VERSION 5.8 ;
BUSBITCHARS "[]" ;
DIVIDERCHAR "/" ;
UNITS
    DATABASE MICRONS 1000 ;
END UNITS

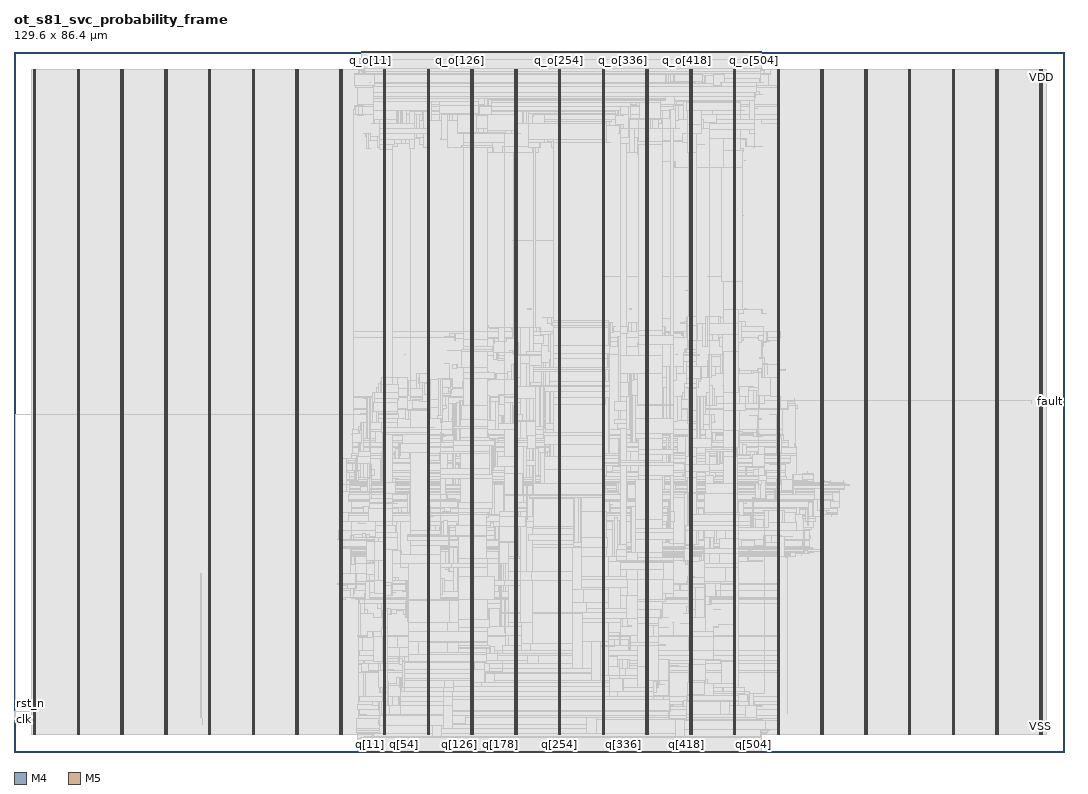
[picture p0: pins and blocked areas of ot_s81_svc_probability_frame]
MACRO ot_s81_svc_probability_frame
  FOREIGN ot_s81_svc_probability_frame 0 0 ;
  CLASS BLOCK ;
  SIZE 129.6 BY 86.4 ;
  PIN clk
    DIRECTION INPUT ;
    USE SIGNAL ;
    PORT
      LAYER M4 ;
        RECT  0 4.032 0.084 4.056 ;
    END
  END clk
  PIN fault
    DIRECTION OUTPUT ;
    USE SIGNAL ;
    PORT
      LAYER M4 ;
        RECT  129.516 43.2 129.6 43.224 ;
    END
    PORT
      LAYER M4 ;
        RECT  128.797 43.2 129.564 43.224 ;
    END
  END fault
  PIN q[0]
    DIRECTION INPUT ;
    USE SIGNAL ;
    PORT
      LAYER M5 ;
        RECT  42.912 0 42.936 0.084 ;
    END
  END q[0]
  PIN q[100]
    DIRECTION INPUT ;
    USE SIGNAL ;
    PORT
      LAYER M5 ;
        RECT  52.512 0 52.536 0.084 ;
    END
  END q[100]
  PIN q[101]
    DIRECTION INPUT ;
    USE SIGNAL ;
    PORT
      LAYER M5 ;
        RECT  52.608 0 52.632 0.084 ;
    END
  END q[101]
  PIN q[102]
    DIRECTION INPUT ;
    USE SIGNAL ;
    PORT
      LAYER M5 ;
        RECT  52.704 0 52.728 0.084 ;
    END
  END q[102]
  PIN q[103]
    DIRECTION INPUT ;
    USE SIGNAL ;
    PORT
      LAYER M5 ;
        RECT  52.8 0 52.824 0.084 ;
    END
  END q[103]
  PIN q[104]
    DIRECTION INPUT ;
    USE SIGNAL ;
    PORT
      LAYER M5 ;
        RECT  52.896 0 52.92 0.084 ;
    END
  END q[104]
  PIN q[105]
    DIRECTION INPUT ;
    USE SIGNAL ;
    PORT
      LAYER M5 ;
        RECT  52.992 0 53.016 0.084 ;
    END
  END q[105]
  PIN q[106]
    DIRECTION INPUT ;
    USE SIGNAL ;
    PORT
      LAYER M5 ;
        RECT  53.088 0 53.112 0.084 ;
    END
  END q[106]
  PIN q[107]
    DIRECTION INPUT ;
    USE SIGNAL ;
    PORT
      LAYER M5 ;
        RECT  53.184 0 53.208 0.084 ;
    END
  END q[107]
  PIN q[108]
    DIRECTION INPUT ;
    USE SIGNAL ;
    PORT
      LAYER M5 ;
        RECT  53.28 0 53.304 0.084 ;
    END
  END q[108]
  PIN q[109]
    DIRECTION INPUT ;
    USE SIGNAL ;
    PORT
      LAYER M5 ;
        RECT  53.376 0 53.4 0.084 ;
    END
  END q[109]
  PIN q[10]
    DIRECTION INPUT ;
    USE SIGNAL ;
    PORT
      LAYER M5 ;
        RECT  43.872 0 43.896 0.084 ;
    END
  END q[10]
  PIN q[110]
    DIRECTION INPUT ;
    USE SIGNAL ;
    PORT
      LAYER M5 ;
        RECT  53.472 0 53.496 0.084 ;
    END
  END q[110]
  PIN q[111]
    DIRECTION INPUT ;
    USE SIGNAL ;
    PORT
      LAYER M5 ;
        RECT  53.568 0 53.592 0.084 ;
    END
  END q[111]
  PIN q[112]
    DIRECTION INPUT ;
    USE SIGNAL ;
    PORT
      LAYER M5 ;
        RECT  53.664 0 53.688 0.084 ;
    END
  END q[112]
  PIN q[113]
    DIRECTION INPUT ;
    USE SIGNAL ;
    PORT
      LAYER M5 ;
        RECT  53.76 0 53.784 0.084 ;
    END
  END q[113]
  PIN q[114]
    DIRECTION INPUT ;
    USE SIGNAL ;
    PORT
      LAYER M5 ;
        RECT  53.856 0 53.88 0.084 ;
    END
  END q[114]
  PIN q[115]
    DIRECTION INPUT ;
    USE SIGNAL ;
    PORT
      LAYER M5 ;
        RECT  53.952 0 53.976 0.084 ;
    END
  END q[115]
  PIN q[116]
    DIRECTION INPUT ;
    USE SIGNAL ;
    PORT
      LAYER M5 ;
        RECT  54.048 0 54.072 0.084 ;
    END
  END q[116]
  PIN q[117]
    DIRECTION INPUT ;
    USE SIGNAL ;
    PORT
      LAYER M5 ;
        RECT  54.144 0 54.168 0.084 ;
    END
  END q[117]
  PIN q[118]
    DIRECTION INPUT ;
    USE SIGNAL ;
    PORT
      LAYER M5 ;
        RECT  54.24 0 54.264 0.084 ;
    END
  END q[118]
  PIN q[119]
    DIRECTION INPUT ;
    USE SIGNAL ;
    PORT
      LAYER M5 ;
        RECT  54.336 0 54.36 0.084 ;
    END
  END q[119]
  PIN q[11]
    DIRECTION INPUT ;
    USE SIGNAL ;
    PORT
      LAYER M5 ;
        RECT  43.968 0 43.992 0.084 ;
    END
  END q[11]
  PIN q[120]
    DIRECTION INPUT ;
    USE SIGNAL ;
    PORT
      LAYER M5 ;
        RECT  54.432 0 54.456 0.084 ;
    END
  END q[120]
  PIN q[121]
    DIRECTION INPUT ;
    USE SIGNAL ;
    PORT
      LAYER M5 ;
        RECT  54.528 0 54.552 0.084 ;
    END
  END q[121]
  PIN q[122]
    DIRECTION INPUT ;
    USE SIGNAL ;
    PORT
      LAYER M5 ;
        RECT  54.624 0 54.648 0.084 ;
    END
  END q[122]
  PIN q[123]
    DIRECTION INPUT ;
    USE SIGNAL ;
    PORT
      LAYER M5 ;
        RECT  54.72 0 54.744 0.084 ;
    END
  END q[123]
  PIN q[124]
    DIRECTION INPUT ;
    USE SIGNAL ;
    PORT
      LAYER M5 ;
        RECT  54.816 0 54.84 0.084 ;
    END
  END q[124]
  PIN q[125]
    DIRECTION INPUT ;
    USE SIGNAL ;
    PORT
      LAYER M5 ;
        RECT  54.912 0 54.936 0.084 ;
    END
  END q[125]
  PIN q[126]
    DIRECTION INPUT ;
    USE SIGNAL ;
    PORT
      LAYER M5 ;
        RECT  55.008 0 55.032 0.084 ;
    END
  END q[126]
  PIN q[127]
    DIRECTION INPUT ;
    USE SIGNAL ;
    PORT
      LAYER M5 ;
        RECT  55.104 0 55.128 0.084 ;
    END
  END q[127]
  PIN q[128]
    DIRECTION INPUT ;
    USE SIGNAL ;
    PORT
      LAYER M5 ;
        RECT  55.2 0 55.224 0.084 ;
    END
  END q[128]
  PIN q[129]
    DIRECTION INPUT ;
    USE SIGNAL ;
    PORT
      LAYER M5 ;
        RECT  55.296 0 55.32 0.084 ;
    END
  END q[129]
  PIN q[12]
    DIRECTION INPUT ;
    USE SIGNAL ;
    PORT
      LAYER M5 ;
        RECT  44.064 0 44.088 0.084 ;
    END
  END q[12]
  PIN q[130]
    DIRECTION INPUT ;
    USE SIGNAL ;
    PORT
      LAYER M5 ;
        RECT  55.392 0 55.416 0.084 ;
    END
  END q[130]
  PIN q[131]
    DIRECTION INPUT ;
    USE SIGNAL ;
    PORT
      LAYER M5 ;
        RECT  55.488 0 55.512 0.084 ;
    END
  END q[131]
  PIN q[132]
    DIRECTION INPUT ;
    USE SIGNAL ;
    PORT
      LAYER M5 ;
        RECT  55.584 0 55.608 0.084 ;
    END
  END q[132]
  PIN q[133]
    DIRECTION INPUT ;
    USE SIGNAL ;
    PORT
      LAYER M5 ;
        RECT  55.68 0 55.704 0.084 ;
    END
  END q[133]
  PIN q[134]
    DIRECTION INPUT ;
    USE SIGNAL ;
    PORT
      LAYER M5 ;
        RECT  55.776 0 55.8 0.084 ;
    END
  END q[134]
  PIN q[135]
    DIRECTION INPUT ;
    USE SIGNAL ;
    PORT
      LAYER M5 ;
        RECT  55.872 0 55.896 0.084 ;
    END
  END q[135]
  PIN q[136]
    DIRECTION INPUT ;
    USE SIGNAL ;
    PORT
      LAYER M5 ;
        RECT  55.968 0 55.992 0.084 ;
    END
  END q[136]
  PIN q[137]
    DIRECTION INPUT ;
    USE SIGNAL ;
    PORT
      LAYER M5 ;
        RECT  56.064 0 56.088 0.084 ;
    END
  END q[137]
  PIN q[138]
    DIRECTION INPUT ;
    USE SIGNAL ;
    PORT
      LAYER M5 ;
        RECT  56.16 0 56.184 0.084 ;
    END
  END q[138]
  PIN q[139]
    DIRECTION INPUT ;
    USE SIGNAL ;
    PORT
      LAYER M5 ;
        RECT  56.256 0 56.28 0.084 ;
    END
  END q[139]
  PIN q[13]
    DIRECTION INPUT ;
    USE SIGNAL ;
    PORT
      LAYER M5 ;
        RECT  44.16 0 44.184 0.084 ;
    END
  END q[13]
  PIN q[140]
    DIRECTION INPUT ;
    USE SIGNAL ;
    PORT
      LAYER M5 ;
        RECT  56.352 0 56.376 0.084 ;
    END
  END q[140]
  PIN q[141]
    DIRECTION INPUT ;
    USE SIGNAL ;
    PORT
      LAYER M5 ;
        RECT  56.448 0 56.472 0.084 ;
    END
  END q[141]
  PIN q[142]
    DIRECTION INPUT ;
    USE SIGNAL ;
    PORT
      LAYER M5 ;
        RECT  56.544 0 56.568 0.084 ;
    END
  END q[142]
  PIN q[143]
    DIRECTION INPUT ;
    USE SIGNAL ;
    PORT
      LAYER M5 ;
        RECT  56.64 0 56.664 0.084 ;
    END
  END q[143]
  PIN q[144]
    DIRECTION INPUT ;
    USE SIGNAL ;
    PORT
      LAYER M5 ;
        RECT  56.736 0 56.76 0.084 ;
    END
  END q[144]
  PIN q[145]
    DIRECTION INPUT ;
    USE SIGNAL ;
    PORT
      LAYER M5 ;
        RECT  56.832 0 56.856 0.084 ;
    END
  END q[145]
  PIN q[146]
    DIRECTION INPUT ;
    USE SIGNAL ;
    PORT
      LAYER M5 ;
        RECT  56.928 0 56.952 0.084 ;
    END
  END q[146]
  PIN q[147]
    DIRECTION INPUT ;
    USE SIGNAL ;
    PORT
      LAYER M5 ;
        RECT  57.024 0 57.048 0.084 ;
    END
  END q[147]
  PIN q[148]
    DIRECTION INPUT ;
    USE SIGNAL ;
    PORT
      LAYER M5 ;
        RECT  57.12 0 57.144 0.084 ;
    END
  END q[148]
  PIN q[149]
    DIRECTION INPUT ;
    USE SIGNAL ;
    PORT
      LAYER M5 ;
        RECT  57.216 0 57.24 0.084 ;
    END
  END q[149]
  PIN q[14]
    DIRECTION INPUT ;
    USE SIGNAL ;
    PORT
      LAYER M5 ;
        RECT  44.256 0 44.28 0.084 ;
    END
  END q[14]
  PIN q[150]
    DIRECTION INPUT ;
    USE SIGNAL ;
    PORT
      LAYER M5 ;
        RECT  57.312 0 57.336 0.084 ;
    END
  END q[150]
  PIN q[151]
    DIRECTION INPUT ;
    USE SIGNAL ;
    PORT
      LAYER M5 ;
        RECT  57.408 0 57.432 0.084 ;
    END
  END q[151]
  PIN q[152]
    DIRECTION INPUT ;
    USE SIGNAL ;
    PORT
      LAYER M5 ;
        RECT  57.504 0 57.528 0.084 ;
    END
  END q[152]
  PIN q[153]
    DIRECTION INPUT ;
    USE SIGNAL ;
    PORT
      LAYER M5 ;
        RECT  57.6 0 57.624 0.084 ;
    END
  END q[153]
  PIN q[154]
    DIRECTION INPUT ;
    USE SIGNAL ;
    PORT
      LAYER M5 ;
        RECT  57.696 0 57.72 0.084 ;
    END
  END q[154]
  PIN q[155]
    DIRECTION INPUT ;
    USE SIGNAL ;
    PORT
      LAYER M5 ;
        RECT  57.792 0 57.816 0.084 ;
    END
  END q[155]
  PIN q[156]
    DIRECTION INPUT ;
    USE SIGNAL ;
    PORT
      LAYER M5 ;
        RECT  57.888 0 57.912 0.084 ;
    END
  END q[156]
  PIN q[157]
    DIRECTION INPUT ;
    USE SIGNAL ;
    PORT
      LAYER M5 ;
        RECT  57.984 0 58.008 0.084 ;
    END
  END q[157]
  PIN q[158]
    DIRECTION INPUT ;
    USE SIGNAL ;
    PORT
      LAYER M5 ;
        RECT  58.08 0 58.104 0.084 ;
    END
  END q[158]
  PIN q[159]
    DIRECTION INPUT ;
    USE SIGNAL ;
    PORT
      LAYER M5 ;
        RECT  58.176 0 58.2 0.084 ;
    END
  END q[159]
  PIN q[15]
    DIRECTION INPUT ;
    USE SIGNAL ;
    PORT
      LAYER M5 ;
        RECT  44.352 0 44.376 0.084 ;
    END
  END q[15]
  PIN q[160]
    DIRECTION INPUT ;
    USE SIGNAL ;
    PORT
      LAYER M5 ;
        RECT  58.272 0 58.296 0.084 ;
    END
  END q[160]
  PIN q[161]
    DIRECTION INPUT ;
    USE SIGNAL ;
    PORT
      LAYER M5 ;
        RECT  58.368 0 58.392 0.084 ;
    END
  END q[161]
  PIN q[162]
    DIRECTION INPUT ;
    USE SIGNAL ;
    PORT
      LAYER M5 ;
        RECT  58.464 0 58.488 0.084 ;
    END
  END q[162]
  PIN q[163]
    DIRECTION INPUT ;
    USE SIGNAL ;
    PORT
      LAYER M5 ;
        RECT  58.56 0 58.584 0.084 ;
    END
  END q[163]
  PIN q[164]
    DIRECTION INPUT ;
    USE SIGNAL ;
    PORT
      LAYER M5 ;
        RECT  58.656 0 58.68 0.084 ;
    END
  END q[164]
  PIN q[165]
    DIRECTION INPUT ;
    USE SIGNAL ;
    PORT
      LAYER M5 ;
        RECT  58.752 0 58.776 0.084 ;
    END
  END q[165]
  PIN q[166]
    DIRECTION INPUT ;
    USE SIGNAL ;
    PORT
      LAYER M5 ;
        RECT  58.848 0 58.872 0.084 ;
    END
  END q[166]
  PIN q[167]
    DIRECTION INPUT ;
    USE SIGNAL ;
    PORT
      LAYER M5 ;
        RECT  58.944 0 58.968 0.084 ;
    END
  END q[167]
  PIN q[168]
    DIRECTION INPUT ;
    USE SIGNAL ;
    PORT
      LAYER M5 ;
        RECT  59.04 0 59.064 0.084 ;
    END
  END q[168]
  PIN q[169]
    DIRECTION INPUT ;
    USE SIGNAL ;
    PORT
      LAYER M5 ;
        RECT  59.136 0 59.16 0.084 ;
    END
  END q[169]
  PIN q[16]
    DIRECTION INPUT ;
    USE SIGNAL ;
    PORT
      LAYER M5 ;
        RECT  44.448 0 44.472 0.084 ;
    END
  END q[16]
  PIN q[170]
    DIRECTION INPUT ;
    USE SIGNAL ;
    PORT
      LAYER M5 ;
        RECT  59.232 0 59.256 0.084 ;
    END
  END q[170]
  PIN q[171]
    DIRECTION INPUT ;
    USE SIGNAL ;
    PORT
      LAYER M5 ;
        RECT  59.328 0 59.352 0.084 ;
    END
  END q[171]
  PIN q[172]
    DIRECTION INPUT ;
    USE SIGNAL ;
    PORT
      LAYER M5 ;
        RECT  59.424 0 59.448 0.084 ;
    END
  END q[172]
  PIN q[173]
    DIRECTION INPUT ;
    USE SIGNAL ;
    PORT
      LAYER M5 ;
        RECT  59.52 0 59.544 0.084 ;
    END
  END q[173]
  PIN q[174]
    DIRECTION INPUT ;
    USE SIGNAL ;
    PORT
      LAYER M5 ;
        RECT  59.616 0 59.64 0.084 ;
    END
  END q[174]
  PIN q[175]
    DIRECTION INPUT ;
    USE SIGNAL ;
    PORT
      LAYER M5 ;
        RECT  59.712 0 59.736 0.084 ;
    END
  END q[175]
  PIN q[176]
    DIRECTION INPUT ;
    USE SIGNAL ;
    PORT
      LAYER M5 ;
        RECT  59.808 0 59.832 0.084 ;
    END
  END q[176]
  PIN q[177]
    DIRECTION INPUT ;
    USE SIGNAL ;
    PORT
      LAYER M5 ;
        RECT  59.904 0 59.928 0.084 ;
    END
  END q[177]
  PIN q[178]
    DIRECTION INPUT ;
    USE SIGNAL ;
    PORT
      LAYER M5 ;
        RECT  60 0 60.024 0.084 ;
    END
  END q[178]
  PIN q[179]
    DIRECTION INPUT ;
    USE SIGNAL ;
    PORT
      LAYER M5 ;
        RECT  60.096 0 60.12 0.084 ;
    END
  END q[179]
  PIN q[17]
    DIRECTION INPUT ;
    USE SIGNAL ;
    PORT
      LAYER M5 ;
        RECT  44.544 0 44.568 0.084 ;
    END
  END q[17]
  PIN q[180]
    DIRECTION INPUT ;
    USE SIGNAL ;
    PORT
      LAYER M5 ;
        RECT  60.192 0 60.216 0.084 ;
    END
  END q[180]
  PIN q[181]
    DIRECTION INPUT ;
    USE SIGNAL ;
    PORT
      LAYER M5 ;
        RECT  60.288 0 60.312 0.084 ;
    END
  END q[181]
  PIN q[182]
    DIRECTION INPUT ;
    USE SIGNAL ;
    PORT
      LAYER M5 ;
        RECT  60.384 0 60.408 0.084 ;
    END
  END q[182]
  PIN q[183]
    DIRECTION INPUT ;
    USE SIGNAL ;
    PORT
      LAYER M5 ;
        RECT  60.48 0 60.504 0.084 ;
    END
  END q[183]
  PIN q[184]
    DIRECTION INPUT ;
    USE SIGNAL ;
    PORT
      LAYER M5 ;
        RECT  60.576 0 60.6 0.084 ;
    END
  END q[184]
  PIN q[185]
    DIRECTION INPUT ;
    USE SIGNAL ;
    PORT
      LAYER M5 ;
        RECT  60.672 0 60.696 0.084 ;
    END
  END q[185]
  PIN q[186]
    DIRECTION INPUT ;
    USE SIGNAL ;
    PORT
      LAYER M5 ;
        RECT  60.768 0 60.792 0.084 ;
    END
  END q[186]
  PIN q[187]
    DIRECTION INPUT ;
    USE SIGNAL ;
    PORT
      LAYER M5 ;
        RECT  60.864 0 60.888 0.084 ;
    END
  END q[187]
  PIN q[188]
    DIRECTION INPUT ;
    USE SIGNAL ;
    PORT
      LAYER M5 ;
        RECT  60.96 0 60.984 0.084 ;
    END
  END q[188]
  PIN q[189]
    DIRECTION INPUT ;
    USE SIGNAL ;
    PORT
      LAYER M5 ;
        RECT  61.056 0 61.08 0.084 ;
    END
  END q[189]
  PIN q[18]
    DIRECTION INPUT ;
    USE SIGNAL ;
    PORT
      LAYER M5 ;
        RECT  44.64 0 44.664 0.084 ;
    END
  END q[18]
  PIN q[190]
    DIRECTION INPUT ;
    USE SIGNAL ;
    PORT
      LAYER M5 ;
        RECT  61.152 0 61.176 0.084 ;
    END
  END q[190]
  PIN q[191]
    DIRECTION INPUT ;
    USE SIGNAL ;
    PORT
      LAYER M5 ;
        RECT  61.248 0 61.272 0.084 ;
    END
  END q[191]
  PIN q[192]
    DIRECTION INPUT ;
    USE SIGNAL ;
    PORT
      LAYER M5 ;
        RECT  61.344 0 61.368 0.084 ;
    END
  END q[192]
  PIN q[193]
    DIRECTION INPUT ;
    USE SIGNAL ;
    PORT
      LAYER M5 ;
        RECT  61.44 0 61.464 0.084 ;
    END
  END q[193]
  PIN q[194]
    DIRECTION INPUT ;
    USE SIGNAL ;
    PORT
      LAYER M5 ;
        RECT  61.536 0 61.56 0.084 ;
    END
  END q[194]
  PIN q[195]
    DIRECTION INPUT ;
    USE SIGNAL ;
    PORT
      LAYER M5 ;
        RECT  61.632 0 61.656 0.084 ;
    END
  END q[195]
  PIN q[196]
    DIRECTION INPUT ;
    USE SIGNAL ;
    PORT
      LAYER M5 ;
        RECT  61.728 0 61.752 0.084 ;
    END
  END q[196]
  PIN q[197]
    DIRECTION INPUT ;
    USE SIGNAL ;
    PORT
      LAYER M5 ;
        RECT  61.824 0 61.848 0.084 ;
    END
  END q[197]
  PIN q[198]
    DIRECTION INPUT ;
    USE SIGNAL ;
    PORT
      LAYER M5 ;
        RECT  61.92 0 61.944 0.084 ;
    END
  END q[198]
  PIN q[199]
    DIRECTION INPUT ;
    USE SIGNAL ;
    PORT
      LAYER M5 ;
        RECT  62.016 0 62.04 0.084 ;
    END
  END q[199]
  PIN q[19]
    DIRECTION INPUT ;
    USE SIGNAL ;
    PORT
      LAYER M5 ;
        RECT  44.736 0 44.76 0.084 ;
    END
  END q[19]
  PIN q[1]
    DIRECTION INPUT ;
    USE SIGNAL ;
    PORT
      LAYER M5 ;
        RECT  43.008 0 43.032 0.084 ;
    END
  END q[1]
  PIN q[200]
    DIRECTION INPUT ;
    USE SIGNAL ;
    PORT
      LAYER M5 ;
        RECT  62.112 0 62.136 0.084 ;
    END
  END q[200]
  PIN q[201]
    DIRECTION INPUT ;
    USE SIGNAL ;
    PORT
      LAYER M5 ;
        RECT  62.208 0 62.232 0.084 ;
    END
  END q[201]
  PIN q[202]
    DIRECTION INPUT ;
    USE SIGNAL ;
    PORT
      LAYER M5 ;
        RECT  62.304 0 62.328 0.084 ;
    END
  END q[202]
  PIN q[203]
    DIRECTION INPUT ;
    USE SIGNAL ;
    PORT
      LAYER M5 ;
        RECT  62.4 0 62.424 0.084 ;
    END
  END q[203]
  PIN q[204]
    DIRECTION INPUT ;
    USE SIGNAL ;
    PORT
      LAYER M5 ;
        RECT  62.496 0 62.52 0.084 ;
    END
  END q[204]
  PIN q[205]
    DIRECTION INPUT ;
    USE SIGNAL ;
    PORT
      LAYER M5 ;
        RECT  62.592 0 62.616 0.084 ;
    END
  END q[205]
  PIN q[206]
    DIRECTION INPUT ;
    USE SIGNAL ;
    PORT
      LAYER M5 ;
        RECT  62.688 0 62.712 0.084 ;
    END
  END q[206]
  PIN q[207]
    DIRECTION INPUT ;
    USE SIGNAL ;
    PORT
      LAYER M5 ;
        RECT  62.784 0 62.808 0.084 ;
    END
  END q[207]
  PIN q[208]
    DIRECTION INPUT ;
    USE SIGNAL ;
    PORT
      LAYER M5 ;
        RECT  62.88 0 62.904 0.084 ;
    END
  END q[208]
  PIN q[209]
    DIRECTION INPUT ;
    USE SIGNAL ;
    PORT
      LAYER M5 ;
        RECT  62.976 0 63 0.084 ;
    END
  END q[209]
  PIN q[20]
    DIRECTION INPUT ;
    USE SIGNAL ;
    PORT
      LAYER M5 ;
        RECT  44.832 0 44.856 0.084 ;
    END
  END q[20]
  PIN q[210]
    DIRECTION INPUT ;
    USE SIGNAL ;
    PORT
      LAYER M5 ;
        RECT  63.072 0 63.096 0.084 ;
    END
  END q[210]
  PIN q[211]
    DIRECTION INPUT ;
    USE SIGNAL ;
    PORT
      LAYER M5 ;
        RECT  63.168 0 63.192 0.084 ;
    END
  END q[211]
  PIN q[212]
    DIRECTION INPUT ;
    USE SIGNAL ;
    PORT
      LAYER M5 ;
        RECT  63.264 0 63.288 0.084 ;
    END
  END q[212]
  PIN q[213]
    DIRECTION INPUT ;
    USE SIGNAL ;
    PORT
      LAYER M5 ;
        RECT  63.36 0 63.384 0.084 ;
    END
  END q[213]
  PIN q[214]
    DIRECTION INPUT ;
    USE SIGNAL ;
    PORT
      LAYER M5 ;
        RECT  63.456 0 63.48 0.084 ;
    END
  END q[214]
  PIN q[215]
    DIRECTION INPUT ;
    USE SIGNAL ;
    PORT
      LAYER M5 ;
        RECT  63.552 0 63.576 0.084 ;
    END
  END q[215]
  PIN q[216]
    DIRECTION INPUT ;
    USE SIGNAL ;
    PORT
      LAYER M5 ;
        RECT  63.648 0 63.672 0.084 ;
    END
  END q[216]
  PIN q[217]
    DIRECTION INPUT ;
    USE SIGNAL ;
    PORT
      LAYER M5 ;
        RECT  63.744 0 63.768 0.084 ;
    END
  END q[217]
  PIN q[218]
    DIRECTION INPUT ;
    USE SIGNAL ;
    PORT
      LAYER M5 ;
        RECT  63.84 0 63.864 0.084 ;
    END
  END q[218]
  PIN q[219]
    DIRECTION INPUT ;
    USE SIGNAL ;
    PORT
      LAYER M5 ;
        RECT  63.936 0 63.96 0.084 ;
    END
  END q[219]
  PIN q[21]
    DIRECTION INPUT ;
    USE SIGNAL ;
    PORT
      LAYER M5 ;
        RECT  44.928 0 44.952 0.084 ;
    END
  END q[21]
  PIN q[220]
    DIRECTION INPUT ;
    USE SIGNAL ;
    PORT
      LAYER M5 ;
        RECT  64.032 0 64.056 0.084 ;
    END
  END q[220]
  PIN q[221]
    DIRECTION INPUT ;
    USE SIGNAL ;
    PORT
      LAYER M5 ;
        RECT  64.128 0 64.152 0.084 ;
    END
  END q[221]
  PIN q[222]
    DIRECTION INPUT ;
    USE SIGNAL ;
    PORT
      LAYER M5 ;
        RECT  64.224 0 64.248 0.084 ;
    END
  END q[222]
  PIN q[223]
    DIRECTION INPUT ;
    USE SIGNAL ;
    PORT
      LAYER M5 ;
        RECT  64.32 0 64.344 0.084 ;
    END
  END q[223]
  PIN q[224]
    DIRECTION INPUT ;
    USE SIGNAL ;
    PORT
      LAYER M5 ;
        RECT  64.416 0 64.44 0.084 ;
    END
  END q[224]
  PIN q[225]
    DIRECTION INPUT ;
    USE SIGNAL ;
    PORT
      LAYER M5 ;
        RECT  64.512 0 64.536 0.084 ;
    END
  END q[225]
  PIN q[226]
    DIRECTION INPUT ;
    USE SIGNAL ;
    PORT
      LAYER M5 ;
        RECT  64.608 0 64.632 0.084 ;
    END
  END q[226]
  PIN q[227]
    DIRECTION INPUT ;
    USE SIGNAL ;
    PORT
      LAYER M5 ;
        RECT  64.704 0 64.728 0.084 ;
    END
  END q[227]
  PIN q[228]
    DIRECTION INPUT ;
    USE SIGNAL ;
    PORT
      LAYER M5 ;
        RECT  64.8 0 64.824 0.084 ;
    END
  END q[228]
  PIN q[229]
    DIRECTION INPUT ;
    USE SIGNAL ;
    PORT
      LAYER M5 ;
        RECT  64.896 0 64.92 0.084 ;
    END
  END q[229]
  PIN q[22]
    DIRECTION INPUT ;
    USE SIGNAL ;
    PORT
      LAYER M5 ;
        RECT  45.024 0 45.048 0.084 ;
    END
  END q[22]
  PIN q[230]
    DIRECTION INPUT ;
    USE SIGNAL ;
    PORT
      LAYER M5 ;
        RECT  64.992 0 65.016 0.084 ;
    END
  END q[230]
  PIN q[231]
    DIRECTION INPUT ;
    USE SIGNAL ;
    PORT
      LAYER M5 ;
        RECT  65.088 0 65.112 0.084 ;
    END
  END q[231]
  PIN q[232]
    DIRECTION INPUT ;
    USE SIGNAL ;
    PORT
      LAYER M5 ;
        RECT  65.184 0 65.208 0.084 ;
    END
  END q[232]
  PIN q[233]
    DIRECTION INPUT ;
    USE SIGNAL ;
    PORT
      LAYER M5 ;
        RECT  65.28 0 65.304 0.084 ;
    END
  END q[233]
  PIN q[234]
    DIRECTION INPUT ;
    USE SIGNAL ;
    PORT
      LAYER M5 ;
        RECT  65.376 0 65.4 0.084 ;
    END
  END q[234]
  PIN q[235]
    DIRECTION INPUT ;
    USE SIGNAL ;
    PORT
      LAYER M5 ;
        RECT  65.472 0 65.496 0.084 ;
    END
  END q[235]
  PIN q[236]
    DIRECTION INPUT ;
    USE SIGNAL ;
    PORT
      LAYER M5 ;
        RECT  65.568 0 65.592 0.084 ;
    END
  END q[236]
  PIN q[237]
    DIRECTION INPUT ;
    USE SIGNAL ;
    PORT
      LAYER M5 ;
        RECT  65.664 0 65.688 0.084 ;
    END
  END q[237]
  PIN q[238]
    DIRECTION INPUT ;
    USE SIGNAL ;
    PORT
      LAYER M5 ;
        RECT  65.76 0 65.784 0.084 ;
    END
  END q[238]
  PIN q[239]
    DIRECTION INPUT ;
    USE SIGNAL ;
    PORT
      LAYER M5 ;
        RECT  65.856 0 65.88 0.084 ;
    END
  END q[239]
  PIN q[23]
    DIRECTION INPUT ;
    USE SIGNAL ;
    PORT
      LAYER M5 ;
        RECT  45.12 0 45.144 0.084 ;
    END
  END q[23]
  PIN q[240]
    DIRECTION INPUT ;
    USE SIGNAL ;
    PORT
      LAYER M5 ;
        RECT  65.952 0 65.976 0.084 ;
    END
  END q[240]
  PIN q[241]
    DIRECTION INPUT ;
    USE SIGNAL ;
    PORT
      LAYER M5 ;
        RECT  66.048 0 66.072 0.084 ;
    END
  END q[241]
  PIN q[242]
    DIRECTION INPUT ;
    USE SIGNAL ;
    PORT
      LAYER M5 ;
        RECT  66.144 0 66.168 0.084 ;
    END
  END q[242]
  PIN q[243]
    DIRECTION INPUT ;
    USE SIGNAL ;
    PORT
      LAYER M5 ;
        RECT  66.24 0 66.264 0.084 ;
    END
  END q[243]
  PIN q[244]
    DIRECTION INPUT ;
    USE SIGNAL ;
    PORT
      LAYER M5 ;
        RECT  66.336 0 66.36 0.084 ;
    END
  END q[244]
  PIN q[245]
    DIRECTION INPUT ;
    USE SIGNAL ;
    PORT
      LAYER M5 ;
        RECT  66.432 0 66.456 0.084 ;
    END
  END q[245]
  PIN q[246]
    DIRECTION INPUT ;
    USE SIGNAL ;
    PORT
      LAYER M5 ;
        RECT  66.528 0 66.552 0.084 ;
    END
  END q[246]
  PIN q[247]
    DIRECTION INPUT ;
    USE SIGNAL ;
    PORT
      LAYER M5 ;
        RECT  66.624 0 66.648 0.084 ;
    END
  END q[247]
  PIN q[248]
    DIRECTION INPUT ;
    USE SIGNAL ;
    PORT
      LAYER M5 ;
        RECT  66.72 0 66.744 0.084 ;
    END
  END q[248]
  PIN q[249]
    DIRECTION INPUT ;
    USE SIGNAL ;
    PORT
      LAYER M5 ;
        RECT  66.816 0 66.84 0.084 ;
    END
  END q[249]
  PIN q[24]
    DIRECTION INPUT ;
    USE SIGNAL ;
    PORT
      LAYER M5 ;
        RECT  45.216 0 45.24 0.084 ;
    END
  END q[24]
  PIN q[250]
    DIRECTION INPUT ;
    USE SIGNAL ;
    PORT
      LAYER M5 ;
        RECT  66.912 0 66.936 0.084 ;
    END
  END q[250]
  PIN q[251]
    DIRECTION INPUT ;
    USE SIGNAL ;
    PORT
      LAYER M5 ;
        RECT  67.008 0 67.032 0.084 ;
    END
  END q[251]
  PIN q[252]
    DIRECTION INPUT ;
    USE SIGNAL ;
    PORT
      LAYER M5 ;
        RECT  67.104 0 67.128 0.084 ;
    END
  END q[252]
  PIN q[253]
    DIRECTION INPUT ;
    USE SIGNAL ;
    PORT
      LAYER M5 ;
        RECT  67.2 0 67.224 0.084 ;
    END
  END q[253]
  PIN q[254]
    DIRECTION INPUT ;
    USE SIGNAL ;
    PORT
      LAYER M5 ;
        RECT  67.296 0 67.32 0.084 ;
    END
  END q[254]
  PIN q[255]
    DIRECTION INPUT ;
    USE SIGNAL ;
    PORT
      LAYER M5 ;
        RECT  67.392 0 67.416 0.084 ;
    END
  END q[255]
  PIN q[256]
    DIRECTION INPUT ;
    USE SIGNAL ;
    PORT
      LAYER M5 ;
        RECT  67.488 0 67.512 0.084 ;
    END
  END q[256]
  PIN q[257]
    DIRECTION INPUT ;
    USE SIGNAL ;
    PORT
      LAYER M5 ;
        RECT  67.584 0 67.608 0.084 ;
    END
  END q[257]
  PIN q[258]
    DIRECTION INPUT ;
    USE SIGNAL ;
    PORT
      LAYER M5 ;
        RECT  67.68 0 67.704 0.084 ;
    END
  END q[258]
  PIN q[259]
    DIRECTION INPUT ;
    USE SIGNAL ;
    PORT
      LAYER M5 ;
        RECT  67.776 0 67.8 0.084 ;
    END
  END q[259]
  PIN q[25]
    DIRECTION INPUT ;
    USE SIGNAL ;
    PORT
      LAYER M5 ;
        RECT  45.312 0 45.336 0.084 ;
    END
  END q[25]
  PIN q[260]
    DIRECTION INPUT ;
    USE SIGNAL ;
    PORT
      LAYER M5 ;
        RECT  67.872 0 67.896 0.084 ;
    END
  END q[260]
  PIN q[261]
    DIRECTION INPUT ;
    USE SIGNAL ;
    PORT
      LAYER M5 ;
        RECT  67.968 0 67.992 0.084 ;
    END
  END q[261]
  PIN q[262]
    DIRECTION INPUT ;
    USE SIGNAL ;
    PORT
      LAYER M5 ;
        RECT  68.064 0 68.088 0.084 ;
    END
  END q[262]
  PIN q[263]
    DIRECTION INPUT ;
    USE SIGNAL ;
    PORT
      LAYER M5 ;
        RECT  68.16 0 68.184 0.084 ;
    END
  END q[263]
  PIN q[264]
    DIRECTION INPUT ;
    USE SIGNAL ;
    PORT
      LAYER M5 ;
        RECT  68.256 0 68.28 0.084 ;
    END
  END q[264]
  PIN q[265]
    DIRECTION INPUT ;
    USE SIGNAL ;
    PORT
      LAYER M5 ;
        RECT  68.352 0 68.376 0.084 ;
    END
  END q[265]
  PIN q[266]
    DIRECTION INPUT ;
    USE SIGNAL ;
    PORT
      LAYER M5 ;
        RECT  68.448 0 68.472 0.084 ;
    END
  END q[266]
  PIN q[267]
    DIRECTION INPUT ;
    USE SIGNAL ;
    PORT
      LAYER M5 ;
        RECT  68.544 0 68.568 0.084 ;
    END
  END q[267]
  PIN q[268]
    DIRECTION INPUT ;
    USE SIGNAL ;
    PORT
      LAYER M5 ;
        RECT  68.64 0 68.664 0.084 ;
    END
  END q[268]
  PIN q[269]
    DIRECTION INPUT ;
    USE SIGNAL ;
    PORT
      LAYER M5 ;
        RECT  68.736 0 68.76 0.084 ;
    END
  END q[269]
  PIN q[26]
    DIRECTION INPUT ;
    USE SIGNAL ;
    PORT
      LAYER M5 ;
        RECT  45.408 0 45.432 0.084 ;
    END
  END q[26]
  PIN q[270]
    DIRECTION INPUT ;
    USE SIGNAL ;
    PORT
      LAYER M5 ;
        RECT  68.832 0 68.856 0.084 ;
    END
  END q[270]
  PIN q[271]
    DIRECTION INPUT ;
    USE SIGNAL ;
    PORT
      LAYER M5 ;
        RECT  68.928 0 68.952 0.084 ;
    END
  END q[271]
  PIN q[272]
    DIRECTION INPUT ;
    USE SIGNAL ;
    PORT
      LAYER M5 ;
        RECT  69.024 0 69.048 0.084 ;
    END
  END q[272]
  PIN q[273]
    DIRECTION INPUT ;
    USE SIGNAL ;
    PORT
      LAYER M5 ;
        RECT  69.12 0 69.144 0.084 ;
    END
  END q[273]
  PIN q[274]
    DIRECTION INPUT ;
    USE SIGNAL ;
    PORT
      LAYER M5 ;
        RECT  69.216 0 69.24 0.084 ;
    END
  END q[274]
  PIN q[275]
    DIRECTION INPUT ;
    USE SIGNAL ;
    PORT
      LAYER M5 ;
        RECT  69.312 0 69.336 0.084 ;
    END
  END q[275]
  PIN q[276]
    DIRECTION INPUT ;
    USE SIGNAL ;
    PORT
      LAYER M5 ;
        RECT  69.408 0 69.432 0.084 ;
    END
  END q[276]
  PIN q[277]
    DIRECTION INPUT ;
    USE SIGNAL ;
    PORT
      LAYER M5 ;
        RECT  69.504 0 69.528 0.084 ;
    END
  END q[277]
  PIN q[278]
    DIRECTION INPUT ;
    USE SIGNAL ;
    PORT
      LAYER M5 ;
        RECT  69.6 0 69.624 0.084 ;
    END
  END q[278]
  PIN q[279]
    DIRECTION INPUT ;
    USE SIGNAL ;
    PORT
      LAYER M5 ;
        RECT  69.696 0 69.72 0.084 ;
    END
  END q[279]
  PIN q[27]
    DIRECTION INPUT ;
    USE SIGNAL ;
    PORT
      LAYER M5 ;
        RECT  45.504 0 45.528 0.084 ;
    END
  END q[27]
  PIN q[280]
    DIRECTION INPUT ;
    USE SIGNAL ;
    PORT
      LAYER M5 ;
        RECT  69.792 0 69.816 0.084 ;
    END
  END q[280]
  PIN q[281]
    DIRECTION INPUT ;
    USE SIGNAL ;
    PORT
      LAYER M5 ;
        RECT  69.888 0 69.912 0.084 ;
    END
  END q[281]
  PIN q[282]
    DIRECTION INPUT ;
    USE SIGNAL ;
    PORT
      LAYER M5 ;
        RECT  69.984 0 70.008 0.084 ;
    END
  END q[282]
  PIN q[283]
    DIRECTION INPUT ;
    USE SIGNAL ;
    PORT
      LAYER M5 ;
        RECT  70.08 0 70.104 0.084 ;
    END
  END q[283]
  PIN q[284]
    DIRECTION INPUT ;
    USE SIGNAL ;
    PORT
      LAYER M5 ;
        RECT  70.176 0 70.2 0.084 ;
    END
  END q[284]
  PIN q[285]
    DIRECTION INPUT ;
    USE SIGNAL ;
    PORT
      LAYER M5 ;
        RECT  70.272 0 70.296 0.084 ;
    END
  END q[285]
  PIN q[286]
    DIRECTION INPUT ;
    USE SIGNAL ;
    PORT
      LAYER M5 ;
        RECT  70.368 0 70.392 0.084 ;
    END
  END q[286]
  PIN q[287]
    DIRECTION INPUT ;
    USE SIGNAL ;
    PORT
      LAYER M5 ;
        RECT  70.464 0 70.488 0.084 ;
    END
  END q[287]
  PIN q[288]
    DIRECTION INPUT ;
    USE SIGNAL ;
    PORT
      LAYER M5 ;
        RECT  70.56 0 70.584 0.084 ;
    END
  END q[288]
  PIN q[289]
    DIRECTION INPUT ;
    USE SIGNAL ;
    PORT
      LAYER M5 ;
        RECT  70.656 0 70.68 0.084 ;
    END
  END q[289]
  PIN q[28]
    DIRECTION INPUT ;
    USE SIGNAL ;
    PORT
      LAYER M5 ;
        RECT  45.6 0 45.624 0.084 ;
    END
  END q[28]
  PIN q[290]
    DIRECTION INPUT ;
    USE SIGNAL ;
    PORT
      LAYER M5 ;
        RECT  70.752 0 70.776 0.084 ;
    END
  END q[290]
  PIN q[291]
    DIRECTION INPUT ;
    USE SIGNAL ;
    PORT
      LAYER M5 ;
        RECT  70.848 0 70.872 0.084 ;
    END
  END q[291]
  PIN q[292]
    DIRECTION INPUT ;
    USE SIGNAL ;
    PORT
      LAYER M5 ;
        RECT  70.944 0 70.968 0.084 ;
    END
  END q[292]
  PIN q[293]
    DIRECTION INPUT ;
    USE SIGNAL ;
    PORT
      LAYER M5 ;
        RECT  71.04 0 71.064 0.084 ;
    END
  END q[293]
  PIN q[294]
    DIRECTION INPUT ;
    USE SIGNAL ;
    PORT
      LAYER M5 ;
        RECT  71.136 0 71.16 0.084 ;
    END
  END q[294]
  PIN q[295]
    DIRECTION INPUT ;
    USE SIGNAL ;
    PORT
      LAYER M5 ;
        RECT  71.232 0 71.256 0.084 ;
    END
  END q[295]
  PIN q[296]
    DIRECTION INPUT ;
    USE SIGNAL ;
    PORT
      LAYER M5 ;
        RECT  71.328 0 71.352 0.084 ;
    END
  END q[296]
  PIN q[297]
    DIRECTION INPUT ;
    USE SIGNAL ;
    PORT
      LAYER M5 ;
        RECT  71.424 0 71.448 0.084 ;
    END
  END q[297]
  PIN q[298]
    DIRECTION INPUT ;
    USE SIGNAL ;
    PORT
      LAYER M5 ;
        RECT  71.52 0 71.544 0.084 ;
    END
  END q[298]
  PIN q[299]
    DIRECTION INPUT ;
    USE SIGNAL ;
    PORT
      LAYER M5 ;
        RECT  71.616 0 71.64 0.084 ;
    END
  END q[299]
  PIN q[29]
    DIRECTION INPUT ;
    USE SIGNAL ;
    PORT
      LAYER M5 ;
        RECT  45.696 0 45.72 0.084 ;
    END
  END q[29]
  PIN q[2]
    DIRECTION INPUT ;
    USE SIGNAL ;
    PORT
      LAYER M5 ;
        RECT  43.104 0 43.128 0.084 ;
    END
  END q[2]
  PIN q[300]
    DIRECTION INPUT ;
    USE SIGNAL ;
    PORT
      LAYER M5 ;
        RECT  71.712 0 71.736 0.084 ;
    END
  END q[300]
  PIN q[301]
    DIRECTION INPUT ;
    USE SIGNAL ;
    PORT
      LAYER M5 ;
        RECT  71.808 0 71.832 0.084 ;
    END
  END q[301]
  PIN q[302]
    DIRECTION INPUT ;
    USE SIGNAL ;
    PORT
      LAYER M5 ;
        RECT  71.904 0 71.928 0.084 ;
    END
  END q[302]
  PIN q[303]
    DIRECTION INPUT ;
    USE SIGNAL ;
    PORT
      LAYER M5 ;
        RECT  72 0 72.024 0.084 ;
    END
  END q[303]
  PIN q[304]
    DIRECTION INPUT ;
    USE SIGNAL ;
    PORT
      LAYER M5 ;
        RECT  72.096 0 72.12 0.084 ;
    END
  END q[304]
  PIN q[305]
    DIRECTION INPUT ;
    USE SIGNAL ;
    PORT
      LAYER M5 ;
        RECT  72.192 0 72.216 0.084 ;
    END
  END q[305]
  PIN q[306]
    DIRECTION INPUT ;
    USE SIGNAL ;
    PORT
      LAYER M5 ;
        RECT  72.288 0 72.312 0.084 ;
    END
  END q[306]
  PIN q[307]
    DIRECTION INPUT ;
    USE SIGNAL ;
    PORT
      LAYER M5 ;
        RECT  72.384 0 72.408 0.084 ;
    END
  END q[307]
  PIN q[308]
    DIRECTION INPUT ;
    USE SIGNAL ;
    PORT
      LAYER M5 ;
        RECT  72.48 0 72.504 0.084 ;
    END
  END q[308]
  PIN q[309]
    DIRECTION INPUT ;
    USE SIGNAL ;
    PORT
      LAYER M5 ;
        RECT  72.576 0 72.6 0.084 ;
    END
  END q[309]
  PIN q[30]
    DIRECTION INPUT ;
    USE SIGNAL ;
    PORT
      LAYER M5 ;
        RECT  45.792 0 45.816 0.084 ;
    END
  END q[30]
  PIN q[310]
    DIRECTION INPUT ;
    USE SIGNAL ;
    PORT
      LAYER M5 ;
        RECT  72.672 0 72.696 0.084 ;
    END
  END q[310]
  PIN q[311]
    DIRECTION INPUT ;
    USE SIGNAL ;
    PORT
      LAYER M5 ;
        RECT  72.768 0 72.792 0.084 ;
    END
  END q[311]
  PIN q[312]
    DIRECTION INPUT ;
    USE SIGNAL ;
    PORT
      LAYER M5 ;
        RECT  72.864 0 72.888 0.084 ;
    END
  END q[312]
  PIN q[313]
    DIRECTION INPUT ;
    USE SIGNAL ;
    PORT
      LAYER M5 ;
        RECT  72.96 0 72.984 0.084 ;
    END
  END q[313]
  PIN q[314]
    DIRECTION INPUT ;
    USE SIGNAL ;
    PORT
      LAYER M5 ;
        RECT  73.056 0 73.08 0.084 ;
    END
  END q[314]
  PIN q[315]
    DIRECTION INPUT ;
    USE SIGNAL ;
    PORT
      LAYER M5 ;
        RECT  73.152 0 73.176 0.084 ;
    END
  END q[315]
  PIN q[316]
    DIRECTION INPUT ;
    USE SIGNAL ;
    PORT
      LAYER M5 ;
        RECT  73.248 0 73.272 0.084 ;
    END
  END q[316]
  PIN q[317]
    DIRECTION INPUT ;
    USE SIGNAL ;
    PORT
      LAYER M5 ;
        RECT  73.344 0 73.368 0.084 ;
    END
  END q[317]
  PIN q[318]
    DIRECTION INPUT ;
    USE SIGNAL ;
    PORT
      LAYER M5 ;
        RECT  73.44 0 73.464 0.084 ;
    END
  END q[318]
  PIN q[319]
    DIRECTION INPUT ;
    USE SIGNAL ;
    PORT
      LAYER M5 ;
        RECT  73.536 0 73.56 0.084 ;
    END
  END q[319]
  PIN q[31]
    DIRECTION INPUT ;
    USE SIGNAL ;
    PORT
      LAYER M5 ;
        RECT  45.888 0 45.912 0.084 ;
    END
  END q[31]
  PIN q[320]
    DIRECTION INPUT ;
    USE SIGNAL ;
    PORT
      LAYER M5 ;
        RECT  73.632 0 73.656 0.084 ;
    END
  END q[320]
  PIN q[321]
    DIRECTION INPUT ;
    USE SIGNAL ;
    PORT
      LAYER M5 ;
        RECT  73.728 0 73.752 0.084 ;
    END
  END q[321]
  PIN q[322]
    DIRECTION INPUT ;
    USE SIGNAL ;
    PORT
      LAYER M5 ;
        RECT  73.824 0 73.848 0.084 ;
    END
  END q[322]
  PIN q[323]
    DIRECTION INPUT ;
    USE SIGNAL ;
    PORT
      LAYER M5 ;
        RECT  73.92 0 73.944 0.084 ;
    END
  END q[323]
  PIN q[324]
    DIRECTION INPUT ;
    USE SIGNAL ;
    PORT
      LAYER M5 ;
        RECT  74.016 0 74.04 0.084 ;
    END
  END q[324]
  PIN q[325]
    DIRECTION INPUT ;
    USE SIGNAL ;
    PORT
      LAYER M5 ;
        RECT  74.112 0 74.136 0.084 ;
    END
  END q[325]
  PIN q[326]
    DIRECTION INPUT ;
    USE SIGNAL ;
    PORT
      LAYER M5 ;
        RECT  74.208 0 74.232 0.084 ;
    END
  END q[326]
  PIN q[327]
    DIRECTION INPUT ;
    USE SIGNAL ;
    PORT
      LAYER M5 ;
        RECT  74.304 0 74.328 0.084 ;
    END
  END q[327]
  PIN q[328]
    DIRECTION INPUT ;
    USE SIGNAL ;
    PORT
      LAYER M5 ;
        RECT  74.4 0 74.424 0.084 ;
    END
  END q[328]
  PIN q[329]
    DIRECTION INPUT ;
    USE SIGNAL ;
    PORT
      LAYER M5 ;
        RECT  74.496 0 74.52 0.084 ;
    END
  END q[329]
  PIN q[32]
    DIRECTION INPUT ;
    USE SIGNAL ;
    PORT
      LAYER M5 ;
        RECT  45.984 0 46.008 0.084 ;
    END
  END q[32]
  PIN q[330]
    DIRECTION INPUT ;
    USE SIGNAL ;
    PORT
      LAYER M5 ;
        RECT  74.592 0 74.616 0.084 ;
    END
  END q[330]
  PIN q[331]
    DIRECTION INPUT ;
    USE SIGNAL ;
    PORT
      LAYER M5 ;
        RECT  74.688 0 74.712 0.084 ;
    END
  END q[331]
  PIN q[332]
    DIRECTION INPUT ;
    USE SIGNAL ;
    PORT
      LAYER M5 ;
        RECT  74.784 0 74.808 0.084 ;
    END
  END q[332]
  PIN q[333]
    DIRECTION INPUT ;
    USE SIGNAL ;
    PORT
      LAYER M5 ;
        RECT  74.88 0 74.904 0.084 ;
    END
  END q[333]
  PIN q[334]
    DIRECTION INPUT ;
    USE SIGNAL ;
    PORT
      LAYER M5 ;
        RECT  74.976 0 75 0.084 ;
    END
  END q[334]
  PIN q[335]
    DIRECTION INPUT ;
    USE SIGNAL ;
    PORT
      LAYER M5 ;
        RECT  75.072 0 75.096 0.084 ;
    END
  END q[335]
  PIN q[336]
    DIRECTION INPUT ;
    USE SIGNAL ;
    PORT
      LAYER M5 ;
        RECT  75.168 0 75.192 0.084 ;
    END
  END q[336]
  PIN q[337]
    DIRECTION INPUT ;
    USE SIGNAL ;
    PORT
      LAYER M5 ;
        RECT  75.264 0 75.288 0.084 ;
    END
  END q[337]
  PIN q[338]
    DIRECTION INPUT ;
    USE SIGNAL ;
    PORT
      LAYER M5 ;
        RECT  75.36 0 75.384 0.084 ;
    END
  END q[338]
  PIN q[339]
    DIRECTION INPUT ;
    USE SIGNAL ;
    PORT
      LAYER M5 ;
        RECT  75.456 0 75.48 0.084 ;
    END
  END q[339]
  PIN q[33]
    DIRECTION INPUT ;
    USE SIGNAL ;
    PORT
      LAYER M5 ;
        RECT  46.08 0 46.104 0.084 ;
    END
  END q[33]
  PIN q[340]
    DIRECTION INPUT ;
    USE SIGNAL ;
    PORT
      LAYER M5 ;
        RECT  75.552 0 75.576 0.084 ;
    END
  END q[340]
  PIN q[341]
    DIRECTION INPUT ;
    USE SIGNAL ;
    PORT
      LAYER M5 ;
        RECT  75.648 0 75.672 0.084 ;
    END
  END q[341]
  PIN q[342]
    DIRECTION INPUT ;
    USE SIGNAL ;
    PORT
      LAYER M5 ;
        RECT  75.744 0 75.768 0.084 ;
    END
  END q[342]
  PIN q[343]
    DIRECTION INPUT ;
    USE SIGNAL ;
    PORT
      LAYER M5 ;
        RECT  75.84 0 75.864 0.084 ;
    END
  END q[343]
  PIN q[344]
    DIRECTION INPUT ;
    USE SIGNAL ;
    PORT
      LAYER M5 ;
        RECT  75.936 0 75.96 0.084 ;
    END
  END q[344]
  PIN q[345]
    DIRECTION INPUT ;
    USE SIGNAL ;
    PORT
      LAYER M5 ;
        RECT  76.032 0 76.056 0.084 ;
    END
  END q[345]
  PIN q[346]
    DIRECTION INPUT ;
    USE SIGNAL ;
    PORT
      LAYER M5 ;
        RECT  76.128 0 76.152 0.084 ;
    END
  END q[346]
  PIN q[347]
    DIRECTION INPUT ;
    USE SIGNAL ;
    PORT
      LAYER M5 ;
        RECT  76.224 0 76.248 0.084 ;
    END
  END q[347]
  PIN q[348]
    DIRECTION INPUT ;
    USE SIGNAL ;
    PORT
      LAYER M5 ;
        RECT  76.32 0 76.344 0.084 ;
    END
  END q[348]
  PIN q[349]
    DIRECTION INPUT ;
    USE SIGNAL ;
    PORT
      LAYER M5 ;
        RECT  76.416 0 76.44 0.084 ;
    END
  END q[349]
  PIN q[34]
    DIRECTION INPUT ;
    USE SIGNAL ;
    PORT
      LAYER M5 ;
        RECT  46.176 0 46.2 0.084 ;
    END
  END q[34]
  PIN q[350]
    DIRECTION INPUT ;
    USE SIGNAL ;
    PORT
      LAYER M5 ;
        RECT  76.512 0 76.536 0.084 ;
    END
  END q[350]
  PIN q[351]
    DIRECTION INPUT ;
    USE SIGNAL ;
    PORT
      LAYER M5 ;
        RECT  76.608 0 76.632 0.084 ;
    END
  END q[351]
  PIN q[352]
    DIRECTION INPUT ;
    USE SIGNAL ;
    PORT
      LAYER M5 ;
        RECT  76.704 0 76.728 0.084 ;
    END
  END q[352]
  PIN q[353]
    DIRECTION INPUT ;
    USE SIGNAL ;
    PORT
      LAYER M5 ;
        RECT  76.8 0 76.824 0.084 ;
    END
  END q[353]
  PIN q[354]
    DIRECTION INPUT ;
    USE SIGNAL ;
    PORT
      LAYER M5 ;
        RECT  76.896 0 76.92 0.084 ;
    END
  END q[354]
  PIN q[355]
    DIRECTION INPUT ;
    USE SIGNAL ;
    PORT
      LAYER M5 ;
        RECT  76.992 0 77.016 0.084 ;
    END
  END q[355]
  PIN q[356]
    DIRECTION INPUT ;
    USE SIGNAL ;
    PORT
      LAYER M5 ;
        RECT  77.088 0 77.112 0.084 ;
    END
  END q[356]
  PIN q[357]
    DIRECTION INPUT ;
    USE SIGNAL ;
    PORT
      LAYER M5 ;
        RECT  77.184 0 77.208 0.084 ;
    END
  END q[357]
  PIN q[358]
    DIRECTION INPUT ;
    USE SIGNAL ;
    PORT
      LAYER M5 ;
        RECT  77.28 0 77.304 0.084 ;
    END
  END q[358]
  PIN q[359]
    DIRECTION INPUT ;
    USE SIGNAL ;
    PORT
      LAYER M5 ;
        RECT  77.376 0 77.4 0.084 ;
    END
  END q[359]
  PIN q[35]
    DIRECTION INPUT ;
    USE SIGNAL ;
    PORT
      LAYER M5 ;
        RECT  46.272 0 46.296 0.084 ;
    END
  END q[35]
  PIN q[360]
    DIRECTION INPUT ;
    USE SIGNAL ;
    PORT
      LAYER M5 ;
        RECT  77.472 0 77.496 0.084 ;
    END
  END q[360]
  PIN q[361]
    DIRECTION INPUT ;
    USE SIGNAL ;
    PORT
      LAYER M5 ;
        RECT  77.568 0 77.592 0.084 ;
    END
  END q[361]
  PIN q[362]
    DIRECTION INPUT ;
    USE SIGNAL ;
    PORT
      LAYER M5 ;
        RECT  77.664 0 77.688 0.084 ;
    END
  END q[362]
  PIN q[363]
    DIRECTION INPUT ;
    USE SIGNAL ;
    PORT
      LAYER M5 ;
        RECT  77.76 0 77.784 0.084 ;
    END
  END q[363]
  PIN q[364]
    DIRECTION INPUT ;
    USE SIGNAL ;
    PORT
      LAYER M5 ;
        RECT  77.856 0 77.88 0.084 ;
    END
  END q[364]
  PIN q[365]
    DIRECTION INPUT ;
    USE SIGNAL ;
    PORT
      LAYER M5 ;
        RECT  77.952 0 77.976 0.084 ;
    END
  END q[365]
  PIN q[366]
    DIRECTION INPUT ;
    USE SIGNAL ;
    PORT
      LAYER M5 ;
        RECT  78.048 0 78.072 0.084 ;
    END
  END q[366]
  PIN q[367]
    DIRECTION INPUT ;
    USE SIGNAL ;
    PORT
      LAYER M5 ;
        RECT  78.144 0 78.168 0.084 ;
    END
  END q[367]
  PIN q[368]
    DIRECTION INPUT ;
    USE SIGNAL ;
    PORT
      LAYER M5 ;
        RECT  78.24 0 78.264 0.084 ;
    END
  END q[368]
  PIN q[369]
    DIRECTION INPUT ;
    USE SIGNAL ;
    PORT
      LAYER M5 ;
        RECT  78.336 0 78.36 0.084 ;
    END
  END q[369]
  PIN q[36]
    DIRECTION INPUT ;
    USE SIGNAL ;
    PORT
      LAYER M5 ;
        RECT  46.368 0 46.392 0.084 ;
    END
  END q[36]
  PIN q[370]
    DIRECTION INPUT ;
    USE SIGNAL ;
    PORT
      LAYER M5 ;
        RECT  78.432 0 78.456 0.084 ;
    END
  END q[370]
  PIN q[371]
    DIRECTION INPUT ;
    USE SIGNAL ;
    PORT
      LAYER M5 ;
        RECT  78.528 0 78.552 0.084 ;
    END
  END q[371]
  PIN q[372]
    DIRECTION INPUT ;
    USE SIGNAL ;
    PORT
      LAYER M5 ;
        RECT  78.624 0 78.648 0.084 ;
    END
  END q[372]
  PIN q[373]
    DIRECTION INPUT ;
    USE SIGNAL ;
    PORT
      LAYER M5 ;
        RECT  78.72 0 78.744 0.084 ;
    END
  END q[373]
  PIN q[374]
    DIRECTION INPUT ;
    USE SIGNAL ;
    PORT
      LAYER M5 ;
        RECT  78.816 0 78.84 0.084 ;
    END
  END q[374]
  PIN q[375]
    DIRECTION INPUT ;
    USE SIGNAL ;
    PORT
      LAYER M5 ;
        RECT  78.912 0 78.936 0.084 ;
    END
  END q[375]
  PIN q[376]
    DIRECTION INPUT ;
    USE SIGNAL ;
    PORT
      LAYER M5 ;
        RECT  79.008 0 79.032 0.084 ;
    END
  END q[376]
  PIN q[377]
    DIRECTION INPUT ;
    USE SIGNAL ;
    PORT
      LAYER M5 ;
        RECT  79.104 0 79.128 0.084 ;
    END
  END q[377]
  PIN q[378]
    DIRECTION INPUT ;
    USE SIGNAL ;
    PORT
      LAYER M5 ;
        RECT  79.2 0 79.224 0.084 ;
    END
  END q[378]
  PIN q[379]
    DIRECTION INPUT ;
    USE SIGNAL ;
    PORT
      LAYER M5 ;
        RECT  79.296 0 79.32 0.084 ;
    END
  END q[379]
  PIN q[37]
    DIRECTION INPUT ;
    USE SIGNAL ;
    PORT
      LAYER M5 ;
        RECT  46.464 0 46.488 0.084 ;
    END
  END q[37]
  PIN q[380]
    DIRECTION INPUT ;
    USE SIGNAL ;
    PORT
      LAYER M5 ;
        RECT  79.392 0 79.416 0.084 ;
    END
  END q[380]
  PIN q[381]
    DIRECTION INPUT ;
    USE SIGNAL ;
    PORT
      LAYER M5 ;
        RECT  79.488 0 79.512 0.084 ;
    END
  END q[381]
  PIN q[382]
    DIRECTION INPUT ;
    USE SIGNAL ;
    PORT
      LAYER M5 ;
        RECT  79.584 0 79.608 0.084 ;
    END
  END q[382]
  PIN q[383]
    DIRECTION INPUT ;
    USE SIGNAL ;
    PORT
      LAYER M5 ;
        RECT  79.68 0 79.704 0.084 ;
    END
  END q[383]
  PIN q[384]
    DIRECTION INPUT ;
    USE SIGNAL ;
    PORT
      LAYER M5 ;
        RECT  79.776 0 79.8 0.084 ;
    END
  END q[384]
  PIN q[385]
    DIRECTION INPUT ;
    USE SIGNAL ;
    PORT
      LAYER M5 ;
        RECT  79.872 0 79.896 0.084 ;
    END
  END q[385]
  PIN q[386]
    DIRECTION INPUT ;
    USE SIGNAL ;
    PORT
      LAYER M5 ;
        RECT  79.968 0 79.992 0.084 ;
    END
  END q[386]
  PIN q[387]
    DIRECTION INPUT ;
    USE SIGNAL ;
    PORT
      LAYER M5 ;
        RECT  80.064 0 80.088 0.084 ;
    END
  END q[387]
  PIN q[388]
    DIRECTION INPUT ;
    USE SIGNAL ;
    PORT
      LAYER M5 ;
        RECT  80.16 0 80.184 0.084 ;
    END
  END q[388]
  PIN q[389]
    DIRECTION INPUT ;
    USE SIGNAL ;
    PORT
      LAYER M5 ;
        RECT  80.256 0 80.28 0.084 ;
    END
  END q[389]
  PIN q[38]
    DIRECTION INPUT ;
    USE SIGNAL ;
    PORT
      LAYER M5 ;
        RECT  46.56 0 46.584 0.084 ;
    END
  END q[38]
  PIN q[390]
    DIRECTION INPUT ;
    USE SIGNAL ;
    PORT
      LAYER M5 ;
        RECT  80.352 0 80.376 0.084 ;
    END
  END q[390]
  PIN q[391]
    DIRECTION INPUT ;
    USE SIGNAL ;
    PORT
      LAYER M5 ;
        RECT  80.448 0 80.472 0.084 ;
    END
  END q[391]
  PIN q[392]
    DIRECTION INPUT ;
    USE SIGNAL ;
    PORT
      LAYER M5 ;
        RECT  80.544 0 80.568 0.084 ;
    END
  END q[392]
  PIN q[393]
    DIRECTION INPUT ;
    USE SIGNAL ;
    PORT
      LAYER M5 ;
        RECT  80.64 0 80.664 0.084 ;
    END
  END q[393]
  PIN q[394]
    DIRECTION INPUT ;
    USE SIGNAL ;
    PORT
      LAYER M5 ;
        RECT  80.736 0 80.76 0.084 ;
    END
  END q[394]
  PIN q[395]
    DIRECTION INPUT ;
    USE SIGNAL ;
    PORT
      LAYER M5 ;
        RECT  80.832 0 80.856 0.084 ;
    END
  END q[395]
  PIN q[396]
    DIRECTION INPUT ;
    USE SIGNAL ;
    PORT
      LAYER M5 ;
        RECT  80.928 0 80.952 0.084 ;
    END
  END q[396]
  PIN q[397]
    DIRECTION INPUT ;
    USE SIGNAL ;
    PORT
      LAYER M5 ;
        RECT  81.024 0 81.048 0.084 ;
    END
  END q[397]
  PIN q[398]
    DIRECTION INPUT ;
    USE SIGNAL ;
    PORT
      LAYER M5 ;
        RECT  81.12 0 81.144 0.084 ;
    END
  END q[398]
  PIN q[399]
    DIRECTION INPUT ;
    USE SIGNAL ;
    PORT
      LAYER M5 ;
        RECT  81.216 0 81.24 0.084 ;
    END
  END q[399]
  PIN q[39]
    DIRECTION INPUT ;
    USE SIGNAL ;
    PORT
      LAYER M5 ;
        RECT  46.656 0 46.68 0.084 ;
    END
  END q[39]
  PIN q[3]
    DIRECTION INPUT ;
    USE SIGNAL ;
    PORT
      LAYER M5 ;
        RECT  43.2 0 43.224 0.084 ;
    END
  END q[3]
  PIN q[400]
    DIRECTION INPUT ;
    USE SIGNAL ;
    PORT
      LAYER M5 ;
        RECT  81.312 0 81.336 0.084 ;
    END
  END q[400]
  PIN q[401]
    DIRECTION INPUT ;
    USE SIGNAL ;
    PORT
      LAYER M5 ;
        RECT  81.408 0 81.432 0.084 ;
    END
  END q[401]
  PIN q[402]
    DIRECTION INPUT ;
    USE SIGNAL ;
    PORT
      LAYER M5 ;
        RECT  81.504 0 81.528 0.084 ;
    END
  END q[402]
  PIN q[403]
    DIRECTION INPUT ;
    USE SIGNAL ;
    PORT
      LAYER M5 ;
        RECT  81.6 0 81.624 0.084 ;
    END
  END q[403]
  PIN q[404]
    DIRECTION INPUT ;
    USE SIGNAL ;
    PORT
      LAYER M5 ;
        RECT  81.696 0 81.72 0.084 ;
    END
  END q[404]
  PIN q[405]
    DIRECTION INPUT ;
    USE SIGNAL ;
    PORT
      LAYER M5 ;
        RECT  81.792 0 81.816 0.084 ;
    END
  END q[405]
  PIN q[406]
    DIRECTION INPUT ;
    USE SIGNAL ;
    PORT
      LAYER M5 ;
        RECT  81.888 0 81.912 0.084 ;
    END
  END q[406]
  PIN q[407]
    DIRECTION INPUT ;
    USE SIGNAL ;
    PORT
      LAYER M5 ;
        RECT  81.984 0 82.008 0.084 ;
    END
  END q[407]
  PIN q[408]
    DIRECTION INPUT ;
    USE SIGNAL ;
    PORT
      LAYER M5 ;
        RECT  82.08 0 82.104 0.084 ;
    END
  END q[408]
  PIN q[409]
    DIRECTION INPUT ;
    USE SIGNAL ;
    PORT
      LAYER M5 ;
        RECT  82.176 0 82.2 0.084 ;
    END
  END q[409]
  PIN q[40]
    DIRECTION INPUT ;
    USE SIGNAL ;
    PORT
      LAYER M5 ;
        RECT  46.752 0 46.776 0.084 ;
    END
  END q[40]
  PIN q[410]
    DIRECTION INPUT ;
    USE SIGNAL ;
    PORT
      LAYER M5 ;
        RECT  82.272 0 82.296 0.084 ;
    END
  END q[410]
  PIN q[411]
    DIRECTION INPUT ;
    USE SIGNAL ;
    PORT
      LAYER M5 ;
        RECT  82.368 0 82.392 0.084 ;
    END
  END q[411]
  PIN q[412]
    DIRECTION INPUT ;
    USE SIGNAL ;
    PORT
      LAYER M5 ;
        RECT  82.464 0 82.488 0.084 ;
    END
  END q[412]
  PIN q[413]
    DIRECTION INPUT ;
    USE SIGNAL ;
    PORT
      LAYER M5 ;
        RECT  82.56 0 82.584 0.084 ;
    END
  END q[413]
  PIN q[414]
    DIRECTION INPUT ;
    USE SIGNAL ;
    PORT
      LAYER M5 ;
        RECT  82.656 0 82.68 0.084 ;
    END
  END q[414]
  PIN q[415]
    DIRECTION INPUT ;
    USE SIGNAL ;
    PORT
      LAYER M5 ;
        RECT  82.752 0 82.776 0.084 ;
    END
  END q[415]
  PIN q[416]
    DIRECTION INPUT ;
    USE SIGNAL ;
    PORT
      LAYER M5 ;
        RECT  82.848 0 82.872 0.084 ;
    END
  END q[416]
  PIN q[417]
    DIRECTION INPUT ;
    USE SIGNAL ;
    PORT
      LAYER M5 ;
        RECT  82.944 0 82.968 0.084 ;
    END
  END q[417]
  PIN q[418]
    DIRECTION INPUT ;
    USE SIGNAL ;
    PORT
      LAYER M5 ;
        RECT  83.04 0 83.064 0.084 ;
    END
  END q[418]
  PIN q[419]
    DIRECTION INPUT ;
    USE SIGNAL ;
    PORT
      LAYER M5 ;
        RECT  83.136 0 83.16 0.084 ;
    END
  END q[419]
  PIN q[41]
    DIRECTION INPUT ;
    USE SIGNAL ;
    PORT
      LAYER M5 ;
        RECT  46.848 0 46.872 0.084 ;
    END
  END q[41]
  PIN q[420]
    DIRECTION INPUT ;
    USE SIGNAL ;
    PORT
      LAYER M5 ;
        RECT  83.232 0 83.256 0.084 ;
    END
  END q[420]
  PIN q[421]
    DIRECTION INPUT ;
    USE SIGNAL ;
    PORT
      LAYER M5 ;
        RECT  83.328 0 83.352 0.084 ;
    END
  END q[421]
  PIN q[422]
    DIRECTION INPUT ;
    USE SIGNAL ;
    PORT
      LAYER M5 ;
        RECT  83.424 0 83.448 0.084 ;
    END
  END q[422]
  PIN q[423]
    DIRECTION INPUT ;
    USE SIGNAL ;
    PORT
      LAYER M5 ;
        RECT  83.52 0 83.544 0.084 ;
    END
  END q[423]
  PIN q[424]
    DIRECTION INPUT ;
    USE SIGNAL ;
    PORT
      LAYER M5 ;
        RECT  83.616 0 83.64 0.084 ;
    END
  END q[424]
  PIN q[425]
    DIRECTION INPUT ;
    USE SIGNAL ;
    PORT
      LAYER M5 ;
        RECT  83.712 0 83.736 0.084 ;
    END
  END q[425]
  PIN q[426]
    DIRECTION INPUT ;
    USE SIGNAL ;
    PORT
      LAYER M5 ;
        RECT  83.808 0 83.832 0.084 ;
    END
  END q[426]
  PIN q[427]
    DIRECTION INPUT ;
    USE SIGNAL ;
    PORT
      LAYER M5 ;
        RECT  83.904 0 83.928 0.084 ;
    END
  END q[427]
  PIN q[428]
    DIRECTION INPUT ;
    USE SIGNAL ;
    PORT
      LAYER M5 ;
        RECT  84 0 84.024 0.084 ;
    END
  END q[428]
  PIN q[429]
    DIRECTION INPUT ;
    USE SIGNAL ;
    PORT
      LAYER M5 ;
        RECT  84.096 0 84.12 0.084 ;
    END
  END q[429]
  PIN q[42]
    DIRECTION INPUT ;
    USE SIGNAL ;
    PORT
      LAYER M5 ;
        RECT  46.944 0 46.968 0.084 ;
    END
  END q[42]
  PIN q[430]
    DIRECTION INPUT ;
    USE SIGNAL ;
    PORT
      LAYER M5 ;
        RECT  84.192 0 84.216 0.084 ;
    END
  END q[430]
  PIN q[431]
    DIRECTION INPUT ;
    USE SIGNAL ;
    PORT
      LAYER M5 ;
        RECT  84.288 0 84.312 0.084 ;
    END
  END q[431]
  PIN q[432]
    DIRECTION INPUT ;
    USE SIGNAL ;
    PORT
      LAYER M5 ;
        RECT  84.384 0 84.408 0.084 ;
    END
  END q[432]
  PIN q[433]
    DIRECTION INPUT ;
    USE SIGNAL ;
    PORT
      LAYER M5 ;
        RECT  84.48 0 84.504 0.084 ;
    END
  END q[433]
  PIN q[434]
    DIRECTION INPUT ;
    USE SIGNAL ;
    PORT
      LAYER M5 ;
        RECT  84.576 0 84.6 0.084 ;
    END
  END q[434]
  PIN q[435]
    DIRECTION INPUT ;
    USE SIGNAL ;
    PORT
      LAYER M5 ;
        RECT  84.672 0 84.696 0.084 ;
    END
  END q[435]
  PIN q[436]
    DIRECTION INPUT ;
    USE SIGNAL ;
    PORT
      LAYER M5 ;
        RECT  84.768 0 84.792 0.084 ;
    END
  END q[436]
  PIN q[437]
    DIRECTION INPUT ;
    USE SIGNAL ;
    PORT
      LAYER M5 ;
        RECT  84.864 0 84.888 0.084 ;
    END
  END q[437]
  PIN q[438]
    DIRECTION INPUT ;
    USE SIGNAL ;
    PORT
      LAYER M5 ;
        RECT  84.96 0 84.984 0.084 ;
    END
  END q[438]
  PIN q[439]
    DIRECTION INPUT ;
    USE SIGNAL ;
    PORT
      LAYER M5 ;
        RECT  85.056 0 85.08 0.084 ;
    END
  END q[439]
  PIN q[43]
    DIRECTION INPUT ;
    USE SIGNAL ;
    PORT
      LAYER M5 ;
        RECT  47.04 0 47.064 0.084 ;
    END
  END q[43]
  PIN q[440]
    DIRECTION INPUT ;
    USE SIGNAL ;
    PORT
      LAYER M5 ;
        RECT  85.152 0 85.176 0.084 ;
    END
  END q[440]
  PIN q[441]
    DIRECTION INPUT ;
    USE SIGNAL ;
    PORT
      LAYER M5 ;
        RECT  85.248 0 85.272 0.084 ;
    END
  END q[441]
  PIN q[442]
    DIRECTION INPUT ;
    USE SIGNAL ;
    PORT
      LAYER M5 ;
        RECT  85.344 0 85.368 0.084 ;
    END
  END q[442]
  PIN q[443]
    DIRECTION INPUT ;
    USE SIGNAL ;
    PORT
      LAYER M5 ;
        RECT  85.44 0 85.464 0.084 ;
    END
  END q[443]
  PIN q[444]
    DIRECTION INPUT ;
    USE SIGNAL ;
    PORT
      LAYER M5 ;
        RECT  85.536 0 85.56 0.084 ;
    END
  END q[444]
  PIN q[445]
    DIRECTION INPUT ;
    USE SIGNAL ;
    PORT
      LAYER M5 ;
        RECT  85.632 0 85.656 0.084 ;
    END
  END q[445]
  PIN q[446]
    DIRECTION INPUT ;
    USE SIGNAL ;
    PORT
      LAYER M5 ;
        RECT  85.728 0 85.752 0.084 ;
    END
  END q[446]
  PIN q[447]
    DIRECTION INPUT ;
    USE SIGNAL ;
    PORT
      LAYER M5 ;
        RECT  85.824 0 85.848 0.084 ;
    END
  END q[447]
  PIN q[448]
    DIRECTION INPUT ;
    USE SIGNAL ;
    PORT
      LAYER M5 ;
        RECT  85.92 0 85.944 0.084 ;
    END
  END q[448]
  PIN q[449]
    DIRECTION INPUT ;
    USE SIGNAL ;
    PORT
      LAYER M5 ;
        RECT  86.016 0 86.04 0.084 ;
    END
  END q[449]
  PIN q[44]
    DIRECTION INPUT ;
    USE SIGNAL ;
    PORT
      LAYER M5 ;
        RECT  47.136 0 47.16 0.084 ;
    END
  END q[44]
  PIN q[450]
    DIRECTION INPUT ;
    USE SIGNAL ;
    PORT
      LAYER M5 ;
        RECT  86.112 0 86.136 0.084 ;
    END
  END q[450]
  PIN q[451]
    DIRECTION INPUT ;
    USE SIGNAL ;
    PORT
      LAYER M5 ;
        RECT  86.208 0 86.232 0.084 ;
    END
  END q[451]
  PIN q[452]
    DIRECTION INPUT ;
    USE SIGNAL ;
    PORT
      LAYER M5 ;
        RECT  86.304 0 86.328 0.084 ;
    END
  END q[452]
  PIN q[453]
    DIRECTION INPUT ;
    USE SIGNAL ;
    PORT
      LAYER M5 ;
        RECT  86.4 0 86.424 0.084 ;
    END
  END q[453]
  PIN q[454]
    DIRECTION INPUT ;
    USE SIGNAL ;
    PORT
      LAYER M5 ;
        RECT  86.496 0 86.52 0.084 ;
    END
  END q[454]
  PIN q[455]
    DIRECTION INPUT ;
    USE SIGNAL ;
    PORT
      LAYER M5 ;
        RECT  86.592 0 86.616 0.084 ;
    END
  END q[455]
  PIN q[456]
    DIRECTION INPUT ;
    USE SIGNAL ;
    PORT
      LAYER M5 ;
        RECT  86.688 0 86.712 0.084 ;
    END
  END q[456]
  PIN q[457]
    DIRECTION INPUT ;
    USE SIGNAL ;
    PORT
      LAYER M5 ;
        RECT  86.784 0 86.808 0.084 ;
    END
  END q[457]
  PIN q[458]
    DIRECTION INPUT ;
    USE SIGNAL ;
    PORT
      LAYER M5 ;
        RECT  86.88 0 86.904 0.084 ;
    END
  END q[458]
  PIN q[459]
    DIRECTION INPUT ;
    USE SIGNAL ;
    PORT
      LAYER M5 ;
        RECT  86.976 0 87 0.084 ;
    END
  END q[459]
  PIN q[45]
    DIRECTION INPUT ;
    USE SIGNAL ;
    PORT
      LAYER M5 ;
        RECT  47.232 0 47.256 0.084 ;
    END
  END q[45]
  PIN q[460]
    DIRECTION INPUT ;
    USE SIGNAL ;
    PORT
      LAYER M5 ;
        RECT  87.072 0 87.096 0.084 ;
    END
  END q[460]
  PIN q[461]
    DIRECTION INPUT ;
    USE SIGNAL ;
    PORT
      LAYER M5 ;
        RECT  87.168 0 87.192 0.084 ;
    END
  END q[461]
  PIN q[462]
    DIRECTION INPUT ;
    USE SIGNAL ;
    PORT
      LAYER M5 ;
        RECT  87.264 0 87.288 0.084 ;
    END
  END q[462]
  PIN q[463]
    DIRECTION INPUT ;
    USE SIGNAL ;
    PORT
      LAYER M5 ;
        RECT  87.36 0 87.384 0.084 ;
    END
  END q[463]
  PIN q[464]
    DIRECTION INPUT ;
    USE SIGNAL ;
    PORT
      LAYER M5 ;
        RECT  87.456 0 87.48 0.084 ;
    END
  END q[464]
  PIN q[465]
    DIRECTION INPUT ;
    USE SIGNAL ;
    PORT
      LAYER M5 ;
        RECT  87.552 0 87.576 0.084 ;
    END
  END q[465]
  PIN q[466]
    DIRECTION INPUT ;
    USE SIGNAL ;
    PORT
      LAYER M5 ;
        RECT  87.648 0 87.672 0.084 ;
    END
  END q[466]
  PIN q[467]
    DIRECTION INPUT ;
    USE SIGNAL ;
    PORT
      LAYER M5 ;
        RECT  87.744 0 87.768 0.084 ;
    END
  END q[467]
  PIN q[468]
    DIRECTION INPUT ;
    USE SIGNAL ;
    PORT
      LAYER M5 ;
        RECT  87.84 0 87.864 0.084 ;
    END
  END q[468]
  PIN q[469]
    DIRECTION INPUT ;
    USE SIGNAL ;
    PORT
      LAYER M5 ;
        RECT  87.936 0 87.96 0.084 ;
    END
  END q[469]
  PIN q[46]
    DIRECTION INPUT ;
    USE SIGNAL ;
    PORT
      LAYER M5 ;
        RECT  47.328 0 47.352 0.084 ;
    END
  END q[46]
  PIN q[470]
    DIRECTION INPUT ;
    USE SIGNAL ;
    PORT
      LAYER M5 ;
        RECT  88.032 0 88.056 0.084 ;
    END
  END q[470]
  PIN q[471]
    DIRECTION INPUT ;
    USE SIGNAL ;
    PORT
      LAYER M5 ;
        RECT  88.128 0 88.152 0.084 ;
    END
  END q[471]
  PIN q[472]
    DIRECTION INPUT ;
    USE SIGNAL ;
    PORT
      LAYER M5 ;
        RECT  88.224 0 88.248 0.084 ;
    END
  END q[472]
  PIN q[473]
    DIRECTION INPUT ;
    USE SIGNAL ;
    PORT
      LAYER M5 ;
        RECT  88.32 0 88.344 0.084 ;
    END
  END q[473]
  PIN q[474]
    DIRECTION INPUT ;
    USE SIGNAL ;
    PORT
      LAYER M5 ;
        RECT  88.416 0 88.44 0.084 ;
    END
  END q[474]
  PIN q[475]
    DIRECTION INPUT ;
    USE SIGNAL ;
    PORT
      LAYER M5 ;
        RECT  88.512 0 88.536 0.084 ;
    END
  END q[475]
  PIN q[476]
    DIRECTION INPUT ;
    USE SIGNAL ;
    PORT
      LAYER M5 ;
        RECT  88.608 0 88.632 0.084 ;
    END
  END q[476]
  PIN q[477]
    DIRECTION INPUT ;
    USE SIGNAL ;
    PORT
      LAYER M5 ;
        RECT  88.704 0 88.728 0.084 ;
    END
  END q[477]
  PIN q[478]
    DIRECTION INPUT ;
    USE SIGNAL ;
    PORT
      LAYER M5 ;
        RECT  88.8 0 88.824 0.084 ;
    END
  END q[478]
  PIN q[479]
    DIRECTION INPUT ;
    USE SIGNAL ;
    PORT
      LAYER M5 ;
        RECT  88.896 0 88.92 0.084 ;
    END
  END q[479]
  PIN q[47]
    DIRECTION INPUT ;
    USE SIGNAL ;
    PORT
      LAYER M5 ;
        RECT  47.424 0 47.448 0.084 ;
    END
  END q[47]
  PIN q[480]
    DIRECTION INPUT ;
    USE SIGNAL ;
    PORT
      LAYER M5 ;
        RECT  88.992 0 89.016 0.084 ;
    END
  END q[480]
  PIN q[481]
    DIRECTION INPUT ;
    USE SIGNAL ;
    PORT
      LAYER M5 ;
        RECT  89.088 0 89.112 0.084 ;
    END
  END q[481]
  PIN q[482]
    DIRECTION INPUT ;
    USE SIGNAL ;
    PORT
      LAYER M5 ;
        RECT  89.184 0 89.208 0.084 ;
    END
  END q[482]
  PIN q[483]
    DIRECTION INPUT ;
    USE SIGNAL ;
    PORT
      LAYER M5 ;
        RECT  89.28 0 89.304 0.084 ;
    END
  END q[483]
  PIN q[484]
    DIRECTION INPUT ;
    USE SIGNAL ;
    PORT
      LAYER M5 ;
        RECT  89.376 0 89.4 0.084 ;
    END
  END q[484]
  PIN q[485]
    DIRECTION INPUT ;
    USE SIGNAL ;
    PORT
      LAYER M5 ;
        RECT  89.472 0 89.496 0.084 ;
    END
  END q[485]
  PIN q[486]
    DIRECTION INPUT ;
    USE SIGNAL ;
    PORT
      LAYER M5 ;
        RECT  89.568 0 89.592 0.084 ;
    END
  END q[486]
  PIN q[487]
    DIRECTION INPUT ;
    USE SIGNAL ;
    PORT
      LAYER M5 ;
        RECT  89.664 0 89.688 0.084 ;
    END
  END q[487]
  PIN q[488]
    DIRECTION INPUT ;
    USE SIGNAL ;
    PORT
      LAYER M5 ;
        RECT  89.76 0 89.784 0.084 ;
    END
  END q[488]
  PIN q[489]
    DIRECTION INPUT ;
    USE SIGNAL ;
    PORT
      LAYER M5 ;
        RECT  89.856 0 89.88 0.084 ;
    END
  END q[489]
  PIN q[48]
    DIRECTION INPUT ;
    USE SIGNAL ;
    PORT
      LAYER M5 ;
        RECT  47.52 0 47.544 0.084 ;
    END
  END q[48]
  PIN q[490]
    DIRECTION INPUT ;
    USE SIGNAL ;
    PORT
      LAYER M5 ;
        RECT  89.952 0 89.976 0.084 ;
    END
  END q[490]
  PIN q[491]
    DIRECTION INPUT ;
    USE SIGNAL ;
    PORT
      LAYER M5 ;
        RECT  90.048 0 90.072 0.084 ;
    END
  END q[491]
  PIN q[492]
    DIRECTION INPUT ;
    USE SIGNAL ;
    PORT
      LAYER M5 ;
        RECT  90.144 0 90.168 0.084 ;
    END
  END q[492]
  PIN q[493]
    DIRECTION INPUT ;
    USE SIGNAL ;
    PORT
      LAYER M5 ;
        RECT  90.24 0 90.264 0.084 ;
    END
  END q[493]
  PIN q[494]
    DIRECTION INPUT ;
    USE SIGNAL ;
    PORT
      LAYER M5 ;
        RECT  90.336 0 90.36 0.084 ;
    END
  END q[494]
  PIN q[495]
    DIRECTION INPUT ;
    USE SIGNAL ;
    PORT
      LAYER M5 ;
        RECT  90.432 0 90.456 0.084 ;
    END
  END q[495]
  PIN q[496]
    DIRECTION INPUT ;
    USE SIGNAL ;
    PORT
      LAYER M5 ;
        RECT  90.528 0 90.552 0.084 ;
    END
  END q[496]
  PIN q[497]
    DIRECTION INPUT ;
    USE SIGNAL ;
    PORT
      LAYER M5 ;
        RECT  90.624 0 90.648 0.084 ;
    END
  END q[497]
  PIN q[498]
    DIRECTION INPUT ;
    USE SIGNAL ;
    PORT
      LAYER M5 ;
        RECT  90.72 0 90.744 0.084 ;
    END
  END q[498]
  PIN q[499]
    DIRECTION INPUT ;
    USE SIGNAL ;
    PORT
      LAYER M5 ;
        RECT  90.816 0 90.84 0.084 ;
    END
  END q[499]
  PIN q[49]
    DIRECTION INPUT ;
    USE SIGNAL ;
    PORT
      LAYER M5 ;
        RECT  47.616 0 47.64 0.084 ;
    END
  END q[49]
  PIN q[4]
    DIRECTION INPUT ;
    USE SIGNAL ;
    PORT
      LAYER M5 ;
        RECT  43.296 0 43.32 0.084 ;
    END
  END q[4]
  PIN q[500]
    DIRECTION INPUT ;
    USE SIGNAL ;
    PORT
      LAYER M5 ;
        RECT  90.912 0 90.936 0.084 ;
    END
  END q[500]
  PIN q[501]
    DIRECTION INPUT ;
    USE SIGNAL ;
    PORT
      LAYER M5 ;
        RECT  91.008 0 91.032 0.084 ;
    END
  END q[501]
  PIN q[502]
    DIRECTION INPUT ;
    USE SIGNAL ;
    PORT
      LAYER M5 ;
        RECT  91.104 0 91.128 0.084 ;
    END
  END q[502]
  PIN q[503]
    DIRECTION INPUT ;
    USE SIGNAL ;
    PORT
      LAYER M5 ;
        RECT  91.2 0 91.224 0.084 ;
    END
  END q[503]
  PIN q[504]
    DIRECTION INPUT ;
    USE SIGNAL ;
    PORT
      LAYER M5 ;
        RECT  91.296 0 91.32 0.084 ;
    END
  END q[504]
  PIN q[505]
    DIRECTION INPUT ;
    USE SIGNAL ;
    PORT
      LAYER M5 ;
        RECT  91.392 0 91.416 0.084 ;
    END
  END q[505]
  PIN q[506]
    DIRECTION INPUT ;
    USE SIGNAL ;
    PORT
      LAYER M5 ;
        RECT  91.488 0 91.512 0.084 ;
    END
  END q[506]
  PIN q[507]
    DIRECTION INPUT ;
    USE SIGNAL ;
    PORT
      LAYER M5 ;
        RECT  91.584 0 91.608 0.084 ;
    END
  END q[507]
  PIN q[508]
    DIRECTION INPUT ;
    USE SIGNAL ;
    PORT
      LAYER M5 ;
        RECT  91.68 0 91.704 0.084 ;
    END
  END q[508]
  PIN q[509]
    DIRECTION INPUT ;
    USE SIGNAL ;
    PORT
      LAYER M5 ;
        RECT  91.776 0 91.8 0.084 ;
    END
  END q[509]
  PIN q[50]
    DIRECTION INPUT ;
    USE SIGNAL ;
    PORT
      LAYER M5 ;
        RECT  47.712 0 47.736 0.084 ;
    END
  END q[50]
  PIN q[510]
    DIRECTION INPUT ;
    USE SIGNAL ;
    PORT
      LAYER M5 ;
        RECT  91.872 0 91.896 0.084 ;
    END
  END q[510]
  PIN q[511]
    DIRECTION INPUT ;
    USE SIGNAL ;
    PORT
      LAYER M5 ;
        RECT  91.968 0 91.992 0.084 ;
    END
  END q[511]
  PIN q[512]
    DIRECTION INPUT ;
    USE SIGNAL ;
    PORT
      LAYER M5 ;
        RECT  92.064 0 92.088 0.084 ;
    END
  END q[512]
  PIN q[513]
    DIRECTION INPUT ;
    USE SIGNAL ;
    PORT
      LAYER M5 ;
        RECT  92.16 0 92.184 0.084 ;
    END
  END q[513]
  PIN q[514]
    DIRECTION INPUT ;
    USE SIGNAL ;
    PORT
      LAYER M5 ;
        RECT  92.256 0 92.28 0.084 ;
    END
  END q[514]
  PIN q[51]
    DIRECTION INPUT ;
    USE SIGNAL ;
    PORT
      LAYER M5 ;
        RECT  47.808 0 47.832 0.084 ;
    END
  END q[51]
  PIN q[52]
    DIRECTION INPUT ;
    USE SIGNAL ;
    PORT
      LAYER M5 ;
        RECT  47.904 0 47.928 0.084 ;
    END
  END q[52]
  PIN q[53]
    DIRECTION INPUT ;
    USE SIGNAL ;
    PORT
      LAYER M5 ;
        RECT  48 0 48.024 0.084 ;
    END
  END q[53]
  PIN q[54]
    DIRECTION INPUT ;
    USE SIGNAL ;
    PORT
      LAYER M5 ;
        RECT  48.096 0 48.12 0.084 ;
    END
  END q[54]
  PIN q[55]
    DIRECTION INPUT ;
    USE SIGNAL ;
    PORT
      LAYER M5 ;
        RECT  48.192 0 48.216 0.084 ;
    END
  END q[55]
  PIN q[56]
    DIRECTION INPUT ;
    USE SIGNAL ;
    PORT
      LAYER M5 ;
        RECT  48.288 0 48.312 0.084 ;
    END
  END q[56]
  PIN q[57]
    DIRECTION INPUT ;
    USE SIGNAL ;
    PORT
      LAYER M5 ;
        RECT  48.384 0 48.408 0.084 ;
    END
  END q[57]
  PIN q[58]
    DIRECTION INPUT ;
    USE SIGNAL ;
    PORT
      LAYER M5 ;
        RECT  48.48 0 48.504 0.084 ;
    END
  END q[58]
  PIN q[59]
    DIRECTION INPUT ;
    USE SIGNAL ;
    PORT
      LAYER M5 ;
        RECT  48.576 0 48.6 0.084 ;
    END
  END q[59]
  PIN q[5]
    DIRECTION INPUT ;
    USE SIGNAL ;
    PORT
      LAYER M5 ;
        RECT  43.392 0 43.416 0.084 ;
    END
  END q[5]
  PIN q[60]
    DIRECTION INPUT ;
    USE SIGNAL ;
    PORT
      LAYER M5 ;
        RECT  48.672 0 48.696 0.084 ;
    END
  END q[60]
  PIN q[61]
    DIRECTION INPUT ;
    USE SIGNAL ;
    PORT
      LAYER M5 ;
        RECT  48.768 0 48.792 0.084 ;
    END
  END q[61]
  PIN q[62]
    DIRECTION INPUT ;
    USE SIGNAL ;
    PORT
      LAYER M5 ;
        RECT  48.864 0 48.888 0.084 ;
    END
  END q[62]
  PIN q[63]
    DIRECTION INPUT ;
    USE SIGNAL ;
    PORT
      LAYER M5 ;
        RECT  48.96 0 48.984 0.084 ;
    END
  END q[63]
  PIN q[64]
    DIRECTION INPUT ;
    USE SIGNAL ;
    PORT
      LAYER M5 ;
        RECT  49.056 0 49.08 0.084 ;
    END
  END q[64]
  PIN q[65]
    DIRECTION INPUT ;
    USE SIGNAL ;
    PORT
      LAYER M5 ;
        RECT  49.152 0 49.176 0.084 ;
    END
  END q[65]
  PIN q[66]
    DIRECTION INPUT ;
    USE SIGNAL ;
    PORT
      LAYER M5 ;
        RECT  49.248 0 49.272 0.084 ;
    END
  END q[66]
  PIN q[67]
    DIRECTION INPUT ;
    USE SIGNAL ;
    PORT
      LAYER M5 ;
        RECT  49.344 0 49.368 0.084 ;
    END
  END q[67]
  PIN q[68]
    DIRECTION INPUT ;
    USE SIGNAL ;
    PORT
      LAYER M5 ;
        RECT  49.44 0 49.464 0.084 ;
    END
  END q[68]
  PIN q[69]
    DIRECTION INPUT ;
    USE SIGNAL ;
    PORT
      LAYER M5 ;
        RECT  49.536 0 49.56 0.084 ;
    END
  END q[69]
  PIN q[6]
    DIRECTION INPUT ;
    USE SIGNAL ;
    PORT
      LAYER M5 ;
        RECT  43.488 0 43.512 0.084 ;
    END
  END q[6]
  PIN q[70]
    DIRECTION INPUT ;
    USE SIGNAL ;
    PORT
      LAYER M5 ;
        RECT  49.632 0 49.656 0.084 ;
    END
  END q[70]
  PIN q[71]
    DIRECTION INPUT ;
    USE SIGNAL ;
    PORT
      LAYER M5 ;
        RECT  49.728 0 49.752 0.084 ;
    END
  END q[71]
  PIN q[72]
    DIRECTION INPUT ;
    USE SIGNAL ;
    PORT
      LAYER M5 ;
        RECT  49.824 0 49.848 0.084 ;
    END
  END q[72]
  PIN q[73]
    DIRECTION INPUT ;
    USE SIGNAL ;
    PORT
      LAYER M5 ;
        RECT  49.92 0 49.944 0.084 ;
    END
  END q[73]
  PIN q[74]
    DIRECTION INPUT ;
    USE SIGNAL ;
    PORT
      LAYER M5 ;
        RECT  50.016 0 50.04 0.084 ;
    END
  END q[74]
  PIN q[75]
    DIRECTION INPUT ;
    USE SIGNAL ;
    PORT
      LAYER M5 ;
        RECT  50.112 0 50.136 0.084 ;
    END
  END q[75]
  PIN q[76]
    DIRECTION INPUT ;
    USE SIGNAL ;
    PORT
      LAYER M5 ;
        RECT  50.208 0 50.232 0.084 ;
    END
  END q[76]
  PIN q[77]
    DIRECTION INPUT ;
    USE SIGNAL ;
    PORT
      LAYER M5 ;
        RECT  50.304 0 50.328 0.084 ;
    END
  END q[77]
  PIN q[78]
    DIRECTION INPUT ;
    USE SIGNAL ;
    PORT
      LAYER M5 ;
        RECT  50.4 0 50.424 0.084 ;
    END
  END q[78]
  PIN q[79]
    DIRECTION INPUT ;
    USE SIGNAL ;
    PORT
      LAYER M5 ;
        RECT  50.496 0 50.52 0.084 ;
    END
  END q[79]
  PIN q[7]
    DIRECTION INPUT ;
    USE SIGNAL ;
    PORT
      LAYER M5 ;
        RECT  43.584 0 43.608 0.084 ;
    END
  END q[7]
  PIN q[80]
    DIRECTION INPUT ;
    USE SIGNAL ;
    PORT
      LAYER M5 ;
        RECT  50.592 0 50.616 0.084 ;
    END
  END q[80]
  PIN q[81]
    DIRECTION INPUT ;
    USE SIGNAL ;
    PORT
      LAYER M5 ;
        RECT  50.688 0 50.712 0.084 ;
    END
  END q[81]
  PIN q[82]
    DIRECTION INPUT ;
    USE SIGNAL ;
    PORT
      LAYER M5 ;
        RECT  50.784 0 50.808 0.084 ;
    END
  END q[82]
  PIN q[83]
    DIRECTION INPUT ;
    USE SIGNAL ;
    PORT
      LAYER M5 ;
        RECT  50.88 0 50.904 0.084 ;
    END
  END q[83]
  PIN q[84]
    DIRECTION INPUT ;
    USE SIGNAL ;
    PORT
      LAYER M5 ;
        RECT  50.976 0 51 0.084 ;
    END
  END q[84]
  PIN q[85]
    DIRECTION INPUT ;
    USE SIGNAL ;
    PORT
      LAYER M5 ;
        RECT  51.072 0 51.096 0.084 ;
    END
  END q[85]
  PIN q[86]
    DIRECTION INPUT ;
    USE SIGNAL ;
    PORT
      LAYER M5 ;
        RECT  51.168 0 51.192 0.084 ;
    END
  END q[86]
  PIN q[87]
    DIRECTION INPUT ;
    USE SIGNAL ;
    PORT
      LAYER M5 ;
        RECT  51.264 0 51.288 0.084 ;
    END
  END q[87]
  PIN q[88]
    DIRECTION INPUT ;
    USE SIGNAL ;
    PORT
      LAYER M5 ;
        RECT  51.36 0 51.384 0.084 ;
    END
  END q[88]
  PIN q[89]
    DIRECTION INPUT ;
    USE SIGNAL ;
    PORT
      LAYER M5 ;
        RECT  51.456 0 51.48 0.084 ;
    END
  END q[89]
  PIN q[8]
    DIRECTION INPUT ;
    USE SIGNAL ;
    PORT
      LAYER M5 ;
        RECT  43.68 0 43.704 0.084 ;
    END
  END q[8]
  PIN q[90]
    DIRECTION INPUT ;
    USE SIGNAL ;
    PORT
      LAYER M5 ;
        RECT  51.552 0 51.576 0.084 ;
    END
  END q[90]
  PIN q[91]
    DIRECTION INPUT ;
    USE SIGNAL ;
    PORT
      LAYER M5 ;
        RECT  51.648 0 51.672 0.084 ;
    END
  END q[91]
  PIN q[92]
    DIRECTION INPUT ;
    USE SIGNAL ;
    PORT
      LAYER M5 ;
        RECT  51.744 0 51.768 0.084 ;
    END
  END q[92]
  PIN q[93]
    DIRECTION INPUT ;
    USE SIGNAL ;
    PORT
      LAYER M5 ;
        RECT  51.84 0 51.864 0.084 ;
    END
  END q[93]
  PIN q[94]
    DIRECTION INPUT ;
    USE SIGNAL ;
    PORT
      LAYER M5 ;
        RECT  51.936 0 51.96 0.084 ;
    END
  END q[94]
  PIN q[95]
    DIRECTION INPUT ;
    USE SIGNAL ;
    PORT
      LAYER M5 ;
        RECT  52.032 0 52.056 0.084 ;
    END
  END q[95]
  PIN q[96]
    DIRECTION INPUT ;
    USE SIGNAL ;
    PORT
      LAYER M5 ;
        RECT  52.128 0 52.152 0.084 ;
    END
  END q[96]
  PIN q[97]
    DIRECTION INPUT ;
    USE SIGNAL ;
    PORT
      LAYER M5 ;
        RECT  52.224 0 52.248 0.084 ;
    END
  END q[97]
  PIN q[98]
    DIRECTION INPUT ;
    USE SIGNAL ;
    PORT
      LAYER M5 ;
        RECT  52.32 0 52.344 0.084 ;
    END
  END q[98]
  PIN q[99]
    DIRECTION INPUT ;
    USE SIGNAL ;
    PORT
      LAYER M5 ;
        RECT  52.416 0 52.44 0.084 ;
    END
  END q[99]
  PIN q[9]
    DIRECTION INPUT ;
    USE SIGNAL ;
    PORT
      LAYER M5 ;
        RECT  43.776 0 43.8 0.084 ;
    END
  END q[9]
  PIN q_o[0]
    DIRECTION OUTPUT ;
    USE SIGNAL ;
    PORT
      LAYER M5 ;
        RECT  42.912 86.316 42.936 86.4 ;
    END
  END q_o[0]
  PIN q_o[100]
    DIRECTION OUTPUT ;
    USE SIGNAL ;
    PORT
      LAYER M5 ;
        RECT  52.512 86.316 52.536 86.4 ;
    END
  END q_o[100]
  PIN q_o[101]
    DIRECTION OUTPUT ;
    USE SIGNAL ;
    PORT
      LAYER M5 ;
        RECT  52.608 86.316 52.632 86.4 ;
    END
  END q_o[101]
  PIN q_o[102]
    DIRECTION OUTPUT ;
    USE SIGNAL ;
    PORT
      LAYER M5 ;
        RECT  52.704 86.316 52.728 86.4 ;
    END
  END q_o[102]
  PIN q_o[103]
    DIRECTION OUTPUT ;
    USE SIGNAL ;
    PORT
      LAYER M5 ;
        RECT  52.8 86.316 52.824 86.4 ;
    END
  END q_o[103]
  PIN q_o[104]
    DIRECTION OUTPUT ;
    USE SIGNAL ;
    PORT
      LAYER M5 ;
        RECT  52.896 86.316 52.92 86.4 ;
    END
  END q_o[104]
  PIN q_o[105]
    DIRECTION OUTPUT ;
    USE SIGNAL ;
    PORT
      LAYER M5 ;
        RECT  52.992 86.316 53.016 86.4 ;
    END
  END q_o[105]
  PIN q_o[106]
    DIRECTION OUTPUT ;
    USE SIGNAL ;
    PORT
      LAYER M5 ;
        RECT  53.088 86.316 53.112 86.4 ;
    END
  END q_o[106]
  PIN q_o[107]
    DIRECTION OUTPUT ;
    USE SIGNAL ;
    PORT
      LAYER M5 ;
        RECT  53.184 86.316 53.208 86.4 ;
    END
  END q_o[107]
  PIN q_o[108]
    DIRECTION OUTPUT ;
    USE SIGNAL ;
    PORT
      LAYER M5 ;
        RECT  53.28 86.316 53.304 86.4 ;
    END
  END q_o[108]
  PIN q_o[109]
    DIRECTION OUTPUT ;
    USE SIGNAL ;
    PORT
      LAYER M5 ;
        RECT  53.376 86.316 53.4 86.4 ;
    END
  END q_o[109]
  PIN q_o[10]
    DIRECTION OUTPUT ;
    USE SIGNAL ;
    PORT
      LAYER M5 ;
        RECT  43.872 86.316 43.896 86.4 ;
    END
  END q_o[10]
  PIN q_o[110]
    DIRECTION OUTPUT ;
    USE SIGNAL ;
    PORT
      LAYER M5 ;
        RECT  53.472 86.316 53.496 86.4 ;
    END
  END q_o[110]
  PIN q_o[111]
    DIRECTION OUTPUT ;
    USE SIGNAL ;
    PORT
      LAYER M5 ;
        RECT  53.568 86.316 53.592 86.4 ;
    END
  END q_o[111]
  PIN q_o[112]
    DIRECTION OUTPUT ;
    USE SIGNAL ;
    PORT
      LAYER M5 ;
        RECT  53.664 86.316 53.688 86.4 ;
    END
  END q_o[112]
  PIN q_o[113]
    DIRECTION OUTPUT ;
    USE SIGNAL ;
    PORT
      LAYER M5 ;
        RECT  53.76 86.316 53.784 86.4 ;
    END
  END q_o[113]
  PIN q_o[114]
    DIRECTION OUTPUT ;
    USE SIGNAL ;
    PORT
      LAYER M5 ;
        RECT  53.856 86.316 53.88 86.4 ;
    END
  END q_o[114]
  PIN q_o[115]
    DIRECTION OUTPUT ;
    USE SIGNAL ;
    PORT
      LAYER M5 ;
        RECT  53.952 86.316 53.976 86.4 ;
    END
  END q_o[115]
  PIN q_o[116]
    DIRECTION OUTPUT ;
    USE SIGNAL ;
    PORT
      LAYER M5 ;
        RECT  54.048 86.316 54.072 86.4 ;
    END
  END q_o[116]
  PIN q_o[117]
    DIRECTION OUTPUT ;
    USE SIGNAL ;
    PORT
      LAYER M5 ;
        RECT  54.144 86.316 54.168 86.4 ;
    END
  END q_o[117]
  PIN q_o[118]
    DIRECTION OUTPUT ;
    USE SIGNAL ;
    PORT
      LAYER M5 ;
        RECT  54.24 86.316 54.264 86.4 ;
    END
  END q_o[118]
  PIN q_o[119]
    DIRECTION OUTPUT ;
    USE SIGNAL ;
    PORT
      LAYER M5 ;
        RECT  54.336 86.316 54.36 86.4 ;
    END
  END q_o[119]
  PIN q_o[11]
    DIRECTION OUTPUT ;
    USE SIGNAL ;
    PORT
      LAYER M5 ;
        RECT  43.968 86.316 43.992 86.4 ;
    END
  END q_o[11]
  PIN q_o[120]
    DIRECTION OUTPUT ;
    USE SIGNAL ;
    PORT
      LAYER M5 ;
        RECT  54.432 86.316 54.456 86.4 ;
    END
  END q_o[120]
  PIN q_o[121]
    DIRECTION OUTPUT ;
    USE SIGNAL ;
    PORT
      LAYER M5 ;
        RECT  54.528 86.316 54.552 86.4 ;
    END
  END q_o[121]
  PIN q_o[122]
    DIRECTION OUTPUT ;
    USE SIGNAL ;
    PORT
      LAYER M5 ;
        RECT  54.624 86.316 54.648 86.4 ;
    END
  END q_o[122]
  PIN q_o[123]
    DIRECTION OUTPUT ;
    USE SIGNAL ;
    PORT
      LAYER M5 ;
        RECT  54.72 86.316 54.744 86.4 ;
    END
  END q_o[123]
  PIN q_o[124]
    DIRECTION OUTPUT ;
    USE SIGNAL ;
    PORT
      LAYER M5 ;
        RECT  54.816 86.316 54.84 86.4 ;
    END
  END q_o[124]
  PIN q_o[125]
    DIRECTION OUTPUT ;
    USE SIGNAL ;
    PORT
      LAYER M5 ;
        RECT  54.912 86.316 54.936 86.4 ;
    END
  END q_o[125]
  PIN q_o[126]
    DIRECTION OUTPUT ;
    USE SIGNAL ;
    PORT
      LAYER M5 ;
        RECT  55.008 86.316 55.032 86.4 ;
    END
  END q_o[126]
  PIN q_o[127]
    DIRECTION OUTPUT ;
    USE SIGNAL ;
    PORT
      LAYER M5 ;
        RECT  55.104 86.316 55.128 86.4 ;
    END
  END q_o[127]
  PIN q_o[128]
    DIRECTION OUTPUT ;
    USE SIGNAL ;
    PORT
      LAYER M5 ;
        RECT  55.2 86.316 55.224 86.4 ;
    END
  END q_o[128]
  PIN q_o[129]
    DIRECTION OUTPUT ;
    USE SIGNAL ;
    PORT
      LAYER M5 ;
        RECT  55.296 86.316 55.32 86.4 ;
    END
  END q_o[129]
  PIN q_o[12]
    DIRECTION OUTPUT ;
    USE SIGNAL ;
    PORT
      LAYER M5 ;
        RECT  44.064 86.316 44.088 86.4 ;
    END
  END q_o[12]
  PIN q_o[130]
    DIRECTION OUTPUT ;
    USE SIGNAL ;
    PORT
      LAYER M5 ;
        RECT  55.392 86.316 55.416 86.4 ;
    END
  END q_o[130]
  PIN q_o[131]
    DIRECTION OUTPUT ;
    USE SIGNAL ;
    PORT
      LAYER M5 ;
        RECT  55.488 86.316 55.512 86.4 ;
    END
  END q_o[131]
  PIN q_o[132]
    DIRECTION OUTPUT ;
    USE SIGNAL ;
    PORT
      LAYER M5 ;
        RECT  55.584 86.316 55.608 86.4 ;
    END
  END q_o[132]
  PIN q_o[133]
    DIRECTION OUTPUT ;
    USE SIGNAL ;
    PORT
      LAYER M5 ;
        RECT  55.68 86.316 55.704 86.4 ;
    END
  END q_o[133]
  PIN q_o[134]
    DIRECTION OUTPUT ;
    USE SIGNAL ;
    PORT
      LAYER M5 ;
        RECT  55.776 86.316 55.8 86.4 ;
    END
  END q_o[134]
  PIN q_o[135]
    DIRECTION OUTPUT ;
    USE SIGNAL ;
    PORT
      LAYER M5 ;
        RECT  55.872 86.316 55.896 86.4 ;
    END
  END q_o[135]
  PIN q_o[136]
    DIRECTION OUTPUT ;
    USE SIGNAL ;
    PORT
      LAYER M5 ;
        RECT  55.968 86.316 55.992 86.4 ;
    END
  END q_o[136]
  PIN q_o[137]
    DIRECTION OUTPUT ;
    USE SIGNAL ;
    PORT
      LAYER M5 ;
        RECT  56.064 86.316 56.088 86.4 ;
    END
  END q_o[137]
  PIN q_o[138]
    DIRECTION OUTPUT ;
    USE SIGNAL ;
    PORT
      LAYER M5 ;
        RECT  56.16 86.316 56.184 86.4 ;
    END
  END q_o[138]
  PIN q_o[139]
    DIRECTION OUTPUT ;
    USE SIGNAL ;
    PORT
      LAYER M5 ;
        RECT  56.256 86.316 56.28 86.4 ;
    END
  END q_o[139]
  PIN q_o[13]
    DIRECTION OUTPUT ;
    USE SIGNAL ;
    PORT
      LAYER M5 ;
        RECT  44.16 86.316 44.184 86.4 ;
    END
  END q_o[13]
  PIN q_o[140]
    DIRECTION OUTPUT ;
    USE SIGNAL ;
    PORT
      LAYER M5 ;
        RECT  56.352 86.316 56.376 86.4 ;
    END
  END q_o[140]
  PIN q_o[141]
    DIRECTION OUTPUT ;
    USE SIGNAL ;
    PORT
      LAYER M5 ;
        RECT  56.448 86.316 56.472 86.4 ;
    END
  END q_o[141]
  PIN q_o[142]
    DIRECTION OUTPUT ;
    USE SIGNAL ;
    PORT
      LAYER M5 ;
        RECT  56.544 86.316 56.568 86.4 ;
    END
  END q_o[142]
  PIN q_o[143]
    DIRECTION OUTPUT ;
    USE SIGNAL ;
    PORT
      LAYER M5 ;
        RECT  56.64 86.316 56.664 86.4 ;
    END
  END q_o[143]
  PIN q_o[144]
    DIRECTION OUTPUT ;
    USE SIGNAL ;
    PORT
      LAYER M5 ;
        RECT  56.736 86.316 56.76 86.4 ;
    END
  END q_o[144]
  PIN q_o[145]
    DIRECTION OUTPUT ;
    USE SIGNAL ;
    PORT
      LAYER M5 ;
        RECT  56.832 86.316 56.856 86.4 ;
    END
  END q_o[145]
  PIN q_o[146]
    DIRECTION OUTPUT ;
    USE SIGNAL ;
    PORT
      LAYER M5 ;
        RECT  56.928 86.316 56.952 86.4 ;
    END
  END q_o[146]
  PIN q_o[147]
    DIRECTION OUTPUT ;
    USE SIGNAL ;
    PORT
      LAYER M5 ;
        RECT  57.024 86.316 57.048 86.4 ;
    END
  END q_o[147]
  PIN q_o[148]
    DIRECTION OUTPUT ;
    USE SIGNAL ;
    PORT
      LAYER M5 ;
        RECT  57.12 86.316 57.144 86.4 ;
    END
  END q_o[148]
  PIN q_o[149]
    DIRECTION OUTPUT ;
    USE SIGNAL ;
    PORT
      LAYER M5 ;
        RECT  57.216 86.316 57.24 86.4 ;
    END
  END q_o[149]
  PIN q_o[14]
    DIRECTION OUTPUT ;
    USE SIGNAL ;
    PORT
      LAYER M5 ;
        RECT  44.256 86.316 44.28 86.4 ;
    END
  END q_o[14]
  PIN q_o[150]
    DIRECTION OUTPUT ;
    USE SIGNAL ;
    PORT
      LAYER M5 ;
        RECT  57.312 86.316 57.336 86.4 ;
    END
  END q_o[150]
  PIN q_o[151]
    DIRECTION OUTPUT ;
    USE SIGNAL ;
    PORT
      LAYER M5 ;
        RECT  57.408 86.316 57.432 86.4 ;
    END
  END q_o[151]
  PIN q_o[152]
    DIRECTION OUTPUT ;
    USE SIGNAL ;
    PORT
      LAYER M5 ;
        RECT  57.504 86.316 57.528 86.4 ;
    END
  END q_o[152]
  PIN q_o[153]
    DIRECTION OUTPUT ;
    USE SIGNAL ;
    PORT
      LAYER M5 ;
        RECT  57.6 86.316 57.624 86.4 ;
    END
  END q_o[153]
  PIN q_o[154]
    DIRECTION OUTPUT ;
    USE SIGNAL ;
    PORT
      LAYER M5 ;
        RECT  57.696 86.316 57.72 86.4 ;
    END
  END q_o[154]
  PIN q_o[155]
    DIRECTION OUTPUT ;
    USE SIGNAL ;
    PORT
      LAYER M5 ;
        RECT  57.792 86.316 57.816 86.4 ;
    END
  END q_o[155]
  PIN q_o[156]
    DIRECTION OUTPUT ;
    USE SIGNAL ;
    PORT
      LAYER M5 ;
        RECT  57.888 86.316 57.912 86.4 ;
    END
  END q_o[156]
  PIN q_o[157]
    DIRECTION OUTPUT ;
    USE SIGNAL ;
    PORT
      LAYER M5 ;
        RECT  57.984 86.316 58.008 86.4 ;
    END
  END q_o[157]
  PIN q_o[158]
    DIRECTION OUTPUT ;
    USE SIGNAL ;
    PORT
      LAYER M5 ;
        RECT  58.08 86.316 58.104 86.4 ;
    END
  END q_o[158]
  PIN q_o[159]
    DIRECTION OUTPUT ;
    USE SIGNAL ;
    PORT
      LAYER M5 ;
        RECT  58.176 86.316 58.2 86.4 ;
    END
  END q_o[159]
  PIN q_o[15]
    DIRECTION OUTPUT ;
    USE SIGNAL ;
    PORT
      LAYER M5 ;
        RECT  44.352 86.316 44.376 86.4 ;
    END
  END q_o[15]
  PIN q_o[160]
    DIRECTION OUTPUT ;
    USE SIGNAL ;
    PORT
      LAYER M5 ;
        RECT  58.272 86.316 58.296 86.4 ;
    END
  END q_o[160]
  PIN q_o[161]
    DIRECTION OUTPUT ;
    USE SIGNAL ;
    PORT
      LAYER M5 ;
        RECT  58.368 86.316 58.392 86.4 ;
    END
  END q_o[161]
  PIN q_o[162]
    DIRECTION OUTPUT ;
    USE SIGNAL ;
    PORT
      LAYER M5 ;
        RECT  58.464 86.316 58.488 86.4 ;
    END
  END q_o[162]
  PIN q_o[163]
    DIRECTION OUTPUT ;
    USE SIGNAL ;
    PORT
      LAYER M5 ;
        RECT  58.56 86.316 58.584 86.4 ;
    END
  END q_o[163]
  PIN q_o[164]
    DIRECTION OUTPUT ;
    USE SIGNAL ;
    PORT
      LAYER M5 ;
        RECT  58.656 86.316 58.68 86.4 ;
    END
  END q_o[164]
  PIN q_o[165]
    DIRECTION OUTPUT ;
    USE SIGNAL ;
    PORT
      LAYER M5 ;
        RECT  58.752 86.316 58.776 86.4 ;
    END
  END q_o[165]
  PIN q_o[166]
    DIRECTION OUTPUT ;
    USE SIGNAL ;
    PORT
      LAYER M5 ;
        RECT  58.848 86.316 58.872 86.4 ;
    END
  END q_o[166]
  PIN q_o[167]
    DIRECTION OUTPUT ;
    USE SIGNAL ;
    PORT
      LAYER M5 ;
        RECT  58.944 86.316 58.968 86.4 ;
    END
  END q_o[167]
  PIN q_o[168]
    DIRECTION OUTPUT ;
    USE SIGNAL ;
    PORT
      LAYER M5 ;
        RECT  59.04 86.316 59.064 86.4 ;
    END
  END q_o[168]
  PIN q_o[169]
    DIRECTION OUTPUT ;
    USE SIGNAL ;
    PORT
      LAYER M5 ;
        RECT  59.136 86.316 59.16 86.4 ;
    END
  END q_o[169]
  PIN q_o[16]
    DIRECTION OUTPUT ;
    USE SIGNAL ;
    PORT
      LAYER M5 ;
        RECT  44.448 86.316 44.472 86.4 ;
    END
  END q_o[16]
  PIN q_o[170]
    DIRECTION OUTPUT ;
    USE SIGNAL ;
    PORT
      LAYER M5 ;
        RECT  59.232 86.316 59.256 86.4 ;
    END
  END q_o[170]
  PIN q_o[171]
    DIRECTION OUTPUT ;
    USE SIGNAL ;
    PORT
      LAYER M5 ;
        RECT  59.328 86.316 59.352 86.4 ;
    END
  END q_o[171]
  PIN q_o[172]
    DIRECTION OUTPUT ;
    USE SIGNAL ;
    PORT
      LAYER M5 ;
        RECT  59.424 86.316 59.448 86.4 ;
    END
  END q_o[172]
  PIN q_o[173]
    DIRECTION OUTPUT ;
    USE SIGNAL ;
    PORT
      LAYER M5 ;
        RECT  59.52 86.316 59.544 86.4 ;
    END
  END q_o[173]
  PIN q_o[174]
    DIRECTION OUTPUT ;
    USE SIGNAL ;
    PORT
      LAYER M5 ;
        RECT  59.616 86.316 59.64 86.4 ;
    END
  END q_o[174]
  PIN q_o[175]
    DIRECTION OUTPUT ;
    USE SIGNAL ;
    PORT
      LAYER M5 ;
        RECT  59.712 86.316 59.736 86.4 ;
    END
  END q_o[175]
  PIN q_o[176]
    DIRECTION OUTPUT ;
    USE SIGNAL ;
    PORT
      LAYER M5 ;
        RECT  59.808 86.316 59.832 86.4 ;
    END
  END q_o[176]
  PIN q_o[177]
    DIRECTION OUTPUT ;
    USE SIGNAL ;
    PORT
      LAYER M5 ;
        RECT  59.904 86.316 59.928 86.4 ;
    END
  END q_o[177]
  PIN q_o[178]
    DIRECTION OUTPUT ;
    USE SIGNAL ;
    PORT
      LAYER M5 ;
        RECT  60 86.316 60.024 86.4 ;
    END
  END q_o[178]
  PIN q_o[179]
    DIRECTION OUTPUT ;
    USE SIGNAL ;
    PORT
      LAYER M5 ;
        RECT  60.096 86.316 60.12 86.4 ;
    END
  END q_o[179]
  PIN q_o[17]
    DIRECTION OUTPUT ;
    USE SIGNAL ;
    PORT
      LAYER M5 ;
        RECT  44.544 86.316 44.568 86.4 ;
    END
  END q_o[17]
  PIN q_o[180]
    DIRECTION OUTPUT ;
    USE SIGNAL ;
    PORT
      LAYER M5 ;
        RECT  60.192 86.316 60.216 86.4 ;
    END
  END q_o[180]
  PIN q_o[181]
    DIRECTION OUTPUT ;
    USE SIGNAL ;
    PORT
      LAYER M5 ;
        RECT  60.288 86.316 60.312 86.4 ;
    END
  END q_o[181]
  PIN q_o[182]
    DIRECTION OUTPUT ;
    USE SIGNAL ;
    PORT
      LAYER M5 ;
        RECT  60.384 86.316 60.408 86.4 ;
    END
  END q_o[182]
  PIN q_o[183]
    DIRECTION OUTPUT ;
    USE SIGNAL ;
    PORT
      LAYER M5 ;
        RECT  60.48 86.316 60.504 86.4 ;
    END
  END q_o[183]
  PIN q_o[184]
    DIRECTION OUTPUT ;
    USE SIGNAL ;
    PORT
      LAYER M5 ;
        RECT  60.576 86.316 60.6 86.4 ;
    END
  END q_o[184]
  PIN q_o[185]
    DIRECTION OUTPUT ;
    USE SIGNAL ;
    PORT
      LAYER M5 ;
        RECT  60.672 86.316 60.696 86.4 ;
    END
  END q_o[185]
  PIN q_o[186]
    DIRECTION OUTPUT ;
    USE SIGNAL ;
    PORT
      LAYER M5 ;
        RECT  60.768 86.316 60.792 86.4 ;
    END
  END q_o[186]
  PIN q_o[187]
    DIRECTION OUTPUT ;
    USE SIGNAL ;
    PORT
      LAYER M5 ;
        RECT  60.864 86.316 60.888 86.4 ;
    END
  END q_o[187]
  PIN q_o[188]
    DIRECTION OUTPUT ;
    USE SIGNAL ;
    PORT
      LAYER M5 ;
        RECT  60.96 86.316 60.984 86.4 ;
    END
  END q_o[188]
  PIN q_o[189]
    DIRECTION OUTPUT ;
    USE SIGNAL ;
    PORT
      LAYER M5 ;
        RECT  61.056 86.316 61.08 86.4 ;
    END
  END q_o[189]
  PIN q_o[18]
    DIRECTION OUTPUT ;
    USE SIGNAL ;
    PORT
      LAYER M5 ;
        RECT  44.64 86.316 44.664 86.4 ;
    END
  END q_o[18]
  PIN q_o[190]
    DIRECTION OUTPUT ;
    USE SIGNAL ;
    PORT
      LAYER M5 ;
        RECT  61.152 86.316 61.176 86.4 ;
    END
  END q_o[190]
  PIN q_o[191]
    DIRECTION OUTPUT ;
    USE SIGNAL ;
    PORT
      LAYER M5 ;
        RECT  61.248 86.316 61.272 86.4 ;
    END
  END q_o[191]
  PIN q_o[192]
    DIRECTION OUTPUT ;
    USE SIGNAL ;
    PORT
      LAYER M5 ;
        RECT  61.344 86.316 61.368 86.4 ;
    END
  END q_o[192]
  PIN q_o[193]
    DIRECTION OUTPUT ;
    USE SIGNAL ;
    PORT
      LAYER M5 ;
        RECT  61.44 86.316 61.464 86.4 ;
    END
  END q_o[193]
  PIN q_o[194]
    DIRECTION OUTPUT ;
    USE SIGNAL ;
    PORT
      LAYER M5 ;
        RECT  61.536 86.316 61.56 86.4 ;
    END
  END q_o[194]
  PIN q_o[195]
    DIRECTION OUTPUT ;
    USE SIGNAL ;
    PORT
      LAYER M5 ;
        RECT  61.632 86.316 61.656 86.4 ;
    END
  END q_o[195]
  PIN q_o[196]
    DIRECTION OUTPUT ;
    USE SIGNAL ;
    PORT
      LAYER M5 ;
        RECT  61.728 86.316 61.752 86.4 ;
    END
  END q_o[196]
  PIN q_o[197]
    DIRECTION OUTPUT ;
    USE SIGNAL ;
    PORT
      LAYER M5 ;
        RECT  61.824 86.316 61.848 86.4 ;
    END
  END q_o[197]
  PIN q_o[198]
    DIRECTION OUTPUT ;
    USE SIGNAL ;
    PORT
      LAYER M5 ;
        RECT  61.92 86.316 61.944 86.4 ;
    END
  END q_o[198]
  PIN q_o[199]
    DIRECTION OUTPUT ;
    USE SIGNAL ;
    PORT
      LAYER M5 ;
        RECT  62.016 86.316 62.04 86.4 ;
    END
  END q_o[199]
  PIN q_o[19]
    DIRECTION OUTPUT ;
    USE SIGNAL ;
    PORT
      LAYER M5 ;
        RECT  44.736 86.316 44.76 86.4 ;
    END
  END q_o[19]
  PIN q_o[1]
    DIRECTION OUTPUT ;
    USE SIGNAL ;
    PORT
      LAYER M5 ;
        RECT  43.008 86.316 43.032 86.4 ;
    END
  END q_o[1]
  PIN q_o[200]
    DIRECTION OUTPUT ;
    USE SIGNAL ;
    PORT
      LAYER M5 ;
        RECT  62.112 86.316 62.136 86.4 ;
    END
  END q_o[200]
  PIN q_o[201]
    DIRECTION OUTPUT ;
    USE SIGNAL ;
    PORT
      LAYER M5 ;
        RECT  62.208 86.316 62.232 86.4 ;
    END
  END q_o[201]
  PIN q_o[202]
    DIRECTION OUTPUT ;
    USE SIGNAL ;
    PORT
      LAYER M5 ;
        RECT  62.304 86.316 62.328 86.4 ;
    END
  END q_o[202]
  PIN q_o[203]
    DIRECTION OUTPUT ;
    USE SIGNAL ;
    PORT
      LAYER M5 ;
        RECT  62.4 86.316 62.424 86.4 ;
    END
  END q_o[203]
  PIN q_o[204]
    DIRECTION OUTPUT ;
    USE SIGNAL ;
    PORT
      LAYER M5 ;
        RECT  62.496 86.316 62.52 86.4 ;
    END
  END q_o[204]
  PIN q_o[205]
    DIRECTION OUTPUT ;
    USE SIGNAL ;
    PORT
      LAYER M5 ;
        RECT  62.592 86.316 62.616 86.4 ;
    END
  END q_o[205]
  PIN q_o[206]
    DIRECTION OUTPUT ;
    USE SIGNAL ;
    PORT
      LAYER M5 ;
        RECT  62.688 86.316 62.712 86.4 ;
    END
  END q_o[206]
  PIN q_o[207]
    DIRECTION OUTPUT ;
    USE SIGNAL ;
    PORT
      LAYER M5 ;
        RECT  62.784 86.316 62.808 86.4 ;
    END
  END q_o[207]
  PIN q_o[208]
    DIRECTION OUTPUT ;
    USE SIGNAL ;
    PORT
      LAYER M5 ;
        RECT  62.88 86.316 62.904 86.4 ;
    END
  END q_o[208]
  PIN q_o[209]
    DIRECTION OUTPUT ;
    USE SIGNAL ;
    PORT
      LAYER M5 ;
        RECT  62.976 86.316 63 86.4 ;
    END
  END q_o[209]
  PIN q_o[20]
    DIRECTION OUTPUT ;
    USE SIGNAL ;
    PORT
      LAYER M5 ;
        RECT  44.832 86.316 44.856 86.4 ;
    END
  END q_o[20]
  PIN q_o[210]
    DIRECTION OUTPUT ;
    USE SIGNAL ;
    PORT
      LAYER M5 ;
        RECT  63.072 86.316 63.096 86.4 ;
    END
  END q_o[210]
  PIN q_o[211]
    DIRECTION OUTPUT ;
    USE SIGNAL ;
    PORT
      LAYER M5 ;
        RECT  63.168 86.316 63.192 86.4 ;
    END
  END q_o[211]
  PIN q_o[212]
    DIRECTION OUTPUT ;
    USE SIGNAL ;
    PORT
      LAYER M5 ;
        RECT  63.264 86.316 63.288 86.4 ;
    END
  END q_o[212]
  PIN q_o[213]
    DIRECTION OUTPUT ;
    USE SIGNAL ;
    PORT
      LAYER M5 ;
        RECT  63.36 86.316 63.384 86.4 ;
    END
  END q_o[213]
  PIN q_o[214]
    DIRECTION OUTPUT ;
    USE SIGNAL ;
    PORT
      LAYER M5 ;
        RECT  63.456 86.316 63.48 86.4 ;
    END
  END q_o[214]
  PIN q_o[215]
    DIRECTION OUTPUT ;
    USE SIGNAL ;
    PORT
      LAYER M5 ;
        RECT  63.552 86.316 63.576 86.4 ;
    END
  END q_o[215]
  PIN q_o[216]
    DIRECTION OUTPUT ;
    USE SIGNAL ;
    PORT
      LAYER M5 ;
        RECT  63.648 86.316 63.672 86.4 ;
    END
  END q_o[216]
  PIN q_o[217]
    DIRECTION OUTPUT ;
    USE SIGNAL ;
    PORT
      LAYER M5 ;
        RECT  63.744 86.316 63.768 86.4 ;
    END
  END q_o[217]
  PIN q_o[218]
    DIRECTION OUTPUT ;
    USE SIGNAL ;
    PORT
      LAYER M5 ;
        RECT  63.84 86.316 63.864 86.4 ;
    END
  END q_o[218]
  PIN q_o[219]
    DIRECTION OUTPUT ;
    USE SIGNAL ;
    PORT
      LAYER M5 ;
        RECT  63.936 86.316 63.96 86.4 ;
    END
  END q_o[219]
  PIN q_o[21]
    DIRECTION OUTPUT ;
    USE SIGNAL ;
    PORT
      LAYER M5 ;
        RECT  44.928 86.316 44.952 86.4 ;
    END
  END q_o[21]
  PIN q_o[220]
    DIRECTION OUTPUT ;
    USE SIGNAL ;
    PORT
      LAYER M5 ;
        RECT  64.032 86.316 64.056 86.4 ;
    END
  END q_o[220]
  PIN q_o[221]
    DIRECTION OUTPUT ;
    USE SIGNAL ;
    PORT
      LAYER M5 ;
        RECT  64.128 86.316 64.152 86.4 ;
    END
  END q_o[221]
  PIN q_o[222]
    DIRECTION OUTPUT ;
    USE SIGNAL ;
    PORT
      LAYER M5 ;
        RECT  64.224 86.316 64.248 86.4 ;
    END
  END q_o[222]
  PIN q_o[223]
    DIRECTION OUTPUT ;
    USE SIGNAL ;
    PORT
      LAYER M5 ;
        RECT  64.32 86.316 64.344 86.4 ;
    END
  END q_o[223]
  PIN q_o[224]
    DIRECTION OUTPUT ;
    USE SIGNAL ;
    PORT
      LAYER M5 ;
        RECT  64.416 86.316 64.44 86.4 ;
    END
  END q_o[224]
  PIN q_o[225]
    DIRECTION OUTPUT ;
    USE SIGNAL ;
    PORT
      LAYER M5 ;
        RECT  64.512 86.316 64.536 86.4 ;
    END
  END q_o[225]
  PIN q_o[226]
    DIRECTION OUTPUT ;
    USE SIGNAL ;
    PORT
      LAYER M5 ;
        RECT  64.608 86.316 64.632 86.4 ;
    END
  END q_o[226]
  PIN q_o[227]
    DIRECTION OUTPUT ;
    USE SIGNAL ;
    PORT
      LAYER M5 ;
        RECT  64.704 86.316 64.728 86.4 ;
    END
  END q_o[227]
  PIN q_o[228]
    DIRECTION OUTPUT ;
    USE SIGNAL ;
    PORT
      LAYER M5 ;
        RECT  64.8 86.316 64.824 86.4 ;
    END
  END q_o[228]
  PIN q_o[229]
    DIRECTION OUTPUT ;
    USE SIGNAL ;
    PORT
      LAYER M5 ;
        RECT  64.896 86.316 64.92 86.4 ;
    END
  END q_o[229]
  PIN q_o[22]
    DIRECTION OUTPUT ;
    USE SIGNAL ;
    PORT
      LAYER M5 ;
        RECT  45.024 86.316 45.048 86.4 ;
    END
  END q_o[22]
  PIN q_o[230]
    DIRECTION OUTPUT ;
    USE SIGNAL ;
    PORT
      LAYER M5 ;
        RECT  64.992 86.316 65.016 86.4 ;
    END
  END q_o[230]
  PIN q_o[231]
    DIRECTION OUTPUT ;
    USE SIGNAL ;
    PORT
      LAYER M5 ;
        RECT  65.088 86.316 65.112 86.4 ;
    END
  END q_o[231]
  PIN q_o[232]
    DIRECTION OUTPUT ;
    USE SIGNAL ;
    PORT
      LAYER M5 ;
        RECT  65.184 86.316 65.208 86.4 ;
    END
  END q_o[232]
  PIN q_o[233]
    DIRECTION OUTPUT ;
    USE SIGNAL ;
    PORT
      LAYER M5 ;
        RECT  65.28 86.316 65.304 86.4 ;
    END
  END q_o[233]
  PIN q_o[234]
    DIRECTION OUTPUT ;
    USE SIGNAL ;
    PORT
      LAYER M5 ;
        RECT  65.376 86.316 65.4 86.4 ;
    END
  END q_o[234]
  PIN q_o[235]
    DIRECTION OUTPUT ;
    USE SIGNAL ;
    PORT
      LAYER M5 ;
        RECT  65.472 86.316 65.496 86.4 ;
    END
  END q_o[235]
  PIN q_o[236]
    DIRECTION OUTPUT ;
    USE SIGNAL ;
    PORT
      LAYER M5 ;
        RECT  65.568 86.316 65.592 86.4 ;
    END
  END q_o[236]
  PIN q_o[237]
    DIRECTION OUTPUT ;
    USE SIGNAL ;
    PORT
      LAYER M5 ;
        RECT  65.664 86.316 65.688 86.4 ;
    END
  END q_o[237]
  PIN q_o[238]
    DIRECTION OUTPUT ;
    USE SIGNAL ;
    PORT
      LAYER M5 ;
        RECT  65.76 86.316 65.784 86.4 ;
    END
  END q_o[238]
  PIN q_o[239]
    DIRECTION OUTPUT ;
    USE SIGNAL ;
    PORT
      LAYER M5 ;
        RECT  65.856 86.316 65.88 86.4 ;
    END
  END q_o[239]
  PIN q_o[23]
    DIRECTION OUTPUT ;
    USE SIGNAL ;
    PORT
      LAYER M5 ;
        RECT  45.12 86.316 45.144 86.4 ;
    END
  END q_o[23]
  PIN q_o[240]
    DIRECTION OUTPUT ;
    USE SIGNAL ;
    PORT
      LAYER M5 ;
        RECT  65.952 86.316 65.976 86.4 ;
    END
  END q_o[240]
  PIN q_o[241]
    DIRECTION OUTPUT ;
    USE SIGNAL ;
    PORT
      LAYER M5 ;
        RECT  66.048 86.316 66.072 86.4 ;
    END
  END q_o[241]
  PIN q_o[242]
    DIRECTION OUTPUT ;
    USE SIGNAL ;
    PORT
      LAYER M5 ;
        RECT  66.144 86.316 66.168 86.4 ;
    END
  END q_o[242]
  PIN q_o[243]
    DIRECTION OUTPUT ;
    USE SIGNAL ;
    PORT
      LAYER M5 ;
        RECT  66.24 86.316 66.264 86.4 ;
    END
  END q_o[243]
  PIN q_o[244]
    DIRECTION OUTPUT ;
    USE SIGNAL ;
    PORT
      LAYER M5 ;
        RECT  66.336 86.316 66.36 86.4 ;
    END
  END q_o[244]
  PIN q_o[245]
    DIRECTION OUTPUT ;
    USE SIGNAL ;
    PORT
      LAYER M5 ;
        RECT  66.432 86.316 66.456 86.4 ;
    END
  END q_o[245]
  PIN q_o[246]
    DIRECTION OUTPUT ;
    USE SIGNAL ;
    PORT
      LAYER M5 ;
        RECT  66.528 86.316 66.552 86.4 ;
    END
  END q_o[246]
  PIN q_o[247]
    DIRECTION OUTPUT ;
    USE SIGNAL ;
    PORT
      LAYER M5 ;
        RECT  66.624 86.316 66.648 86.4 ;
    END
  END q_o[247]
  PIN q_o[248]
    DIRECTION OUTPUT ;
    USE SIGNAL ;
    PORT
      LAYER M5 ;
        RECT  66.72 86.316 66.744 86.4 ;
    END
  END q_o[248]
  PIN q_o[249]
    DIRECTION OUTPUT ;
    USE SIGNAL ;
    PORT
      LAYER M5 ;
        RECT  66.816 86.316 66.84 86.4 ;
    END
  END q_o[249]
  PIN q_o[24]
    DIRECTION OUTPUT ;
    USE SIGNAL ;
    PORT
      LAYER M5 ;
        RECT  45.216 86.316 45.24 86.4 ;
    END
  END q_o[24]
  PIN q_o[250]
    DIRECTION OUTPUT ;
    USE SIGNAL ;
    PORT
      LAYER M5 ;
        RECT  66.912 86.316 66.936 86.4 ;
    END
  END q_o[250]
  PIN q_o[251]
    DIRECTION OUTPUT ;
    USE SIGNAL ;
    PORT
      LAYER M5 ;
        RECT  67.008 86.316 67.032 86.4 ;
    END
  END q_o[251]
  PIN q_o[252]
    DIRECTION OUTPUT ;
    USE SIGNAL ;
    PORT
      LAYER M5 ;
        RECT  67.104 86.316 67.128 86.4 ;
    END
  END q_o[252]
  PIN q_o[253]
    DIRECTION OUTPUT ;
    USE SIGNAL ;
    PORT
      LAYER M5 ;
        RECT  67.2 86.316 67.224 86.4 ;
    END
  END q_o[253]
  PIN q_o[254]
    DIRECTION OUTPUT ;
    USE SIGNAL ;
    PORT
      LAYER M5 ;
        RECT  67.296 86.316 67.32 86.4 ;
    END
  END q_o[254]
  PIN q_o[255]
    DIRECTION OUTPUT ;
    USE SIGNAL ;
    PORT
      LAYER M5 ;
        RECT  67.392 86.316 67.416 86.4 ;
    END
  END q_o[255]
  PIN q_o[256]
    DIRECTION OUTPUT ;
    USE SIGNAL ;
    PORT
      LAYER M5 ;
        RECT  67.488 86.316 67.512 86.4 ;
    END
  END q_o[256]
  PIN q_o[257]
    DIRECTION OUTPUT ;
    USE SIGNAL ;
    PORT
      LAYER M5 ;
        RECT  67.584 86.316 67.608 86.4 ;
    END
  END q_o[257]
  PIN q_o[258]
    DIRECTION OUTPUT ;
    USE SIGNAL ;
    PORT
      LAYER M5 ;
        RECT  67.68 86.316 67.704 86.4 ;
    END
  END q_o[258]
  PIN q_o[259]
    DIRECTION OUTPUT ;
    USE SIGNAL ;
    PORT
      LAYER M5 ;
        RECT  67.776 86.316 67.8 86.4 ;
    END
  END q_o[259]
  PIN q_o[25]
    DIRECTION OUTPUT ;
    USE SIGNAL ;
    PORT
      LAYER M5 ;
        RECT  45.312 86.316 45.336 86.4 ;
    END
  END q_o[25]
  PIN q_o[260]
    DIRECTION OUTPUT ;
    USE SIGNAL ;
    PORT
      LAYER M5 ;
        RECT  67.872 86.316 67.896 86.4 ;
    END
  END q_o[260]
  PIN q_o[261]
    DIRECTION OUTPUT ;
    USE SIGNAL ;
    PORT
      LAYER M5 ;
        RECT  67.968 86.316 67.992 86.4 ;
    END
  END q_o[261]
  PIN q_o[262]
    DIRECTION OUTPUT ;
    USE SIGNAL ;
    PORT
      LAYER M5 ;
        RECT  68.064 86.316 68.088 86.4 ;
    END
  END q_o[262]
  PIN q_o[263]
    DIRECTION OUTPUT ;
    USE SIGNAL ;
    PORT
      LAYER M5 ;
        RECT  68.16 86.316 68.184 86.4 ;
    END
  END q_o[263]
  PIN q_o[264]
    DIRECTION OUTPUT ;
    USE SIGNAL ;
    PORT
      LAYER M5 ;
        RECT  68.256 86.316 68.28 86.4 ;
    END
  END q_o[264]
  PIN q_o[265]
    DIRECTION OUTPUT ;
    USE SIGNAL ;
    PORT
      LAYER M5 ;
        RECT  68.352 86.316 68.376 86.4 ;
    END
  END q_o[265]
  PIN q_o[266]
    DIRECTION OUTPUT ;
    USE SIGNAL ;
    PORT
      LAYER M5 ;
        RECT  68.448 86.316 68.472 86.4 ;
    END
  END q_o[266]
  PIN q_o[267]
    DIRECTION OUTPUT ;
    USE SIGNAL ;
    PORT
      LAYER M5 ;
        RECT  68.544 86.316 68.568 86.4 ;
    END
  END q_o[267]
  PIN q_o[268]
    DIRECTION OUTPUT ;
    USE SIGNAL ;
    PORT
      LAYER M5 ;
        RECT  68.64 86.316 68.664 86.4 ;
    END
  END q_o[268]
  PIN q_o[269]
    DIRECTION OUTPUT ;
    USE SIGNAL ;
    PORT
      LAYER M5 ;
        RECT  68.736 86.316 68.76 86.4 ;
    END
  END q_o[269]
  PIN q_o[26]
    DIRECTION OUTPUT ;
    USE SIGNAL ;
    PORT
      LAYER M5 ;
        RECT  45.408 86.316 45.432 86.4 ;
    END
  END q_o[26]
  PIN q_o[270]
    DIRECTION OUTPUT ;
    USE SIGNAL ;
    PORT
      LAYER M5 ;
        RECT  68.832 86.316 68.856 86.4 ;
    END
  END q_o[270]
  PIN q_o[271]
    DIRECTION OUTPUT ;
    USE SIGNAL ;
    PORT
      LAYER M5 ;
        RECT  68.928 86.316 68.952 86.4 ;
    END
  END q_o[271]
  PIN q_o[272]
    DIRECTION OUTPUT ;
    USE SIGNAL ;
    PORT
      LAYER M5 ;
        RECT  69.024 86.316 69.048 86.4 ;
    END
  END q_o[272]
  PIN q_o[273]
    DIRECTION OUTPUT ;
    USE SIGNAL ;
    PORT
      LAYER M5 ;
        RECT  69.12 86.316 69.144 86.4 ;
    END
  END q_o[273]
  PIN q_o[274]
    DIRECTION OUTPUT ;
    USE SIGNAL ;
    PORT
      LAYER M5 ;
        RECT  69.216 86.316 69.24 86.4 ;
    END
  END q_o[274]
  PIN q_o[275]
    DIRECTION OUTPUT ;
    USE SIGNAL ;
    PORT
      LAYER M5 ;
        RECT  69.312 86.316 69.336 86.4 ;
    END
  END q_o[275]
  PIN q_o[276]
    DIRECTION OUTPUT ;
    USE SIGNAL ;
    PORT
      LAYER M5 ;
        RECT  69.408 86.316 69.432 86.4 ;
    END
  END q_o[276]
  PIN q_o[277]
    DIRECTION OUTPUT ;
    USE SIGNAL ;
    PORT
      LAYER M5 ;
        RECT  69.504 86.316 69.528 86.4 ;
    END
  END q_o[277]
  PIN q_o[278]
    DIRECTION OUTPUT ;
    USE SIGNAL ;
    PORT
      LAYER M5 ;
        RECT  69.6 86.316 69.624 86.4 ;
    END
  END q_o[278]
  PIN q_o[279]
    DIRECTION OUTPUT ;
    USE SIGNAL ;
    PORT
      LAYER M5 ;
        RECT  69.696 86.316 69.72 86.4 ;
    END
  END q_o[279]
  PIN q_o[27]
    DIRECTION OUTPUT ;
    USE SIGNAL ;
    PORT
      LAYER M5 ;
        RECT  45.504 86.316 45.528 86.4 ;
    END
  END q_o[27]
  PIN q_o[280]
    DIRECTION OUTPUT ;
    USE SIGNAL ;
    PORT
      LAYER M5 ;
        RECT  69.792 86.316 69.816 86.4 ;
    END
  END q_o[280]
  PIN q_o[281]
    DIRECTION OUTPUT ;
    USE SIGNAL ;
    PORT
      LAYER M5 ;
        RECT  69.888 86.316 69.912 86.4 ;
    END
  END q_o[281]
  PIN q_o[282]
    DIRECTION OUTPUT ;
    USE SIGNAL ;
    PORT
      LAYER M5 ;
        RECT  69.984 86.316 70.008 86.4 ;
    END
  END q_o[282]
  PIN q_o[283]
    DIRECTION OUTPUT ;
    USE SIGNAL ;
    PORT
      LAYER M5 ;
        RECT  70.08 86.316 70.104 86.4 ;
    END
  END q_o[283]
  PIN q_o[284]
    DIRECTION OUTPUT ;
    USE SIGNAL ;
    PORT
      LAYER M5 ;
        RECT  70.176 86.316 70.2 86.4 ;
    END
  END q_o[284]
  PIN q_o[285]
    DIRECTION OUTPUT ;
    USE SIGNAL ;
    PORT
      LAYER M5 ;
        RECT  70.272 86.316 70.296 86.4 ;
    END
  END q_o[285]
  PIN q_o[286]
    DIRECTION OUTPUT ;
    USE SIGNAL ;
    PORT
      LAYER M5 ;
        RECT  70.368 86.316 70.392 86.4 ;
    END
  END q_o[286]
  PIN q_o[287]
    DIRECTION OUTPUT ;
    USE SIGNAL ;
    PORT
      LAYER M5 ;
        RECT  70.464 86.316 70.488 86.4 ;
    END
  END q_o[287]
  PIN q_o[288]
    DIRECTION OUTPUT ;
    USE SIGNAL ;
    PORT
      LAYER M5 ;
        RECT  70.56 86.316 70.584 86.4 ;
    END
  END q_o[288]
  PIN q_o[289]
    DIRECTION OUTPUT ;
    USE SIGNAL ;
    PORT
      LAYER M5 ;
        RECT  70.656 86.316 70.68 86.4 ;
    END
  END q_o[289]
  PIN q_o[28]
    DIRECTION OUTPUT ;
    USE SIGNAL ;
    PORT
      LAYER M5 ;
        RECT  45.6 86.316 45.624 86.4 ;
    END
  END q_o[28]
  PIN q_o[290]
    DIRECTION OUTPUT ;
    USE SIGNAL ;
    PORT
      LAYER M5 ;
        RECT  70.752 86.316 70.776 86.4 ;
    END
  END q_o[290]
  PIN q_o[291]
    DIRECTION OUTPUT ;
    USE SIGNAL ;
    PORT
      LAYER M5 ;
        RECT  70.848 86.316 70.872 86.4 ;
    END
  END q_o[291]
  PIN q_o[292]
    DIRECTION OUTPUT ;
    USE SIGNAL ;
    PORT
      LAYER M5 ;
        RECT  70.944 86.316 70.968 86.4 ;
    END
  END q_o[292]
  PIN q_o[293]
    DIRECTION OUTPUT ;
    USE SIGNAL ;
    PORT
      LAYER M5 ;
        RECT  71.04 86.316 71.064 86.4 ;
    END
  END q_o[293]
  PIN q_o[294]
    DIRECTION OUTPUT ;
    USE SIGNAL ;
    PORT
      LAYER M5 ;
        RECT  71.136 86.316 71.16 86.4 ;
    END
  END q_o[294]
  PIN q_o[295]
    DIRECTION OUTPUT ;
    USE SIGNAL ;
    PORT
      LAYER M5 ;
        RECT  71.232 86.316 71.256 86.4 ;
    END
  END q_o[295]
  PIN q_o[296]
    DIRECTION OUTPUT ;
    USE SIGNAL ;
    PORT
      LAYER M5 ;
        RECT  71.328 86.316 71.352 86.4 ;
    END
  END q_o[296]
  PIN q_o[297]
    DIRECTION OUTPUT ;
    USE SIGNAL ;
    PORT
      LAYER M5 ;
        RECT  71.424 86.316 71.448 86.4 ;
    END
  END q_o[297]
  PIN q_o[298]
    DIRECTION OUTPUT ;
    USE SIGNAL ;
    PORT
      LAYER M5 ;
        RECT  71.52 86.316 71.544 86.4 ;
    END
  END q_o[298]
  PIN q_o[299]
    DIRECTION OUTPUT ;
    USE SIGNAL ;
    PORT
      LAYER M5 ;
        RECT  71.616 86.316 71.64 86.4 ;
    END
  END q_o[299]
  PIN q_o[29]
    DIRECTION OUTPUT ;
    USE SIGNAL ;
    PORT
      LAYER M5 ;
        RECT  45.696 86.316 45.72 86.4 ;
    END
  END q_o[29]
  PIN q_o[2]
    DIRECTION OUTPUT ;
    USE SIGNAL ;
    PORT
      LAYER M5 ;
        RECT  43.104 86.316 43.128 86.4 ;
    END
  END q_o[2]
  PIN q_o[300]
    DIRECTION OUTPUT ;
    USE SIGNAL ;
    PORT
      LAYER M5 ;
        RECT  71.712 86.316 71.736 86.4 ;
    END
  END q_o[300]
  PIN q_o[301]
    DIRECTION OUTPUT ;
    USE SIGNAL ;
    PORT
      LAYER M5 ;
        RECT  71.808 86.316 71.832 86.4 ;
    END
  END q_o[301]
  PIN q_o[302]
    DIRECTION OUTPUT ;
    USE SIGNAL ;
    PORT
      LAYER M5 ;
        RECT  71.904 86.316 71.928 86.4 ;
    END
  END q_o[302]
  PIN q_o[303]
    DIRECTION OUTPUT ;
    USE SIGNAL ;
    PORT
      LAYER M5 ;
        RECT  72 86.316 72.024 86.4 ;
    END
  END q_o[303]
  PIN q_o[304]
    DIRECTION OUTPUT ;
    USE SIGNAL ;
    PORT
      LAYER M5 ;
        RECT  72.096 86.316 72.12 86.4 ;
    END
  END q_o[304]
  PIN q_o[305]
    DIRECTION OUTPUT ;
    USE SIGNAL ;
    PORT
      LAYER M5 ;
        RECT  72.192 86.316 72.216 86.4 ;
    END
  END q_o[305]
  PIN q_o[306]
    DIRECTION OUTPUT ;
    USE SIGNAL ;
    PORT
      LAYER M5 ;
        RECT  72.288 86.316 72.312 86.4 ;
    END
  END q_o[306]
  PIN q_o[307]
    DIRECTION OUTPUT ;
    USE SIGNAL ;
    PORT
      LAYER M5 ;
        RECT  72.384 86.316 72.408 86.4 ;
    END
  END q_o[307]
  PIN q_o[308]
    DIRECTION OUTPUT ;
    USE SIGNAL ;
    PORT
      LAYER M5 ;
        RECT  72.48 86.316 72.504 86.4 ;
    END
  END q_o[308]
  PIN q_o[309]
    DIRECTION OUTPUT ;
    USE SIGNAL ;
    PORT
      LAYER M5 ;
        RECT  72.576 86.316 72.6 86.4 ;
    END
  END q_o[309]
  PIN q_o[30]
    DIRECTION OUTPUT ;
    USE SIGNAL ;
    PORT
      LAYER M5 ;
        RECT  45.792 86.316 45.816 86.4 ;
    END
  END q_o[30]
  PIN q_o[310]
    DIRECTION OUTPUT ;
    USE SIGNAL ;
    PORT
      LAYER M5 ;
        RECT  72.672 86.316 72.696 86.4 ;
    END
  END q_o[310]
  PIN q_o[311]
    DIRECTION OUTPUT ;
    USE SIGNAL ;
    PORT
      LAYER M5 ;
        RECT  72.768 86.316 72.792 86.4 ;
    END
  END q_o[311]
  PIN q_o[312]
    DIRECTION OUTPUT ;
    USE SIGNAL ;
    PORT
      LAYER M5 ;
        RECT  72.864 86.316 72.888 86.4 ;
    END
  END q_o[312]
  PIN q_o[313]
    DIRECTION OUTPUT ;
    USE SIGNAL ;
    PORT
      LAYER M5 ;
        RECT  72.96 86.316 72.984 86.4 ;
    END
  END q_o[313]
  PIN q_o[314]
    DIRECTION OUTPUT ;
    USE SIGNAL ;
    PORT
      LAYER M5 ;
        RECT  73.056 86.316 73.08 86.4 ;
    END
  END q_o[314]
  PIN q_o[315]
    DIRECTION OUTPUT ;
    USE SIGNAL ;
    PORT
      LAYER M5 ;
        RECT  73.152 86.316 73.176 86.4 ;
    END
  END q_o[315]
  PIN q_o[316]
    DIRECTION OUTPUT ;
    USE SIGNAL ;
    PORT
      LAYER M5 ;
        RECT  73.248 86.316 73.272 86.4 ;
    END
  END q_o[316]
  PIN q_o[317]
    DIRECTION OUTPUT ;
    USE SIGNAL ;
    PORT
      LAYER M5 ;
        RECT  73.344 86.316 73.368 86.4 ;
    END
  END q_o[317]
  PIN q_o[318]
    DIRECTION OUTPUT ;
    USE SIGNAL ;
    PORT
      LAYER M5 ;
        RECT  73.44 86.316 73.464 86.4 ;
    END
  END q_o[318]
  PIN q_o[319]
    DIRECTION OUTPUT ;
    USE SIGNAL ;
    PORT
      LAYER M5 ;
        RECT  73.536 86.316 73.56 86.4 ;
    END
  END q_o[319]
  PIN q_o[31]
    DIRECTION OUTPUT ;
    USE SIGNAL ;
    PORT
      LAYER M5 ;
        RECT  45.888 86.316 45.912 86.4 ;
    END
  END q_o[31]
  PIN q_o[320]
    DIRECTION OUTPUT ;
    USE SIGNAL ;
    PORT
      LAYER M5 ;
        RECT  73.632 86.316 73.656 86.4 ;
    END
  END q_o[320]
  PIN q_o[321]
    DIRECTION OUTPUT ;
    USE SIGNAL ;
    PORT
      LAYER M5 ;
        RECT  73.728 86.316 73.752 86.4 ;
    END
  END q_o[321]
  PIN q_o[322]
    DIRECTION OUTPUT ;
    USE SIGNAL ;
    PORT
      LAYER M5 ;
        RECT  73.824 86.316 73.848 86.4 ;
    END
  END q_o[322]
  PIN q_o[323]
    DIRECTION OUTPUT ;
    USE SIGNAL ;
    PORT
      LAYER M5 ;
        RECT  73.92 86.316 73.944 86.4 ;
    END
  END q_o[323]
  PIN q_o[324]
    DIRECTION OUTPUT ;
    USE SIGNAL ;
    PORT
      LAYER M5 ;
        RECT  74.016 86.316 74.04 86.4 ;
    END
  END q_o[324]
  PIN q_o[325]
    DIRECTION OUTPUT ;
    USE SIGNAL ;
    PORT
      LAYER M5 ;
        RECT  74.112 86.316 74.136 86.4 ;
    END
  END q_o[325]
  PIN q_o[326]
    DIRECTION OUTPUT ;
    USE SIGNAL ;
    PORT
      LAYER M5 ;
        RECT  74.208 86.316 74.232 86.4 ;
    END
  END q_o[326]
  PIN q_o[327]
    DIRECTION OUTPUT ;
    USE SIGNAL ;
    PORT
      LAYER M5 ;
        RECT  74.304 86.316 74.328 86.4 ;
    END
  END q_o[327]
  PIN q_o[328]
    DIRECTION OUTPUT ;
    USE SIGNAL ;
    PORT
      LAYER M5 ;
        RECT  74.4 86.316 74.424 86.4 ;
    END
  END q_o[328]
  PIN q_o[329]
    DIRECTION OUTPUT ;
    USE SIGNAL ;
    PORT
      LAYER M5 ;
        RECT  74.496 86.316 74.52 86.4 ;
    END
  END q_o[329]
  PIN q_o[32]
    DIRECTION OUTPUT ;
    USE SIGNAL ;
    PORT
      LAYER M5 ;
        RECT  45.984 86.316 46.008 86.4 ;
    END
  END q_o[32]
  PIN q_o[330]
    DIRECTION OUTPUT ;
    USE SIGNAL ;
    PORT
      LAYER M5 ;
        RECT  74.592 86.316 74.616 86.4 ;
    END
  END q_o[330]
  PIN q_o[331]
    DIRECTION OUTPUT ;
    USE SIGNAL ;
    PORT
      LAYER M5 ;
        RECT  74.688 86.316 74.712 86.4 ;
    END
  END q_o[331]
  PIN q_o[332]
    DIRECTION OUTPUT ;
    USE SIGNAL ;
    PORT
      LAYER M5 ;
        RECT  74.784 86.316 74.808 86.4 ;
    END
  END q_o[332]
  PIN q_o[333]
    DIRECTION OUTPUT ;
    USE SIGNAL ;
    PORT
      LAYER M5 ;
        RECT  74.88 86.316 74.904 86.4 ;
    END
  END q_o[333]
  PIN q_o[334]
    DIRECTION OUTPUT ;
    USE SIGNAL ;
    PORT
      LAYER M5 ;
        RECT  74.976 86.316 75 86.4 ;
    END
  END q_o[334]
  PIN q_o[335]
    DIRECTION OUTPUT ;
    USE SIGNAL ;
    PORT
      LAYER M5 ;
        RECT  75.072 86.316 75.096 86.4 ;
    END
  END q_o[335]
  PIN q_o[336]
    DIRECTION OUTPUT ;
    USE SIGNAL ;
    PORT
      LAYER M5 ;
        RECT  75.168 86.316 75.192 86.4 ;
    END
  END q_o[336]
  PIN q_o[337]
    DIRECTION OUTPUT ;
    USE SIGNAL ;
    PORT
      LAYER M5 ;
        RECT  75.264 86.316 75.288 86.4 ;
    END
  END q_o[337]
  PIN q_o[338]
    DIRECTION OUTPUT ;
    USE SIGNAL ;
    PORT
      LAYER M5 ;
        RECT  75.36 86.316 75.384 86.4 ;
    END
  END q_o[338]
  PIN q_o[339]
    DIRECTION OUTPUT ;
    USE SIGNAL ;
    PORT
      LAYER M5 ;
        RECT  75.456 86.316 75.48 86.4 ;
    END
  END q_o[339]
  PIN q_o[33]
    DIRECTION OUTPUT ;
    USE SIGNAL ;
    PORT
      LAYER M5 ;
        RECT  46.08 86.316 46.104 86.4 ;
    END
  END q_o[33]
  PIN q_o[340]
    DIRECTION OUTPUT ;
    USE SIGNAL ;
    PORT
      LAYER M5 ;
        RECT  75.552 86.316 75.576 86.4 ;
    END
  END q_o[340]
  PIN q_o[341]
    DIRECTION OUTPUT ;
    USE SIGNAL ;
    PORT
      LAYER M5 ;
        RECT  75.648 86.316 75.672 86.4 ;
    END
  END q_o[341]
  PIN q_o[342]
    DIRECTION OUTPUT ;
    USE SIGNAL ;
    PORT
      LAYER M5 ;
        RECT  75.744 86.316 75.768 86.4 ;
    END
  END q_o[342]
  PIN q_o[343]
    DIRECTION OUTPUT ;
    USE SIGNAL ;
    PORT
      LAYER M5 ;
        RECT  75.84 86.316 75.864 86.4 ;
    END
  END q_o[343]
  PIN q_o[344]
    DIRECTION OUTPUT ;
    USE SIGNAL ;
    PORT
      LAYER M5 ;
        RECT  75.936 86.316 75.96 86.4 ;
    END
  END q_o[344]
  PIN q_o[345]
    DIRECTION OUTPUT ;
    USE SIGNAL ;
    PORT
      LAYER M5 ;
        RECT  76.032 86.316 76.056 86.4 ;
    END
  END q_o[345]
  PIN q_o[346]
    DIRECTION OUTPUT ;
    USE SIGNAL ;
    PORT
      LAYER M5 ;
        RECT  76.128 86.316 76.152 86.4 ;
    END
  END q_o[346]
  PIN q_o[347]
    DIRECTION OUTPUT ;
    USE SIGNAL ;
    PORT
      LAYER M5 ;
        RECT  76.224 86.316 76.248 86.4 ;
    END
  END q_o[347]
  PIN q_o[348]
    DIRECTION OUTPUT ;
    USE SIGNAL ;
    PORT
      LAYER M5 ;
        RECT  76.32 86.316 76.344 86.4 ;
    END
  END q_o[348]
  PIN q_o[349]
    DIRECTION OUTPUT ;
    USE SIGNAL ;
    PORT
      LAYER M5 ;
        RECT  76.416 86.316 76.44 86.4 ;
    END
  END q_o[349]
  PIN q_o[34]
    DIRECTION OUTPUT ;
    USE SIGNAL ;
    PORT
      LAYER M5 ;
        RECT  46.176 86.316 46.2 86.4 ;
    END
  END q_o[34]
  PIN q_o[350]
    DIRECTION OUTPUT ;
    USE SIGNAL ;
    PORT
      LAYER M5 ;
        RECT  76.512 86.316 76.536 86.4 ;
    END
  END q_o[350]
  PIN q_o[351]
    DIRECTION OUTPUT ;
    USE SIGNAL ;
    PORT
      LAYER M5 ;
        RECT  76.608 86.316 76.632 86.4 ;
    END
  END q_o[351]
  PIN q_o[352]
    DIRECTION OUTPUT ;
    USE SIGNAL ;
    PORT
      LAYER M5 ;
        RECT  76.704 86.316 76.728 86.4 ;
    END
  END q_o[352]
  PIN q_o[353]
    DIRECTION OUTPUT ;
    USE SIGNAL ;
    PORT
      LAYER M5 ;
        RECT  76.8 86.316 76.824 86.4 ;
    END
  END q_o[353]
  PIN q_o[354]
    DIRECTION OUTPUT ;
    USE SIGNAL ;
    PORT
      LAYER M5 ;
        RECT  76.896 86.316 76.92 86.4 ;
    END
  END q_o[354]
  PIN q_o[355]
    DIRECTION OUTPUT ;
    USE SIGNAL ;
    PORT
      LAYER M5 ;
        RECT  76.992 86.316 77.016 86.4 ;
    END
  END q_o[355]
  PIN q_o[356]
    DIRECTION OUTPUT ;
    USE SIGNAL ;
    PORT
      LAYER M5 ;
        RECT  77.088 86.316 77.112 86.4 ;
    END
  END q_o[356]
  PIN q_o[357]
    DIRECTION OUTPUT ;
    USE SIGNAL ;
    PORT
      LAYER M5 ;
        RECT  77.184 86.316 77.208 86.4 ;
    END
  END q_o[357]
  PIN q_o[358]
    DIRECTION OUTPUT ;
    USE SIGNAL ;
    PORT
      LAYER M5 ;
        RECT  77.28 86.316 77.304 86.4 ;
    END
  END q_o[358]
  PIN q_o[359]
    DIRECTION OUTPUT ;
    USE SIGNAL ;
    PORT
      LAYER M5 ;
        RECT  77.376 86.316 77.4 86.4 ;
    END
  END q_o[359]
  PIN q_o[35]
    DIRECTION OUTPUT ;
    USE SIGNAL ;
    PORT
      LAYER M5 ;
        RECT  46.272 86.316 46.296 86.4 ;
    END
  END q_o[35]
  PIN q_o[360]
    DIRECTION OUTPUT ;
    USE SIGNAL ;
    PORT
      LAYER M5 ;
        RECT  77.472 86.316 77.496 86.4 ;
    END
  END q_o[360]
  PIN q_o[361]
    DIRECTION OUTPUT ;
    USE SIGNAL ;
    PORT
      LAYER M5 ;
        RECT  77.568 86.316 77.592 86.4 ;
    END
  END q_o[361]
  PIN q_o[362]
    DIRECTION OUTPUT ;
    USE SIGNAL ;
    PORT
      LAYER M5 ;
        RECT  77.664 86.316 77.688 86.4 ;
    END
  END q_o[362]
  PIN q_o[363]
    DIRECTION OUTPUT ;
    USE SIGNAL ;
    PORT
      LAYER M5 ;
        RECT  77.76 86.316 77.784 86.4 ;
    END
  END q_o[363]
  PIN q_o[364]
    DIRECTION OUTPUT ;
    USE SIGNAL ;
    PORT
      LAYER M5 ;
        RECT  77.856 86.316 77.88 86.4 ;
    END
  END q_o[364]
  PIN q_o[365]
    DIRECTION OUTPUT ;
    USE SIGNAL ;
    PORT
      LAYER M5 ;
        RECT  77.952 86.316 77.976 86.4 ;
    END
  END q_o[365]
  PIN q_o[366]
    DIRECTION OUTPUT ;
    USE SIGNAL ;
    PORT
      LAYER M5 ;
        RECT  78.048 86.316 78.072 86.4 ;
    END
  END q_o[366]
  PIN q_o[367]
    DIRECTION OUTPUT ;
    USE SIGNAL ;
    PORT
      LAYER M5 ;
        RECT  78.144 86.316 78.168 86.4 ;
    END
  END q_o[367]
  PIN q_o[368]
    DIRECTION OUTPUT ;
    USE SIGNAL ;
    PORT
      LAYER M5 ;
        RECT  78.24 86.316 78.264 86.4 ;
    END
  END q_o[368]
  PIN q_o[369]
    DIRECTION OUTPUT ;
    USE SIGNAL ;
    PORT
      LAYER M5 ;
        RECT  78.336 86.316 78.36 86.4 ;
    END
  END q_o[369]
  PIN q_o[36]
    DIRECTION OUTPUT ;
    USE SIGNAL ;
    PORT
      LAYER M5 ;
        RECT  46.368 86.316 46.392 86.4 ;
    END
  END q_o[36]
  PIN q_o[370]
    DIRECTION OUTPUT ;
    USE SIGNAL ;
    PORT
      LAYER M5 ;
        RECT  78.432 86.316 78.456 86.4 ;
    END
  END q_o[370]
  PIN q_o[371]
    DIRECTION OUTPUT ;
    USE SIGNAL ;
    PORT
      LAYER M5 ;
        RECT  78.528 86.316 78.552 86.4 ;
    END
  END q_o[371]
  PIN q_o[372]
    DIRECTION OUTPUT ;
    USE SIGNAL ;
    PORT
      LAYER M5 ;
        RECT  78.624 86.316 78.648 86.4 ;
    END
  END q_o[372]
  PIN q_o[373]
    DIRECTION OUTPUT ;
    USE SIGNAL ;
    PORT
      LAYER M5 ;
        RECT  78.72 86.316 78.744 86.4 ;
    END
  END q_o[373]
  PIN q_o[374]
    DIRECTION OUTPUT ;
    USE SIGNAL ;
    PORT
      LAYER M5 ;
        RECT  78.816 86.316 78.84 86.4 ;
    END
  END q_o[374]
  PIN q_o[375]
    DIRECTION OUTPUT ;
    USE SIGNAL ;
    PORT
      LAYER M5 ;
        RECT  78.912 86.316 78.936 86.4 ;
    END
  END q_o[375]
  PIN q_o[376]
    DIRECTION OUTPUT ;
    USE SIGNAL ;
    PORT
      LAYER M5 ;
        RECT  79.008 86.316 79.032 86.4 ;
    END
  END q_o[376]
  PIN q_o[377]
    DIRECTION OUTPUT ;
    USE SIGNAL ;
    PORT
      LAYER M5 ;
        RECT  79.104 86.316 79.128 86.4 ;
    END
  END q_o[377]
  PIN q_o[378]
    DIRECTION OUTPUT ;
    USE SIGNAL ;
    PORT
      LAYER M5 ;
        RECT  79.2 86.316 79.224 86.4 ;
    END
  END q_o[378]
  PIN q_o[379]
    DIRECTION OUTPUT ;
    USE SIGNAL ;
    PORT
      LAYER M5 ;
        RECT  79.296 86.316 79.32 86.4 ;
    END
  END q_o[379]
  PIN q_o[37]
    DIRECTION OUTPUT ;
    USE SIGNAL ;
    PORT
      LAYER M5 ;
        RECT  46.464 86.316 46.488 86.4 ;
    END
  END q_o[37]
  PIN q_o[380]
    DIRECTION OUTPUT ;
    USE SIGNAL ;
    PORT
      LAYER M5 ;
        RECT  79.392 86.316 79.416 86.4 ;
    END
  END q_o[380]
  PIN q_o[381]
    DIRECTION OUTPUT ;
    USE SIGNAL ;
    PORT
      LAYER M5 ;
        RECT  79.488 86.316 79.512 86.4 ;
    END
  END q_o[381]
  PIN q_o[382]
    DIRECTION OUTPUT ;
    USE SIGNAL ;
    PORT
      LAYER M5 ;
        RECT  79.584 86.316 79.608 86.4 ;
    END
  END q_o[382]
  PIN q_o[383]
    DIRECTION OUTPUT ;
    USE SIGNAL ;
    PORT
      LAYER M5 ;
        RECT  79.68 86.316 79.704 86.4 ;
    END
  END q_o[383]
  PIN q_o[384]
    DIRECTION OUTPUT ;
    USE SIGNAL ;
    PORT
      LAYER M5 ;
        RECT  79.776 86.316 79.8 86.4 ;
    END
  END q_o[384]
  PIN q_o[385]
    DIRECTION OUTPUT ;
    USE SIGNAL ;
    PORT
      LAYER M5 ;
        RECT  79.872 86.316 79.896 86.4 ;
    END
  END q_o[385]
  PIN q_o[386]
    DIRECTION OUTPUT ;
    USE SIGNAL ;
    PORT
      LAYER M5 ;
        RECT  79.968 86.316 79.992 86.4 ;
    END
  END q_o[386]
  PIN q_o[387]
    DIRECTION OUTPUT ;
    USE SIGNAL ;
    PORT
      LAYER M5 ;
        RECT  80.064 86.316 80.088 86.4 ;
    END
  END q_o[387]
  PIN q_o[388]
    DIRECTION OUTPUT ;
    USE SIGNAL ;
    PORT
      LAYER M5 ;
        RECT  80.16 86.316 80.184 86.4 ;
    END
  END q_o[388]
  PIN q_o[389]
    DIRECTION OUTPUT ;
    USE SIGNAL ;
    PORT
      LAYER M5 ;
        RECT  80.256 86.316 80.28 86.4 ;
    END
  END q_o[389]
  PIN q_o[38]
    DIRECTION OUTPUT ;
    USE SIGNAL ;
    PORT
      LAYER M5 ;
        RECT  46.56 86.316 46.584 86.4 ;
    END
  END q_o[38]
  PIN q_o[390]
    DIRECTION OUTPUT ;
    USE SIGNAL ;
    PORT
      LAYER M5 ;
        RECT  80.352 86.316 80.376 86.4 ;
    END
  END q_o[390]
  PIN q_o[391]
    DIRECTION OUTPUT ;
    USE SIGNAL ;
    PORT
      LAYER M5 ;
        RECT  80.448 86.316 80.472 86.4 ;
    END
  END q_o[391]
  PIN q_o[392]
    DIRECTION OUTPUT ;
    USE SIGNAL ;
    PORT
      LAYER M5 ;
        RECT  80.544 86.316 80.568 86.4 ;
    END
  END q_o[392]
  PIN q_o[393]
    DIRECTION OUTPUT ;
    USE SIGNAL ;
    PORT
      LAYER M5 ;
        RECT  80.64 86.316 80.664 86.4 ;
    END
  END q_o[393]
  PIN q_o[394]
    DIRECTION OUTPUT ;
    USE SIGNAL ;
    PORT
      LAYER M5 ;
        RECT  80.736 86.316 80.76 86.4 ;
    END
  END q_o[394]
  PIN q_o[395]
    DIRECTION OUTPUT ;
    USE SIGNAL ;
    PORT
      LAYER M5 ;
        RECT  80.832 86.316 80.856 86.4 ;
    END
  END q_o[395]
  PIN q_o[396]
    DIRECTION OUTPUT ;
    USE SIGNAL ;
    PORT
      LAYER M5 ;
        RECT  80.928 86.316 80.952 86.4 ;
    END
  END q_o[396]
  PIN q_o[397]
    DIRECTION OUTPUT ;
    USE SIGNAL ;
    PORT
      LAYER M5 ;
        RECT  81.024 86.316 81.048 86.4 ;
    END
  END q_o[397]
  PIN q_o[398]
    DIRECTION OUTPUT ;
    USE SIGNAL ;
    PORT
      LAYER M5 ;
        RECT  81.12 86.316 81.144 86.4 ;
    END
  END q_o[398]
  PIN q_o[399]
    DIRECTION OUTPUT ;
    USE SIGNAL ;
    PORT
      LAYER M5 ;
        RECT  81.216 86.316 81.24 86.4 ;
    END
  END q_o[399]
  PIN q_o[39]
    DIRECTION OUTPUT ;
    USE SIGNAL ;
    PORT
      LAYER M5 ;
        RECT  46.656 86.316 46.68 86.4 ;
    END
  END q_o[39]
  PIN q_o[3]
    DIRECTION OUTPUT ;
    USE SIGNAL ;
    PORT
      LAYER M5 ;
        RECT  43.2 86.316 43.224 86.4 ;
    END
  END q_o[3]
  PIN q_o[400]
    DIRECTION OUTPUT ;
    USE SIGNAL ;
    PORT
      LAYER M5 ;
        RECT  81.312 86.316 81.336 86.4 ;
    END
  END q_o[400]
  PIN q_o[401]
    DIRECTION OUTPUT ;
    USE SIGNAL ;
    PORT
      LAYER M5 ;
        RECT  81.408 86.316 81.432 86.4 ;
    END
  END q_o[401]
  PIN q_o[402]
    DIRECTION OUTPUT ;
    USE SIGNAL ;
    PORT
      LAYER M5 ;
        RECT  81.504 86.316 81.528 86.4 ;
    END
  END q_o[402]
  PIN q_o[403]
    DIRECTION OUTPUT ;
    USE SIGNAL ;
    PORT
      LAYER M5 ;
        RECT  81.6 86.316 81.624 86.4 ;
    END
  END q_o[403]
  PIN q_o[404]
    DIRECTION OUTPUT ;
    USE SIGNAL ;
    PORT
      LAYER M5 ;
        RECT  81.696 86.316 81.72 86.4 ;
    END
  END q_o[404]
  PIN q_o[405]
    DIRECTION OUTPUT ;
    USE SIGNAL ;
    PORT
      LAYER M5 ;
        RECT  81.792 86.316 81.816 86.4 ;
    END
  END q_o[405]
  PIN q_o[406]
    DIRECTION OUTPUT ;
    USE SIGNAL ;
    PORT
      LAYER M5 ;
        RECT  81.888 86.316 81.912 86.4 ;
    END
  END q_o[406]
  PIN q_o[407]
    DIRECTION OUTPUT ;
    USE SIGNAL ;
    PORT
      LAYER M5 ;
        RECT  81.984 86.316 82.008 86.4 ;
    END
  END q_o[407]
  PIN q_o[408]
    DIRECTION OUTPUT ;
    USE SIGNAL ;
    PORT
      LAYER M5 ;
        RECT  82.08 86.316 82.104 86.4 ;
    END
  END q_o[408]
  PIN q_o[409]
    DIRECTION OUTPUT ;
    USE SIGNAL ;
    PORT
      LAYER M5 ;
        RECT  82.176 86.316 82.2 86.4 ;
    END
  END q_o[409]
  PIN q_o[40]
    DIRECTION OUTPUT ;
    USE SIGNAL ;
    PORT
      LAYER M5 ;
        RECT  46.752 86.316 46.776 86.4 ;
    END
  END q_o[40]
  PIN q_o[410]
    DIRECTION OUTPUT ;
    USE SIGNAL ;
    PORT
      LAYER M5 ;
        RECT  82.272 86.316 82.296 86.4 ;
    END
  END q_o[410]
  PIN q_o[411]
    DIRECTION OUTPUT ;
    USE SIGNAL ;
    PORT
      LAYER M5 ;
        RECT  82.368 86.316 82.392 86.4 ;
    END
  END q_o[411]
  PIN q_o[412]
    DIRECTION OUTPUT ;
    USE SIGNAL ;
    PORT
      LAYER M5 ;
        RECT  82.464 86.316 82.488 86.4 ;
    END
  END q_o[412]
  PIN q_o[413]
    DIRECTION OUTPUT ;
    USE SIGNAL ;
    PORT
      LAYER M5 ;
        RECT  82.56 86.316 82.584 86.4 ;
    END
  END q_o[413]
  PIN q_o[414]
    DIRECTION OUTPUT ;
    USE SIGNAL ;
    PORT
      LAYER M5 ;
        RECT  82.656 86.316 82.68 86.4 ;
    END
  END q_o[414]
  PIN q_o[415]
    DIRECTION OUTPUT ;
    USE SIGNAL ;
    PORT
      LAYER M5 ;
        RECT  82.752 86.316 82.776 86.4 ;
    END
  END q_o[415]
  PIN q_o[416]
    DIRECTION OUTPUT ;
    USE SIGNAL ;
    PORT
      LAYER M5 ;
        RECT  82.848 86.316 82.872 86.4 ;
    END
  END q_o[416]
  PIN q_o[417]
    DIRECTION OUTPUT ;
    USE SIGNAL ;
    PORT
      LAYER M5 ;
        RECT  82.944 86.316 82.968 86.4 ;
    END
  END q_o[417]
  PIN q_o[418]
    DIRECTION OUTPUT ;
    USE SIGNAL ;
    PORT
      LAYER M5 ;
        RECT  83.04 86.316 83.064 86.4 ;
    END
  END q_o[418]
  PIN q_o[419]
    DIRECTION OUTPUT ;
    USE SIGNAL ;
    PORT
      LAYER M5 ;
        RECT  83.136 86.316 83.16 86.4 ;
    END
  END q_o[419]
  PIN q_o[41]
    DIRECTION OUTPUT ;
    USE SIGNAL ;
    PORT
      LAYER M5 ;
        RECT  46.848 86.316 46.872 86.4 ;
    END
  END q_o[41]
  PIN q_o[420]
    DIRECTION OUTPUT ;
    USE SIGNAL ;
    PORT
      LAYER M5 ;
        RECT  83.232 86.316 83.256 86.4 ;
    END
  END q_o[420]
  PIN q_o[421]
    DIRECTION OUTPUT ;
    USE SIGNAL ;
    PORT
      LAYER M5 ;
        RECT  83.328 86.316 83.352 86.4 ;
    END
  END q_o[421]
  PIN q_o[422]
    DIRECTION OUTPUT ;
    USE SIGNAL ;
    PORT
      LAYER M5 ;
        RECT  83.424 86.316 83.448 86.4 ;
    END
  END q_o[422]
  PIN q_o[423]
    DIRECTION OUTPUT ;
    USE SIGNAL ;
    PORT
      LAYER M5 ;
        RECT  83.52 86.316 83.544 86.4 ;
    END
  END q_o[423]
  PIN q_o[424]
    DIRECTION OUTPUT ;
    USE SIGNAL ;
    PORT
      LAYER M5 ;
        RECT  83.616 86.316 83.64 86.4 ;
    END
  END q_o[424]
  PIN q_o[425]
    DIRECTION OUTPUT ;
    USE SIGNAL ;
    PORT
      LAYER M5 ;
        RECT  83.712 86.316 83.736 86.4 ;
    END
  END q_o[425]
  PIN q_o[426]
    DIRECTION OUTPUT ;
    USE SIGNAL ;
    PORT
      LAYER M5 ;
        RECT  83.808 86.316 83.832 86.4 ;
    END
  END q_o[426]
  PIN q_o[427]
    DIRECTION OUTPUT ;
    USE SIGNAL ;
    PORT
      LAYER M5 ;
        RECT  83.904 86.316 83.928 86.4 ;
    END
  END q_o[427]
  PIN q_o[428]
    DIRECTION OUTPUT ;
    USE SIGNAL ;
    PORT
      LAYER M5 ;
        RECT  84 86.316 84.024 86.4 ;
    END
  END q_o[428]
  PIN q_o[429]
    DIRECTION OUTPUT ;
    USE SIGNAL ;
    PORT
      LAYER M5 ;
        RECT  84.096 86.316 84.12 86.4 ;
    END
  END q_o[429]
  PIN q_o[42]
    DIRECTION OUTPUT ;
    USE SIGNAL ;
    PORT
      LAYER M5 ;
        RECT  46.944 86.316 46.968 86.4 ;
    END
  END q_o[42]
  PIN q_o[430]
    DIRECTION OUTPUT ;
    USE SIGNAL ;
    PORT
      LAYER M5 ;
        RECT  84.192 86.316 84.216 86.4 ;
    END
  END q_o[430]
  PIN q_o[431]
    DIRECTION OUTPUT ;
    USE SIGNAL ;
    PORT
      LAYER M5 ;
        RECT  84.288 86.316 84.312 86.4 ;
    END
  END q_o[431]
  PIN q_o[432]
    DIRECTION OUTPUT ;
    USE SIGNAL ;
    PORT
      LAYER M5 ;
        RECT  84.384 86.316 84.408 86.4 ;
    END
  END q_o[432]
  PIN q_o[433]
    DIRECTION OUTPUT ;
    USE SIGNAL ;
    PORT
      LAYER M5 ;
        RECT  84.48 86.316 84.504 86.4 ;
    END
  END q_o[433]
  PIN q_o[434]
    DIRECTION OUTPUT ;
    USE SIGNAL ;
    PORT
      LAYER M5 ;
        RECT  84.576 86.316 84.6 86.4 ;
    END
  END q_o[434]
  PIN q_o[435]
    DIRECTION OUTPUT ;
    USE SIGNAL ;
    PORT
      LAYER M5 ;
        RECT  84.672 86.316 84.696 86.4 ;
    END
  END q_o[435]
  PIN q_o[436]
    DIRECTION OUTPUT ;
    USE SIGNAL ;
    PORT
      LAYER M5 ;
        RECT  84.768 86.316 84.792 86.4 ;
    END
  END q_o[436]
  PIN q_o[437]
    DIRECTION OUTPUT ;
    USE SIGNAL ;
    PORT
      LAYER M5 ;
        RECT  84.864 86.316 84.888 86.4 ;
    END
  END q_o[437]
  PIN q_o[438]
    DIRECTION OUTPUT ;
    USE SIGNAL ;
    PORT
      LAYER M5 ;
        RECT  84.96 86.316 84.984 86.4 ;
    END
  END q_o[438]
  PIN q_o[439]
    DIRECTION OUTPUT ;
    USE SIGNAL ;
    PORT
      LAYER M5 ;
        RECT  85.056 86.316 85.08 86.4 ;
    END
  END q_o[439]
  PIN q_o[43]
    DIRECTION OUTPUT ;
    USE SIGNAL ;
    PORT
      LAYER M5 ;
        RECT  47.04 86.316 47.064 86.4 ;
    END
  END q_o[43]
  PIN q_o[440]
    DIRECTION OUTPUT ;
    USE SIGNAL ;
    PORT
      LAYER M5 ;
        RECT  85.152 86.316 85.176 86.4 ;
    END
  END q_o[440]
  PIN q_o[441]
    DIRECTION OUTPUT ;
    USE SIGNAL ;
    PORT
      LAYER M5 ;
        RECT  85.248 86.316 85.272 86.4 ;
    END
  END q_o[441]
  PIN q_o[442]
    DIRECTION OUTPUT ;
    USE SIGNAL ;
    PORT
      LAYER M5 ;
        RECT  85.344 86.316 85.368 86.4 ;
    END
  END q_o[442]
  PIN q_o[443]
    DIRECTION OUTPUT ;
    USE SIGNAL ;
    PORT
      LAYER M5 ;
        RECT  85.44 86.316 85.464 86.4 ;
    END
  END q_o[443]
  PIN q_o[444]
    DIRECTION OUTPUT ;
    USE SIGNAL ;
    PORT
      LAYER M5 ;
        RECT  85.536 86.316 85.56 86.4 ;
    END
  END q_o[444]
  PIN q_o[445]
    DIRECTION OUTPUT ;
    USE SIGNAL ;
    PORT
      LAYER M5 ;
        RECT  85.632 86.316 85.656 86.4 ;
    END
  END q_o[445]
  PIN q_o[446]
    DIRECTION OUTPUT ;
    USE SIGNAL ;
    PORT
      LAYER M5 ;
        RECT  85.728 86.316 85.752 86.4 ;
    END
  END q_o[446]
  PIN q_o[447]
    DIRECTION OUTPUT ;
    USE SIGNAL ;
    PORT
      LAYER M5 ;
        RECT  85.824 86.316 85.848 86.4 ;
    END
  END q_o[447]
  PIN q_o[448]
    DIRECTION OUTPUT ;
    USE SIGNAL ;
    PORT
      LAYER M5 ;
        RECT  85.92 86.316 85.944 86.4 ;
    END
  END q_o[448]
  PIN q_o[449]
    DIRECTION OUTPUT ;
    USE SIGNAL ;
    PORT
      LAYER M5 ;
        RECT  86.016 86.316 86.04 86.4 ;
    END
  END q_o[449]
  PIN q_o[44]
    DIRECTION OUTPUT ;
    USE SIGNAL ;
    PORT
      LAYER M5 ;
        RECT  47.136 86.316 47.16 86.4 ;
    END
  END q_o[44]
  PIN q_o[450]
    DIRECTION OUTPUT ;
    USE SIGNAL ;
    PORT
      LAYER M5 ;
        RECT  86.112 86.316 86.136 86.4 ;
    END
  END q_o[450]
  PIN q_o[451]
    DIRECTION OUTPUT ;
    USE SIGNAL ;
    PORT
      LAYER M5 ;
        RECT  86.208 86.316 86.232 86.4 ;
    END
  END q_o[451]
  PIN q_o[452]
    DIRECTION OUTPUT ;
    USE SIGNAL ;
    PORT
      LAYER M5 ;
        RECT  86.304 86.316 86.328 86.4 ;
    END
  END q_o[452]
  PIN q_o[453]
    DIRECTION OUTPUT ;
    USE SIGNAL ;
    PORT
      LAYER M5 ;
        RECT  86.4 86.316 86.424 86.4 ;
    END
  END q_o[453]
  PIN q_o[454]
    DIRECTION OUTPUT ;
    USE SIGNAL ;
    PORT
      LAYER M5 ;
        RECT  86.496 86.316 86.52 86.4 ;
    END
  END q_o[454]
  PIN q_o[455]
    DIRECTION OUTPUT ;
    USE SIGNAL ;
    PORT
      LAYER M5 ;
        RECT  86.592 86.316 86.616 86.4 ;
    END
  END q_o[455]
  PIN q_o[456]
    DIRECTION OUTPUT ;
    USE SIGNAL ;
    PORT
      LAYER M5 ;
        RECT  86.688 86.316 86.712 86.4 ;
    END
  END q_o[456]
  PIN q_o[457]
    DIRECTION OUTPUT ;
    USE SIGNAL ;
    PORT
      LAYER M5 ;
        RECT  86.784 86.316 86.808 86.4 ;
    END
  END q_o[457]
  PIN q_o[458]
    DIRECTION OUTPUT ;
    USE SIGNAL ;
    PORT
      LAYER M5 ;
        RECT  86.88 86.316 86.904 86.4 ;
    END
  END q_o[458]
  PIN q_o[459]
    DIRECTION OUTPUT ;
    USE SIGNAL ;
    PORT
      LAYER M5 ;
        RECT  86.976 86.316 87 86.4 ;
    END
  END q_o[459]
  PIN q_o[45]
    DIRECTION OUTPUT ;
    USE SIGNAL ;
    PORT
      LAYER M5 ;
        RECT  47.232 86.316 47.256 86.4 ;
    END
  END q_o[45]
  PIN q_o[460]
    DIRECTION OUTPUT ;
    USE SIGNAL ;
    PORT
      LAYER M5 ;
        RECT  87.072 86.316 87.096 86.4 ;
    END
  END q_o[460]
  PIN q_o[461]
    DIRECTION OUTPUT ;
    USE SIGNAL ;
    PORT
      LAYER M5 ;
        RECT  87.168 86.316 87.192 86.4 ;
    END
  END q_o[461]
  PIN q_o[462]
    DIRECTION OUTPUT ;
    USE SIGNAL ;
    PORT
      LAYER M5 ;
        RECT  87.264 86.316 87.288 86.4 ;
    END
  END q_o[462]
  PIN q_o[463]
    DIRECTION OUTPUT ;
    USE SIGNAL ;
    PORT
      LAYER M5 ;
        RECT  87.36 86.316 87.384 86.4 ;
    END
  END q_o[463]
  PIN q_o[464]
    DIRECTION OUTPUT ;
    USE SIGNAL ;
    PORT
      LAYER M5 ;
        RECT  87.456 86.316 87.48 86.4 ;
    END
  END q_o[464]
  PIN q_o[465]
    DIRECTION OUTPUT ;
    USE SIGNAL ;
    PORT
      LAYER M5 ;
        RECT  87.552 86.316 87.576 86.4 ;
    END
  END q_o[465]
  PIN q_o[466]
    DIRECTION OUTPUT ;
    USE SIGNAL ;
    PORT
      LAYER M5 ;
        RECT  87.648 86.316 87.672 86.4 ;
    END
  END q_o[466]
  PIN q_o[467]
    DIRECTION OUTPUT ;
    USE SIGNAL ;
    PORT
      LAYER M5 ;
        RECT  87.744 86.316 87.768 86.4 ;
    END
  END q_o[467]
  PIN q_o[468]
    DIRECTION OUTPUT ;
    USE SIGNAL ;
    PORT
      LAYER M5 ;
        RECT  87.84 86.316 87.864 86.4 ;
    END
  END q_o[468]
  PIN q_o[469]
    DIRECTION OUTPUT ;
    USE SIGNAL ;
    PORT
      LAYER M5 ;
        RECT  87.936 86.316 87.96 86.4 ;
    END
  END q_o[469]
  PIN q_o[46]
    DIRECTION OUTPUT ;
    USE SIGNAL ;
    PORT
      LAYER M5 ;
        RECT  47.328 86.316 47.352 86.4 ;
    END
  END q_o[46]
  PIN q_o[470]
    DIRECTION OUTPUT ;
    USE SIGNAL ;
    PORT
      LAYER M5 ;
        RECT  88.032 86.316 88.056 86.4 ;
    END
  END q_o[470]
  PIN q_o[471]
    DIRECTION OUTPUT ;
    USE SIGNAL ;
    PORT
      LAYER M5 ;
        RECT  88.128 86.316 88.152 86.4 ;
    END
  END q_o[471]
  PIN q_o[472]
    DIRECTION OUTPUT ;
    USE SIGNAL ;
    PORT
      LAYER M5 ;
        RECT  88.224 86.316 88.248 86.4 ;
    END
  END q_o[472]
  PIN q_o[473]
    DIRECTION OUTPUT ;
    USE SIGNAL ;
    PORT
      LAYER M5 ;
        RECT  88.32 86.316 88.344 86.4 ;
    END
  END q_o[473]
  PIN q_o[474]
    DIRECTION OUTPUT ;
    USE SIGNAL ;
    PORT
      LAYER M5 ;
        RECT  88.416 86.316 88.44 86.4 ;
    END
  END q_o[474]
  PIN q_o[475]
    DIRECTION OUTPUT ;
    USE SIGNAL ;
    PORT
      LAYER M5 ;
        RECT  88.512 86.316 88.536 86.4 ;
    END
  END q_o[475]
  PIN q_o[476]
    DIRECTION OUTPUT ;
    USE SIGNAL ;
    PORT
      LAYER M5 ;
        RECT  88.608 86.316 88.632 86.4 ;
    END
  END q_o[476]
  PIN q_o[477]
    DIRECTION OUTPUT ;
    USE SIGNAL ;
    PORT
      LAYER M5 ;
        RECT  88.704 86.316 88.728 86.4 ;
    END
  END q_o[477]
  PIN q_o[478]
    DIRECTION OUTPUT ;
    USE SIGNAL ;
    PORT
      LAYER M5 ;
        RECT  88.8 86.316 88.824 86.4 ;
    END
  END q_o[478]
  PIN q_o[479]
    DIRECTION OUTPUT ;
    USE SIGNAL ;
    PORT
      LAYER M5 ;
        RECT  88.896 86.316 88.92 86.4 ;
    END
  END q_o[479]
  PIN q_o[47]
    DIRECTION OUTPUT ;
    USE SIGNAL ;
    PORT
      LAYER M5 ;
        RECT  47.424 86.316 47.448 86.4 ;
    END
  END q_o[47]
  PIN q_o[480]
    DIRECTION OUTPUT ;
    USE SIGNAL ;
    PORT
      LAYER M5 ;
        RECT  88.992 86.316 89.016 86.4 ;
    END
  END q_o[480]
  PIN q_o[481]
    DIRECTION OUTPUT ;
    USE SIGNAL ;
    PORT
      LAYER M5 ;
        RECT  89.088 86.316 89.112 86.4 ;
    END
  END q_o[481]
  PIN q_o[482]
    DIRECTION OUTPUT ;
    USE SIGNAL ;
    PORT
      LAYER M5 ;
        RECT  89.184 86.316 89.208 86.4 ;
    END
  END q_o[482]
  PIN q_o[483]
    DIRECTION OUTPUT ;
    USE SIGNAL ;
    PORT
      LAYER M5 ;
        RECT  89.28 86.316 89.304 86.4 ;
    END
  END q_o[483]
  PIN q_o[484]
    DIRECTION OUTPUT ;
    USE SIGNAL ;
    PORT
      LAYER M5 ;
        RECT  89.376 86.316 89.4 86.4 ;
    END
  END q_o[484]
  PIN q_o[485]
    DIRECTION OUTPUT ;
    USE SIGNAL ;
    PORT
      LAYER M5 ;
        RECT  89.472 86.316 89.496 86.4 ;
    END
  END q_o[485]
  PIN q_o[486]
    DIRECTION OUTPUT ;
    USE SIGNAL ;
    PORT
      LAYER M5 ;
        RECT  89.568 86.316 89.592 86.4 ;
    END
  END q_o[486]
  PIN q_o[487]
    DIRECTION OUTPUT ;
    USE SIGNAL ;
    PORT
      LAYER M5 ;
        RECT  89.664 86.316 89.688 86.4 ;
    END
  END q_o[487]
  PIN q_o[488]
    DIRECTION OUTPUT ;
    USE SIGNAL ;
    PORT
      LAYER M5 ;
        RECT  89.76 86.316 89.784 86.4 ;
    END
  END q_o[488]
  PIN q_o[489]
    DIRECTION OUTPUT ;
    USE SIGNAL ;
    PORT
      LAYER M5 ;
        RECT  89.856 86.316 89.88 86.4 ;
    END
  END q_o[489]
  PIN q_o[48]
    DIRECTION OUTPUT ;
    USE SIGNAL ;
    PORT
      LAYER M5 ;
        RECT  47.52 86.316 47.544 86.4 ;
    END
  END q_o[48]
  PIN q_o[490]
    DIRECTION OUTPUT ;
    USE SIGNAL ;
    PORT
      LAYER M5 ;
        RECT  89.952 86.316 89.976 86.4 ;
    END
  END q_o[490]
  PIN q_o[491]
    DIRECTION OUTPUT ;
    USE SIGNAL ;
    PORT
      LAYER M5 ;
        RECT  90.048 86.316 90.072 86.4 ;
    END
  END q_o[491]
  PIN q_o[492]
    DIRECTION OUTPUT ;
    USE SIGNAL ;
    PORT
      LAYER M5 ;
        RECT  90.144 86.316 90.168 86.4 ;
    END
  END q_o[492]
  PIN q_o[493]
    DIRECTION OUTPUT ;
    USE SIGNAL ;
    PORT
      LAYER M5 ;
        RECT  90.24 86.316 90.264 86.4 ;
    END
  END q_o[493]
  PIN q_o[494]
    DIRECTION OUTPUT ;
    USE SIGNAL ;
    PORT
      LAYER M5 ;
        RECT  90.336 86.316 90.36 86.4 ;
    END
  END q_o[494]
  PIN q_o[495]
    DIRECTION OUTPUT ;
    USE SIGNAL ;
    PORT
      LAYER M5 ;
        RECT  90.432 86.316 90.456 86.4 ;
    END
  END q_o[495]
  PIN q_o[496]
    DIRECTION OUTPUT ;
    USE SIGNAL ;
    PORT
      LAYER M5 ;
        RECT  90.528 86.316 90.552 86.4 ;
    END
  END q_o[496]
  PIN q_o[497]
    DIRECTION OUTPUT ;
    USE SIGNAL ;
    PORT
      LAYER M5 ;
        RECT  90.624 86.316 90.648 86.4 ;
    END
  END q_o[497]
  PIN q_o[498]
    DIRECTION OUTPUT ;
    USE SIGNAL ;
    PORT
      LAYER M5 ;
        RECT  90.72 86.316 90.744 86.4 ;
    END
  END q_o[498]
  PIN q_o[499]
    DIRECTION OUTPUT ;
    USE SIGNAL ;
    PORT
      LAYER M5 ;
        RECT  90.816 86.316 90.84 86.4 ;
    END
  END q_o[499]
  PIN q_o[49]
    DIRECTION OUTPUT ;
    USE SIGNAL ;
    PORT
      LAYER M5 ;
        RECT  47.616 86.316 47.64 86.4 ;
    END
  END q_o[49]
  PIN q_o[4]
    DIRECTION OUTPUT ;
    USE SIGNAL ;
    PORT
      LAYER M5 ;
        RECT  43.296 86.316 43.32 86.4 ;
    END
  END q_o[4]
  PIN q_o[500]
    DIRECTION OUTPUT ;
    USE SIGNAL ;
    PORT
      LAYER M5 ;
        RECT  90.912 86.316 90.936 86.4 ;
    END
  END q_o[500]
  PIN q_o[501]
    DIRECTION OUTPUT ;
    USE SIGNAL ;
    PORT
      LAYER M5 ;
        RECT  91.008 86.316 91.032 86.4 ;
    END
  END q_o[501]
  PIN q_o[502]
    DIRECTION OUTPUT ;
    USE SIGNAL ;
    PORT
      LAYER M5 ;
        RECT  91.104 86.316 91.128 86.4 ;
    END
  END q_o[502]
  PIN q_o[503]
    DIRECTION OUTPUT ;
    USE SIGNAL ;
    PORT
      LAYER M5 ;
        RECT  91.2 86.316 91.224 86.4 ;
    END
  END q_o[503]
  PIN q_o[504]
    DIRECTION OUTPUT ;
    USE SIGNAL ;
    PORT
      LAYER M5 ;
        RECT  91.296 86.316 91.32 86.4 ;
    END
  END q_o[504]
  PIN q_o[505]
    DIRECTION OUTPUT ;
    USE SIGNAL ;
    PORT
      LAYER M5 ;
        RECT  91.392 86.316 91.416 86.4 ;
    END
  END q_o[505]
  PIN q_o[506]
    DIRECTION OUTPUT ;
    USE SIGNAL ;
    PORT
      LAYER M5 ;
        RECT  91.488 86.316 91.512 86.4 ;
    END
  END q_o[506]
  PIN q_o[507]
    DIRECTION OUTPUT ;
    USE SIGNAL ;
    PORT
      LAYER M5 ;
        RECT  91.584 86.316 91.608 86.4 ;
    END
  END q_o[507]
  PIN q_o[508]
    DIRECTION OUTPUT ;
    USE SIGNAL ;
    PORT
      LAYER M5 ;
        RECT  91.68 86.316 91.704 86.4 ;
    END
  END q_o[508]
  PIN q_o[509]
    DIRECTION OUTPUT ;
    USE SIGNAL ;
    PORT
      LAYER M5 ;
        RECT  91.776 86.316 91.8 86.4 ;
    END
  END q_o[509]
  PIN q_o[50]
    DIRECTION OUTPUT ;
    USE SIGNAL ;
    PORT
      LAYER M5 ;
        RECT  47.712 86.316 47.736 86.4 ;
    END
  END q_o[50]
  PIN q_o[510]
    DIRECTION OUTPUT ;
    USE SIGNAL ;
    PORT
      LAYER M5 ;
        RECT  91.872 86.316 91.896 86.4 ;
    END
  END q_o[510]
  PIN q_o[511]
    DIRECTION OUTPUT ;
    USE SIGNAL ;
    PORT
      LAYER M5 ;
        RECT  91.968 86.316 91.992 86.4 ;
    END
  END q_o[511]
  PIN q_o[512]
    DIRECTION OUTPUT ;
    USE SIGNAL ;
    PORT
      LAYER M5 ;
        RECT  92.064 86.316 92.088 86.4 ;
    END
  END q_o[512]
  PIN q_o[513]
    DIRECTION OUTPUT ;
    USE SIGNAL ;
    PORT
      LAYER M5 ;
        RECT  92.16 86.316 92.184 86.4 ;
    END
  END q_o[513]
  PIN q_o[514]
    DIRECTION OUTPUT ;
    USE SIGNAL ;
    PORT
      LAYER M5 ;
        RECT  92.256 86.316 92.28 86.4 ;
    END
  END q_o[514]
  PIN q_o[51]
    DIRECTION OUTPUT ;
    USE SIGNAL ;
    PORT
      LAYER M5 ;
        RECT  47.808 86.316 47.832 86.4 ;
    END
  END q_o[51]
  PIN q_o[52]
    DIRECTION OUTPUT ;
    USE SIGNAL ;
    PORT
      LAYER M5 ;
        RECT  47.904 86.316 47.928 86.4 ;
    END
  END q_o[52]
  PIN q_o[53]
    DIRECTION OUTPUT ;
    USE SIGNAL ;
    PORT
      LAYER M5 ;
        RECT  48 86.316 48.024 86.4 ;
    END
  END q_o[53]
  PIN q_o[54]
    DIRECTION OUTPUT ;
    USE SIGNAL ;
    PORT
      LAYER M5 ;
        RECT  48.096 86.316 48.12 86.4 ;
    END
  END q_o[54]
  PIN q_o[55]
    DIRECTION OUTPUT ;
    USE SIGNAL ;
    PORT
      LAYER M5 ;
        RECT  48.192 86.316 48.216 86.4 ;
    END
  END q_o[55]
  PIN q_o[56]
    DIRECTION OUTPUT ;
    USE SIGNAL ;
    PORT
      LAYER M5 ;
        RECT  48.288 86.316 48.312 86.4 ;
    END
  END q_o[56]
  PIN q_o[57]
    DIRECTION OUTPUT ;
    USE SIGNAL ;
    PORT
      LAYER M5 ;
        RECT  48.384 86.316 48.408 86.4 ;
    END
  END q_o[57]
  PIN q_o[58]
    DIRECTION OUTPUT ;
    USE SIGNAL ;
    PORT
      LAYER M5 ;
        RECT  48.48 86.316 48.504 86.4 ;
    END
  END q_o[58]
  PIN q_o[59]
    DIRECTION OUTPUT ;
    USE SIGNAL ;
    PORT
      LAYER M5 ;
        RECT  48.576 86.316 48.6 86.4 ;
    END
  END q_o[59]
  PIN q_o[5]
    DIRECTION OUTPUT ;
    USE SIGNAL ;
    PORT
      LAYER M5 ;
        RECT  43.392 86.316 43.416 86.4 ;
    END
  END q_o[5]
  PIN q_o[60]
    DIRECTION OUTPUT ;
    USE SIGNAL ;
    PORT
      LAYER M5 ;
        RECT  48.672 86.316 48.696 86.4 ;
    END
  END q_o[60]
  PIN q_o[61]
    DIRECTION OUTPUT ;
    USE SIGNAL ;
    PORT
      LAYER M5 ;
        RECT  48.768 86.316 48.792 86.4 ;
    END
  END q_o[61]
  PIN q_o[62]
    DIRECTION OUTPUT ;
    USE SIGNAL ;
    PORT
      LAYER M5 ;
        RECT  48.864 86.316 48.888 86.4 ;
    END
  END q_o[62]
  PIN q_o[63]
    DIRECTION OUTPUT ;
    USE SIGNAL ;
    PORT
      LAYER M5 ;
        RECT  48.96 86.316 48.984 86.4 ;
    END
  END q_o[63]
  PIN q_o[64]
    DIRECTION OUTPUT ;
    USE SIGNAL ;
    PORT
      LAYER M5 ;
        RECT  49.056 86.316 49.08 86.4 ;
    END
  END q_o[64]
  PIN q_o[65]
    DIRECTION OUTPUT ;
    USE SIGNAL ;
    PORT
      LAYER M5 ;
        RECT  49.152 86.316 49.176 86.4 ;
    END
  END q_o[65]
  PIN q_o[66]
    DIRECTION OUTPUT ;
    USE SIGNAL ;
    PORT
      LAYER M5 ;
        RECT  49.248 86.316 49.272 86.4 ;
    END
  END q_o[66]
  PIN q_o[67]
    DIRECTION OUTPUT ;
    USE SIGNAL ;
    PORT
      LAYER M5 ;
        RECT  49.344 86.316 49.368 86.4 ;
    END
  END q_o[67]
  PIN q_o[68]
    DIRECTION OUTPUT ;
    USE SIGNAL ;
    PORT
      LAYER M5 ;
        RECT  49.44 86.316 49.464 86.4 ;
    END
  END q_o[68]
  PIN q_o[69]
    DIRECTION OUTPUT ;
    USE SIGNAL ;
    PORT
      LAYER M5 ;
        RECT  49.536 86.316 49.56 86.4 ;
    END
  END q_o[69]
  PIN q_o[6]
    DIRECTION OUTPUT ;
    USE SIGNAL ;
    PORT
      LAYER M5 ;
        RECT  43.488 86.316 43.512 86.4 ;
    END
  END q_o[6]
  PIN q_o[70]
    DIRECTION OUTPUT ;
    USE SIGNAL ;
    PORT
      LAYER M5 ;
        RECT  49.632 86.316 49.656 86.4 ;
    END
  END q_o[70]
  PIN q_o[71]
    DIRECTION OUTPUT ;
    USE SIGNAL ;
    PORT
      LAYER M5 ;
        RECT  49.728 86.316 49.752 86.4 ;
    END
  END q_o[71]
  PIN q_o[72]
    DIRECTION OUTPUT ;
    USE SIGNAL ;
    PORT
      LAYER M5 ;
        RECT  49.824 86.316 49.848 86.4 ;
    END
  END q_o[72]
  PIN q_o[73]
    DIRECTION OUTPUT ;
    USE SIGNAL ;
    PORT
      LAYER M5 ;
        RECT  49.92 86.316 49.944 86.4 ;
    END
  END q_o[73]
  PIN q_o[74]
    DIRECTION OUTPUT ;
    USE SIGNAL ;
    PORT
      LAYER M5 ;
        RECT  50.016 86.316 50.04 86.4 ;
    END
  END q_o[74]
  PIN q_o[75]
    DIRECTION OUTPUT ;
    USE SIGNAL ;
    PORT
      LAYER M5 ;
        RECT  50.112 86.316 50.136 86.4 ;
    END
  END q_o[75]
  PIN q_o[76]
    DIRECTION OUTPUT ;
    USE SIGNAL ;
    PORT
      LAYER M5 ;
        RECT  50.208 86.316 50.232 86.4 ;
    END
  END q_o[76]
  PIN q_o[77]
    DIRECTION OUTPUT ;
    USE SIGNAL ;
    PORT
      LAYER M5 ;
        RECT  50.304 86.316 50.328 86.4 ;
    END
  END q_o[77]
  PIN q_o[78]
    DIRECTION OUTPUT ;
    USE SIGNAL ;
    PORT
      LAYER M5 ;
        RECT  50.4 86.316 50.424 86.4 ;
    END
  END q_o[78]
  PIN q_o[79]
    DIRECTION OUTPUT ;
    USE SIGNAL ;
    PORT
      LAYER M5 ;
        RECT  50.496 86.316 50.52 86.4 ;
    END
  END q_o[79]
  PIN q_o[7]
    DIRECTION OUTPUT ;
    USE SIGNAL ;
    PORT
      LAYER M5 ;
        RECT  43.584 86.316 43.608 86.4 ;
    END
  END q_o[7]
  PIN q_o[80]
    DIRECTION OUTPUT ;
    USE SIGNAL ;
    PORT
      LAYER M5 ;
        RECT  50.592 86.316 50.616 86.4 ;
    END
  END q_o[80]
  PIN q_o[81]
    DIRECTION OUTPUT ;
    USE SIGNAL ;
    PORT
      LAYER M5 ;
        RECT  50.688 86.316 50.712 86.4 ;
    END
  END q_o[81]
  PIN q_o[82]
    DIRECTION OUTPUT ;
    USE SIGNAL ;
    PORT
      LAYER M5 ;
        RECT  50.784 86.316 50.808 86.4 ;
    END
  END q_o[82]
  PIN q_o[83]
    DIRECTION OUTPUT ;
    USE SIGNAL ;
    PORT
      LAYER M5 ;
        RECT  50.88 86.316 50.904 86.4 ;
    END
  END q_o[83]
  PIN q_o[84]
    DIRECTION OUTPUT ;
    USE SIGNAL ;
    PORT
      LAYER M5 ;
        RECT  50.976 86.316 51 86.4 ;
    END
  END q_o[84]
  PIN q_o[85]
    DIRECTION OUTPUT ;
    USE SIGNAL ;
    PORT
      LAYER M5 ;
        RECT  51.072 86.316 51.096 86.4 ;
    END
  END q_o[85]
  PIN q_o[86]
    DIRECTION OUTPUT ;
    USE SIGNAL ;
    PORT
      LAYER M5 ;
        RECT  51.168 86.316 51.192 86.4 ;
    END
  END q_o[86]
  PIN q_o[87]
    DIRECTION OUTPUT ;
    USE SIGNAL ;
    PORT
      LAYER M5 ;
        RECT  51.264 86.316 51.288 86.4 ;
    END
  END q_o[87]
  PIN q_o[88]
    DIRECTION OUTPUT ;
    USE SIGNAL ;
    PORT
      LAYER M5 ;
        RECT  51.36 86.316 51.384 86.4 ;
    END
  END q_o[88]
  PIN q_o[89]
    DIRECTION OUTPUT ;
    USE SIGNAL ;
    PORT
      LAYER M5 ;
        RECT  51.456 86.316 51.48 86.4 ;
    END
  END q_o[89]
  PIN q_o[8]
    DIRECTION OUTPUT ;
    USE SIGNAL ;
    PORT
      LAYER M5 ;
        RECT  43.68 86.316 43.704 86.4 ;
    END
  END q_o[8]
  PIN q_o[90]
    DIRECTION OUTPUT ;
    USE SIGNAL ;
    PORT
      LAYER M5 ;
        RECT  51.552 86.316 51.576 86.4 ;
    END
  END q_o[90]
  PIN q_o[91]
    DIRECTION OUTPUT ;
    USE SIGNAL ;
    PORT
      LAYER M5 ;
        RECT  51.648 86.316 51.672 86.4 ;
    END
  END q_o[91]
  PIN q_o[92]
    DIRECTION OUTPUT ;
    USE SIGNAL ;
    PORT
      LAYER M5 ;
        RECT  51.744 86.316 51.768 86.4 ;
    END
  END q_o[92]
  PIN q_o[93]
    DIRECTION OUTPUT ;
    USE SIGNAL ;
    PORT
      LAYER M5 ;
        RECT  51.84 86.316 51.864 86.4 ;
    END
  END q_o[93]
  PIN q_o[94]
    DIRECTION OUTPUT ;
    USE SIGNAL ;
    PORT
      LAYER M5 ;
        RECT  51.936 86.316 51.96 86.4 ;
    END
  END q_o[94]
  PIN q_o[95]
    DIRECTION OUTPUT ;
    USE SIGNAL ;
    PORT
      LAYER M5 ;
        RECT  52.032 86.316 52.056 86.4 ;
    END
  END q_o[95]
  PIN q_o[96]
    DIRECTION OUTPUT ;
    USE SIGNAL ;
    PORT
      LAYER M5 ;
        RECT  52.128 86.316 52.152 86.4 ;
    END
  END q_o[96]
  PIN q_o[97]
    DIRECTION OUTPUT ;
    USE SIGNAL ;
    PORT
      LAYER M5 ;
        RECT  52.224 86.316 52.248 86.4 ;
    END
  END q_o[97]
  PIN q_o[98]
    DIRECTION OUTPUT ;
    USE SIGNAL ;
    PORT
      LAYER M5 ;
        RECT  52.32 86.316 52.344 86.4 ;
    END
  END q_o[98]
  PIN q_o[99]
    DIRECTION OUTPUT ;
    USE SIGNAL ;
    PORT
      LAYER M5 ;
        RECT  52.416 86.316 52.44 86.4 ;
    END
  END q_o[99]
  PIN q_o[9]
    DIRECTION OUTPUT ;
    USE SIGNAL ;
    PORT
      LAYER M5 ;
        RECT  43.776 86.316 43.8 86.4 ;
    END
  END q_o[9]
  PIN rst_n
    DIRECTION INPUT ;
    USE SIGNAL ;
    PORT
      LAYER M4 ;
        RECT  0 4.992 0.084 5.016 ;
    END
  END rst_n
  PIN VDD
    DIRECTION INOUT ;
    USE POWER ;
    PORT
      LAYER M5 ;
        RECT  126.792 2.151 126.912 84.249 ;
        RECT  121.392 2.151 121.512 84.249 ;
        RECT  115.992 2.151 116.112 84.249 ;
        RECT  110.592 2.151 110.712 84.249 ;
        RECT  105.192 2.151 105.312 84.249 ;
        RECT  99.792 2.151 99.912 84.249 ;
        RECT  94.392 2.151 94.512 84.249 ;
        RECT  88.992 2.151 89.112 84.249 ;
        RECT  83.592 2.151 83.712 84.249 ;
        RECT  78.192 2.151 78.312 84.249 ;
        RECT  72.792 2.151 72.912 84.249 ;
        RECT  67.392 2.151 67.512 84.249 ;
        RECT  61.992 2.151 62.112 84.249 ;
        RECT  56.592 2.151 56.712 84.249 ;
        RECT  51.192 2.151 51.312 84.249 ;
        RECT  45.792 2.151 45.912 84.249 ;
        RECT  40.392 2.151 40.512 84.249 ;
        RECT  34.992 2.151 35.112 84.249 ;
        RECT  29.592 2.151 29.712 84.249 ;
        RECT  24.192 2.151 24.312 84.249 ;
        RECT  18.792 2.151 18.912 84.249 ;
        RECT  13.392 2.151 13.512 84.249 ;
        RECT  7.992 2.151 8.112 84.249 ;
        RECT  2.592 2.151 2.712 84.249 ;
    END
  END VDD
  PIN VSS
    DIRECTION INOUT ;
    USE GROUND ;
    PORT
      LAYER M5 ;
        RECT  126.6 2.137 126.72 84.263 ;
        RECT  121.2 2.137 121.32 84.263 ;
        RECT  115.8 2.137 115.92 84.263 ;
        RECT  110.4 2.137 110.52 84.263 ;
        RECT  105 2.137 105.12 84.263 ;
        RECT  99.6 2.137 99.72 84.263 ;
        RECT  94.2 2.137 94.32 84.263 ;
        RECT  88.8 2.137 88.92 84.263 ;
        RECT  83.4 2.137 83.52 84.263 ;
        RECT  78 2.137 78.12 84.263 ;
        RECT  72.6 2.137 72.72 84.263 ;
        RECT  67.2 2.137 67.32 84.263 ;
        RECT  61.8 2.137 61.92 84.263 ;
        RECT  56.4 2.137 56.52 84.263 ;
        RECT  51 2.137 51.12 84.263 ;
        RECT  45.6 2.137 45.72 84.263 ;
        RECT  40.2 2.137 40.32 84.263 ;
        RECT  34.8 2.137 34.92 84.263 ;
        RECT  29.4 2.137 29.52 84.263 ;
        RECT  24 2.137 24.12 84.263 ;
        RECT  18.6 2.137 18.72 84.263 ;
        RECT  13.2 2.137 13.32 84.263 ;
        RECT  7.8 2.137 7.92 84.263 ;
        RECT  2.4 2.137 2.52 84.263 ;
    END
  END VSS
  # OT_OBS_CLOSED layer=M5 d_um=1.536 added=349
  OBS
    LAYER RVTN ;
     RECT  2.16 2.16 127.44 2.295 ;
     RECT  2.16 2.565 127.44 2.835 ;
     RECT  2.16 3.105 127.44 3.375 ;
     RECT  2.16 3.645 127.44 3.915 ;
     RECT  2.16 4.185 127.44 4.455 ;
     RECT  2.16 4.725 127.44 4.995 ;
     RECT  2.16 5.265 127.44 5.535 ;
     RECT  2.16 5.805 127.44 6.075 ;
     RECT  2.16 6.345 127.44 6.615 ;
     RECT  2.16 6.885 127.44 7.155 ;
     RECT  2.16 7.425 127.44 7.695 ;
     RECT  2.16 7.965 127.44 8.235 ;
     RECT  2.16 8.505 127.44 8.775 ;
     RECT  2.16 9.045 127.44 9.315 ;
     RECT  2.16 9.585 127.44 9.855 ;
     RECT  2.16 10.125 127.44 10.395 ;
     RECT  2.16 10.665 127.44 10.935 ;
     RECT  2.16 11.205 127.44 11.475 ;
     RECT  2.16 11.745 127.44 12.015 ;
     RECT  2.16 12.285 127.44 12.555 ;
     RECT  2.16 12.825 127.44 13.095 ;
     RECT  2.16 13.365 127.44 13.635 ;
     RECT  2.16 13.905 127.44 14.175 ;
     RECT  2.16 14.445 127.44 14.715 ;
     RECT  2.16 14.985 127.44 15.255 ;
     RECT  2.16 15.525 127.44 15.795 ;
     RECT  2.16 16.065 127.44 16.335 ;
     RECT  2.16 16.605 127.44 16.875 ;
     RECT  2.16 17.145 127.44 17.415 ;
     RECT  2.16 17.685 127.44 17.955 ;
     RECT  2.16 18.225 127.44 18.495 ;
     RECT  2.16 18.765 127.44 19.035 ;
     RECT  2.16 19.305 127.44 19.575 ;
     RECT  2.16 19.845 127.44 20.115 ;
     RECT  2.16 20.385 127.44 20.655 ;
     RECT  2.16 20.925 127.44 21.195 ;
     RECT  2.16 21.465 127.44 21.735 ;
     RECT  2.16 22.005 127.44 22.275 ;
     RECT  2.16 22.545 127.44 22.815 ;
     RECT  2.16 23.085 127.44 23.355 ;
     RECT  2.16 23.625 127.44 23.895 ;
     RECT  2.16 24.165 127.44 24.435 ;
     RECT  2.16 24.705 127.44 24.975 ;
     RECT  2.16 25.245 127.44 25.515 ;
     RECT  2.16 25.785 127.44 26.055 ;
     RECT  2.16 26.325 127.44 26.595 ;
     RECT  2.16 26.865 127.44 27.135 ;
     RECT  2.16 27.405 127.44 27.675 ;
     RECT  2.16 27.945 127.44 28.215 ;
     RECT  2.16 28.485 127.44 28.755 ;
     RECT  2.16 29.025 127.44 29.295 ;
     RECT  2.16 29.565 127.44 29.835 ;
     RECT  2.16 30.105 127.44 30.375 ;
     RECT  2.16 30.645 127.44 30.915 ;
     RECT  2.16 31.185 127.44 31.455 ;
     RECT  2.16 31.725 127.44 31.995 ;
     RECT  2.16 32.265 127.44 32.535 ;
     RECT  2.16 32.805 127.44 33.075 ;
     RECT  2.16 33.345 127.44 33.615 ;
     RECT  2.16 33.885 127.44 34.155 ;
     RECT  2.16 34.425 127.44 34.695 ;
     RECT  2.16 34.965 127.44 35.235 ;
     RECT  2.16 35.505 127.44 35.775 ;
     RECT  2.16 36.045 127.44 36.315 ;
     RECT  2.16 36.585 127.44 36.855 ;
     RECT  2.16 37.125 127.44 37.395 ;
     RECT  2.16 37.665 127.44 37.935 ;
     RECT  2.16 38.205 127.44 38.475 ;
     RECT  2.16 38.745 127.44 39.015 ;
     RECT  2.16 39.285 127.44 39.555 ;
     RECT  2.16 39.825 127.44 40.095 ;
     RECT  2.16 40.365 127.44 40.635 ;
     RECT  2.16 40.905 127.44 41.175 ;
     RECT  2.16 41.445 127.44 41.715 ;
     RECT  2.16 41.985 127.44 42.255 ;
     RECT  2.16 42.525 127.44 42.795 ;
     RECT  2.16 43.065 127.44 43.335 ;
     RECT  2.16 43.605 127.44 43.875 ;
     RECT  2.16 44.145 127.44 44.415 ;
     RECT  2.16 44.685 127.44 44.955 ;
     RECT  2.16 45.225 127.44 45.495 ;
     RECT  2.16 45.765 127.44 46.035 ;
     RECT  2.16 46.305 127.44 46.575 ;
     RECT  2.16 46.845 127.44 47.115 ;
     RECT  2.16 47.385 127.44 47.655 ;
     RECT  2.16 47.925 127.44 48.195 ;
     RECT  2.16 48.465 127.44 48.735 ;
     RECT  2.16 49.005 127.44 49.275 ;
     RECT  2.16 49.545 127.44 49.815 ;
     RECT  2.16 50.085 127.44 50.355 ;
     RECT  2.16 50.625 127.44 50.895 ;
     RECT  2.16 51.165 127.44 51.435 ;
     RECT  2.16 51.705 127.44 51.975 ;
     RECT  2.16 52.245 127.44 52.515 ;
     RECT  2.16 52.785 127.44 53.055 ;
     RECT  2.16 53.325 127.44 53.595 ;
     RECT  2.16 53.865 127.44 54.135 ;
     RECT  2.16 54.405 127.44 54.675 ;
     RECT  2.16 54.945 127.44 55.215 ;
     RECT  2.16 55.485 127.44 55.755 ;
     RECT  2.16 56.025 127.44 56.295 ;
     RECT  2.16 56.565 127.44 56.835 ;
     RECT  2.16 57.105 127.44 57.375 ;
     RECT  2.16 57.645 127.44 57.915 ;
     RECT  2.16 58.185 127.44 58.455 ;
     RECT  2.16 58.725 127.44 58.995 ;
     RECT  2.16 59.265 127.44 59.535 ;
     RECT  2.16 59.805 127.44 60.075 ;
     RECT  2.16 60.345 127.44 60.615 ;
     RECT  2.16 60.885 127.44 61.155 ;
     RECT  2.16 61.425 127.44 61.695 ;
     RECT  2.16 61.965 127.44 62.235 ;
     RECT  2.16 62.505 127.44 62.775 ;
     RECT  2.16 63.045 127.44 63.315 ;
     RECT  2.16 63.585 127.44 63.855 ;
     RECT  2.16 64.125 127.44 64.395 ;
     RECT  2.16 64.665 127.44 64.935 ;
     RECT  2.16 65.205 127.44 65.475 ;
     RECT  2.16 65.745 127.44 66.015 ;
     RECT  2.16 66.285 127.44 66.555 ;
     RECT  2.16 66.825 127.44 67.095 ;
     RECT  2.16 67.365 127.44 67.635 ;
     RECT  2.16 67.905 127.44 68.175 ;
     RECT  2.16 68.445 127.44 68.715 ;
     RECT  2.16 68.985 127.44 69.255 ;
     RECT  2.16 69.525 127.44 69.795 ;
     RECT  2.16 70.065 127.44 70.335 ;
     RECT  2.16 70.605 127.44 70.875 ;
     RECT  2.16 71.145 127.44 71.415 ;
     RECT  2.16 71.685 127.44 71.955 ;
     RECT  2.16 72.225 127.44 72.495 ;
     RECT  2.16 72.765 127.44 73.035 ;
     RECT  2.16 73.305 127.44 73.575 ;
     RECT  2.16 73.845 127.44 74.115 ;
     RECT  2.16 74.385 127.44 74.655 ;
     RECT  2.16 74.925 127.44 75.195 ;
     RECT  2.16 75.465 127.44 75.735 ;
     RECT  2.16 76.005 127.44 76.275 ;
     RECT  2.16 76.545 127.44 76.815 ;
     RECT  2.16 77.085 127.44 77.355 ;
     RECT  2.16 77.625 127.44 77.895 ;
     RECT  2.16 78.165 127.44 78.435 ;
     RECT  2.16 78.705 127.44 78.975 ;
     RECT  2.16 79.245 127.44 79.515 ;
     RECT  2.16 79.785 127.44 80.055 ;
     RECT  2.16 80.325 127.44 80.595 ;
     RECT  2.16 80.865 127.44 81.135 ;
     RECT  2.16 81.405 127.44 81.675 ;
     RECT  2.16 81.945 127.44 82.215 ;
     RECT  2.16 82.485 127.44 82.755 ;
     RECT  2.16 83.025 127.44 83.295 ;
     RECT  2.16 83.565 127.44 83.835 ;
     RECT  2.16 84.105 127.44 84.24 ;
    LAYER RVTP ;
     RECT  2.16 2.295 127.44 2.565 ;
     RECT  2.16 2.835 127.44 3.105 ;
     RECT  2.16 3.375 127.44 3.645 ;
     RECT  2.16 3.915 127.44 4.185 ;
     RECT  2.16 4.455 127.44 4.725 ;
     RECT  2.16 4.995 127.44 5.265 ;
     RECT  2.16 5.535 127.44 5.805 ;
     RECT  2.16 6.075 127.44 6.345 ;
     RECT  2.16 6.615 127.44 6.885 ;
     RECT  2.16 7.155 127.44 7.425 ;
     RECT  2.16 7.695 127.44 7.965 ;
     RECT  2.16 8.235 127.44 8.505 ;
     RECT  2.16 8.775 127.44 9.045 ;
     RECT  2.16 9.315 127.44 9.585 ;
     RECT  2.16 9.855 127.44 10.125 ;
     RECT  2.16 10.395 127.44 10.665 ;
     RECT  2.16 10.935 127.44 11.205 ;
     RECT  2.16 11.475 127.44 11.745 ;
     RECT  2.16 12.015 127.44 12.285 ;
     RECT  2.16 12.555 127.44 12.825 ;
     RECT  2.16 13.095 127.44 13.365 ;
     RECT  2.16 13.635 127.44 13.905 ;
     RECT  2.16 14.175 127.44 14.445 ;
     RECT  2.16 14.715 127.44 14.985 ;
     RECT  2.16 15.255 127.44 15.525 ;
     RECT  2.16 15.795 127.44 16.065 ;
     RECT  2.16 16.335 127.44 16.605 ;
     RECT  2.16 16.875 127.44 17.145 ;
     RECT  2.16 17.415 127.44 17.685 ;
     RECT  2.16 17.955 127.44 18.225 ;
     RECT  2.16 18.495 127.44 18.765 ;
     RECT  2.16 19.035 127.44 19.305 ;
     RECT  2.16 19.575 127.44 19.845 ;
     RECT  2.16 20.115 127.44 20.385 ;
     RECT  2.16 20.655 127.44 20.925 ;
     RECT  2.16 21.195 127.44 21.465 ;
     RECT  2.16 21.735 127.44 22.005 ;
     RECT  2.16 22.275 127.44 22.545 ;
     RECT  2.16 22.815 127.44 23.085 ;
     RECT  2.16 23.355 127.44 23.625 ;
     RECT  2.16 23.895 127.44 24.165 ;
     RECT  2.16 24.435 127.44 24.705 ;
     RECT  2.16 24.975 127.44 25.245 ;
     RECT  2.16 25.515 127.44 25.785 ;
     RECT  2.16 26.055 127.44 26.325 ;
     RECT  2.16 26.595 127.44 26.865 ;
     RECT  2.16 27.135 127.44 27.405 ;
     RECT  2.16 27.675 127.44 27.945 ;
     RECT  2.16 28.215 127.44 28.485 ;
     RECT  2.16 28.755 127.44 29.025 ;
     RECT  2.16 29.295 127.44 29.565 ;
     RECT  2.16 29.835 127.44 30.105 ;
     RECT  2.16 30.375 127.44 30.645 ;
     RECT  2.16 30.915 127.44 31.185 ;
     RECT  2.16 31.455 127.44 31.725 ;
     RECT  2.16 31.995 127.44 32.265 ;
     RECT  2.16 32.535 127.44 32.805 ;
     RECT  2.16 33.075 127.44 33.345 ;
     RECT  2.16 33.615 127.44 33.885 ;
     RECT  2.16 34.155 127.44 34.425 ;
     RECT  2.16 34.695 127.44 34.965 ;
     RECT  2.16 35.235 127.44 35.505 ;
     RECT  2.16 35.775 127.44 36.045 ;
     RECT  2.16 36.315 127.44 36.585 ;
     RECT  2.16 36.855 127.44 37.125 ;
     RECT  2.16 37.395 127.44 37.665 ;
     RECT  2.16 37.935 127.44 38.205 ;
     RECT  2.16 38.475 127.44 38.745 ;
     RECT  2.16 39.015 127.44 39.285 ;
     RECT  2.16 39.555 127.44 39.825 ;
     RECT  2.16 40.095 127.44 40.365 ;
     RECT  2.16 40.635 127.44 40.905 ;
     RECT  2.16 41.175 127.44 41.445 ;
     RECT  2.16 41.715 127.44 41.985 ;
     RECT  2.16 42.255 127.44 42.525 ;
     RECT  2.16 42.795 127.44 43.065 ;
     RECT  2.16 43.335 127.44 43.605 ;
     RECT  2.16 43.875 127.44 44.145 ;
     RECT  2.16 44.415 127.44 44.685 ;
     RECT  2.16 44.955 127.44 45.225 ;
     RECT  2.16 45.495 127.44 45.765 ;
     RECT  2.16 46.035 127.44 46.305 ;
     RECT  2.16 46.575 127.44 46.845 ;
     RECT  2.16 47.115 127.44 47.385 ;
     RECT  2.16 47.655 127.44 47.925 ;
     RECT  2.16 48.195 127.44 48.465 ;
     RECT  2.16 48.735 127.44 49.005 ;
     RECT  2.16 49.275 127.44 49.545 ;
     RECT  2.16 49.815 127.44 50.085 ;
     RECT  2.16 50.355 127.44 50.625 ;
     RECT  2.16 50.895 127.44 51.165 ;
     RECT  2.16 51.435 127.44 51.705 ;
     RECT  2.16 51.975 127.44 52.245 ;
     RECT  2.16 52.515 127.44 52.785 ;
     RECT  2.16 53.055 127.44 53.325 ;
     RECT  2.16 53.595 127.44 53.865 ;
     RECT  2.16 54.135 127.44 54.405 ;
     RECT  2.16 54.675 127.44 54.945 ;
     RECT  2.16 55.215 127.44 55.485 ;
     RECT  2.16 55.755 127.44 56.025 ;
     RECT  2.16 56.295 127.44 56.565 ;
     RECT  2.16 56.835 127.44 57.105 ;
     RECT  2.16 57.375 127.44 57.645 ;
     RECT  2.16 57.915 127.44 58.185 ;
     RECT  2.16 58.455 127.44 58.725 ;
     RECT  2.16 58.995 127.44 59.265 ;
     RECT  2.16 59.535 127.44 59.805 ;
     RECT  2.16 60.075 127.44 60.345 ;
     RECT  2.16 60.615 127.44 60.885 ;
     RECT  2.16 61.155 127.44 61.425 ;
     RECT  2.16 61.695 127.44 61.965 ;
     RECT  2.16 62.235 127.44 62.505 ;
     RECT  2.16 62.775 127.44 63.045 ;
     RECT  2.16 63.315 127.44 63.585 ;
     RECT  2.16 63.855 127.44 64.125 ;
     RECT  2.16 64.395 127.44 64.665 ;
     RECT  2.16 64.935 127.44 65.205 ;
     RECT  2.16 65.475 127.44 65.745 ;
     RECT  2.16 66.015 127.44 66.285 ;
     RECT  2.16 66.555 127.44 66.825 ;
     RECT  2.16 67.095 127.44 67.365 ;
     RECT  2.16 67.635 127.44 67.905 ;
     RECT  2.16 68.175 127.44 68.445 ;
     RECT  2.16 68.715 127.44 68.985 ;
     RECT  2.16 69.255 127.44 69.525 ;
     RECT  2.16 69.795 127.44 70.065 ;
     RECT  2.16 70.335 127.44 70.605 ;
     RECT  2.16 70.875 127.44 71.145 ;
     RECT  2.16 71.415 127.44 71.685 ;
     RECT  2.16 71.955 127.44 72.225 ;
     RECT  2.16 72.495 127.44 72.765 ;
     RECT  2.16 73.035 127.44 73.305 ;
     RECT  2.16 73.575 127.44 73.845 ;
     RECT  2.16 74.115 127.44 74.385 ;
     RECT  2.16 74.655 127.44 74.925 ;
     RECT  2.16 75.195 127.44 75.465 ;
     RECT  2.16 75.735 127.44 76.005 ;
     RECT  2.16 76.275 127.44 76.545 ;
     RECT  2.16 76.815 127.44 77.085 ;
     RECT  2.16 77.355 127.44 77.625 ;
     RECT  2.16 77.895 127.44 78.165 ;
     RECT  2.16 78.435 127.44 78.705 ;
     RECT  2.16 78.975 127.44 79.245 ;
     RECT  2.16 79.515 127.44 79.785 ;
     RECT  2.16 80.055 127.44 80.325 ;
     RECT  2.16 80.595 127.44 80.865 ;
     RECT  2.16 81.135 127.44 81.405 ;
     RECT  2.16 81.675 127.44 81.945 ;
     RECT  2.16 82.215 127.44 82.485 ;
     RECT  2.16 82.755 127.44 83.025 ;
     RECT  2.16 83.295 127.44 83.565 ;
     RECT  2.16 83.835 127.44 84.105 ;
    LAYER M1 ;
     RECT  2.16 2.151 127.44 84.249 ;
    LAYER M2 ;
     RECT  2.16 2.151 42.511 84.249 ;
     RECT  42.511 2.106 43.115 84.249 ;
     RECT  45.967 1.152 46.067 1.17 ;
     RECT  43.115 2.151 46.219 84.249 ;
     RECT  46.219 2.151 48.695 84.906 ;
     RECT  48.695 2.151 49.603 84.249 ;
     RECT  49.603 2.106 50.107 84.249 ;
     RECT  50.107 1.998 51.071 84.249 ;
     RECT  51.071 2.151 52.231 84.249 ;
     RECT  52.231 2.151 52.331 84.906 ;
     RECT  52.331 2.151 52.555 84.249 ;
     RECT  52.555 2.106 53.491 84.249 ;
     RECT  53.491 2.034 54.239 84.249 ;
     RECT  54.239 2.151 55.255 84.249 ;
     RECT  55.255 2.106 57.515 84.249 ;
     RECT  61.699 1.152 62.375 1.17 ;
     RECT  57.515 2.151 64.543 84.249 ;
     RECT  64.543 2.106 65.003 84.249 ;
     RECT  65.003 2.151 66.775 84.249 ;
     RECT  66.775 2.151 66.875 84.906 ;
     RECT  66.875 2.151 70.375 84.249 ;
     RECT  70.375 2.151 70.691 84.906 ;
     RECT  70.691 2.151 71.599 84.249 ;
     RECT  71.599 2.151 71.699 84.906 ;
     RECT  71.699 2.151 72.463 84.249 ;
     RECT  72.463 2.151 72.563 84.906 ;
     RECT  72.563 2.151 72.779 84.834 ;
     RECT  72.779 2.151 73.535 84.294 ;
     RECT  73.535 2.151 73.831 84.249 ;
     RECT  73.831 2.106 74.219 84.249 ;
     RECT  74.219 2.151 76.243 84.249 ;
     RECT  76.243 2.106 76.955 84.249 ;
     RECT  76.955 2.151 83.119 84.249 ;
     RECT  83.119 2.106 83.795 84.249 ;
     RECT  83.795 2.151 90.679 84.249 ;
     RECT  90.679 2.106 91.895 84.249 ;
     RECT  91.895 2.151 127.44 84.249 ;
     RECT  127.44 43.236 128.831 43.254 ;
    LAYER M3 ;
     RECT  46.08 0.091 46.098 0.139 ;
     RECT  46.08 0.139 46.206 0.187 ;
     RECT  62.856 0.091 63.162 0.187 ;
     RECT  72.936 0.091 72.954 0.221 ;
     RECT  46.08 0.187 46.566 0.317 ;
     RECT  62.784 0.187 63.162 0.365 ;
     RECT  63 0.365 63.162 0.461 ;
     RECT  46.188 0.317 46.566 0.523 ;
     RECT  56.88 0.091 57.006 0.523 ;
     RECT  42.372 0.139 42.39 0.571 ;
     RECT  43.272 0.091 43.29 0.571 ;
     RECT  44.532 0.523 44.55 0.571 ;
     RECT  48.456 0.091 48.474 0.571 ;
     RECT  50.724 0.091 50.742 0.571 ;
     RECT  53.892 0.523 53.91 0.571 ;
     RECT  58.176 0.475 58.194 0.571 ;
     RECT  61.704 0.523 61.722 0.571 ;
     RECT  74.124 0.523 74.142 0.571 ;
     RECT  89.748 0.523 89.766 0.571 ;
     RECT  44.532 0.571 45.054 0.619 ;
     RECT  86.184 0.571 86.202 0.619 ;
     RECT  84.42 0.571 84.438 0.667 ;
     RECT  46.188 0.523 46.926 1.099 ;
     RECT  50.724 0.571 51.066 1.099 ;
     RECT  55.332 0.523 55.35 1.099 ;
     RECT  66.708 0.091 66.726 1.099 ;
     RECT  74.124 0.571 74.214 1.099 ;
     RECT  88.236 0.523 88.254 1.099 ;
     RECT  61.2 0.571 62.226 1.147 ;
     RECT  63.288 0.571 63.306 1.147 ;
     RECT  81 0.571 81.018 1.147 ;
     RECT  82.08 0.571 82.674 1.147 ;
     RECT  89.748 0.571 90.666 1.147 ;
     RECT  53.892 0.571 54.234 1.627 ;
     RECT  55.332 1.099 55.494 1.627 ;
     RECT  72.396 0.571 72.414 1.675 ;
     RECT  84.42 0.667 84.474 1.675 ;
     RECT  42.372 0.571 43.29 1.723 ;
     RECT  44.532 0.619 45.126 1.723 ;
     RECT  45.972 1.099 46.926 1.723 ;
     RECT  48.456 0.571 49.05 1.723 ;
     RECT  50.292 1.099 51.066 1.723 ;
     RECT  51.912 0.091 51.93 1.723 ;
     RECT  52.812 0.091 52.83 1.723 ;
     RECT  53.892 1.627 55.494 1.723 ;
     RECT  56.88 0.523 57.402 1.723 ;
     RECT  58.14 0.571 58.194 1.723 ;
     RECT  59.328 0.571 59.346 1.723 ;
     RECT  60.444 0.571 60.462 1.723 ;
     RECT  61.2 1.147 62.37 1.723 ;
     RECT  63.288 1.147 64.026 1.723 ;
     RECT  64.98 0.571 64.998 1.723 ;
     RECT  66.708 1.099 67.374 1.723 ;
     RECT  70.704 0.571 70.722 1.723 ;
     RECT  72.396 1.675 72.594 1.723 ;
     RECT  73.512 1.099 74.214 1.723 ;
     RECT  74.952 1.147 74.97 1.723 ;
     RECT  76.356 1.147 76.374 1.723 ;
     RECT  79.272 0.571 79.29 1.723 ;
     RECT  81 1.147 82.674 1.723 ;
     RECT  84.42 1.675 85.014 1.723 ;
     RECT  86.184 0.619 86.274 1.723 ;
     RECT  87.336 1.099 87.354 1.723 ;
     RECT  88.236 1.099 88.65 1.723 ;
     RECT  89.748 1.147 90.738 1.723 ;
     RECT  91.908 0.091 91.926 1.723 ;
     RECT  60.228 1.723 86.274 1.771 ;
     RECT  87.156 1.723 87.354 1.771 ;
     RECT  88.2 1.723 92.286 1.771 ;
     RECT  42.372 1.723 59.49 2.155 ;
     RECT  60.228 1.771 92.286 2.155 ;
     RECT  42.372 2.155 92.286 2.263 ;
     RECT  42.372 2.263 92.934 2.371 ;
     RECT  2.415 2.143 2.505 2.413 ;
     RECT  7.815 2.143 7.905 2.413 ;
     RECT  13.215 2.143 13.305 2.413 ;
     RECT  18.615 2.143 18.705 2.413 ;
     RECT  24.015 2.143 24.105 2.413 ;
     RECT  29.415 2.143 29.505 2.413 ;
     RECT  34.815 2.143 34.905 2.413 ;
     RECT  40.215 2.143 40.305 2.413 ;
     RECT  94.215 2.143 94.305 2.413 ;
     RECT  99.615 2.143 99.705 2.413 ;
     RECT  105.015 2.143 105.105 2.413 ;
     RECT  110.415 2.143 110.505 2.413 ;
     RECT  115.815 2.143 115.905 2.413 ;
     RECT  121.215 2.143 121.305 2.413 ;
     RECT  126.615 2.143 126.705 2.413 ;
     RECT  42.264 2.371 92.97 2.641 ;
     RECT  42.264 2.641 93.258 2.911 ;
     RECT  94.215 2.413 94.497 2.911 ;
     RECT  23.22 3.379 23.238 4.109 ;
     RECT  42.264 2.911 94.497 4.145 ;
     RECT  42.48 4.145 94.497 4.451 ;
     RECT  2.415 2.413 2.697 4.987 ;
     RECT  2.304 4.987 2.697 5.225 ;
     RECT  42.588 4.451 94.497 5.305 ;
     RECT  42.372 5.305 94.497 5.909 ;
     RECT  42.48 5.909 94.497 6.269 ;
     RECT  42.66 6.269 94.497 6.809 ;
     RECT  43.344 6.809 94.497 9.787 ;
     RECT  42.912 9.787 94.497 10.013 ;
     RECT  43.344 10.013 94.497 10.975 ;
     RECT  42.48 10.843 42.498 11.281 ;
     RECT  43.308 10.975 94.497 11.281 ;
     RECT  42.48 11.281 94.497 11.939 ;
     RECT  42.696 11.939 94.497 12.557 ;
     RECT  43.056 12.557 94.497 14.251 ;
     RECT  42.768 14.251 94.497 14.299 ;
     RECT  42.444 14.299 94.497 14.369 ;
     RECT  42.768 14.369 94.497 18.301 ;
     RECT  42.66 18.301 94.497 18.769 ;
     RECT  40.215 2.413 40.497 18.805 ;
     RECT  40.215 18.805 40.878 18.841 ;
     RECT  42.552 18.769 94.497 18.841 ;
     RECT  42.192 18.841 94.497 18.931 ;
     RECT  40.215 18.841 40.95 19.075 ;
     RECT  41.688 18.931 94.497 19.075 ;
     RECT  40.215 19.075 94.497 19.921 ;
     RECT  40.176 19.921 94.497 20.731 ;
     RECT  39.96 20.731 94.497 20.849 ;
     RECT  23.076 4.225 23.094 22.037 ;
     RECT  95.436 4.801 95.454 23.971 ;
     RECT  40.215 20.849 94.497 24.097 ;
     RECT  95.256 23.971 95.454 24.097 ;
     RECT  40.215 24.097 95.454 24.241 ;
     RECT  40.215 24.241 95.562 24.331 ;
     RECT  40.215 24.331 95.634 24.403 ;
     RECT  96.408 24.187 96.426 24.403 ;
     RECT  97.236 24.205 97.254 24.439 ;
     RECT  97.236 24.439 97.398 24.475 ;
     RECT  40.215 24.403 96.426 24.511 ;
     RECT  97.236 24.475 97.902 24.511 ;
     RECT  40.215 24.511 97.902 24.523 ;
     RECT  40.215 24.523 98.19 24.637 ;
     RECT  40.215 24.637 98.694 24.781 ;
     RECT  99.615 2.413 99.897 24.781 ;
     RECT  40.215 24.781 99.897 25.007 ;
     RECT  40.215 25.007 98.694 25.079 ;
     RECT  40.215 25.079 98.55 25.205 ;
     RECT  40.215 25.205 98.19 25.349 ;
     RECT  40.215 25.349 97.362 26.131 ;
     RECT  98.172 25.349 98.19 26.131 ;
     RECT  40.215 26.131 98.19 26.251 ;
     RECT  39.996 26.251 98.19 26.285 ;
     RECT  98.172 26.285 98.19 26.401 ;
     RECT  98.172 26.401 98.262 26.663 ;
     RECT  39.996 26.285 97.434 27.355 ;
     RECT  98.172 26.663 98.19 27.355 ;
     RECT  39.996 27.355 98.19 27.365 ;
     RECT  40.215 27.365 98.19 27.401 ;
     RECT  97.416 27.401 98.19 27.481 ;
     RECT  97.416 27.481 98.478 27.751 ;
     RECT  97.416 27.751 98.73 28.417 ;
     RECT  40.215 27.401 96.57 28.481 ;
     RECT  97.416 28.417 98.874 28.795 ;
     RECT  97.344 28.795 98.874 29.035 ;
     RECT  99.615 25.007 99.897 29.035 ;
     RECT  40.215 28.481 96.354 29.219 ;
     RECT  97.344 29.035 99.897 29.227 ;
     RECT  97.344 29.227 99.954 29.263 ;
     RECT  100.908 29.101 100.926 29.263 ;
     RECT  97.344 29.263 100.926 29.335 ;
     RECT  40.215 29.219 40.497 29.371 ;
     RECT  97.344 29.335 101.178 29.371 ;
     RECT  41.328 29.219 96.354 29.461 ;
     RECT  97.344 29.371 101.61 29.461 ;
     RECT  40.176 29.371 40.497 29.549 ;
     RECT  41.328 29.461 101.61 29.549 ;
     RECT  41.616 29.549 101.61 30.065 ;
     RECT  41.688 30.065 99.99 30.101 ;
     RECT  41.688 30.101 99.954 30.173 ;
     RECT  100.728 30.065 101.61 30.181 ;
     RECT  100.728 30.181 101.934 30.875 ;
     RECT  41.688 30.173 99.897 30.955 ;
     RECT  41.292 30.955 99.897 30.991 ;
     RECT  100.728 30.875 101.106 30.991 ;
     RECT  41.292 30.991 101.106 31.145 ;
     RECT  41.292 31.145 101.07 31.829 ;
     RECT  41.4 31.829 101.07 32.071 ;
     RECT  101.916 30.875 101.934 32.071 ;
     RECT  41.4 32.071 101.934 32.189 ;
     RECT  41.436 32.189 101.934 32.341 ;
     RECT  41.436 32.341 102.474 32.575 ;
     RECT  41.436 32.575 102.546 32.845 ;
     RECT  41.436 32.845 102.69 32.881 ;
     RECT  40.215 29.549 40.497 32.965 ;
     RECT  41.436 32.881 103.158 32.965 ;
     RECT  40.215 32.965 103.158 32.999 ;
     RECT  40.215 32.999 102.69 33.005 ;
     RECT  41.436 33.005 102.69 33.143 ;
     RECT  41.436 33.143 102.546 33.269 ;
     RECT  99.615 33.269 101.286 33.305 ;
     RECT  102.42 33.269 102.474 33.305 ;
     RECT  41.436 33.269 98.694 33.341 ;
     RECT  99.615 33.305 100.818 33.413 ;
     RECT  99.615 33.413 100.062 33.539 ;
     RECT  100.8 33.413 100.818 33.539 ;
     RECT  102.42 33.305 102.438 33.539 ;
     RECT  41.436 33.341 98.622 33.575 ;
     RECT  41.436 33.575 95.382 33.989 ;
     RECT  96.156 33.575 98.622 34.223 ;
     RECT  96.156 34.223 96.606 34.253 ;
     RECT  97.344 34.223 98.622 34.349 ;
     RECT  97.344 34.349 98.154 34.385 ;
     RECT  41.436 33.989 95.202 34.465 ;
     RECT  97.884 34.385 97.902 34.619 ;
     RECT  41.22 34.465 95.202 34.781 ;
     RECT  41.76 34.781 95.202 35.581 ;
     RECT  40.215 33.005 40.497 35.659 ;
     RECT  41.652 35.581 95.778 35.659 ;
     RECT  40.215 35.659 95.778 35.699 ;
     RECT  41.292 35.699 95.778 35.779 ;
     RECT  41.292 35.779 95.814 36.275 ;
     RECT  41.652 36.275 95.814 36.283 ;
     RECT  41.652 36.283 95.85 36.625 ;
     RECT  96.588 34.253 96.606 36.625 ;
     RECT  41.652 36.625 96.606 36.887 ;
     RECT  41.832 36.887 96.606 37.625 ;
     RECT  96.336 37.625 96.606 37.661 ;
     RECT  41.832 37.625 95.598 37.741 ;
     RECT  96.336 37.661 96.426 38.129 ;
     RECT  41.76 37.741 95.598 38.189 ;
     RECT  41.904 38.189 95.598 38.435 ;
     RECT  96.408 38.129 96.426 38.749 ;
     RECT  96.408 38.749 96.498 38.777 ;
     RECT  41.904 38.435 95.022 39.091 ;
     RECT  41.868 39.091 95.022 39.209 ;
     RECT  41.868 39.209 94.914 39.211 ;
     RECT  41.724 39.211 94.914 39.785 ;
     RECT  41.904 39.785 94.914 42.331 ;
     RECT  96.48 38.777 96.498 42.421 ;
     RECT  41.904 42.331 95.634 42.449 ;
     RECT  96.48 42.421 96.75 42.719 ;
     RECT  95.472 42.449 95.634 42.799 ;
     RECT  96.48 42.719 96.498 42.799 ;
     RECT  95.472 42.799 96.498 43.061 ;
     RECT  126.615 2.413 126.897 43.141 ;
     RECT  95.472 43.061 96.354 43.259 ;
     RECT  128.808 43.195 128.826 43.259 ;
     RECT  126.615 43.141 127.134 43.295 ;
     RECT  125.604 42.961 125.622 43.375 ;
     RECT  124.884 43.375 125.622 43.403 ;
     RECT  126.615 43.295 126.954 43.411 ;
     RECT  95.472 43.259 95.49 43.421 ;
     RECT  124.884 43.403 124.902 43.421 ;
     RECT  126.288 43.411 126.954 43.565 ;
     RECT  96.336 43.259 96.354 43.601 ;
     RECT  126.615 43.565 126.954 43.637 ;
     RECT  41.904 42.449 94.626 43.709 ;
     RECT  41.904 43.709 94.554 43.901 ;
     RECT  95.22 47.035 95.238 47.309 ;
     RECT  41.904 43.901 94.497 51.205 ;
     RECT  41.904 51.205 94.626 51.899 ;
     RECT  41.904 51.899 94.497 78.665 ;
     RECT  41.904 78.665 42.174 79.277 ;
     RECT  43.056 78.665 94.497 79.681 ;
     RECT  42.012 79.277 42.174 79.757 ;
     RECT  42.948 79.681 94.497 79.951 ;
     RECT  42.372 79.951 94.497 82.021 ;
     RECT  42.156 82.021 94.497 82.291 ;
     RECT  42.084 82.291 94.497 82.319 ;
     RECT  42.084 82.319 93.186 83.641 ;
     RECT  42.084 83.641 93.402 83.759 ;
     RECT  42.084 83.759 92.61 83.795 ;
     RECT  2.415 5.225 2.697 83.987 ;
     RECT  7.815 2.413 8.097 83.987 ;
     RECT  13.215 2.413 13.497 83.987 ;
     RECT  18.615 2.413 18.897 83.987 ;
     RECT  24.015 2.413 24.297 83.987 ;
     RECT  29.415 2.413 29.697 83.987 ;
     RECT  34.815 2.413 35.097 83.987 ;
     RECT  40.215 35.699 40.497 83.987 ;
     RECT  94.215 82.319 94.497 83.987 ;
     RECT  99.615 33.539 99.897 83.987 ;
     RECT  105.015 2.413 105.297 83.987 ;
     RECT  110.415 2.413 110.697 83.987 ;
     RECT  115.815 2.413 116.097 83.987 ;
     RECT  121.215 2.413 121.497 83.987 ;
     RECT  126.615 43.637 126.897 83.987 ;
     RECT  42.588 83.795 92.61 84.065 ;
     RECT  93.384 83.759 93.402 84.065 ;
     RECT  42.624 84.065 92.61 84.137 ;
     RECT  42.624 84.137 92.502 84.209 ;
     RECT  2.415 83.987 2.505 84.257 ;
     RECT  7.815 83.987 7.905 84.257 ;
     RECT  13.215 83.987 13.305 84.257 ;
     RECT  18.615 83.987 18.705 84.257 ;
     RECT  24.015 83.987 24.105 84.257 ;
     RECT  29.415 83.987 29.505 84.257 ;
     RECT  34.815 83.987 34.905 84.257 ;
     RECT  40.215 83.987 40.305 84.257 ;
     RECT  94.215 83.987 94.305 84.257 ;
     RECT  99.615 83.987 99.705 84.257 ;
     RECT  105.015 83.987 105.105 84.257 ;
     RECT  110.415 83.987 110.505 84.257 ;
     RECT  115.815 83.987 115.905 84.257 ;
     RECT  121.215 83.987 121.305 84.257 ;
     RECT  126.615 83.987 126.705 84.257 ;
     RECT  42.624 84.209 92.322 84.365 ;
     RECT  59.904 84.365 70.686 84.461 ;
     RECT  71.604 84.365 81.63 84.461 ;
     RECT  82.44 84.365 92.286 84.461 ;
     RECT  42.624 84.365 56.898 84.845 ;
     RECT  67.68 84.461 70.686 84.893 ;
     RECT  59.904 84.461 66.87 84.911 ;
     RECT  59.904 84.911 66.834 84.941 ;
     RECT  67.752 84.893 70.686 84.941 ;
     RECT  71.604 84.461 75.222 84.941 ;
     RECT  76.068 84.461 81.63 84.941 ;
     RECT  82.44 84.461 86.346 84.941 ;
     RECT  87.084 84.461 92.286 84.941 ;
     RECT  42.624 84.845 50.166 84.989 ;
     RECT  61.596 84.941 66.798 84.989 ;
     RECT  76.788 84.941 78.534 84.989 ;
     RECT  79.524 84.941 81.63 84.989 ;
     RECT  83.268 84.941 86.346 84.989 ;
     RECT  87.336 84.941 92.142 84.989 ;
     RECT  42.624 84.989 49.77 85.037 ;
     RECT  50.904 84.845 56.898 85.037 ;
     RECT  83.268 84.989 86.058 85.037 ;
     RECT  57.78 84.365 59.022 85.421 ;
     RECT  85.284 85.037 86.058 85.421 ;
     RECT  62.028 84.989 66.798 85.469 ;
     RECT  67.896 84.941 70.686 85.469 ;
     RECT  42.624 85.037 47.79 85.517 ;
     RECT  48.6 85.037 49.77 85.517 ;
     RECT  50.904 85.037 56.754 85.517 ;
     RECT  57.78 85.421 58.986 85.517 ;
     RECT  59.904 84.941 60.426 85.517 ;
     RECT  62.028 85.469 62.91 85.517 ;
     RECT  63.684 85.469 66.798 85.517 ;
     RECT  67.896 85.469 69.894 85.517 ;
     RECT  70.668 85.469 70.686 85.517 ;
     RECT  74.304 84.941 75.114 85.517 ;
     RECT  77.292 84.989 78.534 85.517 ;
     RECT  79.524 84.989 80.766 85.517 ;
     RECT  83.268 85.037 84.258 85.517 ;
     RECT  85.284 85.421 86.022 85.517 ;
     RECT  87.336 84.989 88.578 85.517 ;
     RECT  89.856 84.989 92.142 85.517 ;
     RECT  42.624 85.517 43.038 85.565 ;
     RECT  48.78 85.517 48.978 85.565 ;
     RECT  51.372 85.517 52.362 85.565 ;
     RECT  66.168 85.517 66.798 85.565 ;
     RECT  43.02 85.565 43.038 85.613 ;
     RECT  46.044 85.517 47.79 85.613 ;
     RECT  77.292 85.517 78.39 85.997 ;
     RECT  57.78 85.517 57.798 86.011 ;
     RECT  52.02 85.565 52.362 86.045 ;
     RECT  67.896 85.517 68.346 86.045 ;
     RECT  57.492 86.011 57.798 86.059 ;
     RECT  47.16 85.613 47.79 86.141 ;
     RECT  53.388 85.517 54.774 86.141 ;
     RECT  71.604 84.941 73.458 86.189 ;
     RECT  77.616 85.997 78.39 86.189 ;
     RECT  47.16 86.141 47.754 86.237 ;
     RECT  52.02 86.045 52.29 86.237 ;
     RECT  57.348 86.059 57.798 86.237 ;
     RECT  62.028 85.517 62.73 86.237 ;
     RECT  88.02 85.517 88.182 86.237 ;
     RECT  91.512 85.517 91.71 86.237 ;
     RECT  44.244 85.517 44.262 86.285 ;
     RECT  46.044 85.613 46.422 86.285 ;
     RECT  47.16 86.237 47.574 86.285 ;
     RECT  48.96 85.565 48.978 86.285 ;
     RECT  52.02 86.237 52.038 86.285 ;
     RECT  53.964 86.141 54.774 86.285 ;
     RECT  57.492 86.237 57.798 86.285 ;
     RECT  62.028 86.237 62.046 86.285 ;
     RECT  64.08 85.517 64.098 86.285 ;
     RECT  65.304 85.517 65.322 86.285 ;
     RECT  66.78 85.565 66.798 86.285 ;
     RECT  67.896 86.045 67.914 86.285 ;
     RECT  71.604 86.189 71.622 86.285 ;
     RECT  72.756 86.189 73.458 86.285 ;
     RECT  77.616 86.189 78.354 86.285 ;
     RECT  80.1 85.517 80.118 86.285 ;
     RECT  81.612 84.989 81.63 86.285 ;
     RECT  83.124 86.059 83.142 86.285 ;
     RECT  85.284 85.517 85.842 86.285 ;
     RECT  88.02 86.237 88.038 86.285 ;
     RECT  91.692 86.237 91.71 86.285 ;
    LAYER M4 ;
     RECT  0.06 4.032 0.227 5.016 ;
     RECT  0.227 4.992 2.408 5.016 ;
     RECT  0.181 41.664 2.408 41.688 ;
     RECT  2.408 2.148 2.512 84.252 ;
     RECT  2.512 2.418 2.704 83.982 ;
     RECT  2.704 41.664 7.808 41.688 ;
     RECT  7.808 2.148 7.912 84.252 ;
     RECT  7.912 2.418 8.104 83.982 ;
     RECT  8.104 41.664 13.208 41.688 ;
     RECT  13.208 2.148 13.312 84.252 ;
     RECT  13.312 2.418 13.504 83.982 ;
     RECT  13.504 41.664 18.608 41.688 ;
     RECT  18.608 2.148 18.712 84.252 ;
     RECT  18.712 2.418 18.904 83.982 ;
     RECT  18.904 41.664 24.008 41.688 ;
     RECT  24.008 2.148 24.112 84.252 ;
     RECT  24.112 2.418 24.304 83.982 ;
     RECT  24.304 41.664 29.408 41.688 ;
     RECT  29.408 2.148 29.512 84.252 ;
     RECT  29.512 2.418 29.704 83.982 ;
     RECT  29.704 41.664 34.808 41.688 ;
     RECT  34.808 2.148 34.912 84.252 ;
     RECT  34.912 2.418 35.104 83.982 ;
     RECT  39.985 26.256 40.208 26.28 ;
     RECT  40.165 29.52 40.208 29.544 ;
     RECT  35.104 41.664 40.208 41.688 ;
     RECT  40.208 2.148 40.312 84.252 ;
     RECT  40.312 2.418 40.504 83.982 ;
     RECT  40.504 32.16 41.075 33.576 ;
     RECT  40.504 34.752 41.075 36.264 ;
     RECT  40.504 20.16 41.105 20.568 ;
     RECT  40.504 28.416 41.177 29.544 ;
     RECT  41.177 29.52 41.357 29.544 ;
     RECT  40.504 22.032 41.537 25.128 ;
     RECT  40.504 26.256 41.564 26.28 ;
     RECT  40.504 19.104 41.569 19.128 ;
     RECT  41.105 20.16 41.569 20.184 ;
     RECT  41.537 23.136 41.717 25.128 ;
     RECT  41.708 39.216 41.749 39.24 ;
     RECT  41.564 26.256 41.893 26.76 ;
     RECT  41.569 19.104 41.933 20.184 ;
     RECT  41.893 26.256 41.933 26.856 ;
     RECT  41.933 19.536 42.041 20.184 ;
     RECT  41.075 33.552 42.073 33.576 ;
     RECT  41.075 34.752 42.073 34.776 ;
     RECT  41.717 23.136 42.077 24.072 ;
     RECT  42.041 20.16 42.14 20.184 ;
     RECT  42.14 20.16 42.153 21 ;
     RECT  41.537 22.032 42.153 22.056 ;
     RECT  42.077 23.328 42.172 24.072 ;
     RECT  42.073 33.552 42.181 34.776 ;
     RECT  41.075 35.952 42.181 36.264 ;
     RECT  42.153 20.16 42.185 22.056 ;
     RECT  42.185 20.16 42.227 21.96 ;
     RECT  42.181 33.552 42.325 36.264 ;
     RECT  42.227 20.16 42.329 20.184 ;
     RECT  42.428 14.304 42.469 14.328 ;
     RECT  41.749 38.16 42.469 39.24 ;
     RECT  41.177 28.416 42.505 28.44 ;
     RECT  42.469 14.112 42.515 14.328 ;
     RECT  42.505 28.176 42.545 28.44 ;
     RECT  42.325 33.552 42.563 36.504 ;
     RECT  42.563 33.84 42.565 36.504 ;
     RECT  42.469 38.16 42.565 40.152 ;
     RECT  42.565 33.84 42.709 40.152 ;
     RECT  42.469 12.528 42.725 12.552 ;
     RECT  41.075 32.16 42.757 32.184 ;
     RECT  40.504 41.664 42.757 41.688 ;
     RECT  42.793 1.776 42.901 1.8 ;
     RECT  42.469 9.792 42.901 9.816 ;
     RECT  42.469 10.848 42.901 10.872 ;
     RECT  42.613 85.536 42.901 85.56 ;
     RECT  42.901 9.792 42.941 10.872 ;
     RECT  42.937 83.952 42.973 83.976 ;
     RECT  41.933 26.448 43.009 26.856 ;
     RECT  42.901 85.488 43.009 85.56 ;
     RECT  42.901 1.728 43.042 1.8 ;
     RECT  42.361 0.144 43.081 0.168 ;
     RECT  42.709 33.84 43.085 40.68 ;
     RECT  42.361 78.624 43.085 78.648 ;
     RECT  42.001 79.728 43.085 79.752 ;
     RECT  42.973 18.816 43.117 18.84 ;
     RECT  42.973 30.288 43.117 30.312 ;
     RECT  43.009 85.488 43.139 85.608 ;
     RECT  43.085 33.84 43.157 37.608 ;
     RECT  43.081 0.144 43.165 0.6 ;
     RECT  43.117 18.768 43.225 18.84 ;
     RECT  42.973 83.856 43.253 83.976 ;
     RECT  43.165 0.144 43.261 0.168 ;
     RECT  43.253 83.856 43.261 84.36 ;
     RECT  43.261 0.096 43.262 0.168 ;
     RECT  42.829 17.088 43.285 17.112 ;
     RECT  43.225 18.768 43.333 19.56 ;
     RECT  43.081 76.368 43.333 76.392 ;
     RECT  43.261 83.808 43.333 84.36 ;
     RECT  43.009 26.448 43.337 27 ;
     RECT  43.333 83.76 43.337 84.36 ;
     RECT  42.545 28.176 43.373 28.2 ;
     RECT  43.333 18.768 43.441 20.136 ;
     RECT  42.227 21.936 43.441 21.96 ;
     RECT  43.189 43.68 43.477 43.704 ;
     RECT  43.139 85.488 43.477 85.512 ;
     RECT  43.085 38.64 43.513 40.68 ;
     RECT  42.757 41.664 43.513 41.784 ;
     RECT  43.477 43.344 43.513 43.704 ;
     RECT  42.757 4.56 43.517 4.584 ;
     RECT  43.333 75.936 43.525 76.392 ;
     RECT  43.337 26.448 43.553 26.904 ;
     RECT  43.285 17.088 43.589 17.64 ;
     RECT  42.515 14.112 43.657 14.136 ;
     RECT  42.757 32.16 43.657 32.808 ;
     RECT  43.157 33.84 43.657 36.264 ;
     RECT  43.513 38.64 43.661 43.704 ;
     RECT  43.525 74.448 43.697 76.392 ;
     RECT  42.941 9.984 43.733 10.872 ;
     RECT  43.717 28.464 43.765 28.488 ;
     RECT  43.117 29.52 43.765 30.312 ;
     RECT  43.657 32.16 43.837 36.264 ;
     RECT  43.765 28.464 43.861 30.312 ;
     RECT  43.837 31.872 43.861 36.264 ;
     RECT  43.441 18.768 43.877 21.96 ;
     RECT  43.861 28.464 43.877 36.264 ;
     RECT  43.661 38.688 43.877 43.704 ;
     RECT  43.262 0.096 43.907 0.12 ;
     RECT  43.877 29.52 43.907 31.896 ;
     RECT  43.553 26.448 43.913 26.856 ;
     RECT  43.907 30.72 43.921 31.896 ;
     RECT  43.697 74.448 43.949 74.472 ;
     RECT  43.877 32.88 43.955 36.264 ;
     RECT  42.172 23.328 43.981 23.352 ;
     RECT  43.157 37.584 44.003 37.608 ;
     RECT  43.909 82.608 44.021 82.632 ;
     RECT  43.877 40.56 44.057 43.704 ;
     RECT  43.697 75.504 44.057 76.392 ;
     RECT  43.477 84.96 44.099 85.512 ;
     RECT  42.469 6.24 44.233 6.264 ;
     RECT  43.981 23.328 44.233 23.688 ;
     RECT  44.099 85.488 44.233 85.512 ;
     RECT  43.657 14.112 44.237 14.856 ;
     RECT  43.042 1.728 44.3 1.848 ;
     RECT  44.057 40.656 44.305 43.704 ;
     RECT  43.589 17.088 44.377 17.112 ;
     RECT  44.233 23.328 44.377 24.408 ;
     RECT  44.233 85.488 44.387 86.28 ;
     RECT  44.125 77.568 44.389 77.592 ;
     RECT  44.405 80.832 44.413 80.856 ;
     RECT  44.305 82.08 44.413 82.104 ;
     RECT  44.377 16.56 44.417 17.112 ;
     RECT  44.237 14.208 44.425 14.856 ;
     RECT  44.377 23.328 44.437 25.464 ;
     RECT  43.913 26.448 44.437 26.568 ;
     RECT  43.337 83.76 44.449 83.88 ;
     RECT  43.921 30.72 44.453 31.32 ;
     RECT  44.341 11.232 44.485 11.256 ;
     RECT  44.389 77.568 44.489 78.12 ;
     RECT  44.413 80.832 44.525 82.104 ;
     RECT  43.877 19.632 44.557 21.96 ;
     RECT  44.437 23.328 44.557 26.568 ;
     RECT  44.492 0.528 44.579 0.552 ;
     RECT  44.449 83.76 44.629 84.504 ;
     RECT  43.877 38.688 44.665 39.528 ;
     RECT  44.305 40.656 44.773 44.376 ;
     RECT  44.845 18.336 44.917 18.36 ;
     RECT  44.057 75.504 44.917 75.96 ;
     RECT  44.233 5.76 44.989 6.264 ;
     RECT  44.773 40.656 44.989 45.048 ;
     RECT  44.953 3.408 45.025 3.432 ;
     RECT  44.557 19.632 45.025 26.568 ;
     RECT  45.025 3.408 45.061 3.912 ;
     RECT  44.989 5.136 45.061 6.264 ;
     RECT  45.013 7.968 45.061 7.992 ;
     RECT  44.525 82.032 45.061 82.104 ;
     RECT  44.629 83.232 45.061 84.504 ;
     RECT  44.981 0.576 45.064 0.6 ;
     RECT  44.917 74.592 45.109 75.96 ;
     RECT  44.629 79.2 45.169 79.224 ;
     RECT  43.733 9.984 45.205 10.008 ;
     RECT  44.485 11.232 45.205 11.976 ;
     RECT  44.989 40.656 45.241 45.48 ;
     RECT  45.061 7.344 45.277 7.992 ;
     RECT  43.955 33.6 45.277 36.264 ;
     RECT  45.061 82.032 45.301 84.504 ;
     RECT  44.387 85.488 45.301 85.512 ;
     RECT  45.277 33.264 45.313 36.264 ;
     RECT  45.241 40.656 45.397 45.768 ;
     RECT  44.417 16.56 45.421 16.584 ;
     RECT  44.917 17.712 45.421 18.36 ;
     RECT  43.877 28.464 45.421 28.488 ;
     RECT  45.313 33.264 45.529 37.128 ;
     RECT  44.665 38.208 45.529 39.528 ;
     RECT  44.3 1.728 45.608 2.28 ;
     RECT  45.061 3.408 45.608 6.264 ;
     RECT  45.277 7.344 45.608 8.472 ;
     RECT  45.205 9.984 45.608 11.976 ;
     RECT  44.425 14.208 45.608 14.232 ;
     RECT  45.341 15.312 45.608 15.336 ;
     RECT  45.421 16.56 45.608 18.36 ;
     RECT  45.025 19.632 45.608 26.616 ;
     RECT  45.421 27.648 45.608 28.488 ;
     RECT  43.907 29.52 45.608 29.544 ;
     RECT  44.453 30.96 45.608 31.32 ;
     RECT  45.529 33.264 45.608 39.528 ;
     RECT  45.397 40.656 45.608 46.248 ;
     RECT  45.109 74.4 45.608 75.96 ;
     RECT  44.489 77.568 45.608 77.592 ;
     RECT  45.169 79.2 45.608 79.56 ;
     RECT  44.621 80.736 45.608 80.76 ;
     RECT  45.301 82.032 45.608 85.512 ;
     RECT  45.064 0.576 45.685 0.648 ;
     RECT  45.608 1.728 45.685 85.512 ;
     RECT  45.685 0.576 45.781 85.512 ;
     RECT  45.781 0.384 45.904 86.28 ;
     RECT  45.904 0.384 45.925 3.576 ;
     RECT  45.925 0.288 45.973 3.576 ;
     RECT  45.904 19.344 46.019 30.984 ;
     RECT  45.904 32.688 46.037 36.744 ;
     RECT  45.973 0.144 46.045 3.576 ;
     RECT  46.045 0.144 46.069 3.048 ;
     RECT  45.904 11.136 46.073 11.976 ;
     RECT  46.069 0.096 46.115 3.048 ;
     RECT  45.904 39.264 46.115 46.248 ;
     RECT  46.019 22.56 46.145 30.984 ;
     RECT  46.115 0.096 46.153 0.552 ;
     RECT  45.904 4.56 46.181 8.712 ;
     RECT  46.145 22.56 46.181 29.544 ;
     RECT  46.153 0.144 46.217 0.552 ;
     RECT  46.115 1.728 46.217 3.048 ;
     RECT  46.181 4.56 46.217 8.472 ;
     RECT  46.181 22.56 46.217 26.616 ;
     RECT  46.217 22.752 46.253 26.616 ;
     RECT  46.115 44.832 46.289 46.248 ;
     RECT  46.145 30.672 46.325 30.984 ;
     RECT  45.904 78.624 46.325 86.28 ;
     RECT  46.037 35.28 46.397 36.744 ;
     RECT  45.904 16.944 46.433 17.736 ;
     RECT  46.037 32.688 46.433 33.912 ;
     RECT  46.217 1.728 46.499 2.328 ;
     RECT  46.181 27.648 46.499 29.544 ;
     RECT  46.217 0.192 46.577 0.552 ;
     RECT  46.433 16.944 46.577 17.64 ;
     RECT  45.904 74.592 46.595 77.592 ;
     RECT  46.325 80.688 46.595 86.28 ;
     RECT  46.115 39.264 46.613 43.848 ;
     RECT  46.595 74.592 46.613 75.096 ;
     RECT  46.595 80.688 46.613 83.832 ;
     RECT  46.397 35.328 46.643 36.744 ;
     RECT  46.433 32.688 46.649 33.864 ;
     RECT  46.019 19.344 46.685 21.576 ;
     RECT  46.217 4.56 46.721 6.84 ;
     RECT  46.685 20.976 46.732 21.576 ;
     RECT  46.685 19.344 46.757 19.656 ;
     RECT  46.643 35.568 46.757 36.744 ;
     RECT  45.904 49.008 46.757 49.032 ;
     RECT  46.325 30.672 46.801 30.792 ;
     RECT  46.613 39.264 46.829 43.608 ;
     RECT  45.904 10.128 46.901 10.152 ;
     RECT  46.577 0.528 46.937 0.552 ;
     RECT  46.757 36.24 47.005 36.744 ;
     RECT  46.757 19.632 47.045 19.656 ;
     RECT  46.732 21.12 47.045 21.576 ;
     RECT  46.649 32.688 47.077 33.72 ;
     RECT  46.721 4.56 47.116 4.584 ;
     RECT  47.077 31.872 47.123 33.72 ;
     RECT  46.595 76.32 47.125 77.592 ;
     RECT  46.325 78.624 47.125 79.224 ;
     RECT  47.005 36.24 47.149 37.128 ;
     RECT  46.577 17.04 47.153 17.64 ;
     RECT  46.217 8.16 47.257 8.472 ;
     RECT  46.253 23.664 47.269 26.616 ;
     RECT  46.499 27.648 47.269 28.488 ;
     RECT  46.613 74.688 47.297 75.096 ;
     RECT  45.904 13.104 47.317 13.992 ;
     RECT  46.829 39.264 47.317 40.056 ;
     RECT  46.289 44.832 47.333 46.2 ;
     RECT  47.317 12.912 47.363 14.28 ;
     RECT  46.801 30.672 47.369 30.696 ;
     RECT  47.125 76.32 47.372 79.224 ;
     RECT  46.829 43.344 47.405 43.608 ;
     RECT  47.372 76.32 47.405 79.272 ;
     RECT  47.405 43.584 47.411 43.608 ;
     RECT  47.149 36.24 47.437 37.464 ;
     RECT  46.721 5.664 47.473 6.84 ;
     RECT  46.499 29.52 47.473 29.544 ;
     RECT  47.045 21.12 47.477 21.528 ;
     RECT  47.123 33.696 47.513 33.72 ;
     RECT  46.073 11.136 47.516 11.544 ;
     RECT  47.516 11.136 47.545 11.832 ;
     RECT  47.257 8.16 47.581 9.144 ;
     RECT  46.595 84.864 47.585 86.28 ;
     RECT  47.545 10.848 47.603 11.832 ;
     RECT  47.473 5.664 47.621 6.888 ;
     RECT  47.437 36.24 47.621 38.232 ;
     RECT  47.581 7.92 47.653 9.144 ;
     RECT  47.293 3.312 47.701 3.336 ;
     RECT  47.269 23.664 47.717 28.488 ;
     RECT  47.701 3.264 47.749 3.336 ;
     RECT  47.405 76.896 47.749 79.272 ;
     RECT  47.717 23.328 47.761 28.488 ;
     RECT  47.585 84.864 47.765 86.232 ;
     RECT  47.653 7.44 47.801 9.144 ;
     RECT  47.363 12.912 47.801 13.128 ;
     RECT  47.765 84.864 47.801 86.136 ;
     RECT  47.749 76.896 47.836 79.848 ;
     RECT  47.749 3.264 47.843 4.296 ;
     RECT  47.843 3.36 47.845 4.296 ;
     RECT  47.297 75.072 47.852 75.096 ;
     RECT  46.613 80.928 47.861 83.832 ;
     RECT  47.801 84.864 47.861 85.56 ;
     RECT  47.473 29.52 47.873 30.216 ;
     RECT  47.603 10.848 47.909 11.544 ;
     RECT  47.836 76.896 47.909 79.272 ;
     RECT  47.861 80.928 47.941 85.56 ;
     RECT  47.801 7.92 47.977 9.144 ;
     RECT  47.909 10.848 47.977 11.16 ;
     RECT  47.941 80.256 48.017 85.56 ;
     RECT  47.317 39.216 48.035 40.056 ;
     RECT  48.035 39.216 48.076 39.288 ;
     RECT  46.499 1.728 48.121 2.28 ;
     RECT  47.153 17.472 48.121 17.64 ;
     RECT  48.017 80.256 48.131 80.952 ;
     RECT  48.017 81.984 48.131 85.56 ;
     RECT  47.845 3.408 48.265 4.296 ;
     RECT  48.121 16.992 48.301 17.64 ;
     RECT  48.013 19.872 48.301 19.896 ;
     RECT  47.477 21.12 48.301 21.144 ;
     RECT  48.193 49.008 48.305 49.032 ;
     RECT  48.121 1.728 48.323 2.328 ;
     RECT  48.131 81.984 48.323 84.408 ;
     RECT  48.301 16.656 48.337 17.64 ;
     RECT  46.829 41.136 48.373 42.312 ;
     RECT  47.852 75.072 48.373 75.672 ;
     RECT  47.909 77.52 48.413 79.272 ;
     RECT  48.323 82.08 48.449 84.408 ;
     RECT  48.337 16.656 48.481 18.6 ;
     RECT  48.301 19.872 48.481 21.144 ;
     RECT  47.333 44.88 48.521 46.2 ;
     RECT  48.449 82.08 48.521 83.256 ;
     RECT  48.445 0.096 48.529 0.12 ;
     RECT  48.131 80.256 48.556 80.904 ;
     RECT  48.556 80.352 48.563 80.904 ;
     RECT  47.873 29.616 48.589 30.216 ;
     RECT  47.123 31.872 48.589 31.896 ;
     RECT  48.521 44.88 48.589 45.816 ;
     RECT  48.481 16.656 48.625 21.144 ;
     RECT  48.373 40.992 48.659 42.312 ;
     RECT  48.589 43.92 48.673 45.816 ;
     RECT  48.265 3.408 48.697 4.68 ;
     RECT  47.621 5.664 48.697 6.312 ;
     RECT  47.363 14.256 48.697 14.28 ;
     RECT  48.697 3.408 48.769 6.312 ;
     RECT  47.621 36.24 48.769 37.032 ;
     RECT  47.621 38.016 48.769 38.232 ;
     RECT  48.373 75.072 48.773 75.864 ;
     RECT  48.563 80.352 48.773 80.712 ;
     RECT  48.769 3.408 48.803 6.84 ;
     RECT  48.769 36.24 48.805 38.232 ;
     RECT  48.076 39.216 48.805 39.24 ;
     RECT  48.625 16.128 48.809 21.144 ;
     RECT  48.589 29.616 48.841 31.896 ;
     RECT  48.131 85.488 48.853 85.56 ;
     RECT  48.697 14.256 48.901 14.856 ;
     RECT  48.773 75.696 48.949 75.864 ;
     RECT  48.809 16.512 48.956 21.144 ;
     RECT  48.803 3.408 48.985 4.68 ;
     RECT  48.853 85.488 48.989 86.28 ;
     RECT  48.841 29.616 48.995 32.472 ;
     RECT  48.449 84.384 48.995 84.408 ;
     RECT  47.801 13.104 48.997 13.128 ;
     RECT  47.761 22.752 48.997 28.488 ;
     RECT  48.995 29.616 48.997 30.024 ;
     RECT  47.941 34.032 48.997 34.056 ;
     RECT  48.997 33.072 49.021 34.056 ;
     RECT  48.995 31.008 49.025 31.896 ;
     RECT  49.021 33.072 49.052 34.248 ;
     RECT  49.052 33.072 49.061 35.016 ;
     RECT  48.997 13.008 49.069 13.128 ;
     RECT  48.659 40.992 49.093 42.168 ;
     RECT  49.021 0.576 49.105 0.6 ;
     RECT  47.977 7.92 49.129 11.16 ;
     RECT  48.949 75.696 49.129 76.392 ;
     RECT  48.413 77.52 49.129 78.696 ;
     RECT  49.093 40.464 49.133 42.168 ;
     RECT  49.061 33.072 49.139 33.096 ;
     RECT  49.061 34.224 49.139 35.016 ;
     RECT  48.805 36.24 49.165 39.24 ;
     RECT  49.133 40.464 49.165 42.024 ;
     RECT  49.069 13.008 49.187 13.032 ;
     RECT  48.803 5.664 49.189 6.84 ;
     RECT  49.129 7.92 49.189 11.352 ;
     RECT  49.189 5.664 49.205 11.352 ;
     RECT  48.989 85.488 49.237 85.512 ;
     RECT  48.323 1.728 49.283 2.28 ;
     RECT  49.237 85.44 49.309 85.512 ;
     RECT  49.205 5.904 49.379 11.352 ;
     RECT  48.805 74.496 49.388 74.52 ;
     RECT  49.129 75.696 49.42 78.696 ;
     RECT  48.521 82.656 49.429 83.256 ;
     RECT  49.379 5.904 49.457 6.264 ;
     RECT  49.379 7.344 49.457 11.352 ;
     RECT  49.388 74.448 49.475 74.52 ;
     RECT  49.165 36.24 49.565 42.024 ;
     RECT  48.985 3.312 49.571 4.68 ;
     RECT  49.565 36.24 49.571 37.032 ;
     RECT  49.025 31.872 49.601 31.896 ;
     RECT  49.42 75.696 49.619 78.744 ;
     RECT  48.673 44.88 49.741 45.816 ;
     RECT  49.457 7.392 49.777 11.352 ;
     RECT  49.477 12.528 49.777 12.552 ;
     RECT  49.309 85.344 49.781 85.512 ;
     RECT  49.429 82.656 49.849 84.36 ;
     RECT  49.139 34.224 49.853 34.44 ;
     RECT  49.571 36.48 49.859 37.032 ;
     RECT  48.773 80.592 49.861 80.712 ;
     RECT  49.571 3.312 49.885 3.432 ;
     RECT  48.997 22.752 49.885 30.024 ;
     RECT  49.859 36.528 49.925 37.032 ;
     RECT  48.956 16.512 49.957 21.192 ;
     RECT  49.885 22.272 49.957 30.024 ;
     RECT  49.619 75.696 49.993 75.864 ;
     RECT  49.619 76.896 50.033 78.744 ;
     RECT  49.741 44.88 50.044 46.728 ;
     RECT  49.189 43.344 50.065 43.56 ;
     RECT  49.849 82.08 50.101 84.36 ;
     RECT  49.565 38.064 50.149 42.024 ;
     RECT  49.957 16.512 50.245 30.024 ;
     RECT  49.861 80.592 50.245 80.808 ;
     RECT  48.901 14.208 50.273 14.856 ;
     RECT  49.283 1.728 50.281 1.848 ;
     RECT  50.101 82.08 50.281 84.984 ;
     RECT  49.571 4.56 50.3 4.68 ;
     RECT  50.197 86.208 50.387 86.232 ;
     RECT  50.065 43.296 50.389 43.56 ;
     RECT  50.044 44.88 50.389 45.576 ;
     RECT  50.033 77.904 50.389 78.744 ;
     RECT  50.3 4.56 50.437 4.872 ;
     RECT  49.457 5.904 50.437 5.928 ;
     RECT  50.245 80.352 50.485 80.808 ;
     RECT  50.281 82.032 50.485 84.984 ;
     RECT  50.281 1.104 50.533 1.848 ;
     RECT  49.885 2.88 50.533 3.432 ;
     RECT  50.437 4.56 50.533 5.928 ;
     RECT  49.777 7.392 50.533 12.552 ;
     RECT  49.853 34.416 50.533 34.44 ;
     RECT  50.492 35.472 50.533 35.496 ;
     RECT  49.993 74.976 50.533 75.864 ;
     RECT  50.485 80.352 50.713 84.984 ;
     RECT  50.533 4.56 50.773 12.552 ;
     RECT  50.389 77.904 50.773 79.08 ;
     RECT  50.713 80.208 50.773 84.984 ;
     RECT  50.713 0.096 50.819 0.12 ;
     RECT  50.533 1.104 50.821 3.432 ;
     RECT  50.773 4.512 50.821 12.552 ;
     RECT  50.533 34.416 50.857 35.496 ;
     RECT  50.857 33.6 50.869 35.496 ;
     RECT  49.925 36.528 50.869 36.552 ;
     RECT  50.273 13.632 50.893 14.856 ;
     RECT  50.773 77.904 50.893 84.984 ;
     RECT  50.893 13.632 50.929 14.952 ;
     RECT  50.821 0.192 51.008 12.552 ;
     RECT  50.929 13.632 51.008 15.048 ;
     RECT  50.245 16.512 51.008 30.84 ;
     RECT  50.869 33.6 51.008 36.552 ;
     RECT  50.149 38.064 51.008 42.216 ;
     RECT  50.389 43.296 51.008 45.576 ;
     RECT  50.044 46.704 51.008 46.728 ;
     RECT  50.533 74.64 51.008 75.864 ;
     RECT  50.033 76.896 51.008 76.92 ;
     RECT  50.893 77.904 51.008 85.56 ;
     RECT  51.008 0.192 51.011 85.56 ;
     RECT  51.011 0.192 51.304 84.408 ;
     RECT  51.304 13.632 51.365 15.048 ;
     RECT  51.304 17.088 51.365 30.408 ;
     RECT  51.365 17.088 51.401 29.592 ;
     RECT  51.304 41.136 51.437 46.008 ;
     RECT  51.011 85.392 51.443 85.56 ;
     RECT  51.365 13.632 51.473 14.952 ;
     RECT  51.304 77.904 51.473 81 ;
     RECT  51.473 79.056 51.509 81 ;
     RECT  51.304 82.032 51.545 84.408 ;
     RECT  51.545 82.56 51.553 84.408 ;
     RECT  51.304 0.192 51.683 12.024 ;
     RECT  51.683 0.192 51.689 3.528 ;
     RECT  51.401 29.04 51.761 29.064 ;
     RECT  51.553 83.808 51.833 84.408 ;
     RECT  51.833 83.808 51.875 84.312 ;
     RECT  51.689 0.192 51.901 2.28 ;
     RECT  51.304 40.08 51.905 40.104 ;
     RECT  51.443 85.488 51.925 85.56 ;
     RECT  51.901 0.096 52.049 2.28 ;
     RECT  51.925 85.488 52.049 86.28 ;
     RECT  51.401 17.088 52.085 28.008 ;
     RECT  52.085 17.088 52.157 25.272 ;
     RECT  51.509 80.352 52.157 81 ;
     RECT  52.049 0.096 52.163 1.848 ;
     RECT  52.157 17.088 52.201 21.432 ;
     RECT  52.157 22.992 52.265 25.272 ;
     RECT  51.683 4.512 52.333 12.024 ;
     RECT  51.473 13.632 52.333 14.76 ;
     RECT  52.201 19.344 52.337 21.432 ;
     RECT  51.304 16.032 52.369 16.056 ;
     RECT  51.437 41.136 52.405 42.552 ;
     RECT  51.437 43.536 52.405 46.008 ;
     RECT  52.405 41.136 52.441 46.008 ;
     RECT  52.333 4.512 52.453 12.12 ;
     RECT  52.333 13.104 52.453 14.76 ;
     RECT  51.304 36 52.477 36.648 ;
     RECT  51.509 79.056 52.513 79.224 ;
     RECT  52.157 80.352 52.513 80.376 ;
     RECT  51.473 77.904 52.549 77.928 ;
     RECT  52.513 79.056 52.549 80.376 ;
     RECT  52.453 4.512 52.553 14.76 ;
     RECT  52.441 41.136 52.585 46.056 ;
     RECT  52.369 15.936 52.621 16.056 ;
     RECT  52.201 17.088 52.621 18.216 ;
     RECT  51.304 38.208 52.621 38.712 ;
     RECT  52.585 40.704 52.621 46.056 ;
     RECT  52.265 23.28 52.625 25.272 ;
     RECT  52.553 5.712 52.661 14.76 ;
     RECT  52.621 38.208 52.705 39.384 ;
     RECT  52.085 26.256 52.765 28.008 ;
     RECT  51.553 82.56 52.789 82.584 ;
     RECT  51.875 83.808 52.789 83.928 ;
     RECT  52.729 33.12 52.801 33.144 ;
     RECT  52.705 38.208 52.835 39.288 ;
     RECT  52.597 81.456 52.837 81.48 ;
     RECT  52.789 82.56 52.837 83.928 ;
     RECT  52.163 0.096 52.841 0.12 ;
     RECT  52.337 19.44 52.841 21.432 ;
     RECT  52.621 40.704 52.877 46.104 ;
     RECT  51.689 3.312 52.885 3.528 ;
     RECT  52.553 4.512 52.885 4.536 ;
     RECT  52.661 5.712 52.913 14.424 ;
     RECT  52.801 33.072 52.945 33.144 ;
     RECT  52.885 3.312 52.979 4.536 ;
     RECT  52.765 26.256 52.981 28.296 ;
     RECT  51.304 34.416 52.981 34.44 ;
     RECT  52.477 36 52.981 36.936 ;
     RECT  52.049 85.488 53.021 86.232 ;
     RECT  52.945 33.024 53.029 33.144 ;
     RECT  52.981 34.416 53.029 36.936 ;
     RECT  52.7 75.648 53.029 75.672 ;
     RECT  52.163 1.728 53.036 1.848 ;
     RECT  52.835 38.88 53.057 39.288 ;
     RECT  52.913 5.712 53.065 12.936 ;
     RECT  53.029 33.024 53.075 36.936 ;
     RECT  52.841 19.872 53.129 21.432 ;
     RECT  52.873 29.664 53.161 29.688 ;
     RECT  53.029 75.648 53.18 76.392 ;
     RECT  53.036 1.728 53.197 2.28 ;
     RECT  52.979 3.312 53.197 3.672 ;
     RECT  53.057 38.88 53.201 38.904 ;
     RECT  52.625 23.28 53.233 24.744 ;
     RECT  53.18 75.552 53.267 76.392 ;
     RECT  51.304 31.728 53.269 31.752 ;
     RECT  53.075 36 53.269 36.936 ;
     RECT  52.549 77.904 53.297 80.376 ;
     RECT  52.837 81.456 53.297 83.928 ;
     RECT  53.269 31.728 53.356 31.848 ;
     RECT  52.621 15.936 53.413 18.216 ;
     RECT  53.356 31.728 53.413 31.752 ;
     RECT  53.413 31.296 53.453 31.752 ;
     RECT  53.267 76.368 53.453 76.392 ;
     RECT  53.065 5.904 53.459 12.936 ;
     RECT  53.413 15.936 53.459 18.84 ;
     RECT  53.297 77.904 53.525 83.928 ;
     RECT  52.981 26.256 53.561 28.536 ;
     RECT  53.525 77.904 53.561 82.824 ;
     RECT  53.233 22.512 53.605 24.744 ;
     RECT  53.561 26.256 53.605 28.008 ;
     RECT  53.605 22.512 53.629 28.008 ;
     RECT  53.197 1.728 53.633 3.672 ;
     RECT  53.525 83.808 53.653 83.928 ;
     RECT  53.557 84.912 53.653 84.936 ;
     RECT  52.877 40.848 53.677 45 ;
     RECT  53.629 22.224 53.692 28.008 ;
     RECT  53.692 26.256 53.705 28.008 ;
     RECT  53.561 77.952 53.705 82.824 ;
     RECT  53.459 15.936 53.747 17.544 ;
     RECT  52.877 45.984 53.747 46.104 ;
     RECT  53.125 47.904 53.747 47.928 ;
     RECT  53.161 51.312 53.809 51.336 ;
     RECT  52.913 14.4 53.845 14.424 ;
     RECT  53.677 44.064 53.845 45 ;
     RECT  53.747 45.984 53.845 46.056 ;
     RECT  53.459 18.672 53.849 18.84 ;
     RECT  53.161 29.664 53.849 30.12 ;
     RECT  53.509 74.64 53.885 74.664 ;
     RECT  53.845 44.064 53.891 46.056 ;
     RECT  53.845 14.4 53.893 14.856 ;
     RECT  53.021 86.112 53.909 86.232 ;
     RECT  53.893 13.392 53.939 14.856 ;
     RECT  53.891 44.208 53.957 46.056 ;
     RECT  53.459 5.904 53.993 12.312 ;
     RECT  53.849 18.672 53.993 18.696 ;
     RECT  53.849 30.096 54.029 30.12 ;
     RECT  53.957 44.784 54.083 46.056 ;
     RECT  53.993 5.904 54.085 12.216 ;
     RECT  53.075 33.072 54.097 34.776 ;
     RECT  53.269 36 54.097 37.08 ;
     RECT  53.677 40.848 54.097 43.032 ;
     RECT  54.083 44.832 54.101 46.056 ;
     RECT  53.705 77.952 54.137 82.728 ;
     RECT  54.097 39.264 54.14 39.288 ;
     RECT  54.097 40.272 54.14 43.032 ;
     RECT  54.101 46.032 54.173 46.056 ;
     RECT  53.881 0.528 54.205 0.552 ;
     RECT  53.653 83.808 54.229 84.936 ;
     RECT  53.909 86.112 54.229 86.28 ;
     RECT  53.129 19.872 54.241 21.144 ;
     RECT  53.692 22.224 54.241 25.224 ;
     RECT  54.097 33.072 54.241 37.08 ;
     RECT  54.14 39.264 54.241 43.032 ;
     RECT  54.137 80.4 54.245 82.728 ;
     RECT  54.205 0.528 54.289 0.6 ;
     RECT  54.241 38.352 54.313 43.032 ;
     RECT  53.809 51.312 54.313 51.672 ;
     RECT  54.085 5.712 54.353 12.216 ;
     RECT  53.939 13.392 54.389 14.424 ;
     RECT  54.245 80.4 54.412 82.68 ;
     RECT  54.353 5.904 54.419 12.216 ;
     RECT  54.313 38.208 54.421 43.032 ;
     RECT  54.412 80.88 54.425 82.68 ;
     RECT  54.241 33.072 54.457 37.176 ;
     RECT  54.421 38.16 54.457 43.032 ;
     RECT  54.313 50.736 54.461 51.672 ;
     RECT  54.389 13.392 54.497 14.184 ;
     RECT  53.453 31.296 54.497 31.32 ;
     RECT  54.457 33.072 54.497 43.032 ;
     RECT  54.425 80.928 54.515 82.68 ;
     RECT  54.497 13.392 54.533 13.944 ;
     RECT  54.229 83.808 54.563 86.28 ;
     RECT  53.705 27.744 54.637 28.008 ;
     RECT  54.133 47.28 54.641 47.88 ;
     RECT  53.633 1.728 54.673 3.528 ;
     RECT  54.497 36.528 54.673 43.032 ;
     RECT  53.705 26.256 54.709 26.664 ;
     RECT  54.637 27.744 54.709 28.248 ;
     RECT  54.673 1.728 54.745 4.488 ;
     RECT  54.241 19.872 54.749 25.224 ;
     RECT  54.641 47.472 54.749 47.88 ;
     RECT  54.457 30.192 54.773 30.216 ;
     RECT  54.563 85.488 54.796 86.28 ;
     RECT  54.773 30.192 54.857 30.84 ;
     RECT  54.497 33.072 54.857 35.496 ;
     RECT  54.709 26.256 54.86 28.248 ;
     RECT  54.745 1.632 54.908 4.488 ;
     RECT  54.86 26.256 54.947 28.968 ;
     RECT  54.857 34.704 54.965 35.496 ;
     RECT  54.908 1.632 54.995 4.536 ;
     RECT  54.673 36.528 55.001 43.128 ;
     RECT  54.947 26.256 55.004 28.536 ;
     RECT  55.001 36.576 55.033 43.128 ;
     RECT  55.033 36.576 55.073 43.368 ;
     RECT  55.004 25.968 55.091 28.536 ;
     RECT  54.419 5.904 55.145 10.296 ;
     RECT  55.073 38.16 55.145 38.28 ;
     RECT  54.419 11.376 55.18 11.832 ;
     RECT  54.097 74.592 55.18 74.616 ;
     RECT  55.18 74.592 55.181 74.664 ;
     RECT  54.137 77.952 55.205 79.272 ;
     RECT  54.515 81.408 55.213 82.68 ;
     RECT  54.563 83.808 55.213 84.36 ;
     RECT  53.557 49.584 55.237 49.608 ;
     RECT  54.857 33.072 55.249 33.576 ;
     RECT  55.181 74.64 55.285 74.664 ;
     RECT  54.995 1.632 55.289 4.488 ;
     RECT  55.091 26.256 55.289 28.536 ;
     RECT  55.249 33.024 55.321 33.576 ;
     RECT  55.285 74.64 55.331 74.856 ;
     RECT  54.101 44.832 55.357 44.952 ;
     RECT  55.073 39.888 55.361 43.368 ;
     RECT  55.145 38.16 55.397 38.184 ;
     RECT  55.237 49.248 55.397 49.608 ;
     RECT  54.289 0.528 55.427 0.552 ;
     RECT  54.461 50.976 55.429 51.672 ;
     RECT  55.331 74.688 55.429 74.856 ;
     RECT  54.709 76.368 55.429 76.392 ;
     RECT  55.289 1.632 55.465 1.752 ;
     RECT  54.857 30.192 55.465 30.216 ;
     RECT  53.747 16.272 55.477 17.544 ;
     RECT  55.357 44.832 55.501 45.768 ;
     RECT  55.477 16.272 55.573 18.168 ;
     RECT  55.573 15.84 55.621 18.168 ;
     RECT  54.749 19.872 55.645 24.936 ;
     RECT  55.145 5.904 55.669 9.672 ;
     RECT  55.213 81.408 55.669 84.36 ;
     RECT  55.465 14.544 55.681 14.568 ;
     RECT  55.18 11.376 55.789 11.544 ;
     RECT  55.681 14.544 55.789 14.76 ;
     RECT  55.621 15.84 55.789 18.216 ;
     RECT  55.429 74.688 55.789 76.392 ;
     RECT  55.465 30.048 55.82 30.216 ;
     RECT  55.501 44.832 55.861 45.864 ;
     RECT  54.749 47.472 55.861 47.496 ;
     RECT  55.789 74.688 55.897 76.968 ;
     RECT  55.205 77.952 55.897 79.8 ;
     RECT  55.669 80.832 55.957 84.36 ;
     RECT  54.796 85.488 55.957 86.232 ;
     RECT  54.965 34.896 56.053 35.496 ;
     RECT  55.789 14.544 56.077 18.216 ;
     RECT  55.82 30 56.077 30.216 ;
     RECT  55.073 36.576 56.077 37.08 ;
     RECT  55.897 74.688 56.101 79.8 ;
     RECT  55.321 32.304 56.113 33.576 ;
     RECT  56.053 34.896 56.113 35.544 ;
     RECT  55.645 19.824 56.185 24.936 ;
     RECT  55.289 26.256 56.185 26.664 ;
     RECT  55.429 50.976 56.185 51.912 ;
     RECT  55.465 1.104 56.195 1.752 ;
     RECT  56.101 74.688 56.197 79.848 ;
     RECT  55.957 80.832 56.197 86.232 ;
     RECT  56.077 14.544 56.221 18.792 ;
     RECT  56.185 19.824 56.221 26.664 ;
     RECT  55.289 2.736 56.245 4.488 ;
     RECT  56.113 32.304 56.257 35.544 ;
     RECT  56.077 36.576 56.257 37.704 ;
     RECT  55.669 5.712 56.293 9.672 ;
     RECT  55.361 43.008 56.329 43.368 ;
     RECT  56.245 2.736 56.365 4.68 ;
     RECT  56.293 5.712 56.365 9.912 ;
     RECT  56.365 2.736 56.401 9.912 ;
     RECT  55.789 11.136 56.401 11.544 ;
     RECT  56.185 50.016 56.401 51.912 ;
     RECT  56.195 1.728 56.408 1.752 ;
     RECT  56.401 2.736 56.408 11.544 ;
     RECT  54.533 13.392 56.408 13.416 ;
     RECT  56.221 14.544 56.408 26.664 ;
     RECT  55.289 27.744 56.408 28.536 ;
     RECT  56.077 30 56.408 30.984 ;
     RECT  56.257 32.304 56.408 37.704 ;
     RECT  55.361 39.888 56.408 41.688 ;
     RECT  56.329 42.72 56.408 43.368 ;
     RECT  55.861 44.832 56.408 47.496 ;
     RECT  55.825 48.48 56.408 48.504 ;
     RECT  56.401 49.872 56.408 51.912 ;
     RECT  56.197 74.688 56.408 86.232 ;
     RECT  56.408 1.728 56.704 86.232 ;
     RECT  56.704 48.24 56.729 48.504 ;
     RECT  56.704 32.304 56.915 39.288 ;
     RECT  56.704 49.872 56.981 51.96 ;
     RECT  56.704 77.952 57.045 86.232 ;
     RECT  57.045 78.624 57.052 86.232 ;
     RECT  56.704 14.496 57.053 16.296 ;
     RECT  56.437 0.096 57.061 0.12 ;
     RECT  56.915 32.736 57.089 39.288 ;
     RECT  57.053 14.496 57.197 15.336 ;
     RECT  57.052 80.88 57.203 86.232 ;
     RECT  56.704 75.84 57.299 76.92 ;
     RECT  56.704 1.728 57.305 4.68 ;
     RECT  57.203 80.88 57.305 81 ;
     RECT  57.197 14.496 57.341 14.856 ;
     RECT  57.052 78.624 57.413 79.8 ;
     RECT  57.203 82.032 57.442 86.232 ;
     RECT  57.442 82.032 57.457 86.28 ;
     RECT  57.457 82.08 57.493 86.28 ;
     RECT  57.305 1.728 57.539 2.28 ;
     RECT  56.704 5.712 57.593 12.984 ;
     RECT  56.704 17.472 57.629 28.296 ;
     RECT  57.341 14.496 57.648 14.52 ;
     RECT  57.593 5.712 57.697 9.624 ;
     RECT  57.089 32.784 57.697 39.288 ;
     RECT  56.704 29.808 57.733 30.984 ;
     RECT  56.729 48.24 57.773 48.264 ;
     RECT  56.704 74.016 57.809 74.088 ;
     RECT  57.629 17.472 57.841 28.008 ;
     RECT  56.704 42.72 57.841 43.32 ;
     RECT  57.493 84.96 57.853 86.28 ;
     RECT  57.841 42.72 57.877 43.848 ;
     RECT  56.704 44.88 57.877 46.92 ;
     RECT  57.841 17.088 57.923 28.008 ;
     RECT  57.877 42.72 57.923 46.92 ;
     RECT  57.805 13.968 57.989 13.992 ;
     RECT  57.299 76.032 57.989 76.92 ;
     RECT  57.305 3.312 58.057 4.68 ;
     RECT  57.697 5.664 58.057 9.624 ;
     RECT  57.923 17.088 58.057 18.84 ;
     RECT  57.923 42.72 58.057 43.992 ;
     RECT  57.923 19.872 58.061 28.008 ;
     RECT  56.981 49.872 58.093 51.336 ;
     RECT  56.704 40.416 58.097 41.688 ;
     RECT  58.093 49.488 58.117 51.336 ;
     RECT  57.413 79.776 58.117 79.8 ;
     RECT  57.305 80.88 58.117 80.904 ;
     RECT  57.373 0.528 58.129 0.552 ;
     RECT  58.057 16.896 58.129 18.84 ;
     RECT  58.097 40.848 58.129 41.688 ;
     RECT  58.057 42.672 58.129 43.992 ;
     RECT  57.853 84.96 58.133 85.512 ;
     RECT  58.117 48.912 58.163 51.336 ;
     RECT  57.493 82.08 58.163 83.832 ;
     RECT  58.129 0.528 58.165 0.6 ;
     RECT  58.061 26.256 58.169 28.008 ;
     RECT  58.165 0.48 58.213 0.6 ;
     RECT  58.129 16.56 58.241 18.84 ;
     RECT  58.129 40.848 58.241 43.992 ;
     RECT  57.913 52.368 58.273 52.392 ;
     RECT  58.213 0.48 58.307 0.504 ;
     RECT  57.593 10.656 58.309 12.984 ;
     RECT  58.057 3.312 58.345 9.624 ;
     RECT  58.345 3.072 58.349 9.624 ;
     RECT  58.241 16.56 58.453 17.688 ;
     RECT  58.117 79.776 58.453 80.904 ;
     RECT  58.237 54.672 58.457 54.696 ;
     RECT  57.989 76.368 58.481 76.92 ;
     RECT  58.453 79.776 58.489 81 ;
     RECT  58.163 82.08 58.489 82.68 ;
     RECT  57.733 28.992 58.529 30.984 ;
     RECT  57.697 32.784 58.529 39.336 ;
     RECT  58.489 79.776 58.54 82.68 ;
     RECT  58.453 16.464 58.561 17.688 ;
     RECT  57.923 45.792 58.565 46.92 ;
     RECT  58.481 76.368 58.565 77.544 ;
     RECT  58.273 52.368 58.601 52.68 ;
     RECT  58.349 4.368 58.645 9.624 ;
     RECT  58.309 10.656 58.645 13.08 ;
     RECT  58.529 29.376 58.669 30.984 ;
     RECT  58.529 32.784 58.669 38.808 ;
     RECT  58.669 29.376 58.691 38.808 ;
     RECT  58.601 52.368 58.705 52.392 ;
     RECT  58.163 83.808 58.716 83.832 ;
     RECT  58.561 15.36 58.739 17.688 ;
     RECT  58.645 4.368 58.745 13.08 ;
     RECT  58.241 40.896 58.745 43.992 ;
     RECT  58.565 45.792 58.745 46.824 ;
     RECT  58.745 45.936 58.781 46.824 ;
     RECT  58.745 40.896 58.817 43.752 ;
     RECT  58.169 27.744 58.849 28.008 ;
     RECT  58.745 4.464 58.853 13.08 ;
     RECT  58.691 29.376 58.961 38.712 ;
     RECT  57.539 1.728 59.065 1.896 ;
     RECT  58.349 3.072 59.065 3.336 ;
     RECT  57.809 74.016 59.065 74.04 ;
     RECT  58.961 34.224 59.075 38.712 ;
     RECT  58.133 85.392 59.077 85.512 ;
     RECT  58.716 83.808 59.093 83.88 ;
     RECT  58.849 27.744 59.141 28.296 ;
     RECT  59.065 74.016 59.149 74.664 ;
     RECT  58.163 48.912 59.164 51.096 ;
     RECT  59.075 34.8 59.177 38.712 ;
     RECT  57.413 78.624 59.221 78.696 ;
     RECT  58.54 79.776 59.221 80.52 ;
     RECT  59.164 48.912 59.245 49.368 ;
     RECT  58.169 26.256 59.281 26.76 ;
     RECT  59.141 27.744 59.281 27.864 ;
     RECT  59.177 35.136 59.285 38.712 ;
     RECT  59.164 50.4 59.285 51.096 ;
     RECT  59.221 78.624 59.315 80.52 ;
     RECT  58.54 81.504 59.317 82.68 ;
     RECT  59.093 83.808 59.317 84.36 ;
     RECT  58.853 6.384 59.357 13.08 ;
     RECT  58.961 29.376 59.357 33.048 ;
     RECT  59.281 26.256 59.389 27.864 ;
     RECT  59.285 35.28 59.401 38.712 ;
     RECT  58.993 39.792 59.425 39.816 ;
     RECT  58.817 40.896 59.425 43.272 ;
     RECT  59.401 38.16 59.429 38.712 ;
     RECT  58.781 45.936 59.429 46.776 ;
     RECT  58.565 76.368 59.429 76.92 ;
     RECT  59.315 78.624 59.437 79.944 ;
     RECT  59.065 1.728 59.569 3.336 ;
     RECT  58.241 18.816 59.569 18.84 ;
     RECT  59.317 81.504 59.569 84.36 ;
     RECT  59.429 45.936 59.573 46.728 ;
     RECT  59.245 48.384 59.573 49.368 ;
     RECT  59.573 48.384 59.633 49.32 ;
     RECT  59.429 38.208 59.645 38.712 ;
     RECT  59.357 6.384 59.651 12.552 ;
     RECT  59.645 38.352 59.681 38.712 ;
     RECT  59.429 76.896 59.681 76.92 ;
     RECT  59.401 35.28 59.699 37.032 ;
     RECT  59.681 38.544 59.717 38.712 ;
     RECT  59.633 48.336 59.717 49.32 ;
     RECT  59.569 80.976 59.717 84.36 ;
     RECT  59.717 80.976 59.753 82.776 ;
     RECT  58.061 19.872 59.785 24.744 ;
     RECT  59.389 26.208 59.785 27.864 ;
     RECT  59.285 50.688 59.785 51.096 ;
     RECT  58.705 52.272 59.785 52.392 ;
     RECT  59.717 48.384 59.789 49.32 ;
     RECT  59.425 39.792 59.821 43.272 ;
     RECT  59.317 0.576 59.845 0.6 ;
     RECT  58.853 4.464 59.857 5.352 ;
     RECT  59.651 6.384 59.857 11.4 ;
     RECT  59.717 38.64 59.857 38.712 ;
     RECT  59.797 78.048 59.884 78.12 ;
     RECT  58.739 15.552 59.929 17.688 ;
     RECT  59.569 18.768 59.929 18.84 ;
     RECT  59.785 19.872 59.929 27.864 ;
     RECT  59.437 79.584 59.969 79.944 ;
     RECT  59.845 0.144 60.035 0.6 ;
     RECT  59.929 15.504 60.037 17.688 ;
     RECT  59.929 18.768 60.037 27.864 ;
     RECT  60.037 15.504 60.113 27.864 ;
     RECT  60.037 75.216 60.121 75.24 ;
     RECT  59.569 1.728 60.133 3.48 ;
     RECT  59.857 4.464 60.133 11.4 ;
     RECT  60.133 1.728 60.185 11.4 ;
     RECT  59.821 39.792 60.221 44.136 ;
     RECT  60.221 40.416 60.257 44.136 ;
     RECT  59.149 74.016 60.289 74.04 ;
     RECT  60.035 0.24 60.323 0.6 ;
     RECT  59.651 12.528 60.325 12.552 ;
     RECT  59.785 50.688 60.329 52.392 ;
     RECT  59.077 85.44 60.361 85.512 ;
     RECT  60.113 19.872 60.397 27.864 ;
     RECT  59.357 29.376 60.397 33 ;
     RECT  60.325 12.528 60.409 13.128 ;
     RECT  59.857 38.64 60.433 38.808 ;
     RECT  60.185 11.376 60.437 11.4 ;
     RECT  59.884 78.096 60.437 78.12 ;
     RECT  60.361 85.392 60.437 85.512 ;
     RECT  60.437 85.392 60.445 85.416 ;
     RECT  59.717 83.76 60.469 84.36 ;
     RECT  60.257 40.464 60.473 44.136 ;
     RECT  60.185 1.728 60.509 10.344 ;
     RECT  59.789 48.912 60.509 49.32 ;
     RECT  60.113 15.504 60.541 18.792 ;
     RECT  59.753 82.08 60.581 82.776 ;
     RECT  60.397 19.872 60.652 33 ;
     RECT  60.541 14.784 60.709 18.792 ;
     RECT  60.581 82.656 60.821 82.776 ;
     RECT  60.469 83.76 60.821 84.936 ;
     RECT  59.969 79.824 60.829 79.944 ;
     RECT  59.753 80.976 60.829 81 ;
     RECT  60.509 2.832 60.833 10.344 ;
     RECT  60.329 50.688 60.833 51.096 ;
     RECT  60.289 34.464 60.901 34.488 ;
     RECT  60.901 34.416 60.973 34.488 ;
     RECT  59.699 35.52 60.973 37.032 ;
     RECT  59.573 45.984 60.973 46.728 ;
     RECT  60.709 14.4 61.004 18.792 ;
     RECT  61.004 13.632 61.081 18.792 ;
     RECT  60.652 19.872 61.081 25.08 ;
     RECT  60.652 26.112 61.081 33 ;
     RECT  60.973 34.032 61.081 37.032 ;
     RECT  60.433 38.64 61.081 38.856 ;
     RECT  60.509 49.248 61.117 49.32 ;
     RECT  60.829 79.824 61.261 81 ;
     RECT  61.261 79.824 61.297 81.048 ;
     RECT  60.473 40.464 61.333 43.08 ;
     RECT  60.329 52.368 61.369 52.392 ;
     RECT  60.613 76.32 61.381 76.344 ;
     RECT  60.833 2.88 61.405 10.344 ;
     RECT  60.973 45.984 61.441 46.92 ;
     RECT  61.081 26.112 61.477 38.856 ;
     RECT  61.333 39.888 61.477 43.08 ;
     RECT  60.833 51.072 61.573 51.096 ;
     RECT  61.369 52.176 61.573 52.392 ;
     RECT  61.297 79.824 61.573 81.144 ;
     RECT  60.821 82.656 61.573 84.936 ;
     RECT  61.117 49.248 61.585 49.608 ;
     RECT  61.573 79.824 61.585 84.936 ;
     RECT  61.405 2.88 61.621 10.728 ;
     RECT  61.585 79.824 61.621 84.984 ;
     RECT  61.513 63.072 61.649 63.096 ;
     RECT  60.323 0.576 61.669 0.6 ;
     RECT  61.441 45.984 61.669 47.88 ;
     RECT  61.585 49.2 61.693 49.608 ;
     RECT  61.253 78.624 61.729 78.648 ;
     RECT  61.621 79.776 61.763 84.984 ;
     RECT  60.509 1.728 61.808 1.848 ;
     RECT  61.621 2.88 61.808 10.92 ;
     RECT  60.829 12.24 61.808 12.504 ;
     RECT  61.081 13.632 61.808 25.08 ;
     RECT  61.477 26.112 61.808 43.08 ;
     RECT  60.473 44.064 61.808 44.136 ;
     RECT  61.669 45.984 61.808 47.928 ;
     RECT  61.693 49.008 61.808 49.608 ;
     RECT  61.573 51.072 61.808 52.392 ;
     RECT  61.649 63.072 61.808 63.24 ;
     RECT  60.289 74.016 61.808 74.712 ;
     RECT  61.381 76.32 61.808 76.776 ;
     RECT  61.729 78.384 61.808 78.648 ;
     RECT  61.763 79.776 61.808 84.408 ;
     RECT  61.808 1.728 61.955 84.408 ;
     RECT  61.669 86.208 61.973 86.232 ;
     RECT  61.973 86.208 62.057 86.28 ;
     RECT  61.955 1.728 62.104 84.36 ;
     RECT  62.057 86.208 62.197 86.232 ;
     RECT  62.104 77.568 62.201 84.36 ;
     RECT  61.669 0.144 62.237 0.6 ;
     RECT  62.104 14.736 62.243 29.64 ;
     RECT  62.104 1.728 62.453 13.656 ;
     RECT  62.243 14.832 62.489 29.64 ;
     RECT  62.104 38.688 62.531 52.44 ;
     RECT  62.489 14.928 62.561 29.64 ;
     RECT  62.104 76.32 62.561 76.344 ;
     RECT  62.453 7.248 62.579 13.656 ;
     RECT  62.579 7.248 62.627 13.416 ;
     RECT  62.561 14.928 62.661 17.16 ;
     RECT  62.661 14.928 62.705 15.048 ;
     RECT  62.197 85.392 62.774 86.232 ;
     RECT  62.661 16.08 62.813 17.16 ;
     RECT  62.237 0.144 62.818 0.456 ;
     RECT  62.201 77.568 62.819 84.024 ;
     RECT  62.705 14.928 62.849 15 ;
     RECT  62.819 77.568 62.885 82.776 ;
     RECT  62.849 14.976 62.921 15 ;
     RECT  62.813 16.272 62.921 17.16 ;
     RECT  62.104 30.768 62.921 37.656 ;
     RECT  62.453 1.728 63.059 6.264 ;
     RECT  62.885 77.568 63.209 80.472 ;
     RECT  62.885 81.456 63.209 82.776 ;
     RECT  62.818 0.096 63.217 0.456 ;
     RECT  62.921 33.84 63.241 37.656 ;
     RECT  62.561 18.192 63.245 29.64 ;
     RECT  62.819 83.808 63.253 84.024 ;
     RECT  62.531 38.688 63.299 47.976 ;
     RECT  63.245 28.752 63.313 29.64 ;
     RECT  62.921 30.768 63.313 32.856 ;
     RECT  63.233 0.576 63.317 0.6 ;
     RECT  63.059 1.728 63.385 1.8 ;
     RECT  63.253 83.808 63.385 84.408 ;
     RECT  62.774 85.392 63.385 85.512 ;
     RECT  63.313 28.752 63.389 32.856 ;
     RECT  63.059 2.832 63.491 6.264 ;
     RECT  63.385 83.808 63.491 85.512 ;
     RECT  63.209 77.568 63.529 80.376 ;
     RECT  63.241 33.84 63.569 37.704 ;
     RECT  62.627 7.872 63.601 13.416 ;
     RECT  63.299 40.224 63.637 47.976 ;
     RECT  62.531 48.96 63.637 52.44 ;
     RECT  63.491 83.808 63.749 84.408 ;
     RECT  63.601 7.872 63.817 13.704 ;
     RECT  63.529 76.992 63.821 80.376 ;
     RECT  63.491 85.488 63.829 85.512 ;
     RECT  63.349 54.672 63.857 54.696 ;
     RECT  63.817 7.872 63.868 14.28 ;
     RECT  63.821 76.992 63.877 77.016 ;
     RECT  63.817 75.792 63.889 75.816 ;
     RECT  63.299 38.688 63.925 39.24 ;
     RECT  63.389 29.088 63.961 32.856 ;
     RECT  63.569 33.84 63.961 37.656 ;
     RECT  63.868 13.632 63.997 14.28 ;
     RECT  63.961 29.088 64.001 37.656 ;
     RECT  62.104 74.016 64.021 74.712 ;
     RECT  63.889 75.792 64.021 75.864 ;
     RECT  63.868 7.872 64.108 12.552 ;
     RECT  63.829 85.488 64.109 86.28 ;
     RECT  64.108 7.872 64.145 11.976 ;
     RECT  63.385 1.152 64.163 1.8 ;
     RECT  63.491 4.992 64.177 6.264 ;
     RECT  64.001 34.128 64.181 37.656 ;
     RECT  63.821 78.432 64.181 80.376 ;
     RECT  63.209 82.032 64.213 82.776 ;
     RECT  64.163 1.728 64.241 1.8 ;
     RECT  63.491 2.832 64.241 3.96 ;
     RECT  64.177 4.992 64.285 6.312 ;
     RECT  64.285 4.992 64.307 6.84 ;
     RECT  63.997 13.632 64.325 14.856 ;
     RECT  63.245 18.192 64.393 27.768 ;
     RECT  62.921 16.272 64.46 16.872 ;
     RECT  64.213 81.792 64.493 82.776 ;
     RECT  63.749 83.808 64.493 84.36 ;
     RECT  64.46 16.272 64.501 16.968 ;
     RECT  64.181 78.768 64.501 80.376 ;
     RECT  64.493 81.792 64.501 84.36 ;
     RECT  64.307 6.72 64.573 6.84 ;
     RECT  64.145 7.872 64.573 11.688 ;
     RECT  64.001 29.088 64.573 33.096 ;
     RECT  64.241 1.728 64.597 3.96 ;
     RECT  64.307 4.992 64.597 5.736 ;
     RECT  64.501 15.84 64.645 16.968 ;
     RECT  64.393 18.192 64.645 27.912 ;
     RECT  64.645 15.84 64.685 27.912 ;
     RECT  64.181 34.128 64.685 37.512 ;
     RECT  64.325 13.632 64.729 14.808 ;
     RECT  64.501 78.768 64.757 84.36 ;
     RECT  64.021 74.016 64.789 75.864 ;
     RECT  63.877 76.944 64.789 77.016 ;
     RECT  64.573 28.992 64.793 33.096 ;
     RECT  64.789 74.016 64.793 77.016 ;
     RECT  64.685 15.84 64.829 18.696 ;
     RECT  64.793 74.592 64.837 77.016 ;
     RECT  63.637 40.224 64.865 52.44 ;
     RECT  64.837 74.64 64.933 77.016 ;
     RECT  64.865 40.224 64.937 48.36 ;
     RECT  64.865 50.016 64.937 52.44 ;
     RECT  64.933 74.64 64.937 77.592 ;
     RECT  64.757 80.352 64.937 84.36 ;
     RECT  64.937 50.16 64.973 52.44 ;
     RECT  64.937 75.216 64.979 77.592 ;
     RECT  64.793 29.088 65.005 33.096 ;
     RECT  64.685 34.128 65.005 36.936 ;
     RECT  64.979 75.216 65.009 76.392 ;
     RECT  64.973 50.16 65.017 51.912 ;
     RECT  64.829 16.272 65.045 18.696 ;
     RECT  64.969 0.576 65.053 0.6 ;
     RECT  64.729 13.632 65.117 14.28 ;
     RECT  64.685 19.872 65.149 27.912 ;
     RECT  64.757 78.768 65.18 79.272 ;
     RECT  64.109 85.488 65.249 86.232 ;
     RECT  65.249 85.488 65.333 86.28 ;
     RECT  63.925 38.64 65.365 39.24 ;
     RECT  64.937 40.224 65.365 48.12 ;
     RECT  64.937 80.976 65.405 84.36 ;
     RECT  64.573 6.72 65.413 11.688 ;
     RECT  65.333 85.488 65.44 85.56 ;
     RECT  65.045 16.512 65.441 18.696 ;
     RECT  64.597 1.728 65.501 5.736 ;
     RECT  65.413 6.72 65.501 12.552 ;
     RECT  65.501 1.728 65.545 12.552 ;
     RECT  65.365 38.64 65.555 48.12 ;
     RECT  65.555 38.64 65.617 39.48 ;
     RECT  65.005 29.088 65.651 36.936 ;
     RECT  65.405 82.08 65.653 84.36 ;
     RECT  65.653 82.08 65.795 84.408 ;
     RECT  65.651 32.256 65.797 36.936 ;
     RECT  65.221 53.568 65.797 53.592 ;
     RECT  65.797 32.256 65.833 36.984 ;
     RECT  65.149 19.872 65.869 27.96 ;
     RECT  65.009 75.264 65.873 76.392 ;
     RECT  65.117 14.16 65.905 14.28 ;
     RECT  65.441 16.8 65.941 18.696 ;
     RECT  65.869 19.872 65.941 28.008 ;
     RECT  65.405 80.976 65.941 81 ;
     RECT  65.017 50.16 65.977 51.528 ;
     RECT  64.979 77.424 65.977 77.592 ;
     RECT  65.18 78.672 65.977 79.272 ;
     RECT  65.941 16.8 66.133 28.008 ;
     RECT  65.651 29.088 66.133 31.224 ;
     RECT  65.833 32.256 66.133 37.08 ;
     RECT  65.617 38.496 66.133 39.48 ;
     RECT  65.977 77.424 66.133 79.272 ;
     RECT  65.941 80.544 66.133 81 ;
     RECT  65.555 40.56 66.157 48.12 ;
     RECT  66.133 32.256 66.179 39.48 ;
     RECT  65.977 49.44 66.229 51.528 ;
     RECT  66.157 40.56 66.265 48.408 ;
     RECT  66.229 49.44 66.265 51.672 ;
     RECT  65.873 75.264 66.301 75.384 ;
     RECT  65.797 52.896 66.38 53.592 ;
     RECT  65.545 1.728 66.467 13.128 ;
     RECT  65.905 14.16 66.589 15.384 ;
     RECT  66.133 16.8 66.589 31.224 ;
     RECT  65.873 76.368 66.6 76.392 ;
     RECT  66.133 77.424 66.6 81 ;
     RECT  65.44 85.44 66.659 85.56 ;
     RECT  66.589 14.16 66.661 31.224 ;
     RECT  66.179 32.256 66.661 38.808 ;
     RECT  66.697 0.096 66.709 0.12 ;
     RECT  66.6 76.368 66.725 81 ;
     RECT  65.795 82.08 66.725 84.36 ;
     RECT  66.709 0.096 66.781 0.312 ;
     RECT  66.725 76.368 66.805 84.36 ;
     RECT  66.709 86.16 66.809 86.28 ;
     RECT  66.467 2.148 66.877 13.128 ;
     RECT  66.661 14.16 66.877 38.808 ;
     RECT  66.38 52.656 67.093 53.592 ;
     RECT  66.301 74.592 67.093 75.384 ;
     RECT  66.805 76.368 67.093 84.936 ;
     RECT  66.877 2.148 67.208 38.808 ;
     RECT  66.265 40.56 67.208 51.672 ;
     RECT  67.093 52.656 67.208 53.928 ;
     RECT  62.104 63.072 67.208 63.096 ;
     RECT  67.093 74.592 67.208 84.936 ;
     RECT  66.781 0.144 67.285 0.312 ;
     RECT  67.285 0.144 67.385 1.128 ;
     RECT  67.208 2.148 67.477 84.936 ;
     RECT  67.477 1.728 67.504 84.936 ;
     RECT  67.385 0.144 67.763 0.168 ;
     RECT  67.504 79.776 67.781 84.936 ;
     RECT  66.809 86.16 67.861 86.184 ;
     RECT  67.861 86.016 67.885 86.184 ;
     RECT  67.504 1.728 67.889 34.584 ;
     RECT  67.504 52.128 67.955 53.928 ;
     RECT  67.889 15.36 67.997 29.592 ;
     RECT  67.885 86.016 68.003 86.28 ;
     RECT  67.889 1.728 68.033 14.376 ;
     RECT  67.504 35.856 68.099 47.88 ;
     RECT  67.781 79.776 68.141 84.408 ;
     RECT  67.504 76.944 68.177 78.696 ;
     RECT  68.141 79.776 68.329 84.36 ;
     RECT  68.177 77.136 68.357 78.696 ;
     RECT  68.003 86.016 68.357 86.04 ;
     RECT  68.033 1.728 68.387 10.248 ;
     RECT  68.329 79.776 68.393 84.312 ;
     RECT  68.099 36.096 68.429 47.88 ;
     RECT  68.429 46.032 68.485 47.88 ;
     RECT  67.504 49.104 68.485 50.424 ;
     RECT  67.889 30.72 68.497 34.584 ;
     RECT  68.485 46.032 68.497 50.424 ;
     RECT  67.955 52.128 68.497 52.44 ;
     RECT  67.504 74.832 68.497 75.864 ;
     RECT  67.997 16.368 68.501 17.688 ;
     RECT  68.429 36.096 68.501 44.856 ;
     RECT  68.497 46.032 68.531 52.44 ;
     RECT  68.497 74.736 68.533 75.864 ;
     RECT  68.033 11.328 68.537 14.376 ;
     RECT  68.533 74.112 68.573 75.864 ;
     RECT  68.357 77.664 68.641 78.696 ;
     RECT  67.997 15.36 68.645 15.384 ;
     RECT  67.997 18.72 68.789 29.592 ;
     RECT  68.501 39.792 68.789 44.712 ;
     RECT  68.573 74.112 68.812 75.816 ;
     RECT  67.955 53.904 68.825 53.928 ;
     RECT  68.537 13.584 68.867 14.376 ;
     RECT  68.393 79.776 68.867 84.216 ;
     RECT  68.789 19.776 68.893 29.592 ;
     RECT  68.497 30.72 68.893 34.68 ;
     RECT  68.387 2.832 68.897 10.248 ;
     RECT  68.812 74.496 68.969 75.816 ;
     RECT  68.969 74.496 69.011 74.712 ;
     RECT  68.867 79.776 69.052 80.52 ;
     RECT  68.893 19.776 69.107 34.68 ;
     RECT  68.641 77.664 69.109 78.744 ;
     RECT  69.052 79.776 69.109 80.424 ;
     RECT  68.789 39.84 69.149 44.712 ;
     RECT  68.969 75.792 69.193 75.816 ;
     RECT  69.107 25.824 69.217 34.68 ;
     RECT  69.149 39.888 69.221 44.712 ;
     RECT  69.109 77.664 69.293 80.424 ;
     RECT  69.293 77.664 69.329 80.328 ;
     RECT  68.537 11.328 69.437 12.552 ;
     RECT  68.501 16.368 69.505 17.208 ;
     RECT  69.221 39.936 69.541 44.712 ;
     RECT  68.531 46.032 69.541 49.128 ;
     RECT  68.531 50.4 69.541 52.44 ;
     RECT  68.897 9.12 69.569 10.248 ;
     RECT  68.867 13.632 69.617 14.376 ;
     RECT  69.541 39.936 69.628 52.872 ;
     RECT  69.217 25.824 69.649 34.728 ;
     RECT  68.501 36.096 69.649 38.712 ;
     RECT  69.329 77.664 69.649 79.944 ;
     RECT  69.569 9.12 69.653 10.296 ;
     RECT  68.867 81.504 69.685 84.216 ;
     RECT  68.525 85.44 69.685 85.512 ;
     RECT  68.387 1.728 69.788 1.848 ;
     RECT  68.897 2.832 69.788 8.136 ;
     RECT  67.504 63.072 69.827 63.096 ;
     RECT  69.628 49.536 69.833 52.872 ;
     RECT  69.653 9.12 69.905 10.248 ;
     RECT  68.789 18.72 69.937 18.744 ;
     RECT  69.107 19.776 69.937 24.696 ;
     RECT  69.685 81.504 69.973 85.512 ;
     RECT  69.649 25.824 69.977 38.712 ;
     RECT  69.505 15.408 70.045 17.208 ;
     RECT  69.628 39.936 70.049 48.264 ;
     RECT  69.437 11.328 70.085 11.976 ;
     RECT  69.833 49.536 70.085 52.44 ;
     RECT  69.788 1.728 70.121 8.136 ;
     RECT  69.937 18.72 70.225 24.696 ;
     RECT  70.225 18.624 70.261 24.696 ;
     RECT  70.045 15.408 70.265 17.4 ;
     RECT  70.049 46.56 70.265 48.264 ;
     RECT  70.121 1.728 70.301 7.992 ;
     RECT  69.011 74.496 70.333 74.664 ;
     RECT  69.649 76.992 70.369 79.944 ;
     RECT  70.049 39.936 70.405 45.576 ;
     RECT  70.085 11.424 70.409 11.976 ;
     RECT  70.369 76.464 70.409 79.944 ;
     RECT  70.265 15.456 70.445 17.4 ;
     RECT  70.409 77.808 70.549 79.944 ;
     RECT  70.301 4.848 70.55 7.992 ;
     RECT  69.977 25.824 70.589 38.664 ;
     RECT  70.333 74.496 70.595 74.712 ;
     RECT  70.409 76.464 70.595 76.728 ;
     RECT  70.549 77.808 70.595 80.376 ;
     RECT  69.973 81.408 70.595 85.512 ;
     RECT  70.595 74.688 70.597 74.712 ;
     RECT  70.301 1.728 70.691 3.432 ;
     RECT  69.617 14.352 70.693 14.376 ;
     RECT  70.445 15.552 70.693 17.4 ;
     RECT  70.261 18.48 70.693 24.696 ;
     RECT  70.265 46.8 70.693 48.264 ;
     RECT  70.085 49.536 70.693 49.56 ;
     RECT  70.595 77.904 70.693 80.376 ;
     RECT  70.595 81.408 70.693 84.36 ;
     RECT  70.085 50.544 70.697 52.44 ;
     RECT  70.595 85.488 70.697 85.512 ;
     RECT  70.589 33.6 70.742 38.664 ;
     RECT  70.693 0.576 70.787 0.6 ;
     RECT  70.691 3.408 70.805 3.432 ;
     RECT  70.589 25.824 70.835 32.328 ;
     RECT  70.597 74.688 70.873 75.288 ;
     RECT  70.742 33.648 70.877 38.664 ;
     RECT  69.905 9.312 70.883 10.248 ;
     RECT  70.835 25.824 70.883 29.688 ;
     RECT  70.693 15.552 70.979 24.696 ;
     RECT  70.883 9.648 71.027 10.248 ;
     RECT  70.877 34.128 71.057 38.664 ;
     RECT  70.979 15.552 71.075 19.08 ;
     RECT  71.027 9.648 71.093 9.672 ;
     RECT  70.883 25.824 71.093 28.968 ;
     RECT  70.873 74.688 71.129 75.336 ;
     RECT  71.129 75.024 71.165 75.336 ;
     RECT  70.693 14.352 71.197 14.472 ;
     RECT  70.697 51.696 71.197 52.44 ;
     RECT  71.197 51.696 71.228 52.488 ;
     RECT  70.835 30.768 71.237 32.328 ;
     RECT  71.165 75.264 71.267 75.336 ;
     RECT  70.409 11.952 71.273 11.976 ;
     RECT  70.595 76.464 71.273 76.488 ;
     RECT  71.057 34.704 71.305 38.664 ;
     RECT  70.405 39.84 71.305 45.576 ;
     RECT  71.305 34.704 71.309 45.576 ;
     RECT  71.228 51.696 71.315 53.352 ;
     RECT  71.075 15.552 71.317 18.84 ;
     RECT  70.693 46.8 71.353 49.56 ;
     RECT  70.693 77.904 71.353 84.36 ;
     RECT  70.55 4.848 71.365 7.944 ;
     RECT  71.365 4.272 71.381 7.944 ;
     RECT  71.093 28.944 71.381 28.968 ;
     RECT  70.741 86.208 71.413 86.232 ;
     RECT  71.353 48.624 71.417 49.56 ;
     RECT  71.353 79.248 71.701 84.36 ;
     RECT  71.381 6.192 71.737 7.944 ;
     RECT  71.701 79.248 71.797 84.936 ;
     RECT  71.413 86.208 71.797 86.28 ;
     RECT  71.381 4.272 71.845 5.208 ;
     RECT  71.309 36.96 71.845 45.576 ;
     RECT  71.353 46.8 71.845 47.592 ;
     RECT  71.353 77.904 71.881 77.928 ;
     RECT  70.691 1.728 71.996 2.28 ;
     RECT  71.845 3.408 71.996 5.208 ;
     RECT  71.737 6.192 72.181 8.04 ;
     RECT  71.309 34.704 72.229 35.88 ;
     RECT  71.197 13.536 72.313 14.472 ;
     RECT  72.229 33.936 72.313 35.88 ;
     RECT  71.941 0.144 72.341 0.168 ;
     RECT  71.317 15.552 72.349 17.208 ;
     RECT  71.317 18.288 72.349 18.84 ;
     RECT  70.979 20.064 72.349 24.696 ;
     RECT  72.241 29.52 72.349 29.592 ;
     RECT  71.845 30.576 72.349 30.6 ;
     RECT  71.417 48.624 72.373 49.512 ;
     RECT  71.881 77.76 72.373 77.928 ;
     RECT  71.797 79.248 72.373 86.28 ;
     RECT  71.845 36.96 72.38 47.592 ;
     RECT  72.373 48.576 72.38 49.512 ;
     RECT  72.349 29.52 72.421 30.6 ;
     RECT  72.38 36.96 72.421 49.512 ;
     RECT  70.697 50.544 72.421 50.712 ;
     RECT  72.341 0.144 72.425 0.6 ;
     RECT  71.267 75.264 72.457 75.288 ;
     RECT  71.996 1.728 72.469 5.208 ;
     RECT  72.181 6.192 72.469 8.76 ;
     RECT  72.469 1.728 72.54 9.624 ;
     RECT  72.54 1.68 72.608 9.624 ;
     RECT  72.469 10.896 72.608 10.92 ;
     RECT  72.313 13.152 72.608 14.472 ;
     RECT  72.349 15.552 72.608 24.696 ;
     RECT  71.093 25.824 72.608 27.96 ;
     RECT  72.421 28.944 72.608 30.6 ;
     RECT  71.237 32.256 72.608 32.328 ;
     RECT  72.313 33.936 72.608 35.928 ;
     RECT  72.421 36.96 72.608 50.712 ;
     RECT  71.315 51.696 72.608 52.488 ;
     RECT  69.781 58.656 72.608 58.68 ;
     RECT  72.457 75.264 72.608 76.248 ;
     RECT  72.373 77.76 72.608 86.28 ;
     RECT  72.425 0.144 72.898 0.216 ;
     RECT  72.608 1.68 72.904 86.28 ;
     RECT  72.904 31.968 72.965 33.096 ;
     RECT  72.898 0.096 73.009 0.216 ;
     RECT  73.009 0.192 73.043 0.216 ;
     RECT  72.904 13.008 73.043 14.472 ;
     RECT  72.904 15.552 73.073 27.432 ;
     RECT  72.904 34.128 73.073 35.352 ;
     RECT  72.904 77.376 73.073 86.28 ;
     RECT  72.904 3.504 73.091 9.432 ;
     RECT  72.965 31.968 73.253 32.472 ;
     RECT  73.091 3.504 73.361 8.04 ;
     RECT  72.904 36.816 73.379 53.208 ;
     RECT  73.073 15.552 73.397 22.584 ;
     RECT  73.397 15.552 73.433 17.64 ;
     RECT  72.904 29.52 73.469 30.936 ;
     RECT  73.361 3.504 73.477 6.888 ;
     RECT  73.361 8.016 73.477 8.04 ;
     RECT  72.904 1.68 73.501 2.28 ;
     RECT  73.379 36.816 73.505 53.016 ;
     RECT  73.073 77.376 73.505 84.936 ;
     RECT  73.073 86.064 73.513 86.28 ;
     RECT  73.091 9.072 73.541 9.432 ;
     RECT  73.505 39.744 73.549 53.016 ;
     RECT  73.549 50.064 73.577 53.016 ;
     RECT  72.904 75.216 73.577 75.24 ;
     RECT  73.469 29.52 73.649 30.6 ;
     RECT  73.433 17.376 73.757 17.64 ;
     RECT  73.649 29.52 73.757 29.544 ;
     RECT  73.501 1.104 73.763 2.28 ;
     RECT  73.073 34.608 73.829 35.352 ;
     RECT  73.577 51.744 73.865 53.016 ;
     RECT  73.073 23.664 73.897 27.432 ;
     RECT  72.904 28.512 73.897 28.536 ;
     RECT  73.649 30.576 73.901 30.6 ;
     RECT  73.865 51.744 73.901 52.776 ;
     RECT  73.433 15.552 73.933 16.392 ;
     RECT  73.505 79.776 73.973 84.936 ;
     RECT  73.901 51.744 74.045 52.536 ;
     RECT  73.043 13.008 74.099 13.896 ;
     RECT  73.973 82.032 74.101 84.936 ;
     RECT  73.897 23.664 74.113 28.536 ;
     RECT  74.045 52.512 74.261 52.536 ;
     RECT  73.505 77.376 74.261 78.696 ;
     RECT  73.253 32.256 74.329 32.472 ;
     RECT  73.397 18.816 74.369 22.584 ;
     RECT  74.113 0.528 74.435 0.6 ;
     RECT  73.973 79.776 74.435 81.048 ;
     RECT  73.477 4.704 74.473 6.888 ;
     RECT  72.904 10.608 74.473 11.832 ;
     RECT  74.473 4.704 74.485 7.464 ;
     RECT  74.261 78.624 74.485 78.696 ;
     RECT  74.435 79.776 74.485 79.848 ;
     RECT  74.473 10.56 74.513 11.832 ;
     RECT  73.577 50.064 74.545 50.712 ;
     RECT  74.113 23.568 74.549 28.92 ;
     RECT  74.485 4.512 74.557 7.464 ;
     RECT  73.829 35.184 74.581 35.352 ;
     RECT  73.505 36.816 74.581 38.712 ;
     RECT  73.477 3.504 74.617 3.528 ;
     RECT  74.485 78.624 74.627 79.848 ;
     RECT  74.329 32.256 74.653 33.288 ;
     RECT  73.549 39.744 74.653 49.08 ;
     RECT  74.545 50.064 74.653 51.336 ;
     RECT  74.513 10.56 74.689 11.4 ;
     RECT  74.549 23.568 74.693 28.584 ;
     RECT  73.541 9.072 74.725 9.096 ;
     RECT  74.689 10.272 74.725 11.4 ;
     RECT  74.653 76.368 74.725 76.392 ;
     RECT  74.261 77.376 74.725 77.448 ;
     RECT  74.581 35.184 74.765 38.712 ;
     RECT  74.099 13.104 74.78 13.896 ;
     RECT  73.933 14.928 74.78 16.392 ;
     RECT  74.627 78.624 74.845 79.752 ;
     RECT  74.78 13.104 74.867 16.392 ;
     RECT  74.725 76.368 74.867 77.448 ;
     RECT  74.617 3.408 74.869 3.528 ;
     RECT  74.557 4.512 74.869 6.6 ;
     RECT  74.869 3.408 74.909 6.6 ;
     RECT  73.763 1.728 74.941 2.28 ;
     RECT  74.941 1.152 75.025 2.28 ;
     RECT  74.765 35.184 75.121 38.664 ;
     RECT  74.941 75.264 75.121 75.288 ;
     RECT  74.693 23.568 75.125 28.392 ;
     RECT  74.101 82.032 75.125 85.512 ;
     RECT  74.725 9.072 75.157 11.4 ;
     RECT  74.867 15.552 75.157 16.392 ;
     RECT  74.435 81.024 75.157 81.048 ;
     RECT  75.125 82.032 75.157 84.936 ;
     RECT  75.121 74.688 75.193 75.288 ;
     RECT  75.193 74.688 75.205 75.864 ;
     RECT  74.867 76.896 75.233 77.448 ;
     RECT  74.845 78.624 75.233 78.648 ;
     RECT  74.653 39.744 75.269 51.336 ;
     RECT  75.269 51.312 75.301 51.336 ;
     RECT  75.301 51.312 75.341 51.672 ;
     RECT  75.269 39.744 75.349 50.136 ;
     RECT  74.909 3.408 75.395 6.264 ;
     RECT  75.395 3.408 75.404 3.432 ;
     RECT  75.349 50.064 75.413 50.136 ;
     RECT  73.757 17.616 75.445 17.64 ;
     RECT  74.369 19.344 75.445 22.584 ;
     RECT  74.653 31.872 75.449 33.288 ;
     RECT  75.025 1.728 75.473 2.28 ;
     RECT  75.404 3.312 75.473 3.432 ;
     RECT  75.445 17.616 75.521 22.584 ;
     RECT  75.157 81.024 75.541 84.936 ;
     RECT  74.845 79.632 75.589 79.752 ;
     RECT  75.521 20.352 75.629 22.584 ;
     RECT  75.121 34.656 75.629 38.664 ;
     RECT  75.341 51.648 75.637 51.672 ;
     RECT  75.157 15.552 75.673 16.536 ;
     RECT  75.637 51.648 75.683 52.488 ;
     RECT  75.157 7.776 75.685 11.4 ;
     RECT  75.449 31.872 75.733 33.048 ;
     RECT  75.589 79.632 75.733 79.8 ;
     RECT  75.541 80.928 75.737 84.936 ;
     RECT  75.629 20.352 75.779 22.536 ;
     RECT  75.737 80.928 75.779 83.928 ;
     RECT  74.867 13.104 75.805 13.896 ;
     RECT  75.683 51.888 75.805 52.488 ;
     RECT  75.349 39.744 75.916 48.888 ;
     RECT  75.685 7.632 75.917 11.4 ;
     RECT  75.521 17.616 75.917 19.368 ;
     RECT  75.805 12.48 75.98 13.896 ;
     RECT  75.205 73.968 75.985 75.864 ;
     RECT  75.233 76.896 75.985 76.92 ;
     RECT  75.733 79.632 75.989 79.848 ;
     RECT  75.917 17.616 76.021 19.272 ;
     RECT  75.629 38.16 76.057 38.664 ;
     RECT  75.916 39.744 76.057 47.88 ;
     RECT  75.98 12.48 76.067 14.328 ;
     RECT  75.125 25.824 76.093 28.392 ;
     RECT  75.229 30.24 76.093 30.264 ;
     RECT  75.629 34.656 76.133 37.128 ;
     RECT  75.673 15.552 76.169 15.576 ;
     RECT  75.913 54.672 76.205 54.696 ;
     RECT  75.125 23.568 76.237 24.696 ;
     RECT  76.093 25.824 76.237 30.264 ;
     RECT  75.779 80.928 76.241 83.832 ;
     RECT  75.805 51.888 76.273 52.968 ;
     RECT  76.057 38.16 76.277 47.88 ;
     RECT  75.395 4.896 76.309 6.264 ;
     RECT  76.277 38.16 76.313 44.184 ;
     RECT  75.473 1.728 76.345 3.432 ;
     RECT  75.916 48.864 76.357 48.888 ;
     RECT  76.357 48.864 76.403 48.984 ;
     RECT  76.345 1.152 76.417 3.432 ;
     RECT  76.309 4.896 76.417 6.312 ;
     RECT  75.779 20.928 76.444 22.536 ;
     RECT  76.417 1.152 76.451 6.312 ;
     RECT  76.021 17.088 76.457 19.272 ;
     RECT  76.277 45.84 76.457 47.88 ;
     RECT  76.067 12.912 76.461 13.848 ;
     RECT  76.241 80.928 76.493 81.672 ;
     RECT  76.461 12.96 76.529 13.848 ;
     RECT  76.457 45.984 76.529 47.88 ;
     RECT  76.529 12.96 76.547 13.512 ;
     RECT  76.241 82.656 76.547 83.832 ;
     RECT  76.547 13.056 76.565 13.512 ;
     RECT  75.985 73.968 76.565 76.92 ;
     RECT  75.737 84.912 76.597 84.936 ;
     RECT  76.547 82.752 76.643 83.832 ;
     RECT  76.451 1.728 76.741 6.312 ;
     RECT  75.733 31.344 76.741 33.048 ;
     RECT  76.643 83.04 76.741 83.832 ;
     RECT  76.313 38.16 76.745 43.944 ;
     RECT  76.741 83.04 76.769 83.88 ;
     RECT  76.597 84.912 76.769 84.984 ;
     RECT  76.741 31.344 76.787 33.672 ;
     RECT  76.444 20.928 76.813 22.056 ;
     RECT  76.457 17.088 76.817 18.744 ;
     RECT  76.237 23.568 76.817 30.264 ;
     RECT  76.273 51.888 76.817 53.064 ;
     RECT  75.989 79.824 76.837 79.848 ;
     RECT  76.493 80.928 76.837 81.624 ;
     RECT  76.813 20.88 76.849 22.056 ;
     RECT  76.745 38.16 76.889 38.76 ;
     RECT  76.565 73.968 76.957 75.816 ;
     RECT  76.849 20.544 76.981 22.056 ;
     RECT  75.413 50.064 76.988 50.088 ;
     RECT  76.403 48.96 77.029 48.984 ;
     RECT  76.988 50.064 77.029 50.52 ;
     RECT  77.029 48.96 77.065 50.52 ;
     RECT  76.117 78.048 77.077 78.072 ;
     RECT  76.787 32.4 77.173 33.672 ;
     RECT  76.133 34.656 77.173 37.032 ;
     RECT  76.741 1.728 77.209 6.84 ;
     RECT  75.917 7.968 77.209 10.632 ;
     RECT  77.077 78.048 77.389 78.168 ;
     RECT  77.077 17.04 77.413 17.064 ;
     RECT  77.389 78.048 77.413 78.264 ;
     RECT  76.837 79.824 77.413 81.624 ;
     RECT  76.745 39.744 77.425 43.944 ;
     RECT  76.981 20.16 77.461 22.056 ;
     RECT  76.769 83.04 77.465 84.984 ;
     RECT  77.077 85.968 77.557 85.992 ;
     RECT  76.565 13.104 77.569 13.512 ;
     RECT  76.817 18.72 77.569 18.744 ;
     RECT  76.529 45.984 77.569 47.688 ;
     RECT  77.569 45.552 77.677 47.688 ;
     RECT  77.317 15.936 77.701 15.96 ;
     RECT  77.425 39.744 77.701 44.376 ;
     RECT  77.465 83.04 77.749 84.408 ;
     RECT  77.677 45.552 77.777 47.784 ;
     RECT  76.787 31.344 77.785 31.368 ;
     RECT  77.173 32.4 77.785 37.032 ;
     RECT  77.413 16.992 77.804 17.064 ;
     RECT  77.413 78.048 77.821 81.624 ;
     RECT  77.749 82.608 77.821 84.408 ;
     RECT  77.557 85.968 77.821 86.28 ;
     RECT  77.569 13.104 77.857 13.656 ;
     RECT  77.701 15.888 77.929 15.96 ;
     RECT  77.461 20.16 78.001 22.248 ;
     RECT  76.817 23.568 78.001 24.696 ;
     RECT  77.209 1.728 78.008 10.632 ;
     RECT  77.857 12.48 78.008 13.656 ;
     RECT  77.929 15.456 78.008 15.96 ;
     RECT  77.804 16.944 78.008 17.064 ;
     RECT  77.569 18.72 78.008 19.032 ;
     RECT  78.001 20.16 78.008 24.696 ;
     RECT  76.817 25.824 78.008 30.264 ;
     RECT  77.785 31.344 78.008 37.032 ;
     RECT  76.889 38.496 78.008 38.76 ;
     RECT  77.701 39.744 78.008 44.568 ;
     RECT  77.777 45.552 78.008 47.928 ;
     RECT  77.065 48.96 78.008 50.904 ;
     RECT  76.817 51.936 78.008 53.064 ;
     RECT  72.904 58.656 78.008 58.68 ;
     RECT  76.957 73.776 78.008 75.816 ;
     RECT  76.565 76.896 78.008 76.92 ;
     RECT  77.821 77.904 78.008 84.408 ;
     RECT  78.008 1.728 78.304 84.408 ;
     RECT  78.304 18.72 78.365 28.44 ;
     RECT  78.304 29.856 78.365 40.584 ;
     RECT  77.821 85.488 78.365 86.28 ;
     RECT  78.133 0.144 78.419 0.168 ;
     RECT  78.304 10.08 78.437 10.632 ;
     RECT  78.365 19.584 78.445 28.44 ;
     RECT  78.365 85.488 78.467 86.184 ;
     RECT  78.365 30.768 78.509 40.584 ;
     RECT  78.445 19.584 78.515 24.696 ;
     RECT  78.304 1.728 78.517 8.76 ;
     RECT  78.515 20.16 78.545 24.696 ;
     RECT  78.437 10.128 78.617 10.632 ;
     RECT  78.304 51.792 78.659 53.544 ;
     RECT  78.304 41.616 78.689 49.56 ;
     RECT  78.617 10.176 78.725 10.632 ;
     RECT  78.304 76.944 78.755 84.408 ;
     RECT  78.509 30.768 78.869 39.192 ;
     RECT  78.755 80.4 78.901 84.408 ;
     RECT  78.467 85.488 78.901 85.512 ;
     RECT  78.545 23.424 78.941 24.696 ;
     RECT  78.445 25.824 78.941 28.44 ;
     RECT  78.304 50.736 78.977 50.76 ;
     RECT  78.941 25.824 79.013 26.904 ;
     RECT  78.901 80.4 79.043 85.512 ;
     RECT  78.304 13.104 79.049 14.28 ;
     RECT  78.869 31.776 79.085 39.192 ;
     RECT  79.043 80.4 79.193 82.776 ;
     RECT  79.085 31.968 79.229 39.192 ;
     RECT  78.517 7.392 79.265 8.76 ;
     RECT  79.261 0.576 79.345 0.6 ;
     RECT  78.517 1.728 79.373 6.312 ;
     RECT  79.049 13.104 79.381 13.224 ;
     RECT  78.304 73.776 79.436 73.8 ;
     RECT  78.509 40.176 79.441 40.584 ;
     RECT  78.689 41.616 79.441 49.416 ;
     RECT  78.659 52.176 79.445 53.544 ;
     RECT  79.381 12.528 79.468 13.224 ;
     RECT  79.265 7.968 79.477 8.76 ;
     RECT  78.545 20.16 79.477 22.248 ;
     RECT  79.043 83.76 79.477 85.512 ;
     RECT  79.441 40.176 79.481 49.416 ;
     RECT  78.304 15.36 79.484 15.48 ;
     RECT  78.304 16.464 79.484 16.488 ;
     RECT  79.373 6.24 79.513 6.312 ;
     RECT  79.229 31.968 79.517 38.76 ;
     RECT  79.049 14.256 79.523 14.28 ;
     RECT  79.436 73.776 79.523 74.664 ;
     RECT  79.193 80.928 79.523 82.776 ;
     RECT  79.477 7.968 79.553 8.904 ;
     RECT  79.481 46.176 79.553 49.416 ;
     RECT  79.477 83.76 79.553 86.232 ;
     RECT  79.484 15.36 79.571 16.488 ;
     RECT  79.517 32.448 79.571 38.76 ;
     RECT  78.941 28.128 79.585 28.44 ;
     RECT  79.477 19.968 79.621 22.248 ;
     RECT  78.941 23.424 79.621 23.976 ;
     RECT  79.445 52.176 79.621 52.536 ;
     RECT  78.755 76.944 79.66 79.272 ;
     RECT  79.549 18.624 79.669 18.648 ;
     RECT  79.621 19.968 79.669 23.976 ;
     RECT  79.585 28.128 79.669 29.112 ;
     RECT  79.553 8.352 79.697 8.904 ;
     RECT  79.523 81.456 79.733 82.776 ;
     RECT  79.657 75.84 79.741 75.864 ;
     RECT  79.571 16.464 79.801 16.488 ;
     RECT  79.571 32.448 79.805 37.464 ;
     RECT  79.513 6.24 79.811 6.888 ;
     RECT  78.869 30.768 79.841 30.792 ;
     RECT  79.523 73.776 79.861 73.8 ;
     RECT  79.801 75.216 79.885 75.576 ;
     RECT  79.861 72.912 79.907 73.8 ;
     RECT  79.801 16.464 79.913 17.448 ;
     RECT  79.553 46.176 79.913 48.648 ;
     RECT  79.913 16.56 79.916 17.448 ;
     RECT  79.885 75.408 79.948 75.576 ;
     RECT  79.669 18.624 79.955 23.976 ;
     RECT  79.916 16.56 79.985 17.64 ;
     RECT  79.913 48.624 79.985 48.648 ;
     RECT  79.373 1.728 80.003 3.432 ;
     RECT  79.985 17.616 80.003 17.64 ;
     RECT  79.66 76.944 80.003 79.224 ;
     RECT  80.003 3.408 80.021 3.432 ;
     RECT  79.955 18.624 80.021 19.032 ;
     RECT  79.553 86.208 80.045 86.232 ;
     RECT  79.955 20.832 80.053 23.976 ;
     RECT  80.053 20.832 80.089 24.024 ;
     RECT  79.468 13.104 80.093 13.224 ;
     RECT  80.089 20.832 80.125 24.12 ;
     RECT  80.045 86.208 80.129 86.28 ;
     RECT  79.733 82.176 80.149 82.776 ;
     RECT  79.553 83.76 80.149 84.936 ;
     RECT  79.481 40.176 80.161 45.048 ;
     RECT  80.125 20.832 80.173 24.312 ;
     RECT  80.173 23.376 80.237 24.312 ;
     RECT  79.909 50.256 80.269 50.28 ;
     RECT  79.621 51.696 80.269 52.536 ;
     RECT  79.805 32.448 80.309 34.2 ;
     RECT  79.811 6.816 80.341 6.888 ;
     RECT  79.697 8.352 80.345 8.376 ;
     RECT  80.237 23.376 80.381 24.12 ;
     RECT  80.269 50.256 80.381 52.536 ;
     RECT  80.021 18.624 80.387 18.84 ;
     RECT  80.3 80.4 80.387 80.424 ;
     RECT  79.373 4.512 80.417 5.112 ;
     RECT  80.381 51.312 80.417 52.536 ;
     RECT  79.013 25.824 80.444 26.616 ;
     RECT  80.093 13.2 80.453 13.224 ;
     RECT  80.173 20.832 80.453 22.056 ;
     RECT  80.417 5.04 80.485 5.112 ;
     RECT  80.444 25.824 80.485 26.808 ;
     RECT  79.669 28.128 80.485 28.44 ;
     RECT  80.341 6.816 80.525 6.936 ;
     RECT  80.381 23.376 80.553 24.024 ;
     RECT  79.805 35.52 80.557 37.464 ;
     RECT  79.571 38.496 80.557 38.76 ;
     RECT  80.161 39.888 80.593 45.048 ;
     RECT  79.913 46.176 80.593 47.592 ;
     RECT  80.149 82.176 80.593 84.936 ;
     RECT  80.521 80.928 80.627 80.952 ;
     RECT  80.453 20.832 80.633 21.672 ;
     RECT  80.485 25.824 80.665 28.44 ;
     RECT  80.305 30 80.665 30.36 ;
     RECT  80.525 6.816 80.705 6.888 ;
     RECT  80.309 34.128 80.741 34.2 ;
     RECT  80.557 35.52 80.777 38.76 ;
     RECT  80.417 51.312 80.777 51.816 ;
     RECT  78.725 10.56 80.78 10.632 ;
     RECT  80.593 82.176 80.812 85.512 ;
     RECT  79.571 15.36 80.813 15.384 ;
     RECT  79.985 16.56 80.813 16.584 ;
     RECT  80.665 25.824 80.845 30.36 ;
     RECT  80.485 5.04 80.849 5.736 ;
     RECT  80.777 35.52 80.849 37.368 ;
     RECT  80.003 1.728 80.867 2.28 ;
     RECT  80.78 10.56 80.867 11.448 ;
     RECT  80.777 38.688 80.869 38.76 ;
     RECT  80.593 39.888 80.869 47.592 ;
     RECT  80.633 20.832 80.885 21.192 ;
     RECT  80.867 1.728 80.917 1.896 ;
     RECT  80.845 25.824 80.953 31.128 ;
     RECT  80.705 6.816 80.957 6.84 ;
     RECT  80.003 78.24 80.965 79.224 ;
     RECT  80.917 1.152 80.989 1.896 ;
     RECT  80.885 20.832 81.029 20.952 ;
     RECT  80.812 82.176 81.029 84.984 ;
     RECT  80.773 14.304 81.061 14.328 ;
     RECT  81.029 20.832 81.061 20.856 ;
     RECT  80.849 5.04 81.065 5.688 ;
     RECT  81.061 14.208 81.101 14.328 ;
     RECT  80.869 38.688 81.107 47.592 ;
     RECT  80.003 76.944 81.133 76.968 ;
     RECT  81.107 45.024 81.137 47.592 ;
     RECT  81.137 45.84 81.169 47.592 ;
     RECT  80.553 23.664 81.173 24.024 ;
     RECT  81.107 38.688 81.173 43.896 ;
     RECT  80.845 34.224 81.281 34.248 ;
     RECT  81.173 38.688 81.317 39.576 ;
     RECT  80.387 18.816 81.349 18.84 ;
     RECT  80.849 35.52 81.349 35.784 ;
     RECT  80.965 78.24 81.385 79.272 ;
     RECT  80.989 0.576 81.389 1.896 ;
     RECT  81.169 45.84 81.389 48.216 ;
     RECT  80.381 50.256 81.389 50.28 ;
     RECT  81.101 14.208 81.395 14.232 ;
     RECT  81.313 15.984 81.397 16.008 ;
     RECT  80.953 25.776 81.421 31.128 ;
     RECT  81.349 35.04 81.425 35.784 ;
     RECT  81.349 18.816 81.443 19.656 ;
     RECT  81.029 82.752 81.443 84.984 ;
     RECT  81.065 5.568 81.461 5.688 ;
     RECT  81.425 35.04 81.461 35.592 ;
     RECT  79.445 53.52 81.461 53.544 ;
     RECT  81.385 78.24 81.469 79.848 ;
     RECT  81.389 0.576 81.541 1.848 ;
     RECT  81.133 76.944 81.541 77.208 ;
     RECT  81.469 78.24 81.541 79.8 ;
     RECT  79.907 72.912 81.565 72.936 ;
     RECT  80.309 32.448 81.605 33.048 ;
     RECT  81.565 72.144 81.605 72.936 ;
     RECT  81.385 3.984 81.635 4.008 ;
     RECT  81.557 86.256 81.641 86.28 ;
     RECT  81.541 76.944 81.683 79.8 ;
     RECT  81.389 45.84 81.821 47.592 ;
     RECT  81.637 49.056 81.893 49.08 ;
     RECT  80.849 36.912 81.925 37.368 ;
     RECT  81.317 38.688 81.925 38.952 ;
     RECT  81.173 40.848 81.929 43.896 ;
     RECT  80.867 10.56 82.073 10.632 ;
     RECT  81.683 78 82.073 79.8 ;
     RECT  81.061 20.64 82.141 20.856 ;
     RECT  81.443 82.752 82.141 84.936 ;
     RECT  81.683 76.944 82.145 76.968 ;
     RECT  81.443 18.816 82.217 18.84 ;
     RECT  82.141 20.112 82.253 20.856 ;
     RECT  81.929 40.944 82.357 43.896 ;
     RECT  82.285 33.072 82.397 33.096 ;
     RECT  82.357 40.944 82.397 43.944 ;
     RECT  80.777 51.696 82.429 51.816 ;
     RECT  81.877 81.456 82.453 81.48 ;
     RECT  82.141 82.56 82.453 84.936 ;
     RECT  82.397 43.536 82.501 43.944 ;
     RECT  82.429 51.408 82.501 51.816 ;
     RECT  79.948 75.408 82.501 75.432 ;
     RECT  81.461 5.568 82.537 5.592 ;
     RECT  82.501 75.216 82.537 75.432 ;
     RECT  81.821 46.704 82.604 47.592 ;
     RECT  82.501 51.408 82.609 51.96 ;
     RECT  82.073 78.048 82.637 79.8 ;
     RECT  82.453 80.928 82.637 84.936 ;
     RECT  81.173 23.664 82.645 23.976 ;
     RECT  82.537 5.568 82.681 6.264 ;
     RECT  81.461 35.568 82.681 35.592 ;
     RECT  81.541 1.728 82.7 1.848 ;
     RECT  82.501 43.536 82.7 44.376 ;
     RECT  82.465 34.176 82.717 34.2 ;
     RECT  82.681 35.424 82.717 35.592 ;
     RECT  82.213 52.944 82.717 52.968 ;
     RECT  81.541 0.576 82.729 0.6 ;
     RECT  81.421 25.776 82.753 31.368 ;
     RECT  82.741 3.984 82.789 4.008 ;
     RECT  82.753 25.104 82.789 31.368 ;
     RECT  82.645 49.296 82.789 49.32 ;
     RECT  82.717 34.176 82.844 35.592 ;
     RECT  82.844 33.552 82.885 35.592 ;
     RECT  81.925 36.912 82.885 38.952 ;
     RECT  82.645 23.568 82.897 23.976 ;
     RECT  82.789 49.296 82.897 49.656 ;
     RECT  82.253 20.64 82.969 20.856 ;
     RECT  82.604 46.704 82.997 48.264 ;
     RECT  82.897 49.296 82.997 49.848 ;
     RECT  82.717 52.944 83.005 53.16 ;
     RECT  82.933 56.976 83.005 57 ;
     RECT  82.681 5.568 83.029 6.312 ;
     RECT  82.609 51.216 83.036 51.96 ;
     RECT  83.005 52.944 83.036 53.256 ;
     RECT  83.029 5.568 83.041 6.36 ;
     RECT  82.681 17.088 83.041 17.112 ;
     RECT  83.041 5.568 83.077 7.032 ;
     RECT  82.969 20.64 83.077 21 ;
     RECT  83.036 51.216 83.077 53.688 ;
     RECT  82.397 40.944 83.113 42.264 ;
     RECT  83.029 86.064 83.113 86.184 ;
     RECT  82.789 3.648 83.125 4.008 ;
     RECT  83.077 4.992 83.125 7.368 ;
     RECT  82.789 25.104 83.125 31.848 ;
     RECT  83.113 40.704 83.125 42.264 ;
     RECT  82.7 1.728 83.149 2.232 ;
     RECT  83.149 1.728 83.173 2.616 ;
     RECT  83.125 3.648 83.173 7.368 ;
     RECT  82.997 46.704 83.173 49.848 ;
     RECT  83.077 51.072 83.173 53.688 ;
     RECT  82.637 78.048 83.173 84.936 ;
     RECT  82.897 23.136 83.185 23.976 ;
     RECT  83.113 86.064 83.197 86.28 ;
     RECT  83.173 77.616 83.213 84.936 ;
     RECT  83.197 86.064 83.213 86.232 ;
     RECT  83.173 1.728 83.221 7.368 ;
     RECT  83.041 17.088 83.221 17.928 ;
     RECT  82.885 33.552 83.221 38.952 ;
     RECT  83.125 40.608 83.221 42.264 ;
     RECT  83.173 46.704 83.221 53.688 ;
     RECT  82.537 75.216 83.221 76.392 ;
     RECT  82.073 10.56 83.269 10.584 ;
     RECT  82.285 14.256 83.269 14.28 ;
     RECT  83.185 23.136 83.269 24.12 ;
     RECT  83.125 25.104 83.269 32.04 ;
     RECT  83.221 1.728 83.329 7.464 ;
     RECT  83.173 8.544 83.329 8.568 ;
     RECT  82.7 43.536 83.329 45.528 ;
     RECT  83.221 46.608 83.329 53.688 ;
     RECT  83.125 74.064 83.365 74.088 ;
     RECT  83.221 75.216 83.365 76.584 ;
     RECT  83.329 1.728 83.408 8.568 ;
     RECT  83.269 10.56 83.408 10.728 ;
     RECT  83.269 12.528 83.408 12.552 ;
     RECT  83.269 13.872 83.408 14.28 ;
     RECT  82.285 15.84 83.408 15.864 ;
     RECT  83.221 17.088 83.408 17.976 ;
     RECT  83.077 20.64 83.408 21.72 ;
     RECT  83.269 23.136 83.408 32.04 ;
     RECT  83.221 33.552 83.408 42.264 ;
     RECT  83.329 43.536 83.408 53.688 ;
     RECT  83.005 56.928 83.408 57 ;
     RECT  78.304 58.656 83.408 58.68 ;
     RECT  81.605 72.144 83.408 72.168 ;
     RECT  83.365 74.064 83.408 76.584 ;
     RECT  83.213 77.616 83.408 86.232 ;
     RECT  83.408 1.728 83.459 86.232 ;
     RECT  83.459 1.728 83.704 85.512 ;
     RECT  83.704 16.56 83.729 20.328 ;
     RECT  83.704 25.488 83.729 32.04 ;
     RECT  83.704 1.728 83.765 9.096 ;
     RECT  83.704 74.4 83.765 75.432 ;
     RECT  83.729 25.488 83.843 31.896 ;
     RECT  83.765 74.592 83.843 75.432 ;
     RECT  83.704 34.608 83.891 47.592 ;
     RECT  83.891 34.608 83.909 43.896 ;
     RECT  83.704 21.504 83.945 21.72 ;
     RECT  83.843 74.976 83.981 75.432 ;
     RECT  83.704 58.656 84.053 58.68 ;
     RECT  83.729 18.192 84.083 20.328 ;
     RECT  83.704 79.152 84.083 79.272 ;
     RECT  84.083 18.192 84.124 19.368 ;
     RECT  83.765 6.816 84.125 9.096 ;
     RECT  83.909 37.248 84.131 43.896 ;
     RECT  84.124 18.192 84.133 18.84 ;
     RECT  84.083 79.2 84.179 79.272 ;
     RECT  83.704 48.816 84.197 49.32 ;
     RECT  84.197 48.912 84.233 49.32 ;
     RECT  83.843 25.632 84.269 31.896 ;
     RECT  83.704 50.832 84.269 53.592 ;
     RECT  83.704 83.76 84.269 85.512 ;
     RECT  83.765 1.728 84.305 5.784 ;
     RECT  84.269 31.248 84.305 31.896 ;
     RECT  84.131 37.44 84.305 43.896 ;
     RECT  84.269 50.832 84.305 52.92 ;
     RECT  84.125 6.864 84.341 9.096 ;
     RECT  83.704 12.432 84.371 14.232 ;
     RECT  84.341 7.248 84.377 9.096 ;
     RECT  84.365 0.576 84.445 0.6 ;
     RECT  84.445 0.576 84.449 0.696 ;
     RECT  84.269 25.632 84.449 30.024 ;
     RECT  83.891 44.976 84.485 47.592 ;
     RECT  83.704 80.928 84.485 82.728 ;
     RECT  84.449 0.672 84.529 0.696 ;
     RECT  83.704 23.568 84.593 24.12 ;
     RECT  83.729 16.56 84.629 17.112 ;
     RECT  84.629 16.56 84.659 16.584 ;
     RECT  84.233 48.912 84.659 49.08 ;
     RECT  84.305 37.536 84.665 43.896 ;
     RECT  84.485 45.696 84.701 47.592 ;
     RECT  84.665 38.832 84.737 43.896 ;
     RECT  83.704 76.944 84.805 78.12 ;
     RECT  84.701 45.936 84.809 47.592 ;
     RECT  84.485 81.984 84.844 82.728 ;
     RECT  84.844 82.08 84.899 82.728 ;
     RECT  84.593 23.664 84.913 24.12 ;
     RECT  84.805 76.368 84.917 78.12 ;
     RECT  84.485 80.928 84.917 80.952 ;
     RECT  84.371 13.872 84.947 14.232 ;
     RECT  83.704 10.704 84.949 10.728 ;
     RECT  84.899 82.656 84.949 82.728 ;
     RECT  84.269 83.76 84.949 85.032 ;
     RECT  84.305 1.728 84.985 1.8 ;
     RECT  84.947 13.872 84.989 13.896 ;
     RECT  84.949 10.704 84.995 11.304 ;
     RECT  84.901 15.84 84.997 16.008 ;
     RECT  84.305 50.832 85.021 52.872 ;
     RECT  84.449 26.256 85.061 30.024 ;
     RECT  84.985 1.68 85.091 1.8 ;
     RECT  84.913 23.664 85.093 24.504 ;
     RECT  84.665 37.536 85.097 37.752 ;
     RECT  84.737 39.792 85.097 43.896 ;
     RECT  85.061 26.256 85.133 28.056 ;
     RECT  84.917 76.944 85.133 78.12 ;
     RECT  83.981 74.976 85.169 75 ;
     RECT  84.305 31.872 85.201 31.896 ;
     RECT  84.305 2.832 85.237 5.784 ;
     RECT  85.091 1.728 85.273 1.8 ;
     RECT  84.997 15.84 85.277 15.864 ;
     RECT  85.061 29.04 85.277 30.024 ;
     RECT  84.949 82.656 85.277 85.032 ;
     RECT  85.237 2.832 85.309 5.928 ;
     RECT  84.377 7.248 85.309 8.904 ;
     RECT  84.133 18.192 85.309 18.216 ;
     RECT  85.097 41.616 85.313 43.896 ;
     RECT  85.309 2.832 85.324 8.904 ;
     RECT  84.179 79.248 85.331 79.272 ;
     RECT  85.021 50.064 85.345 52.872 ;
     RECT  85.277 82.656 85.357 82.68 ;
     RECT  85.201 31.872 85.381 32.088 ;
     RECT  83.909 34.608 85.381 35.88 ;
     RECT  85.093 23.664 85.417 25.08 ;
     RECT  85.133 26.256 85.417 27.912 ;
     RECT  85.381 31.872 85.421 32.232 ;
     RECT  85.381 33.936 85.525 35.88 ;
     RECT  85.313 42.768 85.525 43.896 ;
     RECT  85.421 32.064 85.529 32.232 ;
     RECT  84.809 46.272 85.561 47.592 ;
     RECT  85.345 50.064 85.601 53.784 ;
     RECT  85.097 37.536 85.629 37.56 ;
     RECT  85.324 6.864 85.637 8.904 ;
     RECT  85.273 1.728 85.669 1.848 ;
     RECT  85.324 2.832 85.669 5.736 ;
     RECT  83.945 21.504 85.669 21.528 ;
     RECT  85.417 23.664 85.669 27.912 ;
     RECT  84.995 11.28 85.709 11.304 ;
     RECT  85.525 33.936 85.745 36.456 ;
     RECT  85.561 46.272 85.777 48.36 ;
     RECT  85.529 32.208 85.781 32.232 ;
     RECT  85.669 21.504 85.813 27.912 ;
     RECT  85.277 83.76 85.813 85.032 ;
     RECT  85.045 86.256 85.813 86.28 ;
     RECT  85.525 42.768 85.849 44.328 ;
     RECT  85.601 50.736 85.853 53.784 ;
     RECT  85.813 83.76 85.853 86.28 ;
     RECT  85.309 18.192 85.885 19.176 ;
     RECT  85.813 20.832 85.885 27.912 ;
     RECT  85.133 76.944 85.993 77.64 ;
     RECT  85.669 1.728 85.997 5.736 ;
     RECT  85.885 18.192 85.997 27.912 ;
     RECT  85.993 76.368 86.033 77.64 ;
     RECT  85.909 81.6 86.033 81.624 ;
     RECT  85.853 83.76 86.033 85.512 ;
     RECT  85.097 39.792 86.06 40.44 ;
     RECT  86.06 39.744 86.065 40.44 ;
     RECT  85.313 41.616 86.065 41.688 ;
     RECT  86.033 76.368 86.065 76.392 ;
     RECT  85.997 18.192 86.069 20.568 ;
     RECT  86.033 83.76 86.069 85.416 ;
     RECT  86.065 39.744 86.101 41.688 ;
     RECT  85.777 46.272 86.105 49.032 ;
     RECT  86.105 46.272 86.141 47.592 ;
     RECT  86.101 39.36 86.147 41.688 ;
     RECT  86.101 38.16 86.209 38.184 ;
     RECT  86.147 39.36 86.209 39.384 ;
     RECT  85.849 42.768 86.213 45.288 ;
     RECT  86.173 0.576 86.245 0.6 ;
     RECT  86.069 83.76 86.245 84.984 ;
     RECT  86.209 38.16 86.249 39.384 ;
     RECT  86.245 0.576 86.257 0.648 ;
     RECT  85.277 29.04 86.281 29.88 ;
     RECT  85.997 21.648 86.293 27.912 ;
     RECT  86.281 29.04 86.293 30.792 ;
     RECT  86.273 14.832 86.317 14.856 ;
     RECT  86.245 83.232 86.329 84.984 ;
     RECT  86.257 0.624 86.339 0.648 ;
     RECT  84.371 12.432 86.339 12.456 ;
     RECT  86.317 14.832 86.357 15.432 ;
     RECT  86.293 25.728 86.389 27.912 ;
     RECT  86.293 28.992 86.389 30.792 ;
     RECT  86.389 25.728 86.425 30.792 ;
     RECT  85.997 1.776 86.429 5.736 ;
     RECT  86.147 40.656 86.429 41.688 ;
     RECT  86.429 40.656 86.465 40.776 ;
     RECT  86.213 42.768 86.465 44.856 ;
     RECT  86.249 38.4 86.537 39.384 ;
     RECT  86.465 40.752 86.537 40.776 ;
     RECT  86.141 46.512 86.537 47.592 ;
     RECT  86.429 4.512 86.54 5.736 ;
     RECT  85.637 6.864 86.54 8.424 ;
     RECT  85.745 33.936 86.573 34.44 ;
     RECT  86.101 80.88 86.573 80.904 ;
     RECT  86.069 19.152 86.675 20.568 ;
     RECT  85.745 35.424 86.677 36.456 ;
     RECT  86.065 75.936 86.677 76.392 ;
     RECT  86.677 35.424 86.732 37.128 ;
     RECT  86.54 4.512 86.753 8.424 ;
     RECT  86.425 25.728 86.753 30.84 ;
     RECT  86.465 42.768 86.753 43.896 ;
     RECT  86.753 4.56 86.819 8.424 ;
     RECT  86.732 35.424 86.819 37.32 ;
     RECT  86.819 5.088 86.833 8.424 ;
     RECT  86.753 27.312 86.86 30.84 ;
     RECT  86.833 5.088 86.897 6.888 ;
     RECT  85.741 78.672 86.933 78.744 ;
     RECT  86.357 15.408 86.965 15.432 ;
     RECT  86.293 21.648 86.969 24.504 ;
     RECT  85.853 50.832 86.969 53.784 ;
     RECT  86.677 82.08 86.977 82.104 ;
     RECT  86.033 77.616 87.001 77.64 ;
     RECT  86.933 78.672 87.001 78.696 ;
     RECT  86.965 15.408 87.005 15.72 ;
     RECT  86.969 50.832 87.037 51.144 ;
     RECT  86.677 75.792 87.037 76.392 ;
     RECT  87.001 77.616 87.037 78.696 ;
     RECT  87.037 75.792 87.041 78.696 ;
     RECT  86.897 5.136 87.049 6.888 ;
     RECT  86.429 1.776 87.061 3.432 ;
     RECT  86.86 29.28 87.068 30.84 ;
     RECT  86.819 35.424 87.077 37.224 ;
     RECT  87.037 50.352 87.109 51.144 ;
     RECT  86.969 22.176 87.113 24.504 ;
     RECT  87.049 5.136 87.149 6.84 ;
     RECT  86.675 19.152 87.155 19.944 ;
     RECT  86.537 46.704 87.181 47.592 ;
     RECT  86.105 48.768 87.181 49.032 ;
     RECT  86.293 11.376 87.212 11.4 ;
     RECT  87.068 29.28 87.212 31.32 ;
     RECT  86.929 33.072 87.212 33.096 ;
     RECT  86.353 17.616 87.221 17.64 ;
     RECT  87.077 35.76 87.221 37.224 ;
     RECT  86.833 7.92 87.253 8.424 ;
     RECT  87.212 11.088 87.257 11.4 ;
     RECT  86.969 52.464 87.257 53.784 ;
     RECT  87.257 11.088 87.299 11.112 ;
     RECT  87.212 29.28 87.299 33.096 ;
     RECT  87.061 1.728 87.308 3.432 ;
     RECT  83.704 72.144 87.308 72.168 ;
     RECT  86.329 83.76 87.308 84.984 ;
     RECT  87.113 22.176 87.329 24.12 ;
     RECT  85.597 58.656 87.349 58.68 ;
     RECT  87.212 82.464 87.365 82.584 ;
     RECT  87.308 1.104 87.395 3.432 ;
     RECT  87.349 58.128 87.395 58.68 ;
     RECT  87.308 71.568 87.395 72.168 ;
     RECT  87.308 83.76 87.395 85.512 ;
     RECT  87.181 46.704 87.404 49.032 ;
     RECT  87.109 50.016 87.404 51.144 ;
     RECT  87.253 7.92 87.437 8.472 ;
     RECT  87.221 35.76 87.473 37.032 ;
     RECT  87.361 79.824 87.505 79.848 ;
     RECT  87.404 46.704 87.509 51.144 ;
     RECT  87.509 46.704 87.541 49.56 ;
     RECT  87.257 52.464 87.581 53.64 ;
     RECT  87.395 83.76 87.677 84.936 ;
     RECT  87.041 75.792 87.725 78.216 ;
     RECT  87.685 74.64 87.733 74.664 ;
     RECT  87.473 36.096 87.761 37.032 ;
     RECT  87.395 58.128 87.779 58.152 ;
     RECT  86.537 39.36 87.781 39.384 ;
     RECT  87.677 83.232 87.805 84.936 ;
     RECT  87.733 74.592 87.829 74.664 ;
     RECT  87.541 46.32 87.865 49.56 ;
     RECT  87.781 39.264 87.893 39.384 ;
     RECT  87.299 29.28 87.901 31.8 ;
     RECT  86.753 43.008 87.937 43.896 ;
     RECT  87.505 45.264 87.937 45.288 ;
     RECT  87.613 80.88 88.021 80.904 ;
     RECT  87.829 86.208 88.049 86.28 ;
     RECT  87.725 76.32 88.069 78.216 ;
     RECT  87.505 79.824 88.069 79.896 ;
     RECT  88.045 4.56 88.189 4.584 ;
     RECT  87.893 39.264 88.189 39.96 ;
     RECT  88.021 80.88 88.189 81.48 ;
     RECT  88.189 4.512 88.22 4.584 ;
     RECT  87.149 5.712 88.22 6.84 ;
     RECT  88.22 4.512 88.309 6.84 ;
     RECT  87.437 7.92 88.309 7.992 ;
     RECT  86.573 34.08 88.316 34.44 ;
     RECT  88.316 34.08 88.357 34.536 ;
     RECT  88.069 79.68 88.357 79.896 ;
     RECT  88.189 80.88 88.357 82.104 ;
     RECT  87.973 38.16 88.369 38.184 ;
     RECT  88.189 39.264 88.369 40.296 ;
     RECT  88.049 86.208 88.501 86.232 ;
     RECT  87.299 33.072 88.549 33.096 ;
     RECT  88.153 41.76 88.549 41.784 ;
     RECT  87.937 43.008 88.549 45.288 ;
     RECT  87.829 74.592 88.549 74.712 ;
     RECT  88.357 79.68 88.549 82.104 ;
     RECT  87.805 83.232 88.549 84.408 ;
     RECT  88.069 76.32 88.585 78.648 ;
     RECT  88.549 79.68 88.585 84.408 ;
     RECT  88.225 0.528 88.621 0.552 ;
     RECT  87.395 1.728 88.621 3.432 ;
     RECT  87.761 36.096 88.765 36.888 ;
     RECT  88.369 37.92 88.765 40.296 ;
     RECT  88.621 0.528 88.808 3.432 ;
     RECT  88.309 4.512 88.808 7.992 ;
     RECT  87.005 15.696 88.808 15.72 ;
     RECT  87.155 19.152 88.808 19.176 ;
     RECT  87.781 21.024 88.808 21.048 ;
     RECT  87.329 22.752 88.808 24.12 ;
     RECT  86.753 25.728 88.808 26.28 ;
     RECT  86.86 27.312 88.808 27.912 ;
     RECT  87.901 29.232 88.808 31.8 ;
     RECT  88.549 32.832 88.808 33.096 ;
     RECT  88.357 34.08 88.808 34.92 ;
     RECT  88.765 36.096 88.808 40.296 ;
     RECT  88.549 41.76 88.808 45.288 ;
     RECT  87.865 46.272 88.808 49.56 ;
     RECT  87.509 50.736 88.808 51.144 ;
     RECT  87.581 52.512 88.808 53.64 ;
     RECT  88.021 66.48 88.808 66.504 ;
     RECT  87.395 71.808 88.808 71.832 ;
     RECT  88.549 74.16 88.808 74.712 ;
     RECT  88.585 76.32 88.808 84.408 ;
     RECT  88.501 85.488 88.835 86.232 ;
     RECT  88.808 0.528 89.104 84.408 ;
     RECT  89.104 0.528 89.123 2.28 ;
     RECT  89.104 82.032 89.161 84.408 ;
     RECT  88.835 85.488 89.161 86.136 ;
     RECT  89.104 23.664 89.201 24.12 ;
     RECT  89.104 79.008 89.219 80.424 ;
     RECT  89.104 32.832 89.237 33.096 ;
     RECT  89.104 49.536 89.273 49.56 ;
     RECT  89.104 34.08 89.309 35.208 ;
     RECT  89.104 36.48 89.315 39.768 ;
     RECT  89.104 41.76 89.345 47.352 ;
     RECT  89.104 74.16 89.345 74.664 ;
     RECT  89.219 79.152 89.345 80.424 ;
     RECT  89.161 82.032 89.363 86.136 ;
     RECT  89.104 3.312 89.411 4.584 ;
     RECT  89.104 29.088 89.411 30.936 ;
     RECT  89.345 42.144 89.411 47.352 ;
     RECT  89.411 46.752 89.489 47.352 ;
     RECT  89.315 36.672 89.507 39.768 ;
     RECT  89.411 42.144 89.507 45.144 ;
     RECT  89.507 36.672 89.561 39.528 ;
     RECT  89.104 66.192 89.633 66.504 ;
     RECT  89.363 82.032 89.699 85.512 ;
     RECT  89.237 33.072 89.741 33.096 ;
     RECT  89.123 0.528 89.795 0.6 ;
     RECT  89.104 25.392 89.813 26.28 ;
     RECT  89.104 50.592 89.849 53.112 ;
     RECT  89.561 36.672 89.921 38.184 ;
     RECT  89.561 39.36 89.921 39.528 ;
     RECT  89.345 74.16 89.987 74.52 ;
     RECT  89.633 66.192 90.028 66.216 ;
     RECT  89.849 50.832 90.029 51.144 ;
     RECT  89.104 54.144 90.029 54.6 ;
     RECT  89.411 29.232 90.065 30.936 ;
     RECT  89.795 0.576 90.1 0.6 ;
     RECT  89.345 80.4 90.124 80.424 ;
     RECT  89.411 3.408 90.133 4.584 ;
     RECT  89.104 5.712 90.133 7.992 ;
     RECT  90.029 54.576 90.133 54.6 ;
     RECT  90.133 3.408 90.173 7.992 ;
     RECT  89.104 76.944 90.177 77.592 ;
     RECT  90.173 5.472 90.179 7.992 ;
     RECT  89.345 79.152 90.209 79.176 ;
     RECT  90.177 76.944 90.229 78.072 ;
     RECT  89.849 52.464 90.245 53.112 ;
     RECT  89.309 34.08 90.284 34.104 ;
     RECT  89.104 75.648 90.313 75.672 ;
     RECT  89.507 42.144 90.317 43.896 ;
     RECT  90.133 72.96 90.317 72.984 ;
     RECT  90.133 54.576 90.353 54.696 ;
     RECT  90.313 74.688 90.353 75.672 ;
     RECT  90.065 30.672 90.389 30.936 ;
     RECT  89.921 36.672 90.461 37.992 ;
     RECT  90.173 3.408 90.563 4.2 ;
     RECT  89.201 24.048 90.565 24.12 ;
     RECT  90.565 23.568 90.601 24.12 ;
     RECT  90.317 43.008 90.613 43.896 ;
     RECT  89.507 45.12 90.613 45.144 ;
     RECT  90.229 76.896 90.641 78.072 ;
     RECT  90.601 23.568 90.677 24.936 ;
     RECT  90.1 0.576 90.7 0.648 ;
     RECT  89.123 1.728 90.709 2.28 ;
     RECT  90.709 1.152 90.793 2.28 ;
     RECT  90.179 5.472 90.821 7.512 ;
     RECT  89.104 27.696 90.853 27.912 ;
     RECT  90.065 29.232 90.853 29.256 ;
     RECT  90.677 24.912 90.857 24.936 ;
     RECT  90.853 27.696 90.893 29.256 ;
     RECT  89.699 82.032 90.901 82.152 ;
     RECT  90.029 51.12 90.929 51.144 ;
     RECT  89.699 83.712 90.929 85.512 ;
     RECT  90.461 36.672 90.961 37.128 ;
     RECT  90.929 83.712 90.961 84.984 ;
     RECT  89.489 46.752 91.033 47.064 ;
     RECT  90.901 81.456 91.033 82.152 ;
     RECT  90.389 30.912 91.037 30.936 ;
     RECT  90.961 83.232 91.037 84.984 ;
     RECT  90.893 27.744 91.069 29.256 ;
     RECT  91.033 80.784 91.109 82.152 ;
     RECT  90.563 3.84 91.139 4.2 ;
     RECT  91.109 80.784 91.141 81.48 ;
     RECT  91.037 83.232 91.189 84.936 ;
     RECT  90.613 43.008 91.217 45.144 ;
     RECT  91.033 46.704 91.217 47.064 ;
     RECT  91.069 27.744 91.235 29.352 ;
     RECT  90.793 1.728 91.237 2.28 ;
     RECT  91.141 80.016 91.249 81.48 ;
     RECT  89.309 35.184 91.253 35.208 ;
     RECT  90.353 74.688 91.285 74.712 ;
     RECT  90.284 34.08 91.321 34.152 ;
     RECT  89.921 39.36 91.321 39.384 ;
     RECT  90.821 5.472 91.325 7.272 ;
     RECT  90.961 36.384 91.361 37.128 ;
     RECT  91.285 74.64 91.379 74.712 ;
     RECT  90.997 32.832 91.393 32.856 ;
     RECT  91.249 79.392 91.397 81.48 ;
     RECT  89.813 26.256 91.429 26.28 ;
     RECT  91.325 5.472 91.433 6.216 ;
     RECT  91.235 27.744 91.469 28.824 ;
     RECT  91.189 31.344 91.501 31.368 ;
     RECT  91.393 32.592 91.501 33.096 ;
     RECT  90.805 76.368 91.577 76.392 ;
     RECT  91.397 80.784 91.577 81.48 ;
     RECT  91.433 5.472 91.58 5.736 ;
     RECT  91.321 38.928 91.609 39.384 ;
     RECT  91.361 36.384 91.649 37.032 ;
     RECT  91.217 43.008 91.649 45 ;
     RECT  91.649 44.976 91.66 45 ;
     RECT  91.58 5.184 91.667 5.736 ;
     RECT  91.285 86.208 91.721 86.28 ;
     RECT  91.397 79.392 91.793 79.416 ;
     RECT  91.609 38.928 91.811 39.624 ;
     RECT  91.217 46.8 91.82 47.064 ;
     RECT  91.717 50.976 91.868 51 ;
     RECT  90.781 41.472 91.897 41.496 ;
     RECT  91.868 50.784 91.897 51 ;
     RECT  91.897 41.04 91.901 41.496 ;
     RECT  91.649 43.008 91.909 43.944 ;
     RECT  91.765 0.096 91.937 0.12 ;
     RECT  91.321 34.08 91.937 34.92 ;
     RECT  91.811 38.928 91.973 39.288 ;
     RECT  91.577 81.168 91.973 81.48 ;
     RECT  91.909 42.576 91.996 43.944 ;
     RECT  91.237 1.728 92.099 2.712 ;
     RECT  91.189 82.608 92.108 84.936 ;
     RECT  91.901 41.04 92.117 41.112 ;
     RECT  92.108 82.608 92.117 85.512 ;
     RECT  91.501 31.344 92.156 33.096 ;
     RECT  91.937 34.08 92.156 34.728 ;
     RECT  92.117 84.288 92.195 85.512 ;
     RECT  90.641 78.048 92.221 78.072 ;
     RECT  92.005 48.624 92.257 48.648 ;
     RECT  91.897 50.784 92.257 51.336 ;
     RECT  92.195 84.288 92.261 84.936 ;
     RECT  92.099 1.728 92.291 1.848 ;
     RECT  91.82 46.8 92.293 47.352 ;
     RECT  90.353 54.576 92.293 54.6 ;
     RECT  92.291 1.728 92.297 1.752 ;
     RECT  91.667 5.664 92.297 5.736 ;
     RECT  92.117 41.088 92.297 41.112 ;
     RECT  92.261 84.336 92.297 84.936 ;
     RECT  91.139 3.84 92.329 4.008 ;
     RECT  92.329 2.832 92.333 4.008 ;
     RECT  91.973 81.168 92.333 81.192 ;
     RECT  92.297 84.336 92.333 84.36 ;
     RECT  92.293 46.176 92.341 47.352 ;
     RECT  92.257 48.624 92.341 51.336 ;
     RECT  92.297 5.712 92.369 5.736 ;
     RECT  91.973 38.928 92.369 38.952 ;
     RECT  91.379 74.688 92.369 74.712 ;
     RECT  90.677 23.568 92.405 23.592 ;
     RECT  92.341 46.176 92.405 51.336 ;
     RECT  92.293 54.144 92.405 54.6 ;
     RECT  92.405 46.176 92.441 48.648 ;
     RECT  91.469 27.744 92.473 28.68 ;
     RECT  92.405 50.064 92.473 51.336 ;
     RECT  90.245 52.464 92.473 52.488 ;
     RECT  92.473 50.064 92.513 52.488 ;
     RECT  92.117 82.608 92.513 82.632 ;
     RECT  92.513 50.064 92.531 51.912 ;
     RECT  91.429 25.536 92.545 26.28 ;
     RECT  92.473 27.744 92.581 28.728 ;
     RECT  92.401 29.808 92.581 29.832 ;
     RECT  91.649 37.008 92.581 37.032 ;
     RECT  92.441 46.224 92.585 48.648 ;
     RECT  91.325 7.248 92.627 7.272 ;
     RECT  92.545 25.536 92.629 26.664 ;
     RECT  92.581 37.008 92.665 37.656 ;
     RECT  91.996 43.008 92.693 43.944 ;
     RECT  92.629 25.056 92.716 26.664 ;
     RECT  92.156 31.344 92.765 34.728 ;
     RECT  92.765 31.344 92.801 32.232 ;
     RECT  92.333 2.832 92.837 3.864 ;
     RECT  92.405 54.144 92.837 54.168 ;
     RECT  92.801 31.344 92.905 31.752 ;
     RECT  92.765 33.312 92.909 34.728 ;
     RECT  92.909 33.312 92.915 34.104 ;
     RECT  92.531 50.592 92.915 51.912 ;
     RECT  92.915 50.688 92.945 51.912 ;
     RECT  92.837 3.408 93.089 3.864 ;
     RECT  92.581 27.744 93.089 29.832 ;
     RECT  92.945 50.688 93.233 50.808 ;
     RECT  92.716 25.824 93.445 26.664 ;
     RECT  92.905 31.152 93.913 31.752 ;
     RECT  93.913 31.152 93.985 32.28 ;
     RECT  93.985 31.152 94.069 32.328 ;
     RECT  92.915 33.312 94.069 33.816 ;
     RECT  94.057 39.024 94.069 39.048 ;
     RECT  93.121 24.72 94.208 24.744 ;
     RECT  93.445 25.824 94.208 26.712 ;
     RECT  93.089 28.368 94.208 29.832 ;
     RECT  94.069 31.152 94.208 33.816 ;
     RECT  93.193 35.52 94.208 35.544 ;
     RECT  92.797 36.672 94.208 36.696 ;
     RECT  94.069 38.016 94.208 38.04 ;
     RECT  94.069 39.024 94.208 39.24 ;
     RECT  93.229 41.616 94.208 41.64 ;
     RECT  92.693 43.392 94.208 43.944 ;
     RECT  92.585 46.224 94.208 47.88 ;
     RECT  93.233 50.736 94.208 50.808 ;
     RECT  92.945 51.888 94.208 51.912 ;
     RECT  92.221 77.568 94.208 78.072 ;
     RECT  94.208 2.148 94.312 84.252 ;
     RECT  94.312 2.418 94.504 83.982 ;
     RECT  94.504 43.392 94.565 43.896 ;
     RECT  94.504 38.736 94.643 39.24 ;
     RECT  94.504 32.208 94.709 33.576 ;
     RECT  94.504 37.008 94.739 37.608 ;
     RECT  94.643 38.736 94.739 38.76 ;
     RECT  94.504 26.592 94.781 26.664 ;
     RECT  94.504 28.272 94.853 29.832 ;
     RECT  94.504 35.52 95.105 35.544 ;
     RECT  94.853 28.368 95.141 29.832 ;
     RECT  94.739 37.584 95.141 37.608 ;
     RECT  94.504 47.04 95.249 47.16 ;
     RECT  94.504 24.192 95.821 24.216 ;
     RECT  94.709 32.256 96.037 33.576 ;
     RECT  94.781 26.592 96.041 26.616 ;
     RECT  96.037 31.776 96.133 33.576 ;
     RECT  96.133 31.776 96.179 34.248 ;
     RECT  95.821 24.192 96.401 24.648 ;
     RECT  96.401 24.192 96.437 24.6 ;
     RECT  95.141 28.368 96.437 29.592 ;
     RECT  96.179 31.776 96.509 32.52 ;
     RECT  96.437 29.28 96.613 29.592 ;
     RECT  96.613 29.28 96.941 30.168 ;
     RECT  96.179 33.552 97.373 34.248 ;
     RECT  96.437 24.48 97.441 24.6 ;
     RECT  96.973 26.208 97.523 26.232 ;
     RECT  96.509 32.496 97.553 32.52 ;
     RECT  97.477 27.36 97.589 27.384 ;
     RECT  96.941 29.28 97.657 29.976 ;
     RECT  97.657 29.04 97.729 29.976 ;
     RECT  97.441 24.48 97.913 24.888 ;
     RECT  97.729 28.416 97.945 29.976 ;
     RECT  97.373 33.552 97.949 33.576 ;
     RECT  97.945 27.984 98.017 29.976 ;
     RECT  98.017 27.984 98.021 30.744 ;
     RECT  98.021 27.984 98.057 28.008 ;
     RECT  97.913 24.528 98.201 24.552 ;
     RECT  98.021 29.04 98.593 30.744 ;
     RECT  98.593 29.04 98.732 31.176 ;
     RECT  98.732 29.04 99.608 31.224 ;
     RECT  98.017 32.544 99.608 32.568 ;
     RECT  94.565 43.392 99.608 43.416 ;
     RECT  99.608 2.148 99.712 84.252 ;
     RECT  99.712 2.418 99.904 83.982 ;
     RECT  99.904 32.544 99.965 33.24 ;
     RECT  99.904 29.28 100.325 29.784 ;
     RECT  99.965 33.072 100.505 33.24 ;
     RECT  100.325 29.76 100.649 29.784 ;
     RECT  100.505 33.216 101.909 33.24 ;
     RECT  99.904 43.392 105.008 43.416 ;
     RECT  105.008 2.148 105.112 84.252 ;
     RECT  105.112 2.418 105.304 83.982 ;
     RECT  105.304 43.392 110.408 43.416 ;
     RECT  110.408 2.148 110.512 84.252 ;
     RECT  110.512 2.418 110.704 83.982 ;
     RECT  110.704 43.392 115.808 43.416 ;
     RECT  115.808 2.148 115.912 84.252 ;
     RECT  115.912 2.418 116.104 83.982 ;
     RECT  116.104 43.392 121.208 43.416 ;
     RECT  121.208 2.148 121.312 84.252 ;
     RECT  121.312 2.418 121.504 83.982 ;
     RECT  121.504 43.392 124.913 43.416 ;
     RECT  126.608 2.148 126.712 84.252 ;
     RECT  126.712 2.418 126.904 83.982 ;
    LAYER M5 ;
     RECT  42.912 0.016 92.28 1.763 ;
     RECT  43.008 1.763 92.28 1.811 ;
     RECT  43.296 1.811 92.28 1.859 ;
     RECT  44.352 1.859 51.672 1.907 ;
     RECT  2.4 2.137 2.52 2.151 ;
     RECT  7.8 2.137 7.92 2.151 ;
     RECT  13.2 2.137 13.32 2.151 ;
     RECT  18.6 2.137 18.72 2.151 ;
     RECT  24 2.137 24.12 2.151 ;
     RECT  29.4 2.137 29.52 2.151 ;
     RECT  34.8 2.137 34.92 2.151 ;
     RECT  40.2 2.137 40.32 2.151 ;
     RECT  94.2 2.137 94.32 2.151 ;
     RECT  99.6 2.137 99.72 2.151 ;
     RECT  105 2.137 105.12 2.151 ;
     RECT  110.4 2.137 110.52 2.151 ;
     RECT  115.8 2.137 115.92 2.151 ;
     RECT  121.2 2.137 121.32 2.151 ;
     RECT  126.6 2.137 126.72 2.151 ;
     RECT  44.352 1.907 51.624 2.291 ;
     RECT  52.704 1.859 81.624 2.291 ;
     RECT  82.752 1.859 92.088 2.821 ;
     RECT  52.704 2.291 70.68 2.915 ;
     RECT  45.072 2.291 51.624 3.301 ;
     RECT  52.704 2.915 53.016 3.301 ;
     RECT  54.096 2.915 70.68 3.443 ;
     RECT  54.096 3.443 54.168 3.539 ;
     RECT  82.752 2.821 92.808 3.875 ;
     RECT  71.952 2.291 81.624 4.019 ;
     RECT  82.752 3.875 91.896 4.019 ;
     RECT  83.04 4.019 91.656 4.211 ;
     RECT  55.68 3.443 70.68 4.261 ;
     RECT  71.952 4.019 80.76 4.261 ;
     RECT  54.096 3.539 54.12 4.501 ;
     RECT  55.68 4.261 80.76 4.501 ;
     RECT  45.072 3.301 53.016 4.547 ;
     RECT  45.312 4.547 53.016 4.595 ;
     RECT  83.04 4.211 90.264 4.595 ;
     RECT  54.096 4.501 80.76 5.029 ;
     RECT  54.096 5.029 80.952 5.171 ;
     RECT  45.312 4.595 46.296 5.747 ;
     RECT  47.712 4.595 53.016 5.747 ;
     RECT  88.272 4.595 90.264 5.747 ;
     RECT  91.632 4.211 91.656 5.747 ;
     RECT  47.712 5.747 52.968 6.181 ;
     RECT  83.04 4.595 87.24 6.181 ;
     RECT  88.272 5.747 89.448 6.181 ;
     RECT  45.312 5.747 46.104 6.227 ;
     RECT  83.04 6.181 89.448 6.371 ;
     RECT  54.096 5.171 80.856 6.515 ;
     RECT  47.664 6.181 52.968 6.805 ;
     RECT  54.096 6.515 78.888 6.899 ;
     RECT  80.208 6.515 80.856 6.899 ;
     RECT  80.352 6.899 80.856 6.947 ;
     RECT  83.088 6.371 89.448 6.995 ;
     RECT  83.088 6.995 85.272 7.043 ;
     RECT  90.576 6.229 90.6 7.043 ;
     RECT  86.352 6.995 89.448 7.189 ;
     RECT  45.504 6.227 46.104 7.381 ;
     RECT  47.664 6.805 53.016 7.475 ;
     RECT  54.096 6.899 73.512 7.475 ;
     RECT  74.496 6.899 78.888 7.475 ;
     RECT  86.352 7.189 90.168 7.475 ;
     RECT  48.24 7.475 53.016 7.909 ;
     RECT  45.456 7.381 46.104 7.957 ;
     RECT  75.168 7.475 78.888 8.003 ;
     RECT  87.504 7.475 87.528 8.003 ;
     RECT  88.8 7.475 90.168 8.003 ;
     RECT  54.24 7.475 73.512 8.051 ;
     RECT  86.352 7.475 86.376 8.435 ;
     RECT  57.744 8.051 73.512 8.579 ;
     RECT  83.184 7.043 85.272 8.579 ;
     RECT  57.744 8.579 58.152 8.627 ;
     RECT  59.28 8.579 73.512 8.771 ;
     RECT  48.24 7.909 53.16 8.773 ;
     RECT  54.24 8.051 56.712 8.773 ;
     RECT  78 8.003 78.888 8.869 ;
     RECT  83.28 8.579 85.272 8.869 ;
     RECT  48.24 8.773 56.712 9.061 ;
     RECT  75.168 8.003 76.92 9.061 ;
     RECT  74.688 9.061 76.92 9.395 ;
     RECT  72.432 8.771 73.512 9.443 ;
     RECT  48.192 9.061 56.712 9.637 ;
     RECT  58.08 8.627 58.152 9.685 ;
     RECT  59.28 8.771 71.304 9.685 ;
     RECT  58.08 9.685 71.304 9.779 ;
     RECT  58.08 9.779 59.304 9.875 ;
     RECT  45.024 7.957 46.104 10.019 ;
     RECT  48.144 9.637 56.712 10.213 ;
     RECT  60.288 9.779 71.304 10.307 ;
     RECT  74.688 9.395 75.528 10.307 ;
     RECT  74.688 10.307 74.712 10.595 ;
     RECT  76.896 9.395 76.92 10.597 ;
     RECT  83.28 8.869 85.368 10.739 ;
     RECT  42.48 9.781 42.504 10.883 ;
     RECT  60.336 10.307 68.904 10.883 ;
     RECT  45.216 10.019 46.104 10.931 ;
     RECT  58.08 9.875 58.68 10.931 ;
     RECT  64.656 10.883 68.904 10.931 ;
     RECT  48.144 10.213 56.808 11.029 ;
     RECT  58.08 10.931 58.344 11.029 ;
     RECT  87.264 8.437 87.288 11.123 ;
     RECT  48.144 11.029 58.344 11.171 ;
     RECT  60.336 10.883 63.384 11.269 ;
     RECT  83.4 10.739 85.368 11.365 ;
     RECT  80.832 6.947 80.856 11.459 ;
     RECT  59.616 11.269 63.384 11.941 ;
     RECT  64.704 10.931 68.904 11.941 ;
     RECT  48.72 11.171 58.344 12.035 ;
     RECT  59.616 11.941 68.904 12.179 ;
     RECT  51 12.035 58.344 12.227 ;
     RECT  51 12.227 53.592 12.323 ;
     RECT  76.896 10.597 77.016 12.469 ;
     RECT  60.336 12.179 68.904 12.515 ;
     RECT  83.4 11.365 86.328 12.517 ;
     RECT  54.816 12.227 58.344 12.757 ;
     RECT  47.568 11.797 47.592 12.901 ;
     RECT  47.328 12.901 47.592 12.947 ;
     RECT  54.816 12.757 58.584 12.949 ;
     RECT  72.432 9.443 73.368 12.997 ;
     RECT  54.816 12.949 58.68 13.091 ;
     RECT  76.032 12.469 77.016 13.093 ;
     RECT  78 8.869 79.512 13.093 ;
     RECT  60.336 12.515 62.616 13.139 ;
     RECT  72.432 12.997 74.088 13.139 ;
     RECT  63.696 12.515 68.904 13.427 ;
     RECT  76.032 13.093 79.512 13.523 ;
     RECT  51 12.323 53.448 13.573 ;
     RECT  54.816 13.091 58.488 13.573 ;
     RECT  48.72 12.035 49.944 13.621 ;
     RECT  51 13.573 58.488 13.621 ;
     RECT  70.176 10.307 71.304 13.621 ;
     RECT  72.432 13.139 73.368 13.621 ;
     RECT  45.504 10.931 46.104 14.197 ;
     RECT  47.328 12.947 47.352 14.291 ;
     RECT  78 13.523 79.512 14.291 ;
     RECT  83.28 12.517 86.328 14.291 ;
     RECT  42.48 12.517 42.504 14.339 ;
     RECT  76.032 13.523 77.016 14.339 ;
     RECT  61.008 13.139 62.616 14.389 ;
     RECT  44.352 11.221 44.376 14.867 ;
     RECT  48.72 13.621 58.488 14.867 ;
     RECT  83.4 14.291 86.328 14.867 ;
     RECT  45.36 14.197 46.104 15.347 ;
     RECT  54.816 14.867 58.488 15.349 ;
     RECT  60.72 14.389 62.616 15.443 ;
     RECT  78 14.291 78.888 15.589 ;
     RECT  76.896 14.339 77.016 15.877 ;
     RECT  78 15.589 79.56 15.877 ;
     RECT  48.72 14.867 53.448 15.925 ;
     RECT  70.176 13.621 73.368 15.925 ;
     RECT  74.832 14.773 74.856 15.925 ;
     RECT  61.008 15.443 62.616 16.019 ;
     RECT  81.36 14.197 81.384 16.019 ;
     RECT  54.816 15.349 58.728 16.355 ;
     RECT  70.176 15.925 74.856 16.501 ;
     RECT  76.896 15.877 79.56 16.549 ;
     RECT  83.4 14.867 85.368 16.595 ;
     RECT  61.008 16.019 62.568 17.077 ;
     RECT  64.032 13.427 68.904 17.077 ;
     RECT  60.144 17.077 62.568 17.219 ;
     RECT  64.032 17.077 68.952 17.219 ;
     RECT  70.176 16.501 75.624 17.267 ;
     RECT  45.504 15.347 46.104 17.411 ;
     RECT  76.896 16.549 79.848 17.605 ;
     RECT  83.4 16.595 84.12 17.605 ;
     RECT  45.6 17.411 46.104 17.651 ;
     RECT  70.608 17.267 75.624 17.651 ;
     RECT  70.608 17.651 73.368 18.469 ;
     RECT  76.896 17.605 79.992 18.613 ;
     RECT  48.72 15.925 53.736 18.707 ;
     RECT  54.816 16.355 58.488 18.805 ;
     RECT  43.296 17.077 43.32 18.851 ;
     RECT  48.72 18.707 53.448 18.851 ;
     RECT  76.896 18.613 80.376 18.851 ;
     RECT  83.232 17.605 84.12 18.851 ;
     RECT  45.6 17.651 45.912 19.333 ;
     RECT  74.832 17.651 75.624 19.333 ;
     RECT  86.64 19.141 86.664 19.909 ;
     RECT  70.32 18.469 73.368 20.053 ;
     RECT  83.232 18.851 84.072 20.339 ;
     RECT  70.08 20.053 73.368 20.341 ;
     RECT  74.832 19.333 75.768 20.341 ;
     RECT  61.008 17.219 62.568 20.533 ;
     RECT  45.6 19.333 46.536 20.581 ;
     RECT  85.248 16.595 85.368 20.821 ;
     RECT  86.64 19.909 87.144 20.821 ;
     RECT  45.6 20.581 46.584 20.965 ;
     RECT  85.248 20.821 87.144 21.013 ;
     RECT  44.448 19.621 44.472 21.061 ;
     RECT  43.488 21.061 44.472 21.155 ;
     RECT  60.48 20.533 62.568 21.155 ;
     RECT  64.032 17.219 68.904 21.205 ;
     RECT  70.08 20.341 75.768 21.347 ;
     RECT  76.896 18.851 79.992 21.349 ;
     RECT  54.816 18.805 59.256 21.683 ;
     RECT  70.08 21.347 75.624 21.683 ;
     RECT  42.192 20.149 42.216 21.971 ;
     RECT  61.008 21.155 62.568 22.259 ;
     RECT  63.888 21.205 68.904 22.259 ;
     RECT  74.832 21.683 75.624 22.501 ;
     RECT  76.896 21.349 80.136 22.501 ;
     RECT  54.816 21.683 58.392 22.741 ;
     RECT  85.248 21.013 87.816 22.741 ;
     RECT  88.8 8.003 89.448 22.741 ;
     RECT  85.248 22.741 89.448 23.219 ;
     RECT  53.952 22.741 58.392 23.315 ;
     RECT  48.72 18.851 52.68 23.317 ;
     RECT  74.832 22.501 80.136 23.365 ;
     RECT  81.408 19.621 81.432 23.365 ;
     RECT  74.832 23.365 81.432 23.557 ;
     RECT  74.4 23.557 81.432 23.603 ;
     RECT  43.488 21.155 43.512 23.653 ;
     RECT  83.232 20.339 83.712 23.653 ;
     RECT  54.816 23.315 58.392 23.891 ;
     RECT  61.008 22.259 62.472 23.891 ;
     RECT  76.896 23.603 81.432 24.035 ;
     RECT  42.096 23.317 42.12 24.083 ;
     RECT  61.008 23.891 62.376 24.083 ;
     RECT  90.576 23.557 90.6 24.083 ;
     RECT  70.08 21.683 73.368 24.085 ;
     RECT  74.4 23.603 75.624 24.085 ;
     RECT  70.08 24.085 75.624 24.179 ;
     RECT  94.2 2.151 94.512 24.181 ;
     RECT  47.76 23.317 52.68 24.419 ;
     RECT  85.248 23.219 85.896 24.469 ;
     RECT  87.024 23.219 89.448 24.469 ;
     RECT  76.896 24.035 79.992 24.613 ;
     RECT  47.76 24.419 47.784 24.899 ;
     RECT  74.304 24.179 75.624 24.995 ;
     RECT  45.6 20.965 46.68 25.045 ;
     RECT  92.592 7.237 92.616 25.045 ;
     RECT  82.8 23.653 83.712 25.139 ;
     RECT  85.248 24.469 89.448 25.139 ;
     RECT  64.032 22.259 68.904 25.189 ;
     RECT  70.08 24.179 73.128 25.285 ;
     RECT  48.912 24.419 52.68 25.477 ;
     RECT  82.896 25.139 83.712 25.477 ;
     RECT  74.496 24.995 75.624 25.571 ;
     RECT  64.032 25.189 69.096 25.573 ;
     RECT  82.896 25.477 83.832 25.621 ;
     RECT  59.856 23.269 59.88 25.813 ;
     RECT  61.008 24.083 62.112 25.813 ;
     RECT  43.488 23.653 44.472 25.955 ;
     RECT  59.856 25.813 62.112 25.955 ;
     RECT  63.984 25.573 69.096 26.101 ;
     RECT  48.912 25.477 53.64 26.149 ;
     RECT  76.752 24.613 79.992 26.197 ;
     RECT  81.408 24.035 81.432 26.197 ;
     RECT  87.072 25.139 89.448 26.291 ;
     RECT  45.6 25.045 47.304 26.437 ;
     RECT  43.488 25.955 43.512 26.483 ;
     RECT  70.08 25.285 73.272 26.483 ;
     RECT  85.248 25.139 85.896 26.533 ;
     RECT  94.2 24.181 95.16 26.627 ;
     RECT  48.528 26.149 53.64 26.629 ;
     RECT  54.816 23.891 58.344 26.629 ;
     RECT  48.528 26.629 58.344 26.675 ;
     RECT  92.592 25.045 92.664 26.675 ;
     RECT  48.528 26.675 52.68 26.819 ;
     RECT  63.552 26.101 69.096 26.819 ;
     RECT  44.64 26.437 47.304 27.059 ;
     RECT  76.752 26.197 81.432 27.061 ;
     RECT  82.896 25.621 84.216 27.301 ;
     RECT  85.248 26.533 86.424 27.301 ;
     RECT  87.792 26.291 89.448 27.301 ;
     RECT  48.912 26.819 52.68 27.395 ;
     RECT  97.488 24.469 97.512 27.395 ;
     RECT  76.704 27.061 81.432 27.587 ;
     RECT  63.984 26.819 69.096 27.635 ;
     RECT  52.56 27.395 52.68 27.731 ;
     RECT  64.128 27.635 69.096 27.827 ;
     RECT  59.904 25.955 62.112 27.829 ;
     RECT  44.64 27.059 47.064 27.971 ;
     RECT  54.432 26.675 58.344 27.971 ;
     RECT  82.896 27.301 89.448 27.971 ;
     RECT  40.2 2.151 40.512 28.405 ;
     RECT  41.616 26.245 41.64 28.405 ;
     RECT  80.976 27.587 81.432 28.405 ;
     RECT  40.2 28.405 41.64 28.451 ;
     RECT  83.232 27.971 89.448 28.451 ;
     RECT  44.64 27.971 46.68 28.453 ;
     RECT  76.704 27.587 79.992 28.643 ;
     RECT  59.904 27.829 63.096 29.123 ;
     RECT  83.28 28.451 89.448 29.267 ;
     RECT  85.248 29.267 89.448 29.269 ;
     RECT  92.592 26.675 92.616 29.315 ;
     RECT  54.816 27.971 58.344 29.365 ;
     RECT  40.2 28.451 41.256 29.555 ;
     RECT  85.248 29.269 89.592 29.603 ;
     RECT  54.816 29.365 58.44 29.605 ;
     RECT  59.904 29.123 62.112 29.651 ;
     RECT  70.08 26.483 73.128 29.699 ;
     RECT  80.976 28.405 81.528 29.699 ;
     RECT  99.6 2.151 99.912 29.749 ;
     RECT  43.728 28.453 46.68 30.035 ;
     RECT  54.816 29.605 58.728 30.037 ;
     RECT  43.872 30.035 46.68 30.661 ;
     RECT  43.872 30.661 46.776 30.803 ;
     RECT  54.816 30.037 59.064 30.851 ;
     RECT  99.12 29.749 99.912 31.189 ;
     RECT  64.128 27.827 69 31.237 ;
     RECT  43.872 30.803 46.68 31.331 ;
     RECT  91.2 27.733 91.224 31.379 ;
     RECT  63.648 31.237 69 31.381 ;
     RECT  70.08 29.699 72.912 31.381 ;
     RECT  60.576 29.651 62.112 31.669 ;
     RECT  63.648 31.381 72.912 31.669 ;
     RECT  60.576 31.669 72.912 31.763 ;
     RECT  52.656 27.731 52.68 31.813 ;
     RECT  45.6 31.331 46.68 31.861 ;
     RECT  83.28 29.267 84.216 31.861 ;
     RECT  43.872 31.331 44.184 31.907 ;
     RECT  85.248 29.603 89.304 31.907 ;
     RECT  83.232 31.861 84.216 32.005 ;
     RECT  94.2 26.627 94.512 32.053 ;
     RECT  98.784 31.189 99.912 32.579 ;
     RECT  42.768 32.149 42.792 32.819 ;
     RECT  44.16 31.907 44.184 32.869 ;
     RECT  40.2 29.555 40.512 32.965 ;
     RECT  91.872 32.437 91.896 33.061 ;
     RECT  94.08 32.053 94.512 33.061 ;
     RECT  64.128 31.763 72.912 33.107 ;
     RECT  85.344 31.907 89.304 33.107 ;
     RECT  94.08 33.061 94.632 33.107 ;
     RECT  45.6 31.861 47.112 33.251 ;
     RECT  91.872 33.061 92.232 33.541 ;
     RECT  76.752 28.643 79.992 33.683 ;
     RECT  43.92 32.869 44.184 33.781 ;
     RECT  52.656 31.813 53.304 33.781 ;
     RECT  55.104 30.851 59.064 33.781 ;
     RECT  83.136 32.005 84.216 33.877 ;
     RECT  43.776 33.781 44.184 33.923 ;
     RECT  85.344 33.107 86.376 34.115 ;
     RECT  91.872 33.541 92.904 34.115 ;
     RECT  44.16 33.923 44.184 34.165 ;
     RECT  77.088 33.683 79.992 34.165 ;
     RECT  80.976 29.699 81.432 34.165 ;
     RECT  52.656 33.781 59.064 34.259 ;
     RECT  96.144 33.061 96.168 34.259 ;
     RECT  60.576 31.763 62.808 34.355 ;
     RECT  82.896 33.877 84.216 34.597 ;
     RECT  85.344 34.115 85.896 34.597 ;
     RECT  42.528 33.733 42.552 34.645 ;
     RECT  42.336 34.645 42.552 34.741 ;
     RECT  44.16 34.165 44.472 34.835 ;
     RECT  65.424 33.107 72.912 34.835 ;
     RECT  52.656 34.259 58.68 34.931 ;
     RECT  90.336 34.117 90.36 35.173 ;
     RECT  91.872 34.115 92.616 35.173 ;
     RECT  90.336 35.173 92.616 35.219 ;
     RECT  60.576 34.355 62.112 35.269 ;
     RECT  64.128 33.107 64.392 35.317 ;
     RECT  74.832 25.571 75.624 35.317 ;
     RECT  77.088 34.165 81.432 35.317 ;
     RECT  44.16 34.835 44.184 35.413 ;
     RECT  43.92 35.413 44.184 35.459 ;
     RECT  82.896 34.597 85.896 35.507 ;
     RECT  42.336 34.741 42.744 35.557 ;
     RECT  43.92 35.459 43.944 35.557 ;
     RECT  74.832 35.317 81.432 35.699 ;
     RECT  63.264 35.317 64.392 35.939 ;
     RECT  74.832 35.699 79.992 35.987 ;
     RECT  40.2 32.965 41.064 36.275 ;
     RECT  82.896 35.507 84.216 36.467 ;
     RECT  42.336 35.557 43.944 36.515 ;
     RECT  59.664 35.269 62.112 36.515 ;
     RECT  65.52 34.835 72.912 36.515 ;
     RECT  87.552 33.107 89.304 36.515 ;
     RECT  77.088 35.987 79.992 36.661 ;
     RECT  80.976 35.699 81.432 36.661 ;
     RECT  94.2 33.107 94.632 36.661 ;
     RECT  91.152 35.219 92.616 36.707 ;
     RECT  52.656 34.931 53.448 36.805 ;
     RECT  55.104 34.931 58.68 36.805 ;
     RECT  47.664 36.613 47.688 36.997 ;
     RECT  48.912 27.395 51.312 36.997 ;
     RECT  94.08 36.661 94.632 36.997 ;
     RECT  85.344 35.507 85.896 37.045 ;
     RECT  87.552 36.515 89.208 37.045 ;
     RECT  42.576 36.515 43.944 37.091 ;
     RECT  52.656 36.805 58.68 37.091 ;
     RECT  85.344 37.045 89.208 37.331 ;
     RECT  77.088 36.661 81.432 37.379 ;
     RECT  64.128 35.939 64.392 37.477 ;
     RECT  83.28 36.467 84.216 37.525 ;
     RECT  85.344 37.331 86.136 37.525 ;
     RECT  87.552 37.331 89.208 37.525 ;
     RECT  43.92 37.091 43.944 37.573 ;
     RECT  91.872 36.707 92.616 37.667 ;
     RECT  54.288 37.091 58.68 37.861 ;
     RECT  65.52 36.515 65.544 37.909 ;
     RECT  66.528 36.515 72.912 37.909 ;
     RECT  47.664 36.997 51.312 38.099 ;
     RECT  42.576 37.091 42.6 38.101 ;
     RECT  42.576 38.101 42.936 38.149 ;
     RECT  52.656 37.091 52.68 38.197 ;
     RECT  54.288 37.861 59.352 38.387 ;
     RECT  55.104 38.387 59.352 38.435 ;
     RECT  83.28 37.525 86.136 38.675 ;
     RECT  77.088 37.379 79.992 38.677 ;
     RECT  43.92 37.573 43.992 38.723 ;
     RECT  94.08 36.997 94.728 38.771 ;
     RECT  55.104 38.435 58.68 38.819 ;
     RECT  63.408 37.477 64.392 39.061 ;
     RECT  65.52 37.909 72.912 39.109 ;
     RECT  45.6 33.251 46.68 39.205 ;
     RECT  48 38.099 51.312 39.205 ;
     RECT  41.76 38.149 42.936 39.251 ;
     RECT  94.08 38.771 94.632 39.251 ;
     RECT  76.704 38.677 79.992 39.253 ;
     RECT  80.976 37.379 81.432 39.253 ;
     RECT  91.872 37.667 91.896 39.253 ;
     RECT  52.656 38.197 52.824 39.395 ;
     RECT  65.376 39.109 72.912 39.491 ;
     RECT  45.6 39.205 51.312 39.493 ;
     RECT  42.624 39.251 42.936 39.635 ;
     RECT  87.552 37.525 89.448 39.733 ;
     RECT  85.344 38.675 86.136 39.779 ;
     RECT  60.576 36.515 62.112 39.781 ;
     RECT  85.344 39.779 86.04 39.827 ;
     RECT  83.28 38.675 84.216 39.829 ;
     RECT  74.832 35.987 75.624 39.877 ;
     RECT  65.376 39.491 65.544 39.971 ;
     RECT  55.104 38.819 58.44 39.973 ;
     RECT  45.36 39.493 51.312 40.067 ;
     RECT  54.192 39.973 58.44 40.211 ;
     RECT  59.808 39.781 62.112 40.499 ;
     RECT  74.448 39.877 75.624 40.501 ;
     RECT  42.72 39.635 42.936 40.595 ;
     RECT  83.232 39.829 84.216 40.597 ;
     RECT  45.36 40.067 47.352 40.645 ;
     RECT  42.72 40.595 42.744 40.691 ;
     RECT  83.136 40.597 84.216 40.739 ;
     RECT  43.92 38.723 43.944 40.835 ;
     RECT  52.8 39.395 52.824 40.837 ;
     RECT  61.632 40.499 62.112 40.837 ;
     RECT  63.264 39.061 64.392 40.837 ;
     RECT  61.632 40.837 64.392 40.883 ;
     RECT  74.16 40.501 75.624 40.979 ;
     RECT  65.52 39.971 65.544 41.029 ;
     RECT  55.104 40.211 58.44 41.075 ;
     RECT  76.704 39.253 81.432 41.123 ;
     RECT  44.976 40.645 47.352 41.125 ;
     RECT  54.048 41.077 54.072 41.219 ;
     RECT  52.8 40.837 52.92 41.221 ;
     RECT  65.376 41.029 65.544 41.267 ;
     RECT  52.32 41.221 52.92 41.507 ;
     RECT  91.776 39.253 91.896 41.507 ;
     RECT  60.576 40.499 60.6 41.557 ;
     RECT  61.632 40.883 62.76 41.603 ;
     RECT  85.872 39.827 86.04 41.651 ;
     RECT  94.08 39.251 94.512 41.651 ;
     RECT  44.976 41.125 47.4 41.653 ;
     RECT  0.192 4.021 0.216 41.699 ;
     RECT  44.976 41.653 47.496 41.795 ;
     RECT  44.976 41.795 47.352 41.989 ;
     RECT  83.232 40.739 84.216 42.131 ;
     RECT  48.912 40.067 51.312 42.133 ;
     RECT  52.896 41.507 52.92 42.133 ;
     RECT  74.832 40.979 75.624 42.133 ;
     RECT  87.552 39.733 89.496 42.133 ;
     RECT  48.624 42.133 51.312 42.227 ;
     RECT  52.896 42.133 53.016 42.421 ;
     RECT  91.872 41.507 91.896 42.565 ;
     RECT  76.704 41.123 79.992 42.709 ;
     RECT  80.976 41.123 81.432 42.709 ;
     RECT  52.896 42.421 53.4 42.755 ;
     RECT  55.2 41.075 58.44 42.755 ;
     RECT  61.632 41.603 62.112 42.803 ;
     RECT  76.704 42.709 81.432 42.803 ;
     RECT  59.808 41.557 60.6 42.851 ;
     RECT  76.896 42.803 81.432 42.899 ;
     RECT  66.624 39.491 72.912 42.949 ;
     RECT  87.552 42.133 90.264 43.043 ;
     RECT  91.872 42.565 91.944 43.043 ;
     RECT  44.4 41.989 47.352 43.139 ;
     RECT  61.8 42.803 62.112 43.141 ;
     RECT  74.112 42.133 75.624 43.283 ;
     RECT  48.624 42.227 49.224 43.379 ;
     RECT  44.448 43.139 47.352 43.573 ;
     RECT  61.8 43.141 62.52 43.573 ;
     RECT  64.128 40.883 64.392 43.573 ;
     RECT  66.624 42.949 73.032 43.813 ;
     RECT  52.896 42.755 53.208 43.861 ;
     RECT  74.832 43.283 75.624 43.909 ;
     RECT  94.2 41.651 94.512 43.909 ;
     RECT  48.624 43.379 48.936 43.955 ;
     RECT  59.952 42.851 60.6 44.051 ;
     RECT  52.896 43.861 53.64 44.053 ;
     RECT  51 42.227 51.312 44.149 ;
     RECT  52.896 44.053 53.88 44.195 ;
     RECT  53.184 44.195 53.88 44.243 ;
     RECT  87.552 43.043 89.496 44.339 ;
     RECT  44.448 43.573 47.4 44.387 ;
     RECT  65.52 41.267 65.544 44.437 ;
     RECT  66.624 43.813 73.56 44.437 ;
     RECT  53.616 44.243 53.88 44.531 ;
     RECT  90.624 44.341 90.648 44.581 ;
     RECT  91.872 43.043 91.896 44.581 ;
     RECT  53.856 44.531 53.88 44.773 ;
     RECT  83.28 42.131 84.216 44.917 ;
     RECT  90.624 44.581 91.896 45.011 ;
     RECT  83.088 44.917 84.216 45.013 ;
     RECT  53.856 44.773 54.072 45.059 ;
     RECT  61.8 43.573 64.392 45.155 ;
     RECT  90.624 45.011 90.648 45.155 ;
     RECT  63.744 45.155 64.392 45.157 ;
     RECT  65.52 44.437 73.56 45.157 ;
     RECT  63.744 45.157 73.56 45.203 ;
     RECT  45.408 44.387 47.4 45.299 ;
     RECT  50.688 44.149 51.312 45.539 ;
     RECT  82.752 45.013 84.216 45.539 ;
     RECT  63.744 45.203 65.112 45.635 ;
     RECT  74.832 43.909 75.864 45.635 ;
     RECT  66.144 45.203 73.56 45.731 ;
     RECT  54.048 45.059 54.072 45.875 ;
     RECT  55.488 42.755 58.44 46.069 ;
     RECT  82.992 45.539 84.216 46.117 ;
     RECT  49.968 45.541 49.992 46.211 ;
     RECT  61.8 45.155 62.52 46.211 ;
     RECT  61.8 46.211 62.112 46.213 ;
     RECT  45.408 45.299 46.68 46.259 ;
     RECT  93.408 43.909 94.512 46.259 ;
     RECT  74.832 45.635 75.768 46.741 ;
     RECT  76.896 42.899 79.992 46.741 ;
     RECT  55.488 46.069 59.304 46.787 ;
     RECT  64.128 45.635 65.112 46.981 ;
     RECT  66.144 45.731 73.032 46.981 ;
     RECT  64.128 46.981 73.032 47.269 ;
     RECT  91.872 45.011 91.896 47.363 ;
     RECT  64.128 47.269 73.464 47.411 ;
     RECT  66.528 47.411 73.464 47.459 ;
     RECT  55.488 46.787 58.44 47.461 ;
     RECT  82.992 46.117 84.792 47.555 ;
     RECT  64.128 47.411 65.112 47.749 ;
     RECT  93.024 46.645 93.048 47.845 ;
     RECT  92.352 47.845 93.048 47.891 ;
     RECT  53.712 46.069 53.736 47.939 ;
     RECT  61.68 46.213 62.112 47.939 ;
     RECT  82.992 47.555 84.216 48.229 ;
     RECT  60.576 44.051 60.6 48.325 ;
     RECT  66.528 47.459 73.224 48.563 ;
     RECT  59.664 48.325 60.6 48.611 ;
     RECT  92.352 47.891 92.376 48.659 ;
     RECT  61.8 47.939 62.112 48.901 ;
     RECT  82.656 48.229 84.216 48.901 ;
     RECT  61.8 48.901 62.52 48.949 ;
     RECT  63.648 47.749 65.112 48.949 ;
     RECT  74.832 46.741 79.992 48.995 ;
     RECT  61.8 48.949 65.112 49.043 ;
     RECT  82.656 48.901 84.648 49.091 ;
     RECT  66.624 48.563 73.224 49.141 ;
     RECT  82.656 49.091 84.216 49.331 ;
     RECT  87.552 44.339 89.448 49.381 ;
     RECT  63.216 49.043 65.112 49.427 ;
     RECT  55.248 47.461 58.44 49.429 ;
     RECT  55.248 49.429 59.112 49.619 ;
     RECT  82.992 49.331 84.216 49.667 ;
     RECT  55.488 49.619 59.112 50.003 ;
     RECT  66.624 49.141 73.512 50.195 ;
     RECT  77.04 48.995 79.992 50.245 ;
     RECT  80.976 42.899 81.432 50.245 ;
     RECT  64.128 49.427 65.112 50.389 ;
     RECT  61.8 49.043 62.232 50.531 ;
     RECT  92.496 50.053 92.52 50.581 ;
     RECT  60.576 48.611 60.6 50.677 ;
     RECT  92.496 50.581 92.904 50.723 ;
     RECT  83.28 49.667 84.216 50.773 ;
     RECT  92.496 50.723 92.52 50.773 ;
     RECT  85.872 41.651 85.896 50.821 ;
     RECT  55.488 50.003 58.488 50.867 ;
     RECT  55.488 50.867 58.44 50.965 ;
     RECT  61.8 50.531 62.112 51.061 ;
     RECT  61.584 51.061 62.112 51.251 ;
     RECT  77.04 50.245 81.432 51.347 ;
     RECT  91.92 50.773 92.52 51.347 ;
     RECT  64.128 50.389 65.304 51.395 ;
     RECT  85.872 50.821 86.232 51.493 ;
     RECT  87.456 49.381 89.448 51.493 ;
     RECT  74.832 48.995 75.624 51.637 ;
     RECT  55.44 50.965 58.44 51.923 ;
     RECT  64.128 51.395 64.968 51.923 ;
     RECT  77.04 51.347 79.992 51.971 ;
     RECT  59.76 50.677 60.6 52.403 ;
     RECT  64.128 51.923 64.44 52.403 ;
     RECT  66.624 50.195 72.912 52.453 ;
     RECT  74.832 51.637 75.672 52.499 ;
     RECT  66.624 52.453 73.368 52.645 ;
     RECT  83.184 50.773 84.216 52.645 ;
     RECT  85.872 51.493 89.448 52.883 ;
     RECT  66.432 52.645 73.368 52.979 ;
     RECT  66.624 52.979 73.368 53.219 ;
     RECT  83.088 52.645 84.216 53.699 ;
     RECT  87.552 52.883 89.448 54.565 ;
     RECT  87.552 54.565 89.976 58.117 ;
     RECT  87.36 58.117 89.976 72.179 ;
     RECT  61.68 51.251 62.112 74.051 ;
     RECT  83.28 53.699 84.216 74.053 ;
     RECT  87.552 72.179 89.976 74.195 ;
     RECT  45.6 46.259 46.68 74.389 ;
     RECT  48.912 43.955 48.936 74.437 ;
     RECT  48.912 74.437 49.464 74.485 ;
     RECT  64.128 52.403 64.392 74.581 ;
     RECT  51 45.539 51.312 74.629 ;
     RECT  55.488 51.923 58.44 74.629 ;
     RECT  63.792 74.581 64.824 74.629 ;
     RECT  55.296 74.629 59.112 74.867 ;
     RECT  77.088 51.971 79.992 74.965 ;
     RECT  45.12 74.389 46.68 75.013 ;
     RECT  74.832 52.499 75.624 75.157 ;
     RECT  55.44 74.867 59.112 75.205 ;
     RECT  60.576 52.403 60.6 75.205 ;
     RECT  66.624 53.219 72.912 75.205 ;
     RECT  63.552 74.629 64.824 75.253 ;
     RECT  76.896 74.965 79.992 75.395 ;
     RECT  53.52 74.629 53.544 75.541 ;
     RECT  63.552 75.253 65.448 75.541 ;
     RECT  66.624 75.205 73.176 75.541 ;
     RECT  45.12 75.013 46.968 75.637 ;
     RECT  48.816 74.485 49.464 75.637 ;
     RECT  53.232 75.541 53.544 75.637 ;
     RECT  85.872 52.883 85.896 75.781 ;
     RECT  87.552 74.195 89.688 75.781 ;
     RECT  74.832 75.157 75.912 75.875 ;
     RECT  43.536 74.437 43.56 75.971 ;
     RECT  45.12 75.637 49.464 76.309 ;
     RECT  50.544 74.629 51.312 76.309 ;
     RECT  55.44 75.205 60.6 76.309 ;
     RECT  55.44 76.309 60.648 76.357 ;
     RECT  83.136 74.053 84.216 76.357 ;
     RECT  91.344 74.629 91.368 76.357 ;
     RECT  74.832 75.875 74.856 76.403 ;
     RECT  54.72 76.357 60.648 76.451 ;
     RECT  58.416 76.451 60.648 76.741 ;
     RECT  61.8 74.051 62.112 76.741 ;
     RECT  85.872 75.781 89.688 76.885 ;
     RECT  90.816 76.357 91.368 76.885 ;
     RECT  80.976 51.347 81.432 76.933 ;
     RECT  45.12 76.309 51.312 76.979 ;
     RECT  77.088 75.395 79.992 76.979 ;
     RECT  83.136 76.357 84.84 77.509 ;
     RECT  79.488 76.979 79.992 77.555 ;
     RECT  45.12 76.979 49.464 77.603 ;
     RECT  63.552 75.541 73.176 77.603 ;
     RECT  85.872 76.885 91.368 77.603 ;
     RECT  65.424 77.603 73.176 77.797 ;
     RECT  65.424 77.797 73.8 78.037 ;
     RECT  75.888 75.875 75.912 78.037 ;
     RECT  77.088 76.979 78.504 78.037 ;
     RECT  86.688 77.603 91.368 78.083 ;
     RECT  45.12 77.603 47.16 78.085 ;
     RECT  75.888 78.037 78.504 78.085 ;
     RECT  79.488 77.555 79.896 78.085 ;
     RECT  75.888 78.085 79.896 78.131 ;
     RECT  75.888 78.131 79.848 78.179 ;
     RECT  52.752 75.637 53.544 78.661 ;
     RECT  54.72 76.451 57.144 78.661 ;
     RECT  65.424 78.037 74.184 78.661 ;
     RECT  58.416 76.741 62.112 78.707 ;
     RECT  86.688 78.083 89.688 78.709 ;
     RECT  65.232 78.661 74.184 78.757 ;
     RECT  52.752 78.661 57.288 78.805 ;
     RECT  63.552 77.603 64.056 78.805 ;
     RECT  65.184 78.757 74.184 78.805 ;
     RECT  48.816 77.603 49.464 79.045 ;
     RECT  50.544 76.979 51.312 79.045 ;
     RECT  58.944 78.707 62.112 79.045 ;
     RECT  63.552 78.805 74.184 79.045 ;
     RECT  58.944 79.045 74.184 79.189 ;
     RECT  83.136 77.509 84.888 79.189 ;
     RECT  44.4 78.085 47.16 79.237 ;
     RECT  48.816 79.045 51.312 79.237 ;
     RECT  82.992 79.189 84.888 79.237 ;
     RECT  86.256 78.709 89.688 79.237 ;
     RECT  80.976 76.933 81.672 79.283 ;
     RECT  58.944 79.189 74.808 79.621 ;
     RECT  75.888 78.179 76.152 79.621 ;
     RECT  52.56 78.805 57.288 79.765 ;
     RECT  81.408 79.283 81.672 79.765 ;
     RECT  81.408 79.765 81.72 79.859 ;
     RECT  58.944 79.621 76.152 80.149 ;
     RECT  77.184 78.179 79.848 80.149 ;
     RECT  82.992 79.237 89.688 80.197 ;
     RECT  81.552 79.859 81.72 80.245 ;
     RECT  82.944 80.197 89.688 80.245 ;
     RECT  44.4 79.237 51.312 80.341 ;
     RECT  52.56 79.765 57.336 80.341 ;
     RECT  58.944 80.149 79.848 80.389 ;
     RECT  81.552 80.245 89.688 80.389 ;
     RECT  90.816 78.083 91.368 80.389 ;
     RECT  58.944 80.389 80.376 80.485 ;
     RECT  44.4 80.341 57.336 80.677 ;
     RECT  58.848 80.485 80.376 80.677 ;
     RECT  44.4 80.677 80.376 80.917 ;
     RECT  81.552 80.389 91.368 80.917 ;
     RECT  44.4 80.917 91.368 81.445 ;
     RECT  44.4 81.445 91.608 82.115 ;
     RECT  44.448 82.115 86.28 82.547 ;
     RECT  87.264 82.115 91.608 82.595 ;
     RECT  87.648 82.595 91.608 82.645 ;
     RECT  44.448 82.547 84.168 82.691 ;
     RECT  81.504 82.691 84.168 82.739 ;
     RECT  87.648 82.645 91.992 83.173 ;
     RECT  85.296 82.547 86.28 83.557 ;
     RECT  44.448 82.691 80.376 83.653 ;
     RECT  81.504 82.739 83.712 83.653 ;
     RECT  44.448 83.653 83.712 83.749 ;
     RECT  84.96 83.557 86.28 83.749 ;
     RECT  87.648 83.173 92.088 83.749 ;
     RECT  43.392 83.749 86.28 83.797 ;
     RECT  87.264 83.749 92.088 83.797 ;
     RECT  43.392 83.797 92.088 83.941 ;
     RECT  2.4 2.151 2.712 84.249 ;
     RECT  7.8 2.151 8.112 84.249 ;
     RECT  13.2 2.151 13.512 84.249 ;
     RECT  18.6 2.151 18.912 84.249 ;
     RECT  24 2.151 24.312 84.249 ;
     RECT  29.4 2.151 29.712 84.249 ;
     RECT  34.8 2.151 35.112 84.249 ;
     RECT  40.2 36.275 40.512 84.249 ;
     RECT  94.2 46.259 94.512 84.249 ;
     RECT  99.6 32.579 99.912 84.249 ;
     RECT  105 2.151 105.312 84.249 ;
     RECT  110.4 2.151 110.712 84.249 ;
     RECT  115.8 2.151 116.112 84.249 ;
     RECT  121.2 2.151 121.512 84.249 ;
     RECT  126.6 2.151 126.912 84.249 ;
     RECT  2.4 84.249 2.52 84.263 ;
     RECT  7.8 84.249 7.92 84.263 ;
     RECT  13.2 84.249 13.32 84.263 ;
     RECT  18.6 84.249 18.72 84.263 ;
     RECT  24 84.249 24.12 84.263 ;
     RECT  29.4 84.249 29.52 84.263 ;
     RECT  34.8 84.249 34.92 84.263 ;
     RECT  40.2 84.249 40.32 84.263 ;
     RECT  94.2 84.249 94.32 84.263 ;
     RECT  99.6 84.249 99.72 84.263 ;
     RECT  105 84.249 105.12 84.263 ;
     RECT  110.4 84.249 110.52 84.263 ;
     RECT  115.8 84.249 115.92 84.263 ;
     RECT  121.2 84.249 121.32 84.263 ;
     RECT  126.6 84.249 126.72 84.263 ;
     RECT  43.2 83.941 92.088 84.325 ;
     RECT  43.2 84.325 92.28 85.477 ;
     RECT  42.912 85.477 92.28 86.352 ;
     RECT  51.672 1.859 52.704 1.907 ;
     RECT  81.624 1.859 82.752 4.019 ;
     RECT  92.088 1.859 92.28 2.821 ;
     RECT  51.624 1.907 52.704 3.301 ;
     RECT  70.68 2.291 71.952 4.261 ;
     RECT  92.808 2.821 94.2 3.875 ;
     RECT  53.016 2.915 54.096 5.747 ;
     RECT  54.168 3.443 55.68 3.539 ;
     RECT  54.12 3.539 55.68 4.501 ;
     RECT  80.76 4.019 80.952 5.029 ;
     RECT  90.264 4.211 91.632 5.747 ;
     RECT  46.296 4.595 47.712 5.747 ;
     RECT  87.24 4.595 88.272 6.181 ;
     RECT  47.664 5.747 47.712 6.181 ;
     RECT  52.968 5.747 54.096 6.805 ;
     RECT  89.448 5.747 90.6 6.229 ;
     RECT  45.456 6.227 45.504 7.381 ;
     RECT  89.448 6.229 90.576 7.043 ;
     RECT  78.888 6.515 80.208 6.899 ;
     RECT  53.016 6.805 54.096 7.475 ;
     RECT  73.512 6.899 74.496 7.475 ;
     RECT  78.888 6.899 80.352 6.947 ;
     RECT  85.272 6.995 86.352 8.435 ;
     RECT  89.448 7.043 90.168 7.189 ;
     RECT  53.016 7.475 54.24 7.909 ;
     RECT  86.376 7.475 87.504 8.003 ;
     RECT  87.528 7.475 88.8 8.003 ;
     RECT  53.16 7.909 54.24 8.773 ;
     RECT  76.92 8.003 78 10.597 ;
     RECT  86.376 8.003 88.8 8.435 ;
     RECT  56.712 8.051 57.744 8.627 ;
     RECT  85.272 8.435 85.368 8.869 ;
     RECT  87.264 8.435 88.8 8.437 ;
     RECT  87.288 8.437 88.8 11.123 ;
     RECT  58.152 8.579 59.28 9.685 ;
     RECT  56.712 8.627 58.08 10.213 ;
     RECT  71.304 8.771 72.432 13.621 ;
     RECT  79.512 8.869 80.832 11.459 ;
     RECT  73.512 9.061 74.688 9.443 ;
     RECT  75.528 9.395 76.896 10.307 ;
     RECT  73.368 9.443 74.688 10.595 ;
     RECT  59.304 9.779 60.288 9.875 ;
     RECT  58.68 9.875 60.288 10.307 ;
     RECT  45.024 10.019 45.216 10.931 ;
     RECT  56.808 10.213 58.08 11.029 ;
     RECT  58.68 10.307 60.336 10.931 ;
     RECT  68.904 10.307 70.176 17.077 ;
     RECT  77.016 10.597 78 13.093 ;
     RECT  63.384 10.883 64.656 10.931 ;
     RECT  45.024 10.931 45.504 11.221 ;
     RECT  58.344 10.931 60.336 11.269 ;
     RECT  63.384 10.931 64.704 11.941 ;
     RECT  48.144 11.171 48.72 11.797 ;
     RECT  44.376 11.221 45.504 14.197 ;
     RECT  58.344 11.269 59.616 12.179 ;
     RECT  46.104 11.797 47.568 12.901 ;
     RECT  47.592 11.797 48.72 12.947 ;
     RECT  49.944 12.035 51 13.621 ;
     RECT  58.344 12.179 58.68 12.757 ;
     RECT  53.592 12.227 54.816 12.323 ;
     RECT  53.448 12.323 54.816 13.573 ;
     RECT  62.616 12.515 63.696 13.427 ;
     RECT  58.584 12.757 58.68 12.949 ;
     RECT  46.104 12.901 47.328 14.291 ;
     RECT  47.352 12.947 48.72 14.291 ;
     RECT  60.72 13.139 61.008 14.389 ;
     RECT  62.616 13.427 64.032 16.019 ;
     RECT  77.016 13.523 78 15.877 ;
     RECT  44.376 14.197 45.36 14.867 ;
     RECT  78.888 14.291 79.512 15.589 ;
     RECT  73.368 14.773 74.832 15.925 ;
     RECT  53.448 14.867 54.816 15.925 ;
     RECT  53.736 15.925 54.816 18.707 ;
     RECT  62.568 16.019 64.032 21.205 ;
     RECT  75.624 16.501 76.896 19.333 ;
     RECT  84.12 16.595 85.248 18.851 ;
     RECT  68.952 17.077 70.176 17.219 ;
     RECT  68.904 17.219 70.176 17.267 ;
     RECT  68.904 17.267 70.608 18.469 ;
     RECT  73.368 17.651 74.832 20.341 ;
     RECT  68.904 18.469 70.32 20.053 ;
     RECT  53.448 18.707 54.816 18.851 ;
     RECT  79.992 18.851 80.376 19.621 ;
     RECT  84.072 18.851 85.248 20.339 ;
     RECT  85.368 19.141 86.64 20.821 ;
     RECT  75.768 19.333 76.896 21.347 ;
     RECT  44.472 19.621 45.6 21.155 ;
     RECT  79.992 19.621 81.408 21.349 ;
     RECT  68.904 20.053 70.08 25.189 ;
     RECT  59.256 20.533 60.48 21.155 ;
     RECT  87.816 21.013 88.8 22.741 ;
     RECT  42.216 21.061 43.488 21.971 ;
     RECT  62.568 21.205 63.888 22.259 ;
     RECT  75.624 21.347 76.896 22.501 ;
     RECT  80.136 21.349 81.408 23.365 ;
     RECT  73.368 21.683 74.832 23.557 ;
     RECT  42.192 21.971 43.488 23.317 ;
     RECT  52.68 22.741 53.952 23.315 ;
     RECT  85.896 23.219 87.024 24.469 ;
     RECT  58.392 23.269 59.856 23.891 ;
     RECT  59.88 23.269 61.008 25.813 ;
     RECT  42.12 23.317 43.488 24.083 ;
     RECT  46.68 23.317 47.76 24.899 ;
     RECT  73.368 23.557 74.4 24.085 ;
     RECT  89.448 23.557 90.576 24.083 ;
     RECT  75.624 23.603 76.896 24.613 ;
     RECT  44.472 23.653 45.6 25.955 ;
     RECT  81.432 23.653 82.8 25.139 ;
     RECT  58.344 23.891 59.856 25.955 ;
     RECT  79.992 24.035 81.408 26.197 ;
     RECT  73.128 24.179 74.304 24.995 ;
     RECT  47.784 24.419 48.912 24.899 ;
     RECT  75.624 24.613 76.752 27.061 ;
     RECT  46.68 24.899 48.912 25.045 ;
     RECT  73.128 24.995 74.496 25.285 ;
     RECT  47.304 25.045 48.912 26.149 ;
     RECT  81.432 25.139 82.896 27.971 ;
     RECT  85.896 25.139 87.072 26.291 ;
     RECT  69.096 25.189 70.08 27.827 ;
     RECT  73.272 25.285 74.496 25.571 ;
     RECT  53.64 25.477 54.816 26.629 ;
     RECT  83.832 25.477 85.248 25.621 ;
     RECT  84.216 25.621 85.248 27.301 ;
     RECT  43.512 25.955 45.6 26.437 ;
     RECT  62.112 26.101 63.552 26.819 ;
     RECT  47.304 26.149 48.528 26.819 ;
     RECT  40.512 26.245 41.616 28.405 ;
     RECT  85.896 26.291 87.792 26.533 ;
     RECT  43.512 26.437 44.64 26.483 ;
     RECT  86.424 26.533 87.792 27.301 ;
     RECT  62.112 26.819 63.984 27.635 ;
     RECT  75.624 27.061 76.704 28.643 ;
     RECT  51.312 27.395 52.56 27.731 ;
     RECT  79.992 27.587 80.976 34.165 ;
     RECT  62.112 27.635 64.128 27.829 ;
     RECT  51.312 27.731 52.656 39.395 ;
     RECT  91.224 27.733 92.592 29.315 ;
     RECT  69 27.827 70.08 31.381 ;
     RECT  63.096 27.829 64.128 29.123 ;
     RECT  81.432 27.971 81.528 28.405 ;
     RECT  75.624 28.643 76.752 33.683 ;
     RECT  84.216 29.267 85.248 31.907 ;
     RECT  58.44 29.365 59.904 29.605 ;
     RECT  58.728 29.605 59.904 29.651 ;
     RECT  58.728 29.651 60.576 30.037 ;
     RECT  59.064 30.037 60.576 34.259 ;
     RECT  46.68 30.803 46.776 31.861 ;
     RECT  44.184 31.331 45.6 34.165 ;
     RECT  62.808 31.763 64.128 34.355 ;
     RECT  43.872 31.907 44.16 32.149 ;
     RECT  84.216 31.907 85.344 34.597 ;
     RECT  42.792 32.149 44.16 32.819 ;
     RECT  42.768 32.819 44.16 32.869 ;
     RECT  42.768 32.869 43.92 33.733 ;
     RECT  94.632 33.061 96.144 34.259 ;
     RECT  64.392 33.107 65.424 34.835 ;
     RECT  86.376 33.107 87.552 34.115 ;
     RECT  94.08 33.107 94.2 33.541 ;
     RECT  92.904 33.541 94.2 34.115 ;
     RECT  75.624 33.683 77.088 35.317 ;
     RECT  41.064 33.733 42.528 34.645 ;
     RECT  42.552 33.733 43.92 33.781 ;
     RECT  42.552 33.781 43.776 33.923 ;
     RECT  81.432 33.877 82.896 36.467 ;
     RECT  42.552 33.923 44.16 34.741 ;
     RECT  89.304 34.117 90.336 35.219 ;
     RECT  90.36 34.117 91.872 35.173 ;
     RECT  44.472 34.165 45.6 34.835 ;
     RECT  58.68 34.259 60.576 35.269 ;
     RECT  62.112 34.355 64.128 35.317 ;
     RECT  41.064 34.645 42.336 36.275 ;
     RECT  42.744 34.741 44.16 35.413 ;
     RECT  44.184 34.835 45.6 35.459 ;
     RECT  64.392 34.835 65.52 39.109 ;
     RECT  58.68 35.269 59.664 36.515 ;
     RECT  62.112 35.317 63.264 35.939 ;
     RECT  42.744 35.413 43.92 35.557 ;
     RECT  84.216 35.507 85.344 37.525 ;
     RECT  79.992 35.699 80.976 36.661 ;
     RECT  75.624 35.987 77.088 38.677 ;
     RECT  58.68 36.515 60.576 37.861 ;
     RECT  65.544 36.515 66.528 37.909 ;
     RECT  89.208 36.515 89.304 37.525 ;
     RECT  46.68 36.613 47.664 38.099 ;
     RECT  47.688 36.613 48.912 36.997 ;
     RECT  92.616 36.661 94.08 37.667 ;
     RECT  42.6 37.091 43.92 38.101 ;
     RECT  52.68 37.091 54.288 38.197 ;
     RECT  86.136 37.331 87.552 39.779 ;
     RECT  79.992 37.379 80.976 39.253 ;
     RECT  62.112 37.477 63.408 39.061 ;
     RECT  59.352 37.861 60.576 38.435 ;
     RECT  46.68 38.099 48 39.205 ;
     RECT  42.936 38.101 43.92 40.595 ;
     RECT  40.512 38.149 41.76 39.251 ;
     RECT  52.824 38.197 54.288 38.387 ;
     RECT  58.68 38.435 60.576 38.819 ;
     RECT  84.216 38.675 85.344 39.827 ;
     RECT  75.624 38.677 76.704 42.803 ;
     RECT  43.944 38.723 43.992 39.493 ;
     RECT  58.44 38.819 60.576 39.781 ;
     RECT  62.112 39.061 63.264 40.837 ;
     RECT  64.392 39.109 65.376 39.971 ;
     RECT  51.312 39.395 52.8 41.221 ;
     RECT  65.544 39.491 66.624 44.437 ;
     RECT  43.944 39.493 45.36 40.645 ;
     RECT  86.04 39.779 87.552 41.651 ;
     RECT  58.44 39.781 59.808 40.499 ;
     RECT  64.392 39.971 65.52 41.029 ;
     RECT  52.824 39.973 54.192 40.211 ;
     RECT  47.352 40.067 48.912 41.125 ;
     RECT  52.824 40.211 55.104 40.837 ;
     RECT  58.44 40.499 60.576 41.557 ;
     RECT  60.6 40.499 61.632 42.803 ;
     RECT  72.912 40.501 74.16 40.979 ;
     RECT  42.744 40.595 43.92 40.691 ;
     RECT  43.944 40.645 44.976 40.835 ;
     RECT  44.4 40.835 44.976 41.989 ;
     RECT  52.92 40.837 55.104 41.075 ;
     RECT  62.76 40.883 64.128 41.603 ;
     RECT  72.912 40.979 74.832 42.133 ;
     RECT  64.392 41.029 65.376 41.267 ;
     RECT  52.92 41.075 55.2 41.077 ;
     RECT  52.92 41.077 54.048 41.219 ;
     RECT  54.072 41.077 55.2 41.219 ;
     RECT  79.992 41.123 80.976 42.709 ;
     RECT  47.4 41.125 48.912 41.653 ;
     RECT  52.92 41.219 53.4 42.133 ;
     RECT  51.312 41.221 52.32 41.507 ;
     RECT  64.392 41.267 65.52 45.157 ;
     RECT  58.44 41.557 59.808 42.851 ;
     RECT  47.496 41.653 48.912 41.795 ;
     RECT  47.352 41.795 48.912 42.133 ;
     RECT  47.352 42.133 48.624 43.573 ;
     RECT  53.016 42.133 53.4 42.421 ;
     RECT  72.912 42.133 74.112 42.949 ;
     RECT  53.208 42.755 53.4 43.861 ;
     RECT  60.6 42.803 61.8 46.213 ;
     RECT  75.624 42.803 76.896 43.909 ;
     RECT  58.44 42.851 59.952 44.051 ;
     RECT  79.992 42.899 80.976 50.245 ;
     RECT  73.032 42.949 74.112 43.283 ;
     RECT  89.496 43.043 90.264 44.339 ;
     RECT  91.896 43.043 91.944 43.909 ;
     RECT  73.032 43.283 74.832 43.813 ;
     RECT  47.4 43.573 48.624 43.955 ;
     RECT  73.56 43.813 74.832 45.731 ;
     RECT  75.864 43.909 76.896 45.635 ;
     RECT  91.896 43.909 93.408 46.259 ;
     RECT  47.4 43.955 48.912 45.299 ;
     RECT  89.448 44.339 90.264 44.341 ;
     RECT  89.448 44.341 90.624 45.155 ;
     RECT  90.648 44.341 91.872 44.581 ;
     RECT  54.072 44.773 55.488 45.875 ;
     RECT  90.648 45.011 91.872 45.155 ;
     RECT  81.432 45.013 82.752 45.539 ;
     RECT  62.52 45.155 63.744 45.635 ;
     RECT  65.112 45.203 66.144 46.981 ;
     RECT  50.688 45.539 51 45.541 ;
     RECT  48.936 45.541 49.968 46.211 ;
     RECT  49.992 45.541 51 46.211 ;
     RECT  75.768 45.635 76.896 46.741 ;
     RECT  59.304 46.069 60.576 46.787 ;
     RECT  84.792 46.117 85.872 47.555 ;
     RECT  60.6 46.213 61.68 47.939 ;
     RECT  91.896 46.259 94.2 46.645 ;
     RECT  91.896 46.645 93.024 47.363 ;
     RECT  93.048 46.645 94.2 47.891 ;
     RECT  73.464 47.269 74.832 47.459 ;
     RECT  92.352 47.363 93.024 47.845 ;
     RECT  65.112 47.411 66.528 48.563 ;
     RECT  53.736 47.461 55.248 47.939 ;
     RECT  84.216 47.555 85.872 48.901 ;
     RECT  60.6 47.939 61.8 51.061 ;
     RECT  81.432 48.229 82.656 49.331 ;
     RECT  58.44 48.325 59.664 48.611 ;
     RECT  65.112 48.563 66.624 50.389 ;
     RECT  58.44 48.611 60.576 49.429 ;
     RECT  62.52 48.901 63.648 48.949 ;
     RECT  84.648 48.901 85.872 49.091 ;
     RECT  75.624 48.995 77.04 51.637 ;
     RECT  62.232 49.043 63.216 49.427 ;
     RECT  73.512 49.141 74.832 50.195 ;
     RECT  59.112 49.429 60.576 50.003 ;
     RECT  55.44 49.619 55.488 50.965 ;
     RECT  83.184 49.667 83.28 50.773 ;
     RECT  58.488 50.003 60.576 50.677 ;
     RECT  65.304 50.389 66.624 51.395 ;
     RECT  92.904 50.581 94.2 50.723 ;
     RECT  58.488 50.677 59.76 50.867 ;
     RECT  86.232 50.821 87.456 51.493 ;
     RECT  58.44 50.867 59.76 52.403 ;
     RECT  60.6 51.061 61.584 51.251 ;
     RECT  60.6 51.251 61.68 74.051 ;
     RECT  79.992 51.347 80.976 77.555 ;
     RECT  64.968 51.395 66.624 51.923 ;
     RECT  75.672 51.637 77.04 51.971 ;
     RECT  66.432 51.923 66.624 52.645 ;
     RECT  75.672 51.971 77.088 52.499 ;
     RECT  73.368 52.453 74.832 53.219 ;
     RECT  75.624 52.499 77.088 74.965 ;
     RECT  85.896 58.117 87.36 72.179 ;
     RECT  60.6 74.051 61.8 76.309 ;
     RECT  49.464 74.629 50.544 76.309 ;
     RECT  59.112 74.629 60.576 75.205 ;
     RECT  62.112 74.629 63.552 79.045 ;
     RECT  55.296 74.867 55.44 76.357 ;
     RECT  75.624 74.965 76.896 75.157 ;
     RECT  75.912 75.157 76.896 75.395 ;
     RECT  65.448 75.253 66.624 75.541 ;
     RECT  75.912 75.395 77.088 78.037 ;
     RECT  51.312 75.637 52.752 78.805 ;
     RECT  74.856 75.875 75.888 76.403 ;
     RECT  60.648 76.309 61.8 76.741 ;
     RECT  53.544 76.357 54.72 78.661 ;
     RECT  84.84 76.357 85.872 77.509 ;
     RECT  89.688 76.357 90.816 76.885 ;
     RECT  57.144 76.451 58.416 78.661 ;
     RECT  81.672 76.933 83.136 79.189 ;
     RECT  49.464 76.979 50.544 79.045 ;
     RECT  78.504 76.979 79.488 78.085 ;
     RECT  84.888 77.509 85.872 77.603 ;
     RECT  79.896 77.555 80.976 78.131 ;
     RECT  64.056 77.603 65.424 78.661 ;
     RECT  84.888 77.603 86.688 78.709 ;
     RECT  89.688 78.083 90.816 80.389 ;
     RECT  79.848 78.131 80.976 79.283 ;
     RECT  76.152 78.179 77.184 80.149 ;
     RECT  57.288 78.661 58.416 78.707 ;
     RECT  64.056 78.661 65.232 78.757 ;
     RECT  57.288 78.707 57.336 79.765 ;
     RECT  84.888 78.709 86.256 79.237 ;
     RECT  64.056 78.757 65.184 78.805 ;
     RECT  51.312 78.805 52.56 80.341 ;
     RECT  74.808 79.189 75.888 79.621 ;
     RECT  81.672 79.189 82.992 79.765 ;
     RECT  79.848 79.283 81.408 79.859 ;
     RECT  81.72 79.765 82.992 80.197 ;
     RECT  79.848 79.859 81.552 80.389 ;
     RECT  81.72 80.197 82.944 80.245 ;
     RECT  80.376 80.389 81.552 80.917 ;
     RECT  57.336 80.485 58.848 80.677 ;
     RECT  86.28 82.115 87.264 82.595 ;
     RECT  84.168 82.547 85.296 82.739 ;
     RECT  86.28 82.595 87.648 83.749 ;
     RECT  80.376 82.691 81.504 83.653 ;
     RECT  83.712 82.739 85.296 83.557 ;
     RECT  83.712 83.557 84.96 83.749 ;
     RECT  86.28 83.749 87.264 83.797 ;
  END
END ot_s81_svc_probability_frame
END LIBRARY
